VERSION 5.8 ;
BUSBITCHARS "[]" ;
DIVIDERCHAR "/" ;
UNITS
    DATABASE MICRONS 1000 ;
END UNITS

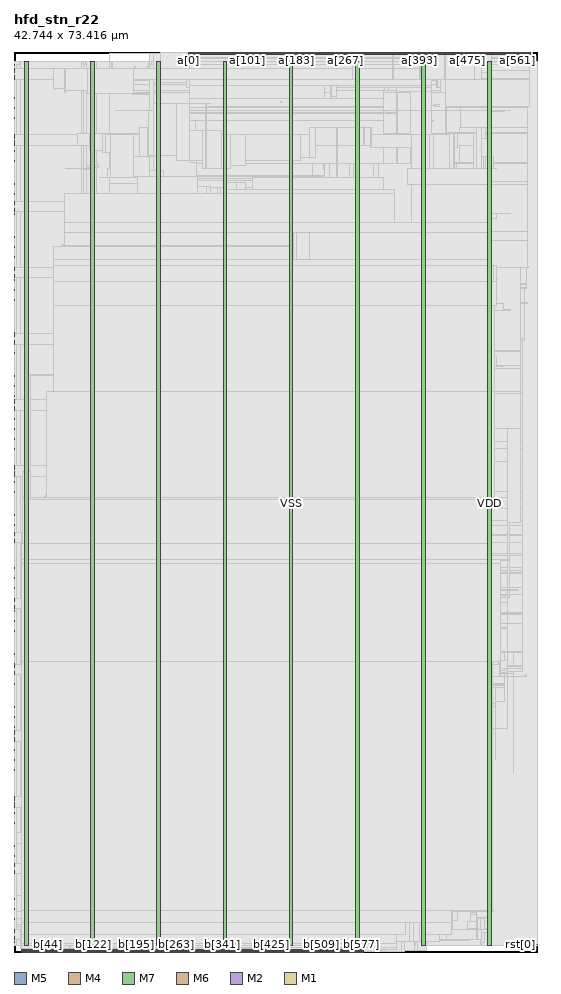
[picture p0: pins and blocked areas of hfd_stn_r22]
MACRO hfd_stn_r22
  FOREIGN hfd_stn_r22 0 0 ;
  CLASS BLOCK ;
  SIZE 42.744 BY 73.416 ;
  PIN a[0]
    DIRECTION INPUT ;
    USE SIGNAL ;
    PORT
      LAYER M5 ;
        RECT  14.208 73.224 14.232 73.416 ;
    END
  END a[0]
  PIN a[100]
    DIRECTION INPUT ;
    USE SIGNAL ;
    PORT
      LAYER M5 ;
        RECT  19.008 73.224 19.032 73.416 ;
    END
  END a[100]
  PIN a[101]
    DIRECTION INPUT ;
    USE SIGNAL ;
    PORT
      LAYER M5 ;
        RECT  19.056 73.224 19.08 73.416 ;
    END
  END a[101]
  PIN a[102]
    DIRECTION INPUT ;
    USE SIGNAL ;
    PORT
      LAYER M5 ;
        RECT  19.104 73.224 19.128 73.416 ;
    END
  END a[102]
  PIN a[103]
    DIRECTION INPUT ;
    USE SIGNAL ;
    PORT
      LAYER M5 ;
        RECT  19.152 73.224 19.176 73.416 ;
    END
  END a[103]
  PIN a[104]
    DIRECTION INPUT ;
    USE SIGNAL ;
    PORT
      LAYER M5 ;
        RECT  19.2 73.224 19.224 73.416 ;
    END
  END a[104]
  PIN a[105]
    DIRECTION INPUT ;
    USE SIGNAL ;
    PORT
      LAYER M5 ;
        RECT  19.248 73.224 19.272 73.416 ;
    END
  END a[105]
  PIN a[106]
    DIRECTION INPUT ;
    USE SIGNAL ;
    PORT
      LAYER M5 ;
        RECT  19.296 73.224 19.32 73.416 ;
    END
  END a[106]
  PIN a[107]
    DIRECTION INPUT ;
    USE SIGNAL ;
    PORT
      LAYER M5 ;
        RECT  19.344 73.224 19.368 73.416 ;
    END
  END a[107]
  PIN a[108]
    DIRECTION INPUT ;
    USE SIGNAL ;
    PORT
      LAYER M5 ;
        RECT  19.392 73.224 19.416 73.416 ;
    END
  END a[108]
  PIN a[109]
    DIRECTION INPUT ;
    USE SIGNAL ;
    PORT
      LAYER M5 ;
        RECT  19.44 73.224 19.464 73.416 ;
    END
  END a[109]
  PIN a[10]
    DIRECTION INPUT ;
    USE SIGNAL ;
    PORT
      LAYER M5 ;
        RECT  14.688 73.224 14.712 73.416 ;
    END
  END a[10]
  PIN a[110]
    DIRECTION INPUT ;
    USE SIGNAL ;
    PORT
      LAYER M5 ;
        RECT  19.488 73.224 19.512 73.416 ;
    END
  END a[110]
  PIN a[111]
    DIRECTION INPUT ;
    USE SIGNAL ;
    PORT
      LAYER M5 ;
        RECT  19.536 73.224 19.56 73.416 ;
    END
  END a[111]
  PIN a[112]
    DIRECTION INPUT ;
    USE SIGNAL ;
    PORT
      LAYER M5 ;
        RECT  19.584 73.224 19.608 73.416 ;
    END
  END a[112]
  PIN a[113]
    DIRECTION INPUT ;
    USE SIGNAL ;
    PORT
      LAYER M5 ;
        RECT  19.632 73.224 19.656 73.416 ;
    END
  END a[113]
  PIN a[114]
    DIRECTION INPUT ;
    USE SIGNAL ;
    PORT
      LAYER M5 ;
        RECT  19.68 73.224 19.704 73.416 ;
    END
  END a[114]
  PIN a[115]
    DIRECTION INPUT ;
    USE SIGNAL ;
    PORT
      LAYER M5 ;
        RECT  19.728 73.224 19.752 73.416 ;
    END
  END a[115]
  PIN a[116]
    DIRECTION INPUT ;
    USE SIGNAL ;
    PORT
      LAYER M5 ;
        RECT  19.776 73.224 19.8 73.416 ;
    END
  END a[116]
  PIN a[117]
    DIRECTION INPUT ;
    USE SIGNAL ;
    PORT
      LAYER M5 ;
        RECT  19.824 73.224 19.848 73.416 ;
    END
  END a[117]
  PIN a[118]
    DIRECTION INPUT ;
    USE SIGNAL ;
    PORT
      LAYER M5 ;
        RECT  19.872 73.224 19.896 73.416 ;
    END
  END a[118]
  PIN a[119]
    DIRECTION INPUT ;
    USE SIGNAL ;
    PORT
      LAYER M5 ;
        RECT  19.92 73.224 19.944 73.416 ;
    END
  END a[119]
  PIN a[11]
    DIRECTION INPUT ;
    USE SIGNAL ;
    PORT
      LAYER M5 ;
        RECT  14.736 73.224 14.76 73.416 ;
    END
  END a[11]
  PIN a[120]
    DIRECTION INPUT ;
    USE SIGNAL ;
    PORT
      LAYER M5 ;
        RECT  19.968 73.224 19.992 73.416 ;
    END
  END a[120]
  PIN a[121]
    DIRECTION INPUT ;
    USE SIGNAL ;
    PORT
      LAYER M5 ;
        RECT  20.016 73.224 20.04 73.416 ;
    END
  END a[121]
  PIN a[122]
    DIRECTION INPUT ;
    USE SIGNAL ;
    PORT
      LAYER M5 ;
        RECT  20.064 73.224 20.088 73.416 ;
    END
  END a[122]
  PIN a[123]
    DIRECTION INPUT ;
    USE SIGNAL ;
    PORT
      LAYER M5 ;
        RECT  20.112 73.224 20.136 73.416 ;
    END
  END a[123]
  PIN a[124]
    DIRECTION INPUT ;
    USE SIGNAL ;
    PORT
      LAYER M5 ;
        RECT  20.16 73.224 20.184 73.416 ;
    END
  END a[124]
  PIN a[125]
    DIRECTION INPUT ;
    USE SIGNAL ;
    PORT
      LAYER M5 ;
        RECT  20.208 73.224 20.232 73.416 ;
    END
  END a[125]
  PIN a[126]
    DIRECTION INPUT ;
    USE SIGNAL ;
    PORT
      LAYER M5 ;
        RECT  20.256 73.224 20.28 73.416 ;
    END
  END a[126]
  PIN a[127]
    DIRECTION INPUT ;
    USE SIGNAL ;
    PORT
      LAYER M5 ;
        RECT  20.304 73.224 20.328 73.416 ;
    END
  END a[127]
  PIN a[128]
    DIRECTION INPUT ;
    USE SIGNAL ;
    PORT
      LAYER M5 ;
        RECT  20.352 73.224 20.376 73.416 ;
    END
  END a[128]
  PIN a[129]
    DIRECTION INPUT ;
    USE SIGNAL ;
    PORT
      LAYER M5 ;
        RECT  20.4 73.224 20.424 73.416 ;
    END
  END a[129]
  PIN a[12]
    DIRECTION INPUT ;
    USE SIGNAL ;
    PORT
      LAYER M5 ;
        RECT  14.784 73.224 14.808 73.416 ;
    END
  END a[12]
  PIN a[130]
    DIRECTION INPUT ;
    USE SIGNAL ;
    PORT
      LAYER M5 ;
        RECT  20.448 73.224 20.472 73.416 ;
    END
  END a[130]
  PIN a[131]
    DIRECTION INPUT ;
    USE SIGNAL ;
    PORT
      LAYER M5 ;
        RECT  20.496 73.224 20.52 73.416 ;
    END
  END a[131]
  PIN a[132]
    DIRECTION INPUT ;
    USE SIGNAL ;
    PORT
      LAYER M5 ;
        RECT  20.544 73.224 20.568 73.416 ;
    END
  END a[132]
  PIN a[133]
    DIRECTION INPUT ;
    USE SIGNAL ;
    PORT
      LAYER M5 ;
        RECT  20.592 73.224 20.616 73.416 ;
    END
  END a[133]
  PIN a[134]
    DIRECTION INPUT ;
    USE SIGNAL ;
    PORT
      LAYER M5 ;
        RECT  20.64 73.224 20.664 73.416 ;
    END
  END a[134]
  PIN a[135]
    DIRECTION INPUT ;
    USE SIGNAL ;
    PORT
      LAYER M5 ;
        RECT  20.688 73.224 20.712 73.416 ;
    END
  END a[135]
  PIN a[136]
    DIRECTION INPUT ;
    USE SIGNAL ;
    PORT
      LAYER M5 ;
        RECT  20.736 73.224 20.76 73.416 ;
    END
  END a[136]
  PIN a[137]
    DIRECTION INPUT ;
    USE SIGNAL ;
    PORT
      LAYER M5 ;
        RECT  20.784 73.224 20.808 73.416 ;
    END
  END a[137]
  PIN a[138]
    DIRECTION INPUT ;
    USE SIGNAL ;
    PORT
      LAYER M5 ;
        RECT  20.832 73.224 20.856 73.416 ;
    END
  END a[138]
  PIN a[139]
    DIRECTION INPUT ;
    USE SIGNAL ;
    PORT
      LAYER M5 ;
        RECT  20.88 73.224 20.904 73.416 ;
    END
  END a[139]
  PIN a[13]
    DIRECTION INPUT ;
    USE SIGNAL ;
    PORT
      LAYER M5 ;
        RECT  14.832 73.224 14.856 73.416 ;
    END
  END a[13]
  PIN a[140]
    DIRECTION INPUT ;
    USE SIGNAL ;
    PORT
      LAYER M5 ;
        RECT  20.928 73.224 20.952 73.416 ;
    END
  END a[140]
  PIN a[141]
    DIRECTION INPUT ;
    USE SIGNAL ;
    PORT
      LAYER M5 ;
        RECT  20.976 73.224 21 73.416 ;
    END
  END a[141]
  PIN a[142]
    DIRECTION INPUT ;
    USE SIGNAL ;
    PORT
      LAYER M5 ;
        RECT  21.024 73.224 21.048 73.416 ;
    END
  END a[142]
  PIN a[143]
    DIRECTION INPUT ;
    USE SIGNAL ;
    PORT
      LAYER M5 ;
        RECT  21.072 73.224 21.096 73.416 ;
    END
  END a[143]
  PIN a[144]
    DIRECTION INPUT ;
    USE SIGNAL ;
    PORT
      LAYER M5 ;
        RECT  21.12 73.224 21.144 73.416 ;
    END
  END a[144]
  PIN a[145]
    DIRECTION INPUT ;
    USE SIGNAL ;
    PORT
      LAYER M5 ;
        RECT  21.168 73.224 21.192 73.416 ;
    END
  END a[145]
  PIN a[146]
    DIRECTION INPUT ;
    USE SIGNAL ;
    PORT
      LAYER M5 ;
        RECT  21.216 73.224 21.24 73.416 ;
    END
  END a[146]
  PIN a[147]
    DIRECTION INPUT ;
    USE SIGNAL ;
    PORT
      LAYER M5 ;
        RECT  21.264 73.224 21.288 73.416 ;
    END
  END a[147]
  PIN a[148]
    DIRECTION INPUT ;
    USE SIGNAL ;
    PORT
      LAYER M5 ;
        RECT  21.312 73.224 21.336 73.416 ;
    END
  END a[148]
  PIN a[149]
    DIRECTION INPUT ;
    USE SIGNAL ;
    PORT
      LAYER M5 ;
        RECT  21.36 73.224 21.384 73.416 ;
    END
  END a[149]
  PIN a[14]
    DIRECTION INPUT ;
    USE SIGNAL ;
    PORT
      LAYER M5 ;
        RECT  14.88 73.224 14.904 73.416 ;
    END
  END a[14]
  PIN a[150]
    DIRECTION INPUT ;
    USE SIGNAL ;
    PORT
      LAYER M5 ;
        RECT  21.408 73.224 21.432 73.416 ;
    END
  END a[150]
  PIN a[151]
    DIRECTION INPUT ;
    USE SIGNAL ;
    PORT
      LAYER M5 ;
        RECT  21.456 73.224 21.48 73.416 ;
    END
  END a[151]
  PIN a[152]
    DIRECTION INPUT ;
    USE SIGNAL ;
    PORT
      LAYER M5 ;
        RECT  21.504 73.224 21.528 73.416 ;
    END
  END a[152]
  PIN a[153]
    DIRECTION INPUT ;
    USE SIGNAL ;
    PORT
      LAYER M5 ;
        RECT  21.552 73.224 21.576 73.416 ;
    END
  END a[153]
  PIN a[154]
    DIRECTION INPUT ;
    USE SIGNAL ;
    PORT
      LAYER M5 ;
        RECT  21.6 73.224 21.624 73.416 ;
    END
  END a[154]
  PIN a[155]
    DIRECTION INPUT ;
    USE SIGNAL ;
    PORT
      LAYER M5 ;
        RECT  21.648 73.224 21.672 73.416 ;
    END
  END a[155]
  PIN a[156]
    DIRECTION INPUT ;
    USE SIGNAL ;
    PORT
      LAYER M5 ;
        RECT  21.696 73.224 21.72 73.416 ;
    END
  END a[156]
  PIN a[157]
    DIRECTION INPUT ;
    USE SIGNAL ;
    PORT
      LAYER M5 ;
        RECT  21.744 73.224 21.768 73.416 ;
    END
  END a[157]
  PIN a[158]
    DIRECTION INPUT ;
    USE SIGNAL ;
    PORT
      LAYER M5 ;
        RECT  21.792 73.224 21.816 73.416 ;
    END
  END a[158]
  PIN a[159]
    DIRECTION INPUT ;
    USE SIGNAL ;
    PORT
      LAYER M5 ;
        RECT  21.84 73.224 21.864 73.416 ;
    END
  END a[159]
  PIN a[15]
    DIRECTION INPUT ;
    USE SIGNAL ;
    PORT
      LAYER M5 ;
        RECT  14.928 73.224 14.952 73.416 ;
    END
  END a[15]
  PIN a[160]
    DIRECTION INPUT ;
    USE SIGNAL ;
    PORT
      LAYER M5 ;
        RECT  21.888 73.224 21.912 73.416 ;
    END
  END a[160]
  PIN a[161]
    DIRECTION INPUT ;
    USE SIGNAL ;
    PORT
      LAYER M5 ;
        RECT  21.936 73.224 21.96 73.416 ;
    END
  END a[161]
  PIN a[162]
    DIRECTION INPUT ;
    USE SIGNAL ;
    PORT
      LAYER M5 ;
        RECT  21.984 73.224 22.008 73.416 ;
    END
  END a[162]
  PIN a[163]
    DIRECTION INPUT ;
    USE SIGNAL ;
    PORT
      LAYER M5 ;
        RECT  22.032 73.224 22.056 73.416 ;
    END
  END a[163]
  PIN a[164]
    DIRECTION INPUT ;
    USE SIGNAL ;
    PORT
      LAYER M5 ;
        RECT  22.08 73.224 22.104 73.416 ;
    END
  END a[164]
  PIN a[165]
    DIRECTION INPUT ;
    USE SIGNAL ;
    PORT
      LAYER M5 ;
        RECT  22.128 73.224 22.152 73.416 ;
    END
  END a[165]
  PIN a[166]
    DIRECTION INPUT ;
    USE SIGNAL ;
    PORT
      LAYER M5 ;
        RECT  22.176 73.224 22.2 73.416 ;
    END
  END a[166]
  PIN a[167]
    DIRECTION INPUT ;
    USE SIGNAL ;
    PORT
      LAYER M5 ;
        RECT  22.224 73.224 22.248 73.416 ;
    END
  END a[167]
  PIN a[168]
    DIRECTION INPUT ;
    USE SIGNAL ;
    PORT
      LAYER M5 ;
        RECT  22.272 73.224 22.296 73.416 ;
    END
  END a[168]
  PIN a[169]
    DIRECTION INPUT ;
    USE SIGNAL ;
    PORT
      LAYER M5 ;
        RECT  22.32 73.224 22.344 73.416 ;
    END
  END a[169]
  PIN a[16]
    DIRECTION INPUT ;
    USE SIGNAL ;
    PORT
      LAYER M5 ;
        RECT  14.976 73.224 15 73.416 ;
    END
  END a[16]
  PIN a[170]
    DIRECTION INPUT ;
    USE SIGNAL ;
    PORT
      LAYER M5 ;
        RECT  22.368 73.224 22.392 73.416 ;
    END
  END a[170]
  PIN a[171]
    DIRECTION INPUT ;
    USE SIGNAL ;
    PORT
      LAYER M5 ;
        RECT  22.416 73.224 22.44 73.416 ;
    END
  END a[171]
  PIN a[172]
    DIRECTION INPUT ;
    USE SIGNAL ;
    PORT
      LAYER M5 ;
        RECT  22.464 73.224 22.488 73.416 ;
    END
  END a[172]
  PIN a[173]
    DIRECTION INPUT ;
    USE SIGNAL ;
    PORT
      LAYER M5 ;
        RECT  22.512 73.224 22.536 73.416 ;
    END
  END a[173]
  PIN a[174]
    DIRECTION INPUT ;
    USE SIGNAL ;
    PORT
      LAYER M5 ;
        RECT  22.56 73.224 22.584 73.416 ;
    END
  END a[174]
  PIN a[175]
    DIRECTION INPUT ;
    USE SIGNAL ;
    PORT
      LAYER M5 ;
        RECT  22.608 73.224 22.632 73.416 ;
    END
  END a[175]
  PIN a[176]
    DIRECTION INPUT ;
    USE SIGNAL ;
    PORT
      LAYER M5 ;
        RECT  22.656 73.224 22.68 73.416 ;
    END
  END a[176]
  PIN a[177]
    DIRECTION INPUT ;
    USE SIGNAL ;
    PORT
      LAYER M5 ;
        RECT  22.704 73.224 22.728 73.416 ;
    END
  END a[177]
  PIN a[178]
    DIRECTION INPUT ;
    USE SIGNAL ;
    PORT
      LAYER M5 ;
        RECT  22.752 73.224 22.776 73.416 ;
    END
  END a[178]
  PIN a[179]
    DIRECTION INPUT ;
    USE SIGNAL ;
    PORT
      LAYER M5 ;
        RECT  22.8 73.224 22.824 73.416 ;
    END
  END a[179]
  PIN a[17]
    DIRECTION INPUT ;
    USE SIGNAL ;
    PORT
      LAYER M5 ;
        RECT  15.024 73.224 15.048 73.416 ;
    END
  END a[17]
  PIN a[180]
    DIRECTION INPUT ;
    USE SIGNAL ;
    PORT
      LAYER M5 ;
        RECT  22.848 73.224 22.872 73.416 ;
    END
  END a[180]
  PIN a[181]
    DIRECTION INPUT ;
    USE SIGNAL ;
    PORT
      LAYER M5 ;
        RECT  22.896 73.224 22.92 73.416 ;
    END
  END a[181]
  PIN a[182]
    DIRECTION INPUT ;
    USE SIGNAL ;
    PORT
      LAYER M5 ;
        RECT  22.944 73.224 22.968 73.416 ;
    END
  END a[182]
  PIN a[183]
    DIRECTION INPUT ;
    USE SIGNAL ;
    PORT
      LAYER M5 ;
        RECT  22.992 73.224 23.016 73.416 ;
    END
  END a[183]
  PIN a[184]
    DIRECTION INPUT ;
    USE SIGNAL ;
    PORT
      LAYER M5 ;
        RECT  23.04 73.224 23.064 73.416 ;
    END
  END a[184]
  PIN a[185]
    DIRECTION INPUT ;
    USE SIGNAL ;
    PORT
      LAYER M5 ;
        RECT  23.088 73.224 23.112 73.416 ;
    END
  END a[185]
  PIN a[186]
    DIRECTION INPUT ;
    USE SIGNAL ;
    PORT
      LAYER M5 ;
        RECT  23.136 73.224 23.16 73.416 ;
    END
  END a[186]
  PIN a[187]
    DIRECTION INPUT ;
    USE SIGNAL ;
    PORT
      LAYER M5 ;
        RECT  23.184 73.224 23.208 73.416 ;
    END
  END a[187]
  PIN a[188]
    DIRECTION INPUT ;
    USE SIGNAL ;
    PORT
      LAYER M5 ;
        RECT  23.232 73.224 23.256 73.416 ;
    END
  END a[188]
  PIN a[189]
    DIRECTION INPUT ;
    USE SIGNAL ;
    PORT
      LAYER M5 ;
        RECT  23.28 73.224 23.304 73.416 ;
    END
  END a[189]
  PIN a[18]
    DIRECTION INPUT ;
    USE SIGNAL ;
    PORT
      LAYER M5 ;
        RECT  15.072 73.224 15.096 73.416 ;
    END
  END a[18]
  PIN a[190]
    DIRECTION INPUT ;
    USE SIGNAL ;
    PORT
      LAYER M5 ;
        RECT  23.328 73.224 23.352 73.416 ;
    END
  END a[190]
  PIN a[191]
    DIRECTION INPUT ;
    USE SIGNAL ;
    PORT
      LAYER M5 ;
        RECT  23.376 73.224 23.4 73.416 ;
    END
  END a[191]
  PIN a[192]
    DIRECTION INPUT ;
    USE SIGNAL ;
    PORT
      LAYER M5 ;
        RECT  23.424 73.224 23.448 73.416 ;
    END
  END a[192]
  PIN a[193]
    DIRECTION INPUT ;
    USE SIGNAL ;
    PORT
      LAYER M5 ;
        RECT  23.472 73.224 23.496 73.416 ;
    END
  END a[193]
  PIN a[194]
    DIRECTION INPUT ;
    USE SIGNAL ;
    PORT
      LAYER M5 ;
        RECT  23.52 73.224 23.544 73.416 ;
    END
  END a[194]
  PIN a[195]
    DIRECTION INPUT ;
    USE SIGNAL ;
    PORT
      LAYER M5 ;
        RECT  23.568 73.224 23.592 73.416 ;
    END
  END a[195]
  PIN a[196]
    DIRECTION INPUT ;
    USE SIGNAL ;
    PORT
      LAYER M5 ;
        RECT  23.616 73.224 23.64 73.416 ;
    END
  END a[196]
  PIN a[197]
    DIRECTION INPUT ;
    USE SIGNAL ;
    PORT
      LAYER M5 ;
        RECT  23.664 73.224 23.688 73.416 ;
    END
  END a[197]
  PIN a[198]
    DIRECTION INPUT ;
    USE SIGNAL ;
    PORT
      LAYER M5 ;
        RECT  23.712 73.224 23.736 73.416 ;
    END
  END a[198]
  PIN a[199]
    DIRECTION INPUT ;
    USE SIGNAL ;
    PORT
      LAYER M5 ;
        RECT  23.76 73.224 23.784 73.416 ;
    END
  END a[199]
  PIN a[19]
    DIRECTION INPUT ;
    USE SIGNAL ;
    PORT
      LAYER M5 ;
        RECT  15.12 73.224 15.144 73.416 ;
    END
  END a[19]
  PIN a[1]
    DIRECTION INPUT ;
    USE SIGNAL ;
    PORT
      LAYER M5 ;
        RECT  14.256 73.224 14.28 73.416 ;
    END
  END a[1]
  PIN a[200]
    DIRECTION INPUT ;
    USE SIGNAL ;
    PORT
      LAYER M5 ;
        RECT  23.808 73.224 23.832 73.416 ;
    END
  END a[200]
  PIN a[201]
    DIRECTION INPUT ;
    USE SIGNAL ;
    PORT
      LAYER M5 ;
        RECT  23.856 73.224 23.88 73.416 ;
    END
  END a[201]
  PIN a[202]
    DIRECTION INPUT ;
    USE SIGNAL ;
    PORT
      LAYER M5 ;
        RECT  23.904 73.224 23.928 73.416 ;
    END
  END a[202]
  PIN a[203]
    DIRECTION INPUT ;
    USE SIGNAL ;
    PORT
      LAYER M5 ;
        RECT  23.952 73.224 23.976 73.416 ;
    END
  END a[203]
  PIN a[204]
    DIRECTION INPUT ;
    USE SIGNAL ;
    PORT
      LAYER M5 ;
        RECT  24 73.224 24.024 73.416 ;
    END
  END a[204]
  PIN a[205]
    DIRECTION INPUT ;
    USE SIGNAL ;
    PORT
      LAYER M5 ;
        RECT  24.048 73.224 24.072 73.416 ;
    END
  END a[205]
  PIN a[206]
    DIRECTION INPUT ;
    USE SIGNAL ;
    PORT
      LAYER M5 ;
        RECT  24.096 73.224 24.12 73.416 ;
    END
  END a[206]
  PIN a[207]
    DIRECTION INPUT ;
    USE SIGNAL ;
    PORT
      LAYER M5 ;
        RECT  24.144 73.224 24.168 73.416 ;
    END
  END a[207]
  PIN a[208]
    DIRECTION INPUT ;
    USE SIGNAL ;
    PORT
      LAYER M5 ;
        RECT  24.192 73.224 24.216 73.416 ;
    END
  END a[208]
  PIN a[209]
    DIRECTION INPUT ;
    USE SIGNAL ;
    PORT
      LAYER M5 ;
        RECT  24.24 73.224 24.264 73.416 ;
    END
  END a[209]
  PIN a[20]
    DIRECTION INPUT ;
    USE SIGNAL ;
    PORT
      LAYER M5 ;
        RECT  15.168 73.224 15.192 73.416 ;
    END
  END a[20]
  PIN a[210]
    DIRECTION INPUT ;
    USE SIGNAL ;
    PORT
      LAYER M5 ;
        RECT  24.288 73.224 24.312 73.416 ;
    END
  END a[210]
  PIN a[211]
    DIRECTION INPUT ;
    USE SIGNAL ;
    PORT
      LAYER M5 ;
        RECT  24.336 73.224 24.36 73.416 ;
    END
  END a[211]
  PIN a[212]
    DIRECTION INPUT ;
    USE SIGNAL ;
    PORT
      LAYER M5 ;
        RECT  24.384 73.224 24.408 73.416 ;
    END
  END a[212]
  PIN a[213]
    DIRECTION INPUT ;
    USE SIGNAL ;
    PORT
      LAYER M5 ;
        RECT  24.432 73.224 24.456 73.416 ;
    END
  END a[213]
  PIN a[214]
    DIRECTION INPUT ;
    USE SIGNAL ;
    PORT
      LAYER M5 ;
        RECT  24.48 73.224 24.504 73.416 ;
    END
  END a[214]
  PIN a[215]
    DIRECTION INPUT ;
    USE SIGNAL ;
    PORT
      LAYER M5 ;
        RECT  24.528 73.224 24.552 73.416 ;
    END
  END a[215]
  PIN a[216]
    DIRECTION INPUT ;
    USE SIGNAL ;
    PORT
      LAYER M5 ;
        RECT  24.576 73.224 24.6 73.416 ;
    END
  END a[216]
  PIN a[217]
    DIRECTION INPUT ;
    USE SIGNAL ;
    PORT
      LAYER M5 ;
        RECT  24.624 73.224 24.648 73.416 ;
    END
  END a[217]
  PIN a[218]
    DIRECTION INPUT ;
    USE SIGNAL ;
    PORT
      LAYER M5 ;
        RECT  24.672 73.224 24.696 73.416 ;
    END
  END a[218]
  PIN a[219]
    DIRECTION INPUT ;
    USE SIGNAL ;
    PORT
      LAYER M5 ;
        RECT  24.72 73.224 24.744 73.416 ;
    END
  END a[219]
  PIN a[21]
    DIRECTION INPUT ;
    USE SIGNAL ;
    PORT
      LAYER M5 ;
        RECT  15.216 73.224 15.24 73.416 ;
    END
  END a[21]
  PIN a[220]
    DIRECTION INPUT ;
    USE SIGNAL ;
    PORT
      LAYER M5 ;
        RECT  24.768 73.224 24.792 73.416 ;
    END
  END a[220]
  PIN a[221]
    DIRECTION INPUT ;
    USE SIGNAL ;
    PORT
      LAYER M5 ;
        RECT  24.816 73.224 24.84 73.416 ;
    END
  END a[221]
  PIN a[222]
    DIRECTION INPUT ;
    USE SIGNAL ;
    PORT
      LAYER M5 ;
        RECT  24.864 73.224 24.888 73.416 ;
    END
  END a[222]
  PIN a[223]
    DIRECTION INPUT ;
    USE SIGNAL ;
    PORT
      LAYER M5 ;
        RECT  24.912 73.224 24.936 73.416 ;
    END
  END a[223]
  PIN a[224]
    DIRECTION INPUT ;
    USE SIGNAL ;
    PORT
      LAYER M5 ;
        RECT  24.96 73.224 24.984 73.416 ;
    END
  END a[224]
  PIN a[225]
    DIRECTION INPUT ;
    USE SIGNAL ;
    PORT
      LAYER M5 ;
        RECT  25.008 73.224 25.032 73.416 ;
    END
  END a[225]
  PIN a[226]
    DIRECTION INPUT ;
    USE SIGNAL ;
    PORT
      LAYER M5 ;
        RECT  25.056 73.224 25.08 73.416 ;
    END
  END a[226]
  PIN a[227]
    DIRECTION INPUT ;
    USE SIGNAL ;
    PORT
      LAYER M5 ;
        RECT  25.104 73.224 25.128 73.416 ;
    END
  END a[227]
  PIN a[228]
    DIRECTION INPUT ;
    USE SIGNAL ;
    PORT
      LAYER M5 ;
        RECT  25.152 73.224 25.176 73.416 ;
    END
  END a[228]
  PIN a[229]
    DIRECTION INPUT ;
    USE SIGNAL ;
    PORT
      LAYER M5 ;
        RECT  25.2 73.224 25.224 73.416 ;
    END
  END a[229]
  PIN a[22]
    DIRECTION INPUT ;
    USE SIGNAL ;
    PORT
      LAYER M5 ;
        RECT  15.264 73.224 15.288 73.416 ;
    END
  END a[22]
  PIN a[230]
    DIRECTION INPUT ;
    USE SIGNAL ;
    PORT
      LAYER M5 ;
        RECT  25.248 73.224 25.272 73.416 ;
    END
  END a[230]
  PIN a[231]
    DIRECTION INPUT ;
    USE SIGNAL ;
    PORT
      LAYER M5 ;
        RECT  25.296 73.224 25.32 73.416 ;
    END
  END a[231]
  PIN a[232]
    DIRECTION INPUT ;
    USE SIGNAL ;
    PORT
      LAYER M5 ;
        RECT  25.344 73.224 25.368 73.416 ;
    END
  END a[232]
  PIN a[233]
    DIRECTION INPUT ;
    USE SIGNAL ;
    PORT
      LAYER M5 ;
        RECT  25.392 73.224 25.416 73.416 ;
    END
  END a[233]
  PIN a[234]
    DIRECTION INPUT ;
    USE SIGNAL ;
    PORT
      LAYER M5 ;
        RECT  25.44 73.224 25.464 73.416 ;
    END
  END a[234]
  PIN a[235]
    DIRECTION INPUT ;
    USE SIGNAL ;
    PORT
      LAYER M5 ;
        RECT  25.488 73.224 25.512 73.416 ;
    END
  END a[235]
  PIN a[236]
    DIRECTION INPUT ;
    USE SIGNAL ;
    PORT
      LAYER M5 ;
        RECT  25.536 73.224 25.56 73.416 ;
    END
  END a[236]
  PIN a[237]
    DIRECTION INPUT ;
    USE SIGNAL ;
    PORT
      LAYER M5 ;
        RECT  25.584 73.224 25.608 73.416 ;
    END
  END a[237]
  PIN a[238]
    DIRECTION INPUT ;
    USE SIGNAL ;
    PORT
      LAYER M5 ;
        RECT  25.632 73.224 25.656 73.416 ;
    END
  END a[238]
  PIN a[239]
    DIRECTION INPUT ;
    USE SIGNAL ;
    PORT
      LAYER M5 ;
        RECT  25.68 73.224 25.704 73.416 ;
    END
  END a[239]
  PIN a[23]
    DIRECTION INPUT ;
    USE SIGNAL ;
    PORT
      LAYER M5 ;
        RECT  15.312 73.224 15.336 73.416 ;
    END
  END a[23]
  PIN a[240]
    DIRECTION INPUT ;
    USE SIGNAL ;
    PORT
      LAYER M5 ;
        RECT  25.728 73.224 25.752 73.416 ;
    END
  END a[240]
  PIN a[241]
    DIRECTION INPUT ;
    USE SIGNAL ;
    PORT
      LAYER M5 ;
        RECT  25.776 73.224 25.8 73.416 ;
    END
  END a[241]
  PIN a[242]
    DIRECTION INPUT ;
    USE SIGNAL ;
    PORT
      LAYER M5 ;
        RECT  25.824 73.224 25.848 73.416 ;
    END
  END a[242]
  PIN a[243]
    DIRECTION INPUT ;
    USE SIGNAL ;
    PORT
      LAYER M5 ;
        RECT  25.872 73.224 25.896 73.416 ;
    END
  END a[243]
  PIN a[244]
    DIRECTION INPUT ;
    USE SIGNAL ;
    PORT
      LAYER M5 ;
        RECT  25.92 73.224 25.944 73.416 ;
    END
  END a[244]
  PIN a[245]
    DIRECTION INPUT ;
    USE SIGNAL ;
    PORT
      LAYER M5 ;
        RECT  25.968 73.224 25.992 73.416 ;
    END
  END a[245]
  PIN a[246]
    DIRECTION INPUT ;
    USE SIGNAL ;
    PORT
      LAYER M5 ;
        RECT  26.016 73.224 26.04 73.416 ;
    END
  END a[246]
  PIN a[247]
    DIRECTION INPUT ;
    USE SIGNAL ;
    PORT
      LAYER M5 ;
        RECT  26.064 73.224 26.088 73.416 ;
    END
  END a[247]
  PIN a[248]
    DIRECTION INPUT ;
    USE SIGNAL ;
    PORT
      LAYER M5 ;
        RECT  26.112 73.224 26.136 73.416 ;
    END
  END a[248]
  PIN a[249]
    DIRECTION INPUT ;
    USE SIGNAL ;
    PORT
      LAYER M5 ;
        RECT  26.16 73.224 26.184 73.416 ;
    END
  END a[249]
  PIN a[24]
    DIRECTION INPUT ;
    USE SIGNAL ;
    PORT
      LAYER M5 ;
        RECT  15.36 73.224 15.384 73.416 ;
    END
  END a[24]
  PIN a[250]
    DIRECTION INPUT ;
    USE SIGNAL ;
    PORT
      LAYER M5 ;
        RECT  26.208 73.224 26.232 73.416 ;
    END
  END a[250]
  PIN a[251]
    DIRECTION INPUT ;
    USE SIGNAL ;
    PORT
      LAYER M5 ;
        RECT  26.256 73.224 26.28 73.416 ;
    END
  END a[251]
  PIN a[252]
    DIRECTION INPUT ;
    USE SIGNAL ;
    PORT
      LAYER M5 ;
        RECT  26.304 73.224 26.328 73.416 ;
    END
  END a[252]
  PIN a[253]
    DIRECTION INPUT ;
    USE SIGNAL ;
    PORT
      LAYER M5 ;
        RECT  26.352 73.224 26.376 73.416 ;
    END
  END a[253]
  PIN a[254]
    DIRECTION INPUT ;
    USE SIGNAL ;
    PORT
      LAYER M5 ;
        RECT  26.4 73.224 26.424 73.416 ;
    END
  END a[254]
  PIN a[255]
    DIRECTION INPUT ;
    USE SIGNAL ;
    PORT
      LAYER M5 ;
        RECT  26.448 73.224 26.472 73.416 ;
    END
  END a[255]
  PIN a[256]
    DIRECTION INPUT ;
    USE SIGNAL ;
    PORT
      LAYER M5 ;
        RECT  26.496 73.224 26.52 73.416 ;
    END
  END a[256]
  PIN a[257]
    DIRECTION INPUT ;
    USE SIGNAL ;
    PORT
      LAYER M5 ;
        RECT  26.544 73.224 26.568 73.416 ;
    END
  END a[257]
  PIN a[258]
    DIRECTION INPUT ;
    USE SIGNAL ;
    PORT
      LAYER M5 ;
        RECT  26.592 73.224 26.616 73.416 ;
    END
  END a[258]
  PIN a[259]
    DIRECTION INPUT ;
    USE SIGNAL ;
    PORT
      LAYER M5 ;
        RECT  26.64 73.224 26.664 73.416 ;
    END
  END a[259]
  PIN a[25]
    DIRECTION INPUT ;
    USE SIGNAL ;
    PORT
      LAYER M5 ;
        RECT  15.408 73.224 15.432 73.416 ;
    END
  END a[25]
  PIN a[260]
    DIRECTION INPUT ;
    USE SIGNAL ;
    PORT
      LAYER M5 ;
        RECT  26.688 73.224 26.712 73.416 ;
    END
  END a[260]
  PIN a[261]
    DIRECTION INPUT ;
    USE SIGNAL ;
    PORT
      LAYER M5 ;
        RECT  26.736 73.224 26.76 73.416 ;
    END
  END a[261]
  PIN a[262]
    DIRECTION INPUT ;
    USE SIGNAL ;
    PORT
      LAYER M5 ;
        RECT  26.784 73.224 26.808 73.416 ;
    END
  END a[262]
  PIN a[263]
    DIRECTION INPUT ;
    USE SIGNAL ;
    PORT
      LAYER M5 ;
        RECT  26.832 73.224 26.856 73.416 ;
    END
  END a[263]
  PIN a[264]
    DIRECTION INPUT ;
    USE SIGNAL ;
    PORT
      LAYER M5 ;
        RECT  26.88 73.224 26.904 73.416 ;
    END
  END a[264]
  PIN a[265]
    DIRECTION INPUT ;
    USE SIGNAL ;
    PORT
      LAYER M5 ;
        RECT  26.928 73.224 26.952 73.416 ;
    END
  END a[265]
  PIN a[266]
    DIRECTION INPUT ;
    USE SIGNAL ;
    PORT
      LAYER M5 ;
        RECT  26.976 73.224 27 73.416 ;
    END
  END a[266]
  PIN a[267]
    DIRECTION INPUT ;
    USE SIGNAL ;
    PORT
      LAYER M5 ;
        RECT  27.024 73.224 27.048 73.416 ;
    END
  END a[267]
  PIN a[268]
    DIRECTION INPUT ;
    USE SIGNAL ;
    PORT
      LAYER M5 ;
        RECT  27.072 73.224 27.096 73.416 ;
    END
  END a[268]
  PIN a[269]
    DIRECTION INPUT ;
    USE SIGNAL ;
    PORT
      LAYER M5 ;
        RECT  27.12 73.224 27.144 73.416 ;
    END
  END a[269]
  PIN a[26]
    DIRECTION INPUT ;
    USE SIGNAL ;
    PORT
      LAYER M5 ;
        RECT  15.456 73.224 15.48 73.416 ;
    END
  END a[26]
  PIN a[270]
    DIRECTION INPUT ;
    USE SIGNAL ;
    PORT
      LAYER M5 ;
        RECT  27.168 73.224 27.192 73.416 ;
    END
  END a[270]
  PIN a[271]
    DIRECTION INPUT ;
    USE SIGNAL ;
    PORT
      LAYER M5 ;
        RECT  27.216 73.224 27.24 73.416 ;
    END
  END a[271]
  PIN a[272]
    DIRECTION INPUT ;
    USE SIGNAL ;
    PORT
      LAYER M5 ;
        RECT  27.264 73.224 27.288 73.416 ;
    END
  END a[272]
  PIN a[273]
    DIRECTION INPUT ;
    USE SIGNAL ;
    PORT
      LAYER M5 ;
        RECT  27.312 73.224 27.336 73.416 ;
    END
  END a[273]
  PIN a[274]
    DIRECTION INPUT ;
    USE SIGNAL ;
    PORT
      LAYER M5 ;
        RECT  27.36 73.224 27.384 73.416 ;
    END
  END a[274]
  PIN a[275]
    DIRECTION INPUT ;
    USE SIGNAL ;
    PORT
      LAYER M5 ;
        RECT  27.408 73.224 27.432 73.416 ;
    END
  END a[275]
  PIN a[276]
    DIRECTION INPUT ;
    USE SIGNAL ;
    PORT
      LAYER M5 ;
        RECT  27.456 73.224 27.48 73.416 ;
    END
  END a[276]
  PIN a[277]
    DIRECTION INPUT ;
    USE SIGNAL ;
    PORT
      LAYER M5 ;
        RECT  27.504 73.224 27.528 73.416 ;
    END
  END a[277]
  PIN a[278]
    DIRECTION INPUT ;
    USE SIGNAL ;
    PORT
      LAYER M5 ;
        RECT  27.552 73.224 27.576 73.416 ;
    END
  END a[278]
  PIN a[279]
    DIRECTION INPUT ;
    USE SIGNAL ;
    PORT
      LAYER M5 ;
        RECT  27.6 73.224 27.624 73.416 ;
    END
  END a[279]
  PIN a[27]
    DIRECTION INPUT ;
    USE SIGNAL ;
    PORT
      LAYER M5 ;
        RECT  15.504 73.224 15.528 73.416 ;
    END
  END a[27]
  PIN a[280]
    DIRECTION INPUT ;
    USE SIGNAL ;
    PORT
      LAYER M5 ;
        RECT  27.648 73.224 27.672 73.416 ;
    END
  END a[280]
  PIN a[281]
    DIRECTION INPUT ;
    USE SIGNAL ;
    PORT
      LAYER M5 ;
        RECT  27.696 73.224 27.72 73.416 ;
    END
  END a[281]
  PIN a[282]
    DIRECTION INPUT ;
    USE SIGNAL ;
    PORT
      LAYER M5 ;
        RECT  27.744 73.224 27.768 73.416 ;
    END
  END a[282]
  PIN a[283]
    DIRECTION INPUT ;
    USE SIGNAL ;
    PORT
      LAYER M5 ;
        RECT  27.792 73.224 27.816 73.416 ;
    END
  END a[283]
  PIN a[284]
    DIRECTION INPUT ;
    USE SIGNAL ;
    PORT
      LAYER M5 ;
        RECT  27.84 73.224 27.864 73.416 ;
    END
  END a[284]
  PIN a[285]
    DIRECTION INPUT ;
    USE SIGNAL ;
    PORT
      LAYER M5 ;
        RECT  27.888 73.224 27.912 73.416 ;
    END
  END a[285]
  PIN a[286]
    DIRECTION INPUT ;
    USE SIGNAL ;
    PORT
      LAYER M5 ;
        RECT  27.936 73.224 27.96 73.416 ;
    END
  END a[286]
  PIN a[287]
    DIRECTION INPUT ;
    USE SIGNAL ;
    PORT
      LAYER M5 ;
        RECT  27.984 73.224 28.008 73.416 ;
    END
  END a[287]
  PIN a[288]
    DIRECTION INPUT ;
    USE SIGNAL ;
    PORT
      LAYER M5 ;
        RECT  28.032 73.224 28.056 73.416 ;
    END
  END a[288]
  PIN a[289]
    DIRECTION INPUT ;
    USE SIGNAL ;
    PORT
      LAYER M5 ;
        RECT  28.08 73.224 28.104 73.416 ;
    END
  END a[289]
  PIN a[28]
    DIRECTION INPUT ;
    USE SIGNAL ;
    PORT
      LAYER M5 ;
        RECT  15.552 73.224 15.576 73.416 ;
    END
  END a[28]
  PIN a[290]
    DIRECTION INPUT ;
    USE SIGNAL ;
    PORT
      LAYER M5 ;
        RECT  28.128 73.224 28.152 73.416 ;
    END
  END a[290]
  PIN a[291]
    DIRECTION INPUT ;
    USE SIGNAL ;
    PORT
      LAYER M5 ;
        RECT  28.176 73.224 28.2 73.416 ;
    END
  END a[291]
  PIN a[292]
    DIRECTION INPUT ;
    USE SIGNAL ;
    PORT
      LAYER M5 ;
        RECT  28.224 73.224 28.248 73.416 ;
    END
  END a[292]
  PIN a[293]
    DIRECTION INPUT ;
    USE SIGNAL ;
    PORT
      LAYER M5 ;
        RECT  28.272 73.224 28.296 73.416 ;
    END
  END a[293]
  PIN a[294]
    DIRECTION INPUT ;
    USE SIGNAL ;
    PORT
      LAYER M5 ;
        RECT  28.32 73.224 28.344 73.416 ;
    END
  END a[294]
  PIN a[295]
    DIRECTION INPUT ;
    USE SIGNAL ;
    PORT
      LAYER M5 ;
        RECT  28.368 73.224 28.392 73.416 ;
    END
  END a[295]
  PIN a[296]
    DIRECTION INPUT ;
    USE SIGNAL ;
    PORT
      LAYER M5 ;
        RECT  28.416 73.224 28.44 73.416 ;
    END
  END a[296]
  PIN a[297]
    DIRECTION INPUT ;
    USE SIGNAL ;
    PORT
      LAYER M5 ;
        RECT  28.464 73.224 28.488 73.416 ;
    END
  END a[297]
  PIN a[298]
    DIRECTION INPUT ;
    USE SIGNAL ;
    PORT
      LAYER M5 ;
        RECT  28.512 73.224 28.536 73.416 ;
    END
  END a[298]
  PIN a[299]
    DIRECTION INPUT ;
    USE SIGNAL ;
    PORT
      LAYER M5 ;
        RECT  28.56 73.224 28.584 73.416 ;
    END
  END a[299]
  PIN a[29]
    DIRECTION INPUT ;
    USE SIGNAL ;
    PORT
      LAYER M5 ;
        RECT  15.6 73.224 15.624 73.416 ;
    END
  END a[29]
  PIN a[2]
    DIRECTION INPUT ;
    USE SIGNAL ;
    PORT
      LAYER M5 ;
        RECT  14.304 73.224 14.328 73.416 ;
    END
  END a[2]
  PIN a[300]
    DIRECTION INPUT ;
    USE SIGNAL ;
    PORT
      LAYER M5 ;
        RECT  28.608 73.224 28.632 73.416 ;
    END
  END a[300]
  PIN a[301]
    DIRECTION INPUT ;
    USE SIGNAL ;
    PORT
      LAYER M5 ;
        RECT  28.656 73.224 28.68 73.416 ;
    END
  END a[301]
  PIN a[302]
    DIRECTION INPUT ;
    USE SIGNAL ;
    PORT
      LAYER M5 ;
        RECT  28.704 73.224 28.728 73.416 ;
    END
  END a[302]
  PIN a[303]
    DIRECTION INPUT ;
    USE SIGNAL ;
    PORT
      LAYER M5 ;
        RECT  28.752 73.224 28.776 73.416 ;
    END
  END a[303]
  PIN a[304]
    DIRECTION INPUT ;
    USE SIGNAL ;
    PORT
      LAYER M5 ;
        RECT  28.8 73.224 28.824 73.416 ;
    END
  END a[304]
  PIN a[305]
    DIRECTION INPUT ;
    USE SIGNAL ;
    PORT
      LAYER M5 ;
        RECT  28.848 73.224 28.872 73.416 ;
    END
  END a[305]
  PIN a[306]
    DIRECTION INPUT ;
    USE SIGNAL ;
    PORT
      LAYER M5 ;
        RECT  28.896 73.224 28.92 73.416 ;
    END
  END a[306]
  PIN a[307]
    DIRECTION INPUT ;
    USE SIGNAL ;
    PORT
      LAYER M5 ;
        RECT  28.944 73.224 28.968 73.416 ;
    END
  END a[307]
  PIN a[308]
    DIRECTION INPUT ;
    USE SIGNAL ;
    PORT
      LAYER M5 ;
        RECT  28.992 73.224 29.016 73.416 ;
    END
  END a[308]
  PIN a[309]
    DIRECTION INPUT ;
    USE SIGNAL ;
    PORT
      LAYER M5 ;
        RECT  29.04 73.224 29.064 73.416 ;
    END
  END a[309]
  PIN a[30]
    DIRECTION INPUT ;
    USE SIGNAL ;
    PORT
      LAYER M5 ;
        RECT  15.648 73.224 15.672 73.416 ;
    END
  END a[30]
  PIN a[310]
    DIRECTION INPUT ;
    USE SIGNAL ;
    PORT
      LAYER M5 ;
        RECT  29.088 73.224 29.112 73.416 ;
    END
  END a[310]
  PIN a[311]
    DIRECTION INPUT ;
    USE SIGNAL ;
    PORT
      LAYER M5 ;
        RECT  29.136 73.224 29.16 73.416 ;
    END
  END a[311]
  PIN a[312]
    DIRECTION INPUT ;
    USE SIGNAL ;
    PORT
      LAYER M5 ;
        RECT  29.184 73.224 29.208 73.416 ;
    END
  END a[312]
  PIN a[313]
    DIRECTION INPUT ;
    USE SIGNAL ;
    PORT
      LAYER M5 ;
        RECT  29.232 73.224 29.256 73.416 ;
    END
  END a[313]
  PIN a[314]
    DIRECTION INPUT ;
    USE SIGNAL ;
    PORT
      LAYER M5 ;
        RECT  29.28 73.224 29.304 73.416 ;
    END
  END a[314]
  PIN a[315]
    DIRECTION INPUT ;
    USE SIGNAL ;
    PORT
      LAYER M5 ;
        RECT  29.328 73.224 29.352 73.416 ;
    END
  END a[315]
  PIN a[316]
    DIRECTION INPUT ;
    USE SIGNAL ;
    PORT
      LAYER M5 ;
        RECT  29.376 73.224 29.4 73.416 ;
    END
  END a[316]
  PIN a[317]
    DIRECTION INPUT ;
    USE SIGNAL ;
    PORT
      LAYER M5 ;
        RECT  29.424 73.224 29.448 73.416 ;
    END
  END a[317]
  PIN a[318]
    DIRECTION INPUT ;
    USE SIGNAL ;
    PORT
      LAYER M5 ;
        RECT  29.472 73.224 29.496 73.416 ;
    END
  END a[318]
  PIN a[319]
    DIRECTION INPUT ;
    USE SIGNAL ;
    PORT
      LAYER M5 ;
        RECT  29.52 73.224 29.544 73.416 ;
    END
  END a[319]
  PIN a[31]
    DIRECTION INPUT ;
    USE SIGNAL ;
    PORT
      LAYER M5 ;
        RECT  15.696 73.224 15.72 73.416 ;
    END
  END a[31]
  PIN a[320]
    DIRECTION INPUT ;
    USE SIGNAL ;
    PORT
      LAYER M5 ;
        RECT  29.568 73.224 29.592 73.416 ;
    END
  END a[320]
  PIN a[321]
    DIRECTION INPUT ;
    USE SIGNAL ;
    PORT
      LAYER M5 ;
        RECT  29.616 73.224 29.64 73.416 ;
    END
  END a[321]
  PIN a[322]
    DIRECTION INPUT ;
    USE SIGNAL ;
    PORT
      LAYER M5 ;
        RECT  29.664 73.224 29.688 73.416 ;
    END
  END a[322]
  PIN a[323]
    DIRECTION INPUT ;
    USE SIGNAL ;
    PORT
      LAYER M5 ;
        RECT  29.712 73.224 29.736 73.416 ;
    END
  END a[323]
  PIN a[324]
    DIRECTION INPUT ;
    USE SIGNAL ;
    PORT
      LAYER M5 ;
        RECT  29.76 73.224 29.784 73.416 ;
    END
  END a[324]
  PIN a[325]
    DIRECTION INPUT ;
    USE SIGNAL ;
    PORT
      LAYER M5 ;
        RECT  29.808 73.224 29.832 73.416 ;
    END
  END a[325]
  PIN a[326]
    DIRECTION INPUT ;
    USE SIGNAL ;
    PORT
      LAYER M5 ;
        RECT  29.856 73.224 29.88 73.416 ;
    END
  END a[326]
  PIN a[327]
    DIRECTION INPUT ;
    USE SIGNAL ;
    PORT
      LAYER M5 ;
        RECT  29.904 73.224 29.928 73.416 ;
    END
  END a[327]
  PIN a[328]
    DIRECTION INPUT ;
    USE SIGNAL ;
    PORT
      LAYER M5 ;
        RECT  29.952 73.224 29.976 73.416 ;
    END
  END a[328]
  PIN a[329]
    DIRECTION INPUT ;
    USE SIGNAL ;
    PORT
      LAYER M5 ;
        RECT  30 73.224 30.024 73.416 ;
    END
  END a[329]
  PIN a[32]
    DIRECTION INPUT ;
    USE SIGNAL ;
    PORT
      LAYER M5 ;
        RECT  15.744 73.224 15.768 73.416 ;
    END
  END a[32]
  PIN a[330]
    DIRECTION INPUT ;
    USE SIGNAL ;
    PORT
      LAYER M5 ;
        RECT  30.048 73.224 30.072 73.416 ;
    END
  END a[330]
  PIN a[331]
    DIRECTION INPUT ;
    USE SIGNAL ;
    PORT
      LAYER M5 ;
        RECT  30.096 73.224 30.12 73.416 ;
    END
  END a[331]
  PIN a[332]
    DIRECTION INPUT ;
    USE SIGNAL ;
    PORT
      LAYER M5 ;
        RECT  30.144 73.224 30.168 73.416 ;
    END
  END a[332]
  PIN a[333]
    DIRECTION INPUT ;
    USE SIGNAL ;
    PORT
      LAYER M5 ;
        RECT  30.192 73.224 30.216 73.416 ;
    END
  END a[333]
  PIN a[334]
    DIRECTION INPUT ;
    USE SIGNAL ;
    PORT
      LAYER M5 ;
        RECT  30.24 73.224 30.264 73.416 ;
    END
  END a[334]
  PIN a[335]
    DIRECTION INPUT ;
    USE SIGNAL ;
    PORT
      LAYER M5 ;
        RECT  30.288 73.224 30.312 73.416 ;
    END
  END a[335]
  PIN a[336]
    DIRECTION INPUT ;
    USE SIGNAL ;
    PORT
      LAYER M5 ;
        RECT  30.336 73.224 30.36 73.416 ;
    END
  END a[336]
  PIN a[337]
    DIRECTION INPUT ;
    USE SIGNAL ;
    PORT
      LAYER M5 ;
        RECT  30.384 73.224 30.408 73.416 ;
    END
  END a[337]
  PIN a[338]
    DIRECTION INPUT ;
    USE SIGNAL ;
    PORT
      LAYER M5 ;
        RECT  30.432 73.224 30.456 73.416 ;
    END
  END a[338]
  PIN a[339]
    DIRECTION INPUT ;
    USE SIGNAL ;
    PORT
      LAYER M5 ;
        RECT  30.48 73.224 30.504 73.416 ;
    END
  END a[339]
  PIN a[33]
    DIRECTION INPUT ;
    USE SIGNAL ;
    PORT
      LAYER M5 ;
        RECT  15.792 73.224 15.816 73.416 ;
    END
  END a[33]
  PIN a[340]
    DIRECTION INPUT ;
    USE SIGNAL ;
    PORT
      LAYER M5 ;
        RECT  30.528 73.224 30.552 73.416 ;
    END
  END a[340]
  PIN a[341]
    DIRECTION INPUT ;
    USE SIGNAL ;
    PORT
      LAYER M5 ;
        RECT  30.576 73.224 30.6 73.416 ;
    END
  END a[341]
  PIN a[342]
    DIRECTION INPUT ;
    USE SIGNAL ;
    PORT
      LAYER M5 ;
        RECT  30.624 73.224 30.648 73.416 ;
    END
  END a[342]
  PIN a[343]
    DIRECTION INPUT ;
    USE SIGNAL ;
    PORT
      LAYER M5 ;
        RECT  30.672 73.224 30.696 73.416 ;
    END
  END a[343]
  PIN a[344]
    DIRECTION INPUT ;
    USE SIGNAL ;
    PORT
      LAYER M5 ;
        RECT  30.72 73.224 30.744 73.416 ;
    END
  END a[344]
  PIN a[345]
    DIRECTION INPUT ;
    USE SIGNAL ;
    PORT
      LAYER M5 ;
        RECT  30.768 73.224 30.792 73.416 ;
    END
  END a[345]
  PIN a[346]
    DIRECTION INPUT ;
    USE SIGNAL ;
    PORT
      LAYER M5 ;
        RECT  30.816 73.224 30.84 73.416 ;
    END
  END a[346]
  PIN a[347]
    DIRECTION INPUT ;
    USE SIGNAL ;
    PORT
      LAYER M5 ;
        RECT  30.864 73.224 30.888 73.416 ;
    END
  END a[347]
  PIN a[348]
    DIRECTION INPUT ;
    USE SIGNAL ;
    PORT
      LAYER M5 ;
        RECT  30.912 73.224 30.936 73.416 ;
    END
  END a[348]
  PIN a[349]
    DIRECTION INPUT ;
    USE SIGNAL ;
    PORT
      LAYER M5 ;
        RECT  30.96 73.224 30.984 73.416 ;
    END
  END a[349]
  PIN a[34]
    DIRECTION INPUT ;
    USE SIGNAL ;
    PORT
      LAYER M5 ;
        RECT  15.84 73.224 15.864 73.416 ;
    END
  END a[34]
  PIN a[350]
    DIRECTION INPUT ;
    USE SIGNAL ;
    PORT
      LAYER M5 ;
        RECT  31.008 73.224 31.032 73.416 ;
    END
  END a[350]
  PIN a[351]
    DIRECTION INPUT ;
    USE SIGNAL ;
    PORT
      LAYER M5 ;
        RECT  31.056 73.224 31.08 73.416 ;
    END
  END a[351]
  PIN a[352]
    DIRECTION INPUT ;
    USE SIGNAL ;
    PORT
      LAYER M5 ;
        RECT  31.104 73.224 31.128 73.416 ;
    END
  END a[352]
  PIN a[353]
    DIRECTION INPUT ;
    USE SIGNAL ;
    PORT
      LAYER M5 ;
        RECT  31.152 73.224 31.176 73.416 ;
    END
  END a[353]
  PIN a[354]
    DIRECTION INPUT ;
    USE SIGNAL ;
    PORT
      LAYER M5 ;
        RECT  31.2 73.224 31.224 73.416 ;
    END
  END a[354]
  PIN a[355]
    DIRECTION INPUT ;
    USE SIGNAL ;
    PORT
      LAYER M5 ;
        RECT  31.248 73.224 31.272 73.416 ;
    END
  END a[355]
  PIN a[356]
    DIRECTION INPUT ;
    USE SIGNAL ;
    PORT
      LAYER M5 ;
        RECT  31.296 73.224 31.32 73.416 ;
    END
  END a[356]
  PIN a[357]
    DIRECTION INPUT ;
    USE SIGNAL ;
    PORT
      LAYER M5 ;
        RECT  31.344 73.224 31.368 73.416 ;
    END
  END a[357]
  PIN a[358]
    DIRECTION INPUT ;
    USE SIGNAL ;
    PORT
      LAYER M5 ;
        RECT  31.392 73.224 31.416 73.416 ;
    END
  END a[358]
  PIN a[359]
    DIRECTION INPUT ;
    USE SIGNAL ;
    PORT
      LAYER M5 ;
        RECT  31.44 73.224 31.464 73.416 ;
    END
  END a[359]
  PIN a[35]
    DIRECTION INPUT ;
    USE SIGNAL ;
    PORT
      LAYER M5 ;
        RECT  15.888 73.224 15.912 73.416 ;
    END
  END a[35]
  PIN a[360]
    DIRECTION INPUT ;
    USE SIGNAL ;
    PORT
      LAYER M5 ;
        RECT  31.488 73.224 31.512 73.416 ;
    END
  END a[360]
  PIN a[361]
    DIRECTION INPUT ;
    USE SIGNAL ;
    PORT
      LAYER M5 ;
        RECT  31.536 73.224 31.56 73.416 ;
    END
  END a[361]
  PIN a[362]
    DIRECTION INPUT ;
    USE SIGNAL ;
    PORT
      LAYER M5 ;
        RECT  31.584 73.224 31.608 73.416 ;
    END
  END a[362]
  PIN a[363]
    DIRECTION INPUT ;
    USE SIGNAL ;
    PORT
      LAYER M5 ;
        RECT  31.632 73.224 31.656 73.416 ;
    END
  END a[363]
  PIN a[364]
    DIRECTION INPUT ;
    USE SIGNAL ;
    PORT
      LAYER M5 ;
        RECT  31.68 73.224 31.704 73.416 ;
    END
  END a[364]
  PIN a[365]
    DIRECTION INPUT ;
    USE SIGNAL ;
    PORT
      LAYER M5 ;
        RECT  31.728 73.224 31.752 73.416 ;
    END
  END a[365]
  PIN a[366]
    DIRECTION INPUT ;
    USE SIGNAL ;
    PORT
      LAYER M5 ;
        RECT  31.776 73.224 31.8 73.416 ;
    END
  END a[366]
  PIN a[367]
    DIRECTION INPUT ;
    USE SIGNAL ;
    PORT
      LAYER M5 ;
        RECT  31.824 73.224 31.848 73.416 ;
    END
  END a[367]
  PIN a[368]
    DIRECTION INPUT ;
    USE SIGNAL ;
    PORT
      LAYER M5 ;
        RECT  31.872 73.224 31.896 73.416 ;
    END
  END a[368]
  PIN a[369]
    DIRECTION INPUT ;
    USE SIGNAL ;
    PORT
      LAYER M5 ;
        RECT  31.92 73.224 31.944 73.416 ;
    END
  END a[369]
  PIN a[36]
    DIRECTION INPUT ;
    USE SIGNAL ;
    PORT
      LAYER M5 ;
        RECT  15.936 73.224 15.96 73.416 ;
    END
  END a[36]
  PIN a[370]
    DIRECTION INPUT ;
    USE SIGNAL ;
    PORT
      LAYER M5 ;
        RECT  31.968 73.224 31.992 73.416 ;
    END
  END a[370]
  PIN a[371]
    DIRECTION INPUT ;
    USE SIGNAL ;
    PORT
      LAYER M5 ;
        RECT  32.016 73.224 32.04 73.416 ;
    END
  END a[371]
  PIN a[372]
    DIRECTION INPUT ;
    USE SIGNAL ;
    PORT
      LAYER M5 ;
        RECT  32.064 73.224 32.088 73.416 ;
    END
  END a[372]
  PIN a[373]
    DIRECTION INPUT ;
    USE SIGNAL ;
    PORT
      LAYER M5 ;
        RECT  32.112 73.224 32.136 73.416 ;
    END
  END a[373]
  PIN a[374]
    DIRECTION INPUT ;
    USE SIGNAL ;
    PORT
      LAYER M5 ;
        RECT  32.16 73.224 32.184 73.416 ;
    END
  END a[374]
  PIN a[375]
    DIRECTION INPUT ;
    USE SIGNAL ;
    PORT
      LAYER M5 ;
        RECT  32.208 73.224 32.232 73.416 ;
    END
  END a[375]
  PIN a[376]
    DIRECTION INPUT ;
    USE SIGNAL ;
    PORT
      LAYER M5 ;
        RECT  32.256 73.224 32.28 73.416 ;
    END
  END a[376]
  PIN a[377]
    DIRECTION INPUT ;
    USE SIGNAL ;
    PORT
      LAYER M5 ;
        RECT  32.304 73.224 32.328 73.416 ;
    END
  END a[377]
  PIN a[378]
    DIRECTION INPUT ;
    USE SIGNAL ;
    PORT
      LAYER M5 ;
        RECT  32.352 73.224 32.376 73.416 ;
    END
  END a[378]
  PIN a[379]
    DIRECTION INPUT ;
    USE SIGNAL ;
    PORT
      LAYER M5 ;
        RECT  32.4 73.224 32.424 73.416 ;
    END
  END a[379]
  PIN a[37]
    DIRECTION INPUT ;
    USE SIGNAL ;
    PORT
      LAYER M5 ;
        RECT  15.984 73.224 16.008 73.416 ;
    END
  END a[37]
  PIN a[380]
    DIRECTION INPUT ;
    USE SIGNAL ;
    PORT
      LAYER M5 ;
        RECT  32.448 73.224 32.472 73.416 ;
    END
  END a[380]
  PIN a[381]
    DIRECTION INPUT ;
    USE SIGNAL ;
    PORT
      LAYER M5 ;
        RECT  32.496 73.224 32.52 73.416 ;
    END
  END a[381]
  PIN a[382]
    DIRECTION INPUT ;
    USE SIGNAL ;
    PORT
      LAYER M5 ;
        RECT  32.544 73.224 32.568 73.416 ;
    END
  END a[382]
  PIN a[383]
    DIRECTION INPUT ;
    USE SIGNAL ;
    PORT
      LAYER M5 ;
        RECT  32.592 73.224 32.616 73.416 ;
    END
  END a[383]
  PIN a[384]
    DIRECTION INPUT ;
    USE SIGNAL ;
    PORT
      LAYER M5 ;
        RECT  32.64 73.224 32.664 73.416 ;
    END
  END a[384]
  PIN a[385]
    DIRECTION INPUT ;
    USE SIGNAL ;
    PORT
      LAYER M5 ;
        RECT  32.688 73.224 32.712 73.416 ;
    END
  END a[385]
  PIN a[386]
    DIRECTION INPUT ;
    USE SIGNAL ;
    PORT
      LAYER M5 ;
        RECT  32.736 73.224 32.76 73.416 ;
    END
  END a[386]
  PIN a[387]
    DIRECTION INPUT ;
    USE SIGNAL ;
    PORT
      LAYER M5 ;
        RECT  32.784 73.224 32.808 73.416 ;
    END
  END a[387]
  PIN a[388]
    DIRECTION INPUT ;
    USE SIGNAL ;
    PORT
      LAYER M5 ;
        RECT  32.832 73.224 32.856 73.416 ;
    END
  END a[388]
  PIN a[389]
    DIRECTION INPUT ;
    USE SIGNAL ;
    PORT
      LAYER M5 ;
        RECT  32.88 73.224 32.904 73.416 ;
    END
  END a[389]
  PIN a[38]
    DIRECTION INPUT ;
    USE SIGNAL ;
    PORT
      LAYER M5 ;
        RECT  16.032 73.224 16.056 73.416 ;
    END
  END a[38]
  PIN a[390]
    DIRECTION INPUT ;
    USE SIGNAL ;
    PORT
      LAYER M5 ;
        RECT  32.928 73.224 32.952 73.416 ;
    END
  END a[390]
  PIN a[391]
    DIRECTION INPUT ;
    USE SIGNAL ;
    PORT
      LAYER M5 ;
        RECT  32.976 73.224 33 73.416 ;
    END
  END a[391]
  PIN a[392]
    DIRECTION INPUT ;
    USE SIGNAL ;
    PORT
      LAYER M5 ;
        RECT  33.024 73.224 33.048 73.416 ;
    END
  END a[392]
  PIN a[393]
    DIRECTION INPUT ;
    USE SIGNAL ;
    PORT
      LAYER M5 ;
        RECT  33.072 73.224 33.096 73.416 ;
    END
  END a[393]
  PIN a[394]
    DIRECTION INPUT ;
    USE SIGNAL ;
    PORT
      LAYER M5 ;
        RECT  33.12 73.224 33.144 73.416 ;
    END
  END a[394]
  PIN a[395]
    DIRECTION INPUT ;
    USE SIGNAL ;
    PORT
      LAYER M5 ;
        RECT  33.168 73.224 33.192 73.416 ;
    END
  END a[395]
  PIN a[396]
    DIRECTION INPUT ;
    USE SIGNAL ;
    PORT
      LAYER M5 ;
        RECT  33.216 73.224 33.24 73.416 ;
    END
  END a[396]
  PIN a[397]
    DIRECTION INPUT ;
    USE SIGNAL ;
    PORT
      LAYER M5 ;
        RECT  33.264 73.224 33.288 73.416 ;
    END
  END a[397]
  PIN a[398]
    DIRECTION INPUT ;
    USE SIGNAL ;
    PORT
      LAYER M5 ;
        RECT  33.312 73.224 33.336 73.416 ;
    END
  END a[398]
  PIN a[399]
    DIRECTION INPUT ;
    USE SIGNAL ;
    PORT
      LAYER M5 ;
        RECT  33.36 73.224 33.384 73.416 ;
    END
  END a[399]
  PIN a[39]
    DIRECTION INPUT ;
    USE SIGNAL ;
    PORT
      LAYER M5 ;
        RECT  16.08 73.224 16.104 73.416 ;
    END
  END a[39]
  PIN a[3]
    DIRECTION INPUT ;
    USE SIGNAL ;
    PORT
      LAYER M5 ;
        RECT  14.352 73.224 14.376 73.416 ;
    END
  END a[3]
  PIN a[400]
    DIRECTION INPUT ;
    USE SIGNAL ;
    PORT
      LAYER M5 ;
        RECT  33.408 73.224 33.432 73.416 ;
    END
  END a[400]
  PIN a[401]
    DIRECTION INPUT ;
    USE SIGNAL ;
    PORT
      LAYER M5 ;
        RECT  33.456 73.224 33.48 73.416 ;
    END
  END a[401]
  PIN a[402]
    DIRECTION INPUT ;
    USE SIGNAL ;
    PORT
      LAYER M5 ;
        RECT  33.504 73.224 33.528 73.416 ;
    END
  END a[402]
  PIN a[403]
    DIRECTION INPUT ;
    USE SIGNAL ;
    PORT
      LAYER M5 ;
        RECT  33.552 73.224 33.576 73.416 ;
    END
  END a[403]
  PIN a[404]
    DIRECTION INPUT ;
    USE SIGNAL ;
    PORT
      LAYER M5 ;
        RECT  33.6 73.224 33.624 73.416 ;
    END
  END a[404]
  PIN a[405]
    DIRECTION INPUT ;
    USE SIGNAL ;
    PORT
      LAYER M5 ;
        RECT  33.648 73.224 33.672 73.416 ;
    END
  END a[405]
  PIN a[406]
    DIRECTION INPUT ;
    USE SIGNAL ;
    PORT
      LAYER M5 ;
        RECT  33.696 73.224 33.72 73.416 ;
    END
  END a[406]
  PIN a[407]
    DIRECTION INPUT ;
    USE SIGNAL ;
    PORT
      LAYER M5 ;
        RECT  33.744 73.224 33.768 73.416 ;
    END
  END a[407]
  PIN a[408]
    DIRECTION INPUT ;
    USE SIGNAL ;
    PORT
      LAYER M5 ;
        RECT  33.792 73.224 33.816 73.416 ;
    END
  END a[408]
  PIN a[409]
    DIRECTION INPUT ;
    USE SIGNAL ;
    PORT
      LAYER M5 ;
        RECT  33.84 73.224 33.864 73.416 ;
    END
  END a[409]
  PIN a[40]
    DIRECTION INPUT ;
    USE SIGNAL ;
    PORT
      LAYER M5 ;
        RECT  16.128 73.224 16.152 73.416 ;
    END
  END a[40]
  PIN a[410]
    DIRECTION INPUT ;
    USE SIGNAL ;
    PORT
      LAYER M5 ;
        RECT  33.888 73.224 33.912 73.416 ;
    END
  END a[410]
  PIN a[411]
    DIRECTION INPUT ;
    USE SIGNAL ;
    PORT
      LAYER M5 ;
        RECT  33.936 73.224 33.96 73.416 ;
    END
  END a[411]
  PIN a[412]
    DIRECTION INPUT ;
    USE SIGNAL ;
    PORT
      LAYER M5 ;
        RECT  33.984 73.224 34.008 73.416 ;
    END
  END a[412]
  PIN a[413]
    DIRECTION INPUT ;
    USE SIGNAL ;
    PORT
      LAYER M5 ;
        RECT  34.032 73.224 34.056 73.416 ;
    END
  END a[413]
  PIN a[414]
    DIRECTION INPUT ;
    USE SIGNAL ;
    PORT
      LAYER M5 ;
        RECT  34.08 73.224 34.104 73.416 ;
    END
  END a[414]
  PIN a[415]
    DIRECTION INPUT ;
    USE SIGNAL ;
    PORT
      LAYER M5 ;
        RECT  34.128 73.224 34.152 73.416 ;
    END
  END a[415]
  PIN a[416]
    DIRECTION INPUT ;
    USE SIGNAL ;
    PORT
      LAYER M5 ;
        RECT  34.176 73.224 34.2 73.416 ;
    END
  END a[416]
  PIN a[417]
    DIRECTION INPUT ;
    USE SIGNAL ;
    PORT
      LAYER M5 ;
        RECT  34.224 73.224 34.248 73.416 ;
    END
  END a[417]
  PIN a[418]
    DIRECTION INPUT ;
    USE SIGNAL ;
    PORT
      LAYER M5 ;
        RECT  34.272 73.224 34.296 73.416 ;
    END
  END a[418]
  PIN a[419]
    DIRECTION INPUT ;
    USE SIGNAL ;
    PORT
      LAYER M5 ;
        RECT  34.32 73.224 34.344 73.416 ;
    END
  END a[419]
  PIN a[41]
    DIRECTION INPUT ;
    USE SIGNAL ;
    PORT
      LAYER M5 ;
        RECT  16.176 73.224 16.2 73.416 ;
    END
  END a[41]
  PIN a[420]
    DIRECTION INPUT ;
    USE SIGNAL ;
    PORT
      LAYER M5 ;
        RECT  34.368 73.224 34.392 73.416 ;
    END
  END a[420]
  PIN a[421]
    DIRECTION INPUT ;
    USE SIGNAL ;
    PORT
      LAYER M5 ;
        RECT  34.416 73.224 34.44 73.416 ;
    END
  END a[421]
  PIN a[422]
    DIRECTION INPUT ;
    USE SIGNAL ;
    PORT
      LAYER M5 ;
        RECT  34.464 73.224 34.488 73.416 ;
    END
  END a[422]
  PIN a[423]
    DIRECTION INPUT ;
    USE SIGNAL ;
    PORT
      LAYER M5 ;
        RECT  34.512 73.224 34.536 73.416 ;
    END
  END a[423]
  PIN a[424]
    DIRECTION INPUT ;
    USE SIGNAL ;
    PORT
      LAYER M5 ;
        RECT  34.56 73.224 34.584 73.416 ;
    END
  END a[424]
  PIN a[425]
    DIRECTION INPUT ;
    USE SIGNAL ;
    PORT
      LAYER M5 ;
        RECT  34.608 73.224 34.632 73.416 ;
    END
  END a[425]
  PIN a[426]
    DIRECTION INPUT ;
    USE SIGNAL ;
    PORT
      LAYER M5 ;
        RECT  34.656 73.224 34.68 73.416 ;
    END
  END a[426]
  PIN a[427]
    DIRECTION INPUT ;
    USE SIGNAL ;
    PORT
      LAYER M5 ;
        RECT  34.704 73.224 34.728 73.416 ;
    END
  END a[427]
  PIN a[428]
    DIRECTION INPUT ;
    USE SIGNAL ;
    PORT
      LAYER M5 ;
        RECT  34.752 73.224 34.776 73.416 ;
    END
  END a[428]
  PIN a[429]
    DIRECTION INPUT ;
    USE SIGNAL ;
    PORT
      LAYER M5 ;
        RECT  34.8 73.224 34.824 73.416 ;
    END
  END a[429]
  PIN a[42]
    DIRECTION INPUT ;
    USE SIGNAL ;
    PORT
      LAYER M5 ;
        RECT  16.224 73.224 16.248 73.416 ;
    END
  END a[42]
  PIN a[430]
    DIRECTION INPUT ;
    USE SIGNAL ;
    PORT
      LAYER M5 ;
        RECT  34.848 73.224 34.872 73.416 ;
    END
  END a[430]
  PIN a[431]
    DIRECTION INPUT ;
    USE SIGNAL ;
    PORT
      LAYER M5 ;
        RECT  34.896 73.224 34.92 73.416 ;
    END
  END a[431]
  PIN a[432]
    DIRECTION INPUT ;
    USE SIGNAL ;
    PORT
      LAYER M5 ;
        RECT  34.944 73.224 34.968 73.416 ;
    END
  END a[432]
  PIN a[433]
    DIRECTION INPUT ;
    USE SIGNAL ;
    PORT
      LAYER M5 ;
        RECT  34.992 73.224 35.016 73.416 ;
    END
  END a[433]
  PIN a[434]
    DIRECTION INPUT ;
    USE SIGNAL ;
    PORT
      LAYER M5 ;
        RECT  35.04 73.224 35.064 73.416 ;
    END
  END a[434]
  PIN a[435]
    DIRECTION INPUT ;
    USE SIGNAL ;
    PORT
      LAYER M5 ;
        RECT  35.088 73.224 35.112 73.416 ;
    END
  END a[435]
  PIN a[436]
    DIRECTION INPUT ;
    USE SIGNAL ;
    PORT
      LAYER M5 ;
        RECT  35.136 73.224 35.16 73.416 ;
    END
  END a[436]
  PIN a[437]
    DIRECTION INPUT ;
    USE SIGNAL ;
    PORT
      LAYER M5 ;
        RECT  35.184 73.224 35.208 73.416 ;
    END
  END a[437]
  PIN a[438]
    DIRECTION INPUT ;
    USE SIGNAL ;
    PORT
      LAYER M5 ;
        RECT  35.232 73.224 35.256 73.416 ;
    END
  END a[438]
  PIN a[439]
    DIRECTION INPUT ;
    USE SIGNAL ;
    PORT
      LAYER M5 ;
        RECT  35.28 73.224 35.304 73.416 ;
    END
  END a[439]
  PIN a[43]
    DIRECTION INPUT ;
    USE SIGNAL ;
    PORT
      LAYER M5 ;
        RECT  16.272 73.224 16.296 73.416 ;
    END
  END a[43]
  PIN a[440]
    DIRECTION INPUT ;
    USE SIGNAL ;
    PORT
      LAYER M5 ;
        RECT  35.328 73.224 35.352 73.416 ;
    END
  END a[440]
  PIN a[441]
    DIRECTION INPUT ;
    USE SIGNAL ;
    PORT
      LAYER M5 ;
        RECT  35.376 73.224 35.4 73.416 ;
    END
  END a[441]
  PIN a[442]
    DIRECTION INPUT ;
    USE SIGNAL ;
    PORT
      LAYER M5 ;
        RECT  35.424 73.224 35.448 73.416 ;
    END
  END a[442]
  PIN a[443]
    DIRECTION INPUT ;
    USE SIGNAL ;
    PORT
      LAYER M5 ;
        RECT  35.472 73.224 35.496 73.416 ;
    END
  END a[443]
  PIN a[444]
    DIRECTION INPUT ;
    USE SIGNAL ;
    PORT
      LAYER M5 ;
        RECT  35.52 73.224 35.544 73.416 ;
    END
  END a[444]
  PIN a[445]
    DIRECTION INPUT ;
    USE SIGNAL ;
    PORT
      LAYER M5 ;
        RECT  35.568 73.224 35.592 73.416 ;
    END
  END a[445]
  PIN a[446]
    DIRECTION INPUT ;
    USE SIGNAL ;
    PORT
      LAYER M5 ;
        RECT  35.616 73.224 35.64 73.416 ;
    END
  END a[446]
  PIN a[447]
    DIRECTION INPUT ;
    USE SIGNAL ;
    PORT
      LAYER M5 ;
        RECT  35.664 73.224 35.688 73.416 ;
    END
  END a[447]
  PIN a[448]
    DIRECTION INPUT ;
    USE SIGNAL ;
    PORT
      LAYER M5 ;
        RECT  35.712 73.224 35.736 73.416 ;
    END
  END a[448]
  PIN a[449]
    DIRECTION INPUT ;
    USE SIGNAL ;
    PORT
      LAYER M5 ;
        RECT  35.76 73.224 35.784 73.416 ;
    END
  END a[449]
  PIN a[44]
    DIRECTION INPUT ;
    USE SIGNAL ;
    PORT
      LAYER M5 ;
        RECT  16.32 73.224 16.344 73.416 ;
    END
  END a[44]
  PIN a[450]
    DIRECTION INPUT ;
    USE SIGNAL ;
    PORT
      LAYER M5 ;
        RECT  35.808 73.224 35.832 73.416 ;
    END
  END a[450]
  PIN a[451]
    DIRECTION INPUT ;
    USE SIGNAL ;
    PORT
      LAYER M5 ;
        RECT  35.856 73.224 35.88 73.416 ;
    END
  END a[451]
  PIN a[452]
    DIRECTION INPUT ;
    USE SIGNAL ;
    PORT
      LAYER M5 ;
        RECT  35.904 73.224 35.928 73.416 ;
    END
  END a[452]
  PIN a[453]
    DIRECTION INPUT ;
    USE SIGNAL ;
    PORT
      LAYER M5 ;
        RECT  35.952 73.224 35.976 73.416 ;
    END
  END a[453]
  PIN a[454]
    DIRECTION INPUT ;
    USE SIGNAL ;
    PORT
      LAYER M5 ;
        RECT  36 73.224 36.024 73.416 ;
    END
  END a[454]
  PIN a[455]
    DIRECTION INPUT ;
    USE SIGNAL ;
    PORT
      LAYER M5 ;
        RECT  36.048 73.224 36.072 73.416 ;
    END
  END a[455]
  PIN a[456]
    DIRECTION INPUT ;
    USE SIGNAL ;
    PORT
      LAYER M5 ;
        RECT  36.096 73.224 36.12 73.416 ;
    END
  END a[456]
  PIN a[457]
    DIRECTION INPUT ;
    USE SIGNAL ;
    PORT
      LAYER M5 ;
        RECT  36.144 73.224 36.168 73.416 ;
    END
  END a[457]
  PIN a[458]
    DIRECTION INPUT ;
    USE SIGNAL ;
    PORT
      LAYER M5 ;
        RECT  36.192 73.224 36.216 73.416 ;
    END
  END a[458]
  PIN a[459]
    DIRECTION INPUT ;
    USE SIGNAL ;
    PORT
      LAYER M5 ;
        RECT  36.24 73.224 36.264 73.416 ;
    END
  END a[459]
  PIN a[45]
    DIRECTION INPUT ;
    USE SIGNAL ;
    PORT
      LAYER M5 ;
        RECT  16.368 73.224 16.392 73.416 ;
    END
  END a[45]
  PIN a[460]
    DIRECTION INPUT ;
    USE SIGNAL ;
    PORT
      LAYER M5 ;
        RECT  36.288 73.224 36.312 73.416 ;
    END
  END a[460]
  PIN a[461]
    DIRECTION INPUT ;
    USE SIGNAL ;
    PORT
      LAYER M5 ;
        RECT  36.336 73.224 36.36 73.416 ;
    END
  END a[461]
  PIN a[462]
    DIRECTION INPUT ;
    USE SIGNAL ;
    PORT
      LAYER M5 ;
        RECT  36.384 73.224 36.408 73.416 ;
    END
  END a[462]
  PIN a[463]
    DIRECTION INPUT ;
    USE SIGNAL ;
    PORT
      LAYER M5 ;
        RECT  36.432 73.224 36.456 73.416 ;
    END
  END a[463]
  PIN a[464]
    DIRECTION INPUT ;
    USE SIGNAL ;
    PORT
      LAYER M5 ;
        RECT  36.48 73.224 36.504 73.416 ;
    END
  END a[464]
  PIN a[465]
    DIRECTION INPUT ;
    USE SIGNAL ;
    PORT
      LAYER M5 ;
        RECT  36.528 73.224 36.552 73.416 ;
    END
  END a[465]
  PIN a[466]
    DIRECTION INPUT ;
    USE SIGNAL ;
    PORT
      LAYER M5 ;
        RECT  36.576 73.224 36.6 73.416 ;
    END
  END a[466]
  PIN a[467]
    DIRECTION INPUT ;
    USE SIGNAL ;
    PORT
      LAYER M5 ;
        RECT  36.624 73.224 36.648 73.416 ;
    END
  END a[467]
  PIN a[468]
    DIRECTION INPUT ;
    USE SIGNAL ;
    PORT
      LAYER M5 ;
        RECT  36.672 73.224 36.696 73.416 ;
    END
  END a[468]
  PIN a[469]
    DIRECTION INPUT ;
    USE SIGNAL ;
    PORT
      LAYER M5 ;
        RECT  36.72 73.224 36.744 73.416 ;
    END
  END a[469]
  PIN a[46]
    DIRECTION INPUT ;
    USE SIGNAL ;
    PORT
      LAYER M5 ;
        RECT  16.416 73.224 16.44 73.416 ;
    END
  END a[46]
  PIN a[470]
    DIRECTION INPUT ;
    USE SIGNAL ;
    PORT
      LAYER M5 ;
        RECT  36.768 73.224 36.792 73.416 ;
    END
  END a[470]
  PIN a[471]
    DIRECTION INPUT ;
    USE SIGNAL ;
    PORT
      LAYER M5 ;
        RECT  36.816 73.224 36.84 73.416 ;
    END
  END a[471]
  PIN a[472]
    DIRECTION INPUT ;
    USE SIGNAL ;
    PORT
      LAYER M5 ;
        RECT  36.864 73.224 36.888 73.416 ;
    END
  END a[472]
  PIN a[473]
    DIRECTION INPUT ;
    USE SIGNAL ;
    PORT
      LAYER M5 ;
        RECT  36.912 73.224 36.936 73.416 ;
    END
  END a[473]
  PIN a[474]
    DIRECTION INPUT ;
    USE SIGNAL ;
    PORT
      LAYER M5 ;
        RECT  36.96 73.224 36.984 73.416 ;
    END
  END a[474]
  PIN a[475]
    DIRECTION INPUT ;
    USE SIGNAL ;
    PORT
      LAYER M5 ;
        RECT  37.008 73.224 37.032 73.416 ;
    END
  END a[475]
  PIN a[476]
    DIRECTION INPUT ;
    USE SIGNAL ;
    PORT
      LAYER M5 ;
        RECT  37.056 73.224 37.08 73.416 ;
    END
  END a[476]
  PIN a[477]
    DIRECTION INPUT ;
    USE SIGNAL ;
    PORT
      LAYER M5 ;
        RECT  37.104 73.224 37.128 73.416 ;
    END
  END a[477]
  PIN a[478]
    DIRECTION INPUT ;
    USE SIGNAL ;
    PORT
      LAYER M5 ;
        RECT  37.152 73.224 37.176 73.416 ;
    END
  END a[478]
  PIN a[479]
    DIRECTION INPUT ;
    USE SIGNAL ;
    PORT
      LAYER M5 ;
        RECT  37.2 73.224 37.224 73.416 ;
    END
  END a[479]
  PIN a[47]
    DIRECTION INPUT ;
    USE SIGNAL ;
    PORT
      LAYER M5 ;
        RECT  16.464 73.224 16.488 73.416 ;
    END
  END a[47]
  PIN a[480]
    DIRECTION INPUT ;
    USE SIGNAL ;
    PORT
      LAYER M5 ;
        RECT  37.248 73.224 37.272 73.416 ;
    END
  END a[480]
  PIN a[481]
    DIRECTION INPUT ;
    USE SIGNAL ;
    PORT
      LAYER M5 ;
        RECT  37.296 73.224 37.32 73.416 ;
    END
  END a[481]
  PIN a[482]
    DIRECTION INPUT ;
    USE SIGNAL ;
    PORT
      LAYER M5 ;
        RECT  37.344 73.224 37.368 73.416 ;
    END
  END a[482]
  PIN a[483]
    DIRECTION INPUT ;
    USE SIGNAL ;
    PORT
      LAYER M5 ;
        RECT  37.392 73.224 37.416 73.416 ;
    END
  END a[483]
  PIN a[484]
    DIRECTION INPUT ;
    USE SIGNAL ;
    PORT
      LAYER M5 ;
        RECT  37.44 73.224 37.464 73.416 ;
    END
  END a[484]
  PIN a[485]
    DIRECTION INPUT ;
    USE SIGNAL ;
    PORT
      LAYER M5 ;
        RECT  37.488 73.224 37.512 73.416 ;
    END
  END a[485]
  PIN a[486]
    DIRECTION INPUT ;
    USE SIGNAL ;
    PORT
      LAYER M5 ;
        RECT  37.536 73.224 37.56 73.416 ;
    END
  END a[486]
  PIN a[487]
    DIRECTION INPUT ;
    USE SIGNAL ;
    PORT
      LAYER M5 ;
        RECT  37.584 73.224 37.608 73.416 ;
    END
  END a[487]
  PIN a[488]
    DIRECTION INPUT ;
    USE SIGNAL ;
    PORT
      LAYER M5 ;
        RECT  37.632 73.224 37.656 73.416 ;
    END
  END a[488]
  PIN a[489]
    DIRECTION INPUT ;
    USE SIGNAL ;
    PORT
      LAYER M5 ;
        RECT  37.68 73.224 37.704 73.416 ;
    END
  END a[489]
  PIN a[48]
    DIRECTION INPUT ;
    USE SIGNAL ;
    PORT
      LAYER M5 ;
        RECT  16.512 73.224 16.536 73.416 ;
    END
  END a[48]
  PIN a[490]
    DIRECTION INPUT ;
    USE SIGNAL ;
    PORT
      LAYER M5 ;
        RECT  37.728 73.224 37.752 73.416 ;
    END
  END a[490]
  PIN a[491]
    DIRECTION INPUT ;
    USE SIGNAL ;
    PORT
      LAYER M5 ;
        RECT  37.776 73.224 37.8 73.416 ;
    END
  END a[491]
  PIN a[492]
    DIRECTION INPUT ;
    USE SIGNAL ;
    PORT
      LAYER M5 ;
        RECT  37.824 73.224 37.848 73.416 ;
    END
  END a[492]
  PIN a[493]
    DIRECTION INPUT ;
    USE SIGNAL ;
    PORT
      LAYER M5 ;
        RECT  37.872 73.224 37.896 73.416 ;
    END
  END a[493]
  PIN a[494]
    DIRECTION INPUT ;
    USE SIGNAL ;
    PORT
      LAYER M5 ;
        RECT  37.92 73.224 37.944 73.416 ;
    END
  END a[494]
  PIN a[495]
    DIRECTION INPUT ;
    USE SIGNAL ;
    PORT
      LAYER M5 ;
        RECT  37.968 73.224 37.992 73.416 ;
    END
  END a[495]
  PIN a[496]
    DIRECTION INPUT ;
    USE SIGNAL ;
    PORT
      LAYER M5 ;
        RECT  38.016 73.224 38.04 73.416 ;
    END
  END a[496]
  PIN a[497]
    DIRECTION INPUT ;
    USE SIGNAL ;
    PORT
      LAYER M5 ;
        RECT  38.064 73.224 38.088 73.416 ;
    END
  END a[497]
  PIN a[498]
    DIRECTION INPUT ;
    USE SIGNAL ;
    PORT
      LAYER M5 ;
        RECT  38.112 73.224 38.136 73.416 ;
    END
  END a[498]
  PIN a[499]
    DIRECTION INPUT ;
    USE SIGNAL ;
    PORT
      LAYER M5 ;
        RECT  38.16 73.224 38.184 73.416 ;
    END
  END a[499]
  PIN a[49]
    DIRECTION INPUT ;
    USE SIGNAL ;
    PORT
      LAYER M5 ;
        RECT  16.56 73.224 16.584 73.416 ;
    END
  END a[49]
  PIN a[4]
    DIRECTION INPUT ;
    USE SIGNAL ;
    PORT
      LAYER M5 ;
        RECT  14.4 73.224 14.424 73.416 ;
    END
  END a[4]
  PIN a[500]
    DIRECTION INPUT ;
    USE SIGNAL ;
    PORT
      LAYER M5 ;
        RECT  38.208 73.224 38.232 73.416 ;
    END
  END a[500]
  PIN a[501]
    DIRECTION INPUT ;
    USE SIGNAL ;
    PORT
      LAYER M5 ;
        RECT  38.256 73.224 38.28 73.416 ;
    END
  END a[501]
  PIN a[502]
    DIRECTION INPUT ;
    USE SIGNAL ;
    PORT
      LAYER M5 ;
        RECT  38.304 73.224 38.328 73.416 ;
    END
  END a[502]
  PIN a[503]
    DIRECTION INPUT ;
    USE SIGNAL ;
    PORT
      LAYER M5 ;
        RECT  38.352 73.224 38.376 73.416 ;
    END
  END a[503]
  PIN a[504]
    DIRECTION INPUT ;
    USE SIGNAL ;
    PORT
      LAYER M5 ;
        RECT  38.4 73.224 38.424 73.416 ;
    END
  END a[504]
  PIN a[505]
    DIRECTION INPUT ;
    USE SIGNAL ;
    PORT
      LAYER M5 ;
        RECT  38.448 73.224 38.472 73.416 ;
    END
  END a[505]
  PIN a[506]
    DIRECTION INPUT ;
    USE SIGNAL ;
    PORT
      LAYER M5 ;
        RECT  38.496 73.224 38.52 73.416 ;
    END
  END a[506]
  PIN a[507]
    DIRECTION INPUT ;
    USE SIGNAL ;
    PORT
      LAYER M5 ;
        RECT  38.544 73.224 38.568 73.416 ;
    END
  END a[507]
  PIN a[508]
    DIRECTION INPUT ;
    USE SIGNAL ;
    PORT
      LAYER M5 ;
        RECT  38.592 73.224 38.616 73.416 ;
    END
  END a[508]
  PIN a[509]
    DIRECTION INPUT ;
    USE SIGNAL ;
    PORT
      LAYER M5 ;
        RECT  38.64 73.224 38.664 73.416 ;
    END
  END a[509]
  PIN a[50]
    DIRECTION INPUT ;
    USE SIGNAL ;
    PORT
      LAYER M5 ;
        RECT  16.608 73.224 16.632 73.416 ;
    END
  END a[50]
  PIN a[510]
    DIRECTION INPUT ;
    USE SIGNAL ;
    PORT
      LAYER M5 ;
        RECT  38.688 73.224 38.712 73.416 ;
    END
  END a[510]
  PIN a[511]
    DIRECTION INPUT ;
    USE SIGNAL ;
    PORT
      LAYER M5 ;
        RECT  38.736 73.224 38.76 73.416 ;
    END
  END a[511]
  PIN a[512]
    DIRECTION INPUT ;
    USE SIGNAL ;
    PORT
      LAYER M5 ;
        RECT  38.784 73.224 38.808 73.416 ;
    END
  END a[512]
  PIN a[513]
    DIRECTION INPUT ;
    USE SIGNAL ;
    PORT
      LAYER M5 ;
        RECT  38.832 73.224 38.856 73.416 ;
    END
  END a[513]
  PIN a[514]
    DIRECTION INPUT ;
    USE SIGNAL ;
    PORT
      LAYER M5 ;
        RECT  38.88 73.224 38.904 73.416 ;
    END
  END a[514]
  PIN a[515]
    DIRECTION INPUT ;
    USE SIGNAL ;
    PORT
      LAYER M5 ;
        RECT  38.928 73.224 38.952 73.416 ;
    END
  END a[515]
  PIN a[516]
    DIRECTION INPUT ;
    USE SIGNAL ;
    PORT
      LAYER M5 ;
        RECT  38.976 73.224 39 73.416 ;
    END
  END a[516]
  PIN a[517]
    DIRECTION INPUT ;
    USE SIGNAL ;
    PORT
      LAYER M5 ;
        RECT  39.024 73.224 39.048 73.416 ;
    END
  END a[517]
  PIN a[518]
    DIRECTION INPUT ;
    USE SIGNAL ;
    PORT
      LAYER M5 ;
        RECT  39.072 73.224 39.096 73.416 ;
    END
  END a[518]
  PIN a[519]
    DIRECTION INPUT ;
    USE SIGNAL ;
    PORT
      LAYER M5 ;
        RECT  39.12 73.224 39.144 73.416 ;
    END
  END a[519]
  PIN a[51]
    DIRECTION INPUT ;
    USE SIGNAL ;
    PORT
      LAYER M5 ;
        RECT  16.656 73.224 16.68 73.416 ;
    END
  END a[51]
  PIN a[520]
    DIRECTION INPUT ;
    USE SIGNAL ;
    PORT
      LAYER M5 ;
        RECT  39.168 73.224 39.192 73.416 ;
    END
  END a[520]
  PIN a[521]
    DIRECTION INPUT ;
    USE SIGNAL ;
    PORT
      LAYER M5 ;
        RECT  39.216 73.224 39.24 73.416 ;
    END
  END a[521]
  PIN a[522]
    DIRECTION INPUT ;
    USE SIGNAL ;
    PORT
      LAYER M5 ;
        RECT  39.264 73.224 39.288 73.416 ;
    END
  END a[522]
  PIN a[523]
    DIRECTION INPUT ;
    USE SIGNAL ;
    PORT
      LAYER M5 ;
        RECT  39.312 73.224 39.336 73.416 ;
    END
  END a[523]
  PIN a[524]
    DIRECTION INPUT ;
    USE SIGNAL ;
    PORT
      LAYER M5 ;
        RECT  39.36 73.224 39.384 73.416 ;
    END
  END a[524]
  PIN a[525]
    DIRECTION INPUT ;
    USE SIGNAL ;
    PORT
      LAYER M5 ;
        RECT  39.408 73.224 39.432 73.416 ;
    END
  END a[525]
  PIN a[526]
    DIRECTION INPUT ;
    USE SIGNAL ;
    PORT
      LAYER M5 ;
        RECT  39.456 73.224 39.48 73.416 ;
    END
  END a[526]
  PIN a[527]
    DIRECTION INPUT ;
    USE SIGNAL ;
    PORT
      LAYER M5 ;
        RECT  39.504 73.224 39.528 73.416 ;
    END
  END a[527]
  PIN a[528]
    DIRECTION INPUT ;
    USE SIGNAL ;
    PORT
      LAYER M5 ;
        RECT  39.552 73.224 39.576 73.416 ;
    END
  END a[528]
  PIN a[529]
    DIRECTION INPUT ;
    USE SIGNAL ;
    PORT
      LAYER M5 ;
        RECT  39.6 73.224 39.624 73.416 ;
    END
  END a[529]
  PIN a[52]
    DIRECTION INPUT ;
    USE SIGNAL ;
    PORT
      LAYER M5 ;
        RECT  16.704 73.224 16.728 73.416 ;
    END
  END a[52]
  PIN a[530]
    DIRECTION INPUT ;
    USE SIGNAL ;
    PORT
      LAYER M5 ;
        RECT  39.648 73.224 39.672 73.416 ;
    END
  END a[530]
  PIN a[531]
    DIRECTION INPUT ;
    USE SIGNAL ;
    PORT
      LAYER M5 ;
        RECT  39.696 73.224 39.72 73.416 ;
    END
  END a[531]
  PIN a[532]
    DIRECTION INPUT ;
    USE SIGNAL ;
    PORT
      LAYER M5 ;
        RECT  39.744 73.224 39.768 73.416 ;
    END
  END a[532]
  PIN a[533]
    DIRECTION INPUT ;
    USE SIGNAL ;
    PORT
      LAYER M5 ;
        RECT  39.792 73.224 39.816 73.416 ;
    END
  END a[533]
  PIN a[534]
    DIRECTION INPUT ;
    USE SIGNAL ;
    PORT
      LAYER M5 ;
        RECT  39.84 73.224 39.864 73.416 ;
    END
  END a[534]
  PIN a[535]
    DIRECTION INPUT ;
    USE SIGNAL ;
    PORT
      LAYER M5 ;
        RECT  39.888 73.224 39.912 73.416 ;
    END
  END a[535]
  PIN a[536]
    DIRECTION INPUT ;
    USE SIGNAL ;
    PORT
      LAYER M5 ;
        RECT  39.936 73.224 39.96 73.416 ;
    END
  END a[536]
  PIN a[537]
    DIRECTION INPUT ;
    USE SIGNAL ;
    PORT
      LAYER M5 ;
        RECT  39.984 73.224 40.008 73.416 ;
    END
  END a[537]
  PIN a[538]
    DIRECTION INPUT ;
    USE SIGNAL ;
    PORT
      LAYER M5 ;
        RECT  40.032 73.224 40.056 73.416 ;
    END
  END a[538]
  PIN a[539]
    DIRECTION INPUT ;
    USE SIGNAL ;
    PORT
      LAYER M5 ;
        RECT  40.08 73.224 40.104 73.416 ;
    END
  END a[539]
  PIN a[53]
    DIRECTION INPUT ;
    USE SIGNAL ;
    PORT
      LAYER M5 ;
        RECT  16.752 73.224 16.776 73.416 ;
    END
  END a[53]
  PIN a[540]
    DIRECTION INPUT ;
    USE SIGNAL ;
    PORT
      LAYER M5 ;
        RECT  40.128 73.224 40.152 73.416 ;
    END
  END a[540]
  PIN a[541]
    DIRECTION INPUT ;
    USE SIGNAL ;
    PORT
      LAYER M5 ;
        RECT  40.176 73.224 40.2 73.416 ;
    END
  END a[541]
  PIN a[542]
    DIRECTION INPUT ;
    USE SIGNAL ;
    PORT
      LAYER M5 ;
        RECT  40.224 73.224 40.248 73.416 ;
    END
  END a[542]
  PIN a[543]
    DIRECTION INPUT ;
    USE SIGNAL ;
    PORT
      LAYER M5 ;
        RECT  40.272 73.224 40.296 73.416 ;
    END
  END a[543]
  PIN a[544]
    DIRECTION INPUT ;
    USE SIGNAL ;
    PORT
      LAYER M5 ;
        RECT  40.32 73.224 40.344 73.416 ;
    END
  END a[544]
  PIN a[545]
    DIRECTION INPUT ;
    USE SIGNAL ;
    PORT
      LAYER M5 ;
        RECT  40.368 73.224 40.392 73.416 ;
    END
  END a[545]
  PIN a[546]
    DIRECTION INPUT ;
    USE SIGNAL ;
    PORT
      LAYER M5 ;
        RECT  40.416 73.224 40.44 73.416 ;
    END
  END a[546]
  PIN a[547]
    DIRECTION INPUT ;
    USE SIGNAL ;
    PORT
      LAYER M5 ;
        RECT  40.464 73.224 40.488 73.416 ;
    END
  END a[547]
  PIN a[548]
    DIRECTION INPUT ;
    USE SIGNAL ;
    PORT
      LAYER M5 ;
        RECT  40.512 73.224 40.536 73.416 ;
    END
  END a[548]
  PIN a[549]
    DIRECTION INPUT ;
    USE SIGNAL ;
    PORT
      LAYER M5 ;
        RECT  40.56 73.224 40.584 73.416 ;
    END
  END a[549]
  PIN a[54]
    DIRECTION INPUT ;
    USE SIGNAL ;
    PORT
      LAYER M5 ;
        RECT  16.8 73.224 16.824 73.416 ;
    END
  END a[54]
  PIN a[550]
    DIRECTION INPUT ;
    USE SIGNAL ;
    PORT
      LAYER M5 ;
        RECT  40.608 73.224 40.632 73.416 ;
    END
  END a[550]
  PIN a[551]
    DIRECTION INPUT ;
    USE SIGNAL ;
    PORT
      LAYER M5 ;
        RECT  40.656 73.224 40.68 73.416 ;
    END
  END a[551]
  PIN a[552]
    DIRECTION INPUT ;
    USE SIGNAL ;
    PORT
      LAYER M5 ;
        RECT  40.704 73.224 40.728 73.416 ;
    END
  END a[552]
  PIN a[553]
    DIRECTION INPUT ;
    USE SIGNAL ;
    PORT
      LAYER M5 ;
        RECT  40.752 73.224 40.776 73.416 ;
    END
  END a[553]
  PIN a[554]
    DIRECTION INPUT ;
    USE SIGNAL ;
    PORT
      LAYER M5 ;
        RECT  40.8 73.224 40.824 73.416 ;
    END
  END a[554]
  PIN a[555]
    DIRECTION INPUT ;
    USE SIGNAL ;
    PORT
      LAYER M5 ;
        RECT  40.848 73.224 40.872 73.416 ;
    END
  END a[555]
  PIN a[556]
    DIRECTION INPUT ;
    USE SIGNAL ;
    PORT
      LAYER M5 ;
        RECT  40.896 73.224 40.92 73.416 ;
    END
  END a[556]
  PIN a[557]
    DIRECTION INPUT ;
    USE SIGNAL ;
    PORT
      LAYER M5 ;
        RECT  40.944 73.224 40.968 73.416 ;
    END
  END a[557]
  PIN a[558]
    DIRECTION INPUT ;
    USE SIGNAL ;
    PORT
      LAYER M5 ;
        RECT  40.992 73.224 41.016 73.416 ;
    END
  END a[558]
  PIN a[559]
    DIRECTION INPUT ;
    USE SIGNAL ;
    PORT
      LAYER M5 ;
        RECT  41.04 73.224 41.064 73.416 ;
    END
  END a[559]
  PIN a[55]
    DIRECTION INPUT ;
    USE SIGNAL ;
    PORT
      LAYER M5 ;
        RECT  16.848 73.224 16.872 73.416 ;
    END
  END a[55]
  PIN a[560]
    DIRECTION INPUT ;
    USE SIGNAL ;
    PORT
      LAYER M5 ;
        RECT  41.088 73.224 41.112 73.416 ;
    END
  END a[560]
  PIN a[561]
    DIRECTION INPUT ;
    USE SIGNAL ;
    PORT
      LAYER M5 ;
        RECT  41.136 73.224 41.16 73.416 ;
    END
  END a[561]
  PIN a[562]
    DIRECTION INPUT ;
    USE SIGNAL ;
    PORT
      LAYER M5 ;
        RECT  41.184 73.224 41.208 73.416 ;
    END
  END a[562]
  PIN a[563]
    DIRECTION INPUT ;
    USE SIGNAL ;
    PORT
      LAYER M5 ;
        RECT  41.232 73.224 41.256 73.416 ;
    END
  END a[563]
  PIN a[564]
    DIRECTION INPUT ;
    USE SIGNAL ;
    PORT
      LAYER M5 ;
        RECT  41.28 73.224 41.304 73.416 ;
    END
  END a[564]
  PIN a[565]
    DIRECTION INPUT ;
    USE SIGNAL ;
    PORT
      LAYER M5 ;
        RECT  41.328 73.224 41.352 73.416 ;
    END
  END a[565]
  PIN a[566]
    DIRECTION INPUT ;
    USE SIGNAL ;
    PORT
      LAYER M5 ;
        RECT  41.376 73.224 41.4 73.416 ;
    END
  END a[566]
  PIN a[567]
    DIRECTION INPUT ;
    USE SIGNAL ;
    PORT
      LAYER M5 ;
        RECT  41.424 73.224 41.448 73.416 ;
    END
  END a[567]
  PIN a[568]
    DIRECTION INPUT ;
    USE SIGNAL ;
    PORT
      LAYER M5 ;
        RECT  41.472 73.224 41.496 73.416 ;
    END
  END a[568]
  PIN a[569]
    DIRECTION INPUT ;
    USE SIGNAL ;
    PORT
      LAYER M5 ;
        RECT  41.52 73.224 41.544 73.416 ;
    END
  END a[569]
  PIN a[56]
    DIRECTION INPUT ;
    USE SIGNAL ;
    PORT
      LAYER M5 ;
        RECT  16.896 73.224 16.92 73.416 ;
    END
  END a[56]
  PIN a[570]
    DIRECTION INPUT ;
    USE SIGNAL ;
    PORT
      LAYER M5 ;
        RECT  41.568 73.224 41.592 73.416 ;
    END
  END a[570]
  PIN a[571]
    DIRECTION INPUT ;
    USE SIGNAL ;
    PORT
      LAYER M5 ;
        RECT  41.616 73.224 41.64 73.416 ;
    END
  END a[571]
  PIN a[572]
    DIRECTION INPUT ;
    USE SIGNAL ;
    PORT
      LAYER M5 ;
        RECT  41.664 73.224 41.688 73.416 ;
    END
  END a[572]
  PIN a[573]
    DIRECTION INPUT ;
    USE SIGNAL ;
    PORT
      LAYER M5 ;
        RECT  41.712 73.224 41.736 73.416 ;
    END
  END a[573]
  PIN a[574]
    DIRECTION INPUT ;
    USE SIGNAL ;
    PORT
      LAYER M5 ;
        RECT  41.76 73.224 41.784 73.416 ;
    END
  END a[574]
  PIN a[575]
    DIRECTION INPUT ;
    USE SIGNAL ;
    PORT
      LAYER M5 ;
        RECT  41.808 73.224 41.832 73.416 ;
    END
  END a[575]
  PIN a[576]
    DIRECTION INPUT ;
    USE SIGNAL ;
    PORT
      LAYER M5 ;
        RECT  41.856 73.224 41.88 73.416 ;
    END
  END a[576]
  PIN a[577]
    DIRECTION INPUT ;
    USE SIGNAL ;
    PORT
      LAYER M5 ;
        RECT  41.904 73.224 41.928 73.416 ;
    END
  END a[577]
  PIN a[578]
    DIRECTION INPUT ;
    USE SIGNAL ;
    PORT
      LAYER M5 ;
        RECT  41.952 73.224 41.976 73.416 ;
    END
  END a[578]
  PIN a[579]
    DIRECTION INPUT ;
    USE SIGNAL ;
    PORT
      LAYER M5 ;
        RECT  42 73.224 42.024 73.416 ;
    END
  END a[579]
  PIN a[57]
    DIRECTION INPUT ;
    USE SIGNAL ;
    PORT
      LAYER M5 ;
        RECT  16.944 73.224 16.968 73.416 ;
    END
  END a[57]
  PIN a[580]
    DIRECTION INPUT ;
    USE SIGNAL ;
    PORT
      LAYER M5 ;
        RECT  42.048 73.224 42.072 73.416 ;
    END
  END a[580]
  PIN a[581]
    DIRECTION INPUT ;
    USE SIGNAL ;
    PORT
      LAYER M5 ;
        RECT  42.096 73.224 42.12 73.416 ;
    END
  END a[581]
  PIN a[58]
    DIRECTION INPUT ;
    USE SIGNAL ;
    PORT
      LAYER M5 ;
        RECT  16.992 73.224 17.016 73.416 ;
    END
  END a[58]
  PIN a[59]
    DIRECTION INPUT ;
    USE SIGNAL ;
    PORT
      LAYER M5 ;
        RECT  17.04 73.224 17.064 73.416 ;
    END
  END a[59]
  PIN a[5]
    DIRECTION INPUT ;
    USE SIGNAL ;
    PORT
      LAYER M5 ;
        RECT  14.448 73.224 14.472 73.416 ;
    END
  END a[5]
  PIN a[60]
    DIRECTION INPUT ;
    USE SIGNAL ;
    PORT
      LAYER M5 ;
        RECT  17.088 73.224 17.112 73.416 ;
    END
  END a[60]
  PIN a[61]
    DIRECTION INPUT ;
    USE SIGNAL ;
    PORT
      LAYER M5 ;
        RECT  17.136 73.224 17.16 73.416 ;
    END
  END a[61]
  PIN a[62]
    DIRECTION INPUT ;
    USE SIGNAL ;
    PORT
      LAYER M5 ;
        RECT  17.184 73.224 17.208 73.416 ;
    END
  END a[62]
  PIN a[63]
    DIRECTION INPUT ;
    USE SIGNAL ;
    PORT
      LAYER M5 ;
        RECT  17.232 73.224 17.256 73.416 ;
    END
  END a[63]
  PIN a[64]
    DIRECTION INPUT ;
    USE SIGNAL ;
    PORT
      LAYER M5 ;
        RECT  17.28 73.224 17.304 73.416 ;
    END
  END a[64]
  PIN a[65]
    DIRECTION INPUT ;
    USE SIGNAL ;
    PORT
      LAYER M5 ;
        RECT  17.328 73.224 17.352 73.416 ;
    END
  END a[65]
  PIN a[66]
    DIRECTION INPUT ;
    USE SIGNAL ;
    PORT
      LAYER M5 ;
        RECT  17.376 73.224 17.4 73.416 ;
    END
  END a[66]
  PIN a[67]
    DIRECTION INPUT ;
    USE SIGNAL ;
    PORT
      LAYER M5 ;
        RECT  17.424 73.224 17.448 73.416 ;
    END
  END a[67]
  PIN a[68]
    DIRECTION INPUT ;
    USE SIGNAL ;
    PORT
      LAYER M5 ;
        RECT  17.472 73.224 17.496 73.416 ;
    END
  END a[68]
  PIN a[69]
    DIRECTION INPUT ;
    USE SIGNAL ;
    PORT
      LAYER M5 ;
        RECT  17.52 73.224 17.544 73.416 ;
    END
  END a[69]
  PIN a[6]
    DIRECTION INPUT ;
    USE SIGNAL ;
    PORT
      LAYER M5 ;
        RECT  14.496 73.224 14.52 73.416 ;
    END
  END a[6]
  PIN a[70]
    DIRECTION INPUT ;
    USE SIGNAL ;
    PORT
      LAYER M5 ;
        RECT  17.568 73.224 17.592 73.416 ;
    END
  END a[70]
  PIN a[71]
    DIRECTION INPUT ;
    USE SIGNAL ;
    PORT
      LAYER M5 ;
        RECT  17.616 73.224 17.64 73.416 ;
    END
  END a[71]
  PIN a[72]
    DIRECTION INPUT ;
    USE SIGNAL ;
    PORT
      LAYER M5 ;
        RECT  17.664 73.224 17.688 73.416 ;
    END
  END a[72]
  PIN a[73]
    DIRECTION INPUT ;
    USE SIGNAL ;
    PORT
      LAYER M5 ;
        RECT  17.712 73.224 17.736 73.416 ;
    END
  END a[73]
  PIN a[74]
    DIRECTION INPUT ;
    USE SIGNAL ;
    PORT
      LAYER M5 ;
        RECT  17.76 73.224 17.784 73.416 ;
    END
  END a[74]
  PIN a[75]
    DIRECTION INPUT ;
    USE SIGNAL ;
    PORT
      LAYER M5 ;
        RECT  17.808 73.224 17.832 73.416 ;
    END
  END a[75]
  PIN a[76]
    DIRECTION INPUT ;
    USE SIGNAL ;
    PORT
      LAYER M5 ;
        RECT  17.856 73.224 17.88 73.416 ;
    END
  END a[76]
  PIN a[77]
    DIRECTION INPUT ;
    USE SIGNAL ;
    PORT
      LAYER M5 ;
        RECT  17.904 73.224 17.928 73.416 ;
    END
  END a[77]
  PIN a[78]
    DIRECTION INPUT ;
    USE SIGNAL ;
    PORT
      LAYER M5 ;
        RECT  17.952 73.224 17.976 73.416 ;
    END
  END a[78]
  PIN a[79]
    DIRECTION INPUT ;
    USE SIGNAL ;
    PORT
      LAYER M5 ;
        RECT  18 73.224 18.024 73.416 ;
    END
  END a[79]
  PIN a[7]
    DIRECTION INPUT ;
    USE SIGNAL ;
    PORT
      LAYER M5 ;
        RECT  14.544 73.224 14.568 73.416 ;
    END
  END a[7]
  PIN a[80]
    DIRECTION INPUT ;
    USE SIGNAL ;
    PORT
      LAYER M5 ;
        RECT  18.048 73.224 18.072 73.416 ;
    END
  END a[80]
  PIN a[81]
    DIRECTION INPUT ;
    USE SIGNAL ;
    PORT
      LAYER M5 ;
        RECT  18.096 73.224 18.12 73.416 ;
    END
  END a[81]
  PIN a[82]
    DIRECTION INPUT ;
    USE SIGNAL ;
    PORT
      LAYER M5 ;
        RECT  18.144 73.224 18.168 73.416 ;
    END
  END a[82]
  PIN a[83]
    DIRECTION INPUT ;
    USE SIGNAL ;
    PORT
      LAYER M5 ;
        RECT  18.192 73.224 18.216 73.416 ;
    END
  END a[83]
  PIN a[84]
    DIRECTION INPUT ;
    USE SIGNAL ;
    PORT
      LAYER M5 ;
        RECT  18.24 73.224 18.264 73.416 ;
    END
  END a[84]
  PIN a[85]
    DIRECTION INPUT ;
    USE SIGNAL ;
    PORT
      LAYER M5 ;
        RECT  18.288 73.224 18.312 73.416 ;
    END
  END a[85]
  PIN a[86]
    DIRECTION INPUT ;
    USE SIGNAL ;
    PORT
      LAYER M5 ;
        RECT  18.336 73.224 18.36 73.416 ;
    END
  END a[86]
  PIN a[87]
    DIRECTION INPUT ;
    USE SIGNAL ;
    PORT
      LAYER M5 ;
        RECT  18.384 73.224 18.408 73.416 ;
    END
  END a[87]
  PIN a[88]
    DIRECTION INPUT ;
    USE SIGNAL ;
    PORT
      LAYER M5 ;
        RECT  18.432 73.224 18.456 73.416 ;
    END
  END a[88]
  PIN a[89]
    DIRECTION INPUT ;
    USE SIGNAL ;
    PORT
      LAYER M5 ;
        RECT  18.48 73.224 18.504 73.416 ;
    END
  END a[89]
  PIN a[8]
    DIRECTION INPUT ;
    USE SIGNAL ;
    PORT
      LAYER M5 ;
        RECT  14.592 73.224 14.616 73.416 ;
    END
  END a[8]
  PIN a[90]
    DIRECTION INPUT ;
    USE SIGNAL ;
    PORT
      LAYER M5 ;
        RECT  18.528 73.224 18.552 73.416 ;
    END
  END a[90]
  PIN a[91]
    DIRECTION INPUT ;
    USE SIGNAL ;
    PORT
      LAYER M5 ;
        RECT  18.576 73.224 18.6 73.416 ;
    END
  END a[91]
  PIN a[92]
    DIRECTION INPUT ;
    USE SIGNAL ;
    PORT
      LAYER M5 ;
        RECT  18.624 73.224 18.648 73.416 ;
    END
  END a[92]
  PIN a[93]
    DIRECTION INPUT ;
    USE SIGNAL ;
    PORT
      LAYER M5 ;
        RECT  18.672 73.224 18.696 73.416 ;
    END
  END a[93]
  PIN a[94]
    DIRECTION INPUT ;
    USE SIGNAL ;
    PORT
      LAYER M5 ;
        RECT  18.72 73.224 18.744 73.416 ;
    END
  END a[94]
  PIN a[95]
    DIRECTION INPUT ;
    USE SIGNAL ;
    PORT
      LAYER M5 ;
        RECT  18.768 73.224 18.792 73.416 ;
    END
  END a[95]
  PIN a[96]
    DIRECTION INPUT ;
    USE SIGNAL ;
    PORT
      LAYER M5 ;
        RECT  18.816 73.224 18.84 73.416 ;
    END
  END a[96]
  PIN a[97]
    DIRECTION INPUT ;
    USE SIGNAL ;
    PORT
      LAYER M5 ;
        RECT  18.864 73.224 18.888 73.416 ;
    END
  END a[97]
  PIN a[98]
    DIRECTION INPUT ;
    USE SIGNAL ;
    PORT
      LAYER M5 ;
        RECT  18.912 73.224 18.936 73.416 ;
    END
  END a[98]
  PIN a[99]
    DIRECTION INPUT ;
    USE SIGNAL ;
    PORT
      LAYER M5 ;
        RECT  18.96 73.224 18.984 73.416 ;
    END
  END a[99]
  PIN a[9]
    DIRECTION INPUT ;
    USE SIGNAL ;
    PORT
      LAYER M5 ;
        RECT  14.64 73.224 14.664 73.416 ;
    END
  END a[9]
  PIN b[0]
    DIRECTION OUTPUT ;
    USE SIGNAL ;
    PORT
      LAYER M5 ;
        RECT  0.624 0 0.648 0.192 ;
    END
  END b[0]
  PIN b[100]
    DIRECTION OUTPUT ;
    USE SIGNAL ;
    PORT
      LAYER M5 ;
        RECT  5.424 0 5.448 0.192 ;
    END
  END b[100]
  PIN b[101]
    DIRECTION OUTPUT ;
    USE SIGNAL ;
    PORT
      LAYER M5 ;
        RECT  5.472 0 5.496 0.192 ;
    END
  END b[101]
  PIN b[102]
    DIRECTION OUTPUT ;
    USE SIGNAL ;
    PORT
      LAYER M5 ;
        RECT  5.52 0 5.544 0.192 ;
    END
  END b[102]
  PIN b[103]
    DIRECTION OUTPUT ;
    USE SIGNAL ;
    PORT
      LAYER M5 ;
        RECT  5.568 0 5.592 0.192 ;
    END
  END b[103]
  PIN b[104]
    DIRECTION OUTPUT ;
    USE SIGNAL ;
    PORT
      LAYER M5 ;
        RECT  5.616 0 5.64 0.192 ;
    END
  END b[104]
  PIN b[105]
    DIRECTION OUTPUT ;
    USE SIGNAL ;
    PORT
      LAYER M5 ;
        RECT  5.664 0 5.688 0.192 ;
    END
  END b[105]
  PIN b[106]
    DIRECTION OUTPUT ;
    USE SIGNAL ;
    PORT
      LAYER M5 ;
        RECT  5.712 0 5.736 0.192 ;
    END
  END b[106]
  PIN b[107]
    DIRECTION OUTPUT ;
    USE SIGNAL ;
    PORT
      LAYER M5 ;
        RECT  5.76 0 5.784 0.192 ;
    END
  END b[107]
  PIN b[108]
    DIRECTION OUTPUT ;
    USE SIGNAL ;
    PORT
      LAYER M5 ;
        RECT  5.808 0 5.832 0.192 ;
    END
  END b[108]
  PIN b[109]
    DIRECTION OUTPUT ;
    USE SIGNAL ;
    PORT
      LAYER M5 ;
        RECT  5.856 0 5.88 0.192 ;
    END
  END b[109]
  PIN b[10]
    DIRECTION OUTPUT ;
    USE SIGNAL ;
    PORT
      LAYER M5 ;
        RECT  1.104 0 1.128 0.192 ;
    END
  END b[10]
  PIN b[110]
    DIRECTION OUTPUT ;
    USE SIGNAL ;
    PORT
      LAYER M5 ;
        RECT  5.904 0 5.928 0.192 ;
    END
  END b[110]
  PIN b[111]
    DIRECTION OUTPUT ;
    USE SIGNAL ;
    PORT
      LAYER M5 ;
        RECT  5.952 0 5.976 0.192 ;
    END
  END b[111]
  PIN b[112]
    DIRECTION OUTPUT ;
    USE SIGNAL ;
    PORT
      LAYER M5 ;
        RECT  6 0 6.024 0.192 ;
    END
  END b[112]
  PIN b[113]
    DIRECTION OUTPUT ;
    USE SIGNAL ;
    PORT
      LAYER M5 ;
        RECT  6.048 0 6.072 0.192 ;
    END
  END b[113]
  PIN b[114]
    DIRECTION OUTPUT ;
    USE SIGNAL ;
    PORT
      LAYER M5 ;
        RECT  6.096 0 6.12 0.192 ;
    END
  END b[114]
  PIN b[115]
    DIRECTION OUTPUT ;
    USE SIGNAL ;
    PORT
      LAYER M5 ;
        RECT  6.144 0 6.168 0.192 ;
    END
  END b[115]
  PIN b[116]
    DIRECTION OUTPUT ;
    USE SIGNAL ;
    PORT
      LAYER M5 ;
        RECT  6.192 0 6.216 0.192 ;
    END
  END b[116]
  PIN b[117]
    DIRECTION OUTPUT ;
    USE SIGNAL ;
    PORT
      LAYER M5 ;
        RECT  6.24 0 6.264 0.192 ;
    END
  END b[117]
  PIN b[118]
    DIRECTION OUTPUT ;
    USE SIGNAL ;
    PORT
      LAYER M5 ;
        RECT  6.288 0 6.312 0.192 ;
    END
  END b[118]
  PIN b[119]
    DIRECTION OUTPUT ;
    USE SIGNAL ;
    PORT
      LAYER M5 ;
        RECT  6.336 0 6.36 0.192 ;
    END
  END b[119]
  PIN b[11]
    DIRECTION OUTPUT ;
    USE SIGNAL ;
    PORT
      LAYER M5 ;
        RECT  1.152 0 1.176 0.192 ;
    END
  END b[11]
  PIN b[120]
    DIRECTION OUTPUT ;
    USE SIGNAL ;
    PORT
      LAYER M5 ;
        RECT  6.384 0 6.408 0.192 ;
    END
  END b[120]
  PIN b[121]
    DIRECTION OUTPUT ;
    USE SIGNAL ;
    PORT
      LAYER M5 ;
        RECT  6.432 0 6.456 0.192 ;
    END
  END b[121]
  PIN b[122]
    DIRECTION OUTPUT ;
    USE SIGNAL ;
    PORT
      LAYER M5 ;
        RECT  6.48 0 6.504 0.192 ;
    END
  END b[122]
  PIN b[123]
    DIRECTION OUTPUT ;
    USE SIGNAL ;
    PORT
      LAYER M5 ;
        RECT  6.528 0 6.552 0.192 ;
    END
  END b[123]
  PIN b[124]
    DIRECTION OUTPUT ;
    USE SIGNAL ;
    PORT
      LAYER M5 ;
        RECT  6.576 0 6.6 0.192 ;
    END
  END b[124]
  PIN b[125]
    DIRECTION OUTPUT ;
    USE SIGNAL ;
    PORT
      LAYER M5 ;
        RECT  6.624 0 6.648 0.192 ;
    END
  END b[125]
  PIN b[126]
    DIRECTION OUTPUT ;
    USE SIGNAL ;
    PORT
      LAYER M5 ;
        RECT  6.672 0 6.696 0.192 ;
    END
  END b[126]
  PIN b[127]
    DIRECTION OUTPUT ;
    USE SIGNAL ;
    PORT
      LAYER M5 ;
        RECT  6.72 0 6.744 0.192 ;
    END
  END b[127]
  PIN b[128]
    DIRECTION OUTPUT ;
    USE SIGNAL ;
    PORT
      LAYER M5 ;
        RECT  6.768 0 6.792 0.192 ;
    END
  END b[128]
  PIN b[129]
    DIRECTION OUTPUT ;
    USE SIGNAL ;
    PORT
      LAYER M5 ;
        RECT  6.816 0 6.84 0.192 ;
    END
  END b[129]
  PIN b[12]
    DIRECTION OUTPUT ;
    USE SIGNAL ;
    PORT
      LAYER M5 ;
        RECT  1.2 0 1.224 0.192 ;
    END
  END b[12]
  PIN b[130]
    DIRECTION OUTPUT ;
    USE SIGNAL ;
    PORT
      LAYER M5 ;
        RECT  6.864 0 6.888 0.192 ;
    END
  END b[130]
  PIN b[131]
    DIRECTION OUTPUT ;
    USE SIGNAL ;
    PORT
      LAYER M5 ;
        RECT  6.912 0 6.936 0.192 ;
    END
  END b[131]
  PIN b[132]
    DIRECTION OUTPUT ;
    USE SIGNAL ;
    PORT
      LAYER M5 ;
        RECT  6.96 0 6.984 0.192 ;
    END
  END b[132]
  PIN b[133]
    DIRECTION OUTPUT ;
    USE SIGNAL ;
    PORT
      LAYER M5 ;
        RECT  7.008 0 7.032 0.192 ;
    END
  END b[133]
  PIN b[134]
    DIRECTION OUTPUT ;
    USE SIGNAL ;
    PORT
      LAYER M5 ;
        RECT  7.056 0 7.08 0.192 ;
    END
  END b[134]
  PIN b[135]
    DIRECTION OUTPUT ;
    USE SIGNAL ;
    PORT
      LAYER M5 ;
        RECT  7.104 0 7.128 0.192 ;
    END
  END b[135]
  PIN b[136]
    DIRECTION OUTPUT ;
    USE SIGNAL ;
    PORT
      LAYER M5 ;
        RECT  7.152 0 7.176 0.192 ;
    END
  END b[136]
  PIN b[137]
    DIRECTION OUTPUT ;
    USE SIGNAL ;
    PORT
      LAYER M5 ;
        RECT  7.2 0 7.224 0.192 ;
    END
  END b[137]
  PIN b[138]
    DIRECTION OUTPUT ;
    USE SIGNAL ;
    PORT
      LAYER M5 ;
        RECT  7.248 0 7.272 0.192 ;
    END
  END b[138]
  PIN b[139]
    DIRECTION OUTPUT ;
    USE SIGNAL ;
    PORT
      LAYER M5 ;
        RECT  7.296 0 7.32 0.192 ;
    END
  END b[139]
  PIN b[13]
    DIRECTION OUTPUT ;
    USE SIGNAL ;
    PORT
      LAYER M5 ;
        RECT  1.248 0 1.272 0.192 ;
    END
  END b[13]
  PIN b[140]
    DIRECTION OUTPUT ;
    USE SIGNAL ;
    PORT
      LAYER M5 ;
        RECT  7.344 0 7.368 0.192 ;
    END
  END b[140]
  PIN b[141]
    DIRECTION OUTPUT ;
    USE SIGNAL ;
    PORT
      LAYER M5 ;
        RECT  7.392 0 7.416 0.192 ;
    END
  END b[141]
  PIN b[142]
    DIRECTION OUTPUT ;
    USE SIGNAL ;
    PORT
      LAYER M5 ;
        RECT  7.44 0 7.464 0.192 ;
    END
  END b[142]
  PIN b[143]
    DIRECTION OUTPUT ;
    USE SIGNAL ;
    PORT
      LAYER M5 ;
        RECT  7.488 0 7.512 0.192 ;
    END
  END b[143]
  PIN b[144]
    DIRECTION OUTPUT ;
    USE SIGNAL ;
    PORT
      LAYER M5 ;
        RECT  7.536 0 7.56 0.192 ;
    END
  END b[144]
  PIN b[145]
    DIRECTION OUTPUT ;
    USE SIGNAL ;
    PORT
      LAYER M5 ;
        RECT  7.584 0 7.608 0.192 ;
    END
  END b[145]
  PIN b[146]
    DIRECTION OUTPUT ;
    USE SIGNAL ;
    PORT
      LAYER M5 ;
        RECT  7.632 0 7.656 0.192 ;
    END
  END b[146]
  PIN b[147]
    DIRECTION OUTPUT ;
    USE SIGNAL ;
    PORT
      LAYER M5 ;
        RECT  7.68 0 7.704 0.192 ;
    END
  END b[147]
  PIN b[148]
    DIRECTION OUTPUT ;
    USE SIGNAL ;
    PORT
      LAYER M5 ;
        RECT  7.728 0 7.752 0.192 ;
    END
  END b[148]
  PIN b[149]
    DIRECTION OUTPUT ;
    USE SIGNAL ;
    PORT
      LAYER M5 ;
        RECT  7.776 0 7.8 0.192 ;
    END
  END b[149]
  PIN b[14]
    DIRECTION OUTPUT ;
    USE SIGNAL ;
    PORT
      LAYER M5 ;
        RECT  1.296 0 1.32 0.192 ;
    END
  END b[14]
  PIN b[150]
    DIRECTION OUTPUT ;
    USE SIGNAL ;
    PORT
      LAYER M5 ;
        RECT  7.824 0 7.848 0.192 ;
    END
  END b[150]
  PIN b[151]
    DIRECTION OUTPUT ;
    USE SIGNAL ;
    PORT
      LAYER M5 ;
        RECT  7.872 0 7.896 0.192 ;
    END
  END b[151]
  PIN b[152]
    DIRECTION OUTPUT ;
    USE SIGNAL ;
    PORT
      LAYER M5 ;
        RECT  7.92 0 7.944 0.192 ;
    END
  END b[152]
  PIN b[153]
    DIRECTION OUTPUT ;
    USE SIGNAL ;
    PORT
      LAYER M5 ;
        RECT  7.968 0 7.992 0.192 ;
    END
  END b[153]
  PIN b[154]
    DIRECTION OUTPUT ;
    USE SIGNAL ;
    PORT
      LAYER M5 ;
        RECT  8.016 0 8.04 0.192 ;
    END
  END b[154]
  PIN b[155]
    DIRECTION OUTPUT ;
    USE SIGNAL ;
    PORT
      LAYER M5 ;
        RECT  8.064 0 8.088 0.192 ;
    END
  END b[155]
  PIN b[156]
    DIRECTION OUTPUT ;
    USE SIGNAL ;
    PORT
      LAYER M5 ;
        RECT  8.112 0 8.136 0.192 ;
    END
  END b[156]
  PIN b[157]
    DIRECTION OUTPUT ;
    USE SIGNAL ;
    PORT
      LAYER M5 ;
        RECT  8.16 0 8.184 0.192 ;
    END
  END b[157]
  PIN b[158]
    DIRECTION OUTPUT ;
    USE SIGNAL ;
    PORT
      LAYER M5 ;
        RECT  8.208 0 8.232 0.192 ;
    END
  END b[158]
  PIN b[159]
    DIRECTION OUTPUT ;
    USE SIGNAL ;
    PORT
      LAYER M5 ;
        RECT  8.256 0 8.28 0.192 ;
    END
  END b[159]
  PIN b[15]
    DIRECTION OUTPUT ;
    USE SIGNAL ;
    PORT
      LAYER M5 ;
        RECT  1.344 0 1.368 0.192 ;
    END
  END b[15]
  PIN b[160]
    DIRECTION OUTPUT ;
    USE SIGNAL ;
    PORT
      LAYER M5 ;
        RECT  8.304 0 8.328 0.192 ;
    END
  END b[160]
  PIN b[161]
    DIRECTION OUTPUT ;
    USE SIGNAL ;
    PORT
      LAYER M5 ;
        RECT  8.352 0 8.376 0.192 ;
    END
  END b[161]
  PIN b[162]
    DIRECTION OUTPUT ;
    USE SIGNAL ;
    PORT
      LAYER M5 ;
        RECT  8.4 0 8.424 0.192 ;
    END
  END b[162]
  PIN b[163]
    DIRECTION OUTPUT ;
    USE SIGNAL ;
    PORT
      LAYER M5 ;
        RECT  8.448 0 8.472 0.192 ;
    END
  END b[163]
  PIN b[164]
    DIRECTION OUTPUT ;
    USE SIGNAL ;
    PORT
      LAYER M5 ;
        RECT  8.496 0 8.52 0.192 ;
    END
  END b[164]
  PIN b[165]
    DIRECTION OUTPUT ;
    USE SIGNAL ;
    PORT
      LAYER M5 ;
        RECT  8.544 0 8.568 0.192 ;
    END
  END b[165]
  PIN b[166]
    DIRECTION OUTPUT ;
    USE SIGNAL ;
    PORT
      LAYER M5 ;
        RECT  8.592 0 8.616 0.192 ;
    END
  END b[166]
  PIN b[167]
    DIRECTION OUTPUT ;
    USE SIGNAL ;
    PORT
      LAYER M5 ;
        RECT  8.64 0 8.664 0.192 ;
    END
  END b[167]
  PIN b[168]
    DIRECTION OUTPUT ;
    USE SIGNAL ;
    PORT
      LAYER M5 ;
        RECT  8.688 0 8.712 0.192 ;
    END
  END b[168]
  PIN b[169]
    DIRECTION OUTPUT ;
    USE SIGNAL ;
    PORT
      LAYER M5 ;
        RECT  8.736 0 8.76 0.192 ;
    END
  END b[169]
  PIN b[16]
    DIRECTION OUTPUT ;
    USE SIGNAL ;
    PORT
      LAYER M5 ;
        RECT  1.392 0 1.416 0.192 ;
    END
  END b[16]
  PIN b[170]
    DIRECTION OUTPUT ;
    USE SIGNAL ;
    PORT
      LAYER M5 ;
        RECT  8.784 0 8.808 0.192 ;
    END
  END b[170]
  PIN b[171]
    DIRECTION OUTPUT ;
    USE SIGNAL ;
    PORT
      LAYER M5 ;
        RECT  8.832 0 8.856 0.192 ;
    END
  END b[171]
  PIN b[172]
    DIRECTION OUTPUT ;
    USE SIGNAL ;
    PORT
      LAYER M5 ;
        RECT  8.88 0 8.904 0.192 ;
    END
  END b[172]
  PIN b[173]
    DIRECTION OUTPUT ;
    USE SIGNAL ;
    PORT
      LAYER M5 ;
        RECT  8.928 0 8.952 0.192 ;
    END
  END b[173]
  PIN b[174]
    DIRECTION OUTPUT ;
    USE SIGNAL ;
    PORT
      LAYER M5 ;
        RECT  8.976 0 9 0.192 ;
    END
  END b[174]
  PIN b[175]
    DIRECTION OUTPUT ;
    USE SIGNAL ;
    PORT
      LAYER M5 ;
        RECT  9.024 0 9.048 0.192 ;
    END
  END b[175]
  PIN b[176]
    DIRECTION OUTPUT ;
    USE SIGNAL ;
    PORT
      LAYER M5 ;
        RECT  9.072 0 9.096 0.192 ;
    END
  END b[176]
  PIN b[177]
    DIRECTION OUTPUT ;
    USE SIGNAL ;
    PORT
      LAYER M5 ;
        RECT  9.12 0 9.144 0.192 ;
    END
  END b[177]
  PIN b[178]
    DIRECTION OUTPUT ;
    USE SIGNAL ;
    PORT
      LAYER M5 ;
        RECT  9.168 0 9.192 0.192 ;
    END
  END b[178]
  PIN b[179]
    DIRECTION OUTPUT ;
    USE SIGNAL ;
    PORT
      LAYER M5 ;
        RECT  9.216 0 9.24 0.192 ;
    END
  END b[179]
  PIN b[17]
    DIRECTION OUTPUT ;
    USE SIGNAL ;
    PORT
      LAYER M5 ;
        RECT  1.44 0 1.464 0.192 ;
    END
  END b[17]
  PIN b[180]
    DIRECTION OUTPUT ;
    USE SIGNAL ;
    PORT
      LAYER M5 ;
        RECT  9.264 0 9.288 0.192 ;
    END
  END b[180]
  PIN b[181]
    DIRECTION OUTPUT ;
    USE SIGNAL ;
    PORT
      LAYER M5 ;
        RECT  9.312 0 9.336 0.192 ;
    END
  END b[181]
  PIN b[182]
    DIRECTION OUTPUT ;
    USE SIGNAL ;
    PORT
      LAYER M5 ;
        RECT  9.36 0 9.384 0.192 ;
    END
  END b[182]
  PIN b[183]
    DIRECTION OUTPUT ;
    USE SIGNAL ;
    PORT
      LAYER M5 ;
        RECT  9.408 0 9.432 0.192 ;
    END
  END b[183]
  PIN b[184]
    DIRECTION OUTPUT ;
    USE SIGNAL ;
    PORT
      LAYER M5 ;
        RECT  9.456 0 9.48 0.192 ;
    END
  END b[184]
  PIN b[185]
    DIRECTION OUTPUT ;
    USE SIGNAL ;
    PORT
      LAYER M5 ;
        RECT  9.504 0 9.528 0.192 ;
    END
  END b[185]
  PIN b[186]
    DIRECTION OUTPUT ;
    USE SIGNAL ;
    PORT
      LAYER M5 ;
        RECT  9.552 0 9.576 0.192 ;
    END
  END b[186]
  PIN b[187]
    DIRECTION OUTPUT ;
    USE SIGNAL ;
    PORT
      LAYER M5 ;
        RECT  9.6 0 9.624 0.192 ;
    END
  END b[187]
  PIN b[188]
    DIRECTION OUTPUT ;
    USE SIGNAL ;
    PORT
      LAYER M5 ;
        RECT  9.648 0 9.672 0.192 ;
    END
  END b[188]
  PIN b[189]
    DIRECTION OUTPUT ;
    USE SIGNAL ;
    PORT
      LAYER M5 ;
        RECT  9.696 0 9.72 0.192 ;
    END
  END b[189]
  PIN b[18]
    DIRECTION OUTPUT ;
    USE SIGNAL ;
    PORT
      LAYER M5 ;
        RECT  1.488 0 1.512 0.192 ;
    END
  END b[18]
  PIN b[190]
    DIRECTION OUTPUT ;
    USE SIGNAL ;
    PORT
      LAYER M5 ;
        RECT  9.744 0 9.768 0.192 ;
    END
  END b[190]
  PIN b[191]
    DIRECTION OUTPUT ;
    USE SIGNAL ;
    PORT
      LAYER M5 ;
        RECT  9.792 0 9.816 0.192 ;
    END
  END b[191]
  PIN b[192]
    DIRECTION OUTPUT ;
    USE SIGNAL ;
    PORT
      LAYER M5 ;
        RECT  9.84 0 9.864 0.192 ;
    END
  END b[192]
  PIN b[193]
    DIRECTION OUTPUT ;
    USE SIGNAL ;
    PORT
      LAYER M5 ;
        RECT  9.888 0 9.912 0.192 ;
    END
  END b[193]
  PIN b[194]
    DIRECTION OUTPUT ;
    USE SIGNAL ;
    PORT
      LAYER M5 ;
        RECT  9.936 0 9.96 0.192 ;
    END
  END b[194]
  PIN b[195]
    DIRECTION OUTPUT ;
    USE SIGNAL ;
    PORT
      LAYER M5 ;
        RECT  9.984 0 10.008 0.192 ;
    END
  END b[195]
  PIN b[196]
    DIRECTION OUTPUT ;
    USE SIGNAL ;
    PORT
      LAYER M5 ;
        RECT  10.032 0 10.056 0.192 ;
    END
  END b[196]
  PIN b[197]
    DIRECTION OUTPUT ;
    USE SIGNAL ;
    PORT
      LAYER M5 ;
        RECT  10.08 0 10.104 0.192 ;
    END
  END b[197]
  PIN b[198]
    DIRECTION OUTPUT ;
    USE SIGNAL ;
    PORT
      LAYER M5 ;
        RECT  10.128 0 10.152 0.192 ;
    END
  END b[198]
  PIN b[199]
    DIRECTION OUTPUT ;
    USE SIGNAL ;
    PORT
      LAYER M5 ;
        RECT  10.176 0 10.2 0.192 ;
    END
  END b[199]
  PIN b[19]
    DIRECTION OUTPUT ;
    USE SIGNAL ;
    PORT
      LAYER M5 ;
        RECT  1.536 0 1.56 0.192 ;
    END
  END b[19]
  PIN b[1]
    DIRECTION OUTPUT ;
    USE SIGNAL ;
    PORT
      LAYER M5 ;
        RECT  0.672 0 0.696 0.192 ;
    END
  END b[1]
  PIN b[200]
    DIRECTION OUTPUT ;
    USE SIGNAL ;
    PORT
      LAYER M5 ;
        RECT  10.224 0 10.248 0.192 ;
    END
  END b[200]
  PIN b[201]
    DIRECTION OUTPUT ;
    USE SIGNAL ;
    PORT
      LAYER M5 ;
        RECT  10.272 0 10.296 0.192 ;
    END
  END b[201]
  PIN b[202]
    DIRECTION OUTPUT ;
    USE SIGNAL ;
    PORT
      LAYER M5 ;
        RECT  10.32 0 10.344 0.192 ;
    END
  END b[202]
  PIN b[203]
    DIRECTION OUTPUT ;
    USE SIGNAL ;
    PORT
      LAYER M5 ;
        RECT  10.368 0 10.392 0.192 ;
    END
  END b[203]
  PIN b[204]
    DIRECTION OUTPUT ;
    USE SIGNAL ;
    PORT
      LAYER M5 ;
        RECT  10.416 0 10.44 0.192 ;
    END
  END b[204]
  PIN b[205]
    DIRECTION OUTPUT ;
    USE SIGNAL ;
    PORT
      LAYER M5 ;
        RECT  10.464 0 10.488 0.192 ;
    END
  END b[205]
  PIN b[206]
    DIRECTION OUTPUT ;
    USE SIGNAL ;
    PORT
      LAYER M5 ;
        RECT  10.512 0 10.536 0.192 ;
    END
  END b[206]
  PIN b[207]
    DIRECTION OUTPUT ;
    USE SIGNAL ;
    PORT
      LAYER M5 ;
        RECT  10.56 0 10.584 0.192 ;
    END
  END b[207]
  PIN b[208]
    DIRECTION OUTPUT ;
    USE SIGNAL ;
    PORT
      LAYER M5 ;
        RECT  10.608 0 10.632 0.192 ;
    END
  END b[208]
  PIN b[209]
    DIRECTION OUTPUT ;
    USE SIGNAL ;
    PORT
      LAYER M5 ;
        RECT  10.656 0 10.68 0.192 ;
    END
  END b[209]
  PIN b[20]
    DIRECTION OUTPUT ;
    USE SIGNAL ;
    PORT
      LAYER M5 ;
        RECT  1.584 0 1.608 0.192 ;
    END
  END b[20]
  PIN b[210]
    DIRECTION OUTPUT ;
    USE SIGNAL ;
    PORT
      LAYER M5 ;
        RECT  10.704 0 10.728 0.192 ;
    END
  END b[210]
  PIN b[211]
    DIRECTION OUTPUT ;
    USE SIGNAL ;
    PORT
      LAYER M5 ;
        RECT  10.752 0 10.776 0.192 ;
    END
  END b[211]
  PIN b[212]
    DIRECTION OUTPUT ;
    USE SIGNAL ;
    PORT
      LAYER M5 ;
        RECT  10.8 0 10.824 0.192 ;
    END
  END b[212]
  PIN b[213]
    DIRECTION OUTPUT ;
    USE SIGNAL ;
    PORT
      LAYER M5 ;
        RECT  10.848 0 10.872 0.192 ;
    END
  END b[213]
  PIN b[214]
    DIRECTION OUTPUT ;
    USE SIGNAL ;
    PORT
      LAYER M5 ;
        RECT  10.896 0 10.92 0.192 ;
    END
  END b[214]
  PIN b[215]
    DIRECTION OUTPUT ;
    USE SIGNAL ;
    PORT
      LAYER M5 ;
        RECT  10.944 0 10.968 0.192 ;
    END
  END b[215]
  PIN b[216]
    DIRECTION OUTPUT ;
    USE SIGNAL ;
    PORT
      LAYER M5 ;
        RECT  10.992 0 11.016 0.192 ;
    END
  END b[216]
  PIN b[217]
    DIRECTION OUTPUT ;
    USE SIGNAL ;
    PORT
      LAYER M5 ;
        RECT  11.04 0 11.064 0.192 ;
    END
  END b[217]
  PIN b[218]
    DIRECTION OUTPUT ;
    USE SIGNAL ;
    PORT
      LAYER M5 ;
        RECT  11.088 0 11.112 0.192 ;
    END
  END b[218]
  PIN b[219]
    DIRECTION OUTPUT ;
    USE SIGNAL ;
    PORT
      LAYER M5 ;
        RECT  11.136 0 11.16 0.192 ;
    END
  END b[219]
  PIN b[21]
    DIRECTION OUTPUT ;
    USE SIGNAL ;
    PORT
      LAYER M5 ;
        RECT  1.632 0 1.656 0.192 ;
    END
  END b[21]
  PIN b[220]
    DIRECTION OUTPUT ;
    USE SIGNAL ;
    PORT
      LAYER M5 ;
        RECT  11.184 0 11.208 0.192 ;
    END
  END b[220]
  PIN b[221]
    DIRECTION OUTPUT ;
    USE SIGNAL ;
    PORT
      LAYER M5 ;
        RECT  11.232 0 11.256 0.192 ;
    END
  END b[221]
  PIN b[222]
    DIRECTION OUTPUT ;
    USE SIGNAL ;
    PORT
      LAYER M5 ;
        RECT  11.28 0 11.304 0.192 ;
    END
  END b[222]
  PIN b[223]
    DIRECTION OUTPUT ;
    USE SIGNAL ;
    PORT
      LAYER M5 ;
        RECT  11.328 0 11.352 0.192 ;
    END
  END b[223]
  PIN b[224]
    DIRECTION OUTPUT ;
    USE SIGNAL ;
    PORT
      LAYER M5 ;
        RECT  11.376 0 11.4 0.192 ;
    END
  END b[224]
  PIN b[225]
    DIRECTION OUTPUT ;
    USE SIGNAL ;
    PORT
      LAYER M5 ;
        RECT  11.424 0 11.448 0.192 ;
    END
  END b[225]
  PIN b[226]
    DIRECTION OUTPUT ;
    USE SIGNAL ;
    PORT
      LAYER M5 ;
        RECT  11.472 0 11.496 0.192 ;
    END
  END b[226]
  PIN b[227]
    DIRECTION OUTPUT ;
    USE SIGNAL ;
    PORT
      LAYER M5 ;
        RECT  11.52 0 11.544 0.192 ;
    END
  END b[227]
  PIN b[228]
    DIRECTION OUTPUT ;
    USE SIGNAL ;
    PORT
      LAYER M5 ;
        RECT  11.568 0 11.592 0.192 ;
    END
  END b[228]
  PIN b[229]
    DIRECTION OUTPUT ;
    USE SIGNAL ;
    PORT
      LAYER M5 ;
        RECT  11.616 0 11.64 0.192 ;
    END
  END b[229]
  PIN b[22]
    DIRECTION OUTPUT ;
    USE SIGNAL ;
    PORT
      LAYER M5 ;
        RECT  1.68 0 1.704 0.192 ;
    END
  END b[22]
  PIN b[230]
    DIRECTION OUTPUT ;
    USE SIGNAL ;
    PORT
      LAYER M5 ;
        RECT  11.664 0 11.688 0.192 ;
    END
  END b[230]
  PIN b[231]
    DIRECTION OUTPUT ;
    USE SIGNAL ;
    PORT
      LAYER M5 ;
        RECT  11.712 0 11.736 0.192 ;
    END
  END b[231]
  PIN b[232]
    DIRECTION OUTPUT ;
    USE SIGNAL ;
    PORT
      LAYER M5 ;
        RECT  11.76 0 11.784 0.192 ;
    END
  END b[232]
  PIN b[233]
    DIRECTION OUTPUT ;
    USE SIGNAL ;
    PORT
      LAYER M5 ;
        RECT  11.808 0 11.832 0.192 ;
    END
  END b[233]
  PIN b[234]
    DIRECTION OUTPUT ;
    USE SIGNAL ;
    PORT
      LAYER M5 ;
        RECT  11.856 0 11.88 0.192 ;
    END
  END b[234]
  PIN b[235]
    DIRECTION OUTPUT ;
    USE SIGNAL ;
    PORT
      LAYER M5 ;
        RECT  11.904 0 11.928 0.192 ;
    END
  END b[235]
  PIN b[236]
    DIRECTION OUTPUT ;
    USE SIGNAL ;
    PORT
      LAYER M5 ;
        RECT  11.952 0 11.976 0.192 ;
    END
  END b[236]
  PIN b[237]
    DIRECTION OUTPUT ;
    USE SIGNAL ;
    PORT
      LAYER M5 ;
        RECT  12 0 12.024 0.192 ;
    END
  END b[237]
  PIN b[238]
    DIRECTION OUTPUT ;
    USE SIGNAL ;
    PORT
      LAYER M5 ;
        RECT  12.048 0 12.072 0.192 ;
    END
  END b[238]
  PIN b[239]
    DIRECTION OUTPUT ;
    USE SIGNAL ;
    PORT
      LAYER M5 ;
        RECT  12.096 0 12.12 0.192 ;
    END
  END b[239]
  PIN b[23]
    DIRECTION OUTPUT ;
    USE SIGNAL ;
    PORT
      LAYER M5 ;
        RECT  1.728 0 1.752 0.192 ;
    END
  END b[23]
  PIN b[240]
    DIRECTION OUTPUT ;
    USE SIGNAL ;
    PORT
      LAYER M5 ;
        RECT  12.144 0 12.168 0.192 ;
    END
  END b[240]
  PIN b[241]
    DIRECTION OUTPUT ;
    USE SIGNAL ;
    PORT
      LAYER M5 ;
        RECT  12.192 0 12.216 0.192 ;
    END
  END b[241]
  PIN b[242]
    DIRECTION OUTPUT ;
    USE SIGNAL ;
    PORT
      LAYER M5 ;
        RECT  12.24 0 12.264 0.192 ;
    END
  END b[242]
  PIN b[243]
    DIRECTION OUTPUT ;
    USE SIGNAL ;
    PORT
      LAYER M5 ;
        RECT  12.288 0 12.312 0.192 ;
    END
  END b[243]
  PIN b[244]
    DIRECTION OUTPUT ;
    USE SIGNAL ;
    PORT
      LAYER M5 ;
        RECT  12.336 0 12.36 0.192 ;
    END
  END b[244]
  PIN b[245]
    DIRECTION OUTPUT ;
    USE SIGNAL ;
    PORT
      LAYER M5 ;
        RECT  12.384 0 12.408 0.192 ;
    END
  END b[245]
  PIN b[246]
    DIRECTION OUTPUT ;
    USE SIGNAL ;
    PORT
      LAYER M5 ;
        RECT  12.432 0 12.456 0.192 ;
    END
  END b[246]
  PIN b[247]
    DIRECTION OUTPUT ;
    USE SIGNAL ;
    PORT
      LAYER M5 ;
        RECT  12.48 0 12.504 0.192 ;
    END
  END b[247]
  PIN b[248]
    DIRECTION OUTPUT ;
    USE SIGNAL ;
    PORT
      LAYER M5 ;
        RECT  12.528 0 12.552 0.192 ;
    END
  END b[248]
  PIN b[249]
    DIRECTION OUTPUT ;
    USE SIGNAL ;
    PORT
      LAYER M5 ;
        RECT  12.576 0 12.6 0.192 ;
    END
  END b[249]
  PIN b[24]
    DIRECTION OUTPUT ;
    USE SIGNAL ;
    PORT
      LAYER M5 ;
        RECT  1.776 0 1.8 0.192 ;
    END
  END b[24]
  PIN b[250]
    DIRECTION OUTPUT ;
    USE SIGNAL ;
    PORT
      LAYER M5 ;
        RECT  12.624 0 12.648 0.192 ;
    END
  END b[250]
  PIN b[251]
    DIRECTION OUTPUT ;
    USE SIGNAL ;
    PORT
      LAYER M5 ;
        RECT  12.672 0 12.696 0.192 ;
    END
  END b[251]
  PIN b[252]
    DIRECTION OUTPUT ;
    USE SIGNAL ;
    PORT
      LAYER M5 ;
        RECT  12.72 0 12.744 0.192 ;
    END
  END b[252]
  PIN b[253]
    DIRECTION OUTPUT ;
    USE SIGNAL ;
    PORT
      LAYER M5 ;
        RECT  12.768 0 12.792 0.192 ;
    END
  END b[253]
  PIN b[254]
    DIRECTION OUTPUT ;
    USE SIGNAL ;
    PORT
      LAYER M5 ;
        RECT  12.816 0 12.84 0.192 ;
    END
  END b[254]
  PIN b[255]
    DIRECTION OUTPUT ;
    USE SIGNAL ;
    PORT
      LAYER M5 ;
        RECT  12.864 0 12.888 0.192 ;
    END
  END b[255]
  PIN b[256]
    DIRECTION OUTPUT ;
    USE SIGNAL ;
    PORT
      LAYER M5 ;
        RECT  12.912 0 12.936 0.192 ;
    END
  END b[256]
  PIN b[257]
    DIRECTION OUTPUT ;
    USE SIGNAL ;
    PORT
      LAYER M5 ;
        RECT  12.96 0 12.984 0.192 ;
    END
  END b[257]
  PIN b[258]
    DIRECTION OUTPUT ;
    USE SIGNAL ;
    PORT
      LAYER M5 ;
        RECT  13.008 0 13.032 0.192 ;
    END
  END b[258]
  PIN b[259]
    DIRECTION OUTPUT ;
    USE SIGNAL ;
    PORT
      LAYER M5 ;
        RECT  13.056 0 13.08 0.192 ;
    END
  END b[259]
  PIN b[25]
    DIRECTION OUTPUT ;
    USE SIGNAL ;
    PORT
      LAYER M5 ;
        RECT  1.824 0 1.848 0.192 ;
    END
  END b[25]
  PIN b[260]
    DIRECTION OUTPUT ;
    USE SIGNAL ;
    PORT
      LAYER M5 ;
        RECT  13.104 0 13.128 0.192 ;
    END
  END b[260]
  PIN b[261]
    DIRECTION OUTPUT ;
    USE SIGNAL ;
    PORT
      LAYER M5 ;
        RECT  13.152 0 13.176 0.192 ;
    END
  END b[261]
  PIN b[262]
    DIRECTION OUTPUT ;
    USE SIGNAL ;
    PORT
      LAYER M5 ;
        RECT  13.2 0 13.224 0.192 ;
    END
  END b[262]
  PIN b[263]
    DIRECTION OUTPUT ;
    USE SIGNAL ;
    PORT
      LAYER M5 ;
        RECT  13.248 0 13.272 0.192 ;
    END
  END b[263]
  PIN b[264]
    DIRECTION OUTPUT ;
    USE SIGNAL ;
    PORT
      LAYER M5 ;
        RECT  13.296 0 13.32 0.192 ;
    END
  END b[264]
  PIN b[265]
    DIRECTION OUTPUT ;
    USE SIGNAL ;
    PORT
      LAYER M5 ;
        RECT  13.344 0 13.368 0.192 ;
    END
  END b[265]
  PIN b[266]
    DIRECTION OUTPUT ;
    USE SIGNAL ;
    PORT
      LAYER M5 ;
        RECT  13.392 0 13.416 0.192 ;
    END
  END b[266]
  PIN b[267]
    DIRECTION OUTPUT ;
    USE SIGNAL ;
    PORT
      LAYER M5 ;
        RECT  13.44 0 13.464 0.192 ;
    END
  END b[267]
  PIN b[268]
    DIRECTION OUTPUT ;
    USE SIGNAL ;
    PORT
      LAYER M5 ;
        RECT  13.488 0 13.512 0.192 ;
    END
  END b[268]
  PIN b[269]
    DIRECTION OUTPUT ;
    USE SIGNAL ;
    PORT
      LAYER M5 ;
        RECT  13.536 0 13.56 0.192 ;
    END
  END b[269]
  PIN b[26]
    DIRECTION OUTPUT ;
    USE SIGNAL ;
    PORT
      LAYER M5 ;
        RECT  1.872 0 1.896 0.192 ;
    END
  END b[26]
  PIN b[270]
    DIRECTION OUTPUT ;
    USE SIGNAL ;
    PORT
      LAYER M5 ;
        RECT  13.584 0 13.608 0.192 ;
    END
  END b[270]
  PIN b[271]
    DIRECTION OUTPUT ;
    USE SIGNAL ;
    PORT
      LAYER M5 ;
        RECT  13.632 0 13.656 0.192 ;
    END
  END b[271]
  PIN b[272]
    DIRECTION OUTPUT ;
    USE SIGNAL ;
    PORT
      LAYER M5 ;
        RECT  13.68 0 13.704 0.192 ;
    END
  END b[272]
  PIN b[273]
    DIRECTION OUTPUT ;
    USE SIGNAL ;
    PORT
      LAYER M5 ;
        RECT  13.728 0 13.752 0.192 ;
    END
  END b[273]
  PIN b[274]
    DIRECTION OUTPUT ;
    USE SIGNAL ;
    PORT
      LAYER M5 ;
        RECT  13.776 0 13.8 0.192 ;
    END
  END b[274]
  PIN b[275]
    DIRECTION OUTPUT ;
    USE SIGNAL ;
    PORT
      LAYER M5 ;
        RECT  13.824 0 13.848 0.192 ;
    END
  END b[275]
  PIN b[276]
    DIRECTION OUTPUT ;
    USE SIGNAL ;
    PORT
      LAYER M5 ;
        RECT  13.872 0 13.896 0.192 ;
    END
  END b[276]
  PIN b[277]
    DIRECTION OUTPUT ;
    USE SIGNAL ;
    PORT
      LAYER M5 ;
        RECT  13.92 0 13.944 0.192 ;
    END
  END b[277]
  PIN b[278]
    DIRECTION OUTPUT ;
    USE SIGNAL ;
    PORT
      LAYER M5 ;
        RECT  13.968 0 13.992 0.192 ;
    END
  END b[278]
  PIN b[279]
    DIRECTION OUTPUT ;
    USE SIGNAL ;
    PORT
      LAYER M5 ;
        RECT  14.016 0 14.04 0.192 ;
    END
  END b[279]
  PIN b[27]
    DIRECTION OUTPUT ;
    USE SIGNAL ;
    PORT
      LAYER M5 ;
        RECT  1.92 0 1.944 0.192 ;
    END
  END b[27]
  PIN b[280]
    DIRECTION OUTPUT ;
    USE SIGNAL ;
    PORT
      LAYER M5 ;
        RECT  14.064 0 14.088 0.192 ;
    END
  END b[280]
  PIN b[281]
    DIRECTION OUTPUT ;
    USE SIGNAL ;
    PORT
      LAYER M5 ;
        RECT  14.112 0 14.136 0.192 ;
    END
  END b[281]
  PIN b[282]
    DIRECTION OUTPUT ;
    USE SIGNAL ;
    PORT
      LAYER M5 ;
        RECT  14.16 0 14.184 0.192 ;
    END
  END b[282]
  PIN b[283]
    DIRECTION OUTPUT ;
    USE SIGNAL ;
    PORT
      LAYER M5 ;
        RECT  14.208 0 14.232 0.192 ;
    END
  END b[283]
  PIN b[284]
    DIRECTION OUTPUT ;
    USE SIGNAL ;
    PORT
      LAYER M5 ;
        RECT  14.256 0 14.28 0.192 ;
    END
  END b[284]
  PIN b[285]
    DIRECTION OUTPUT ;
    USE SIGNAL ;
    PORT
      LAYER M5 ;
        RECT  14.304 0 14.328 0.192 ;
    END
  END b[285]
  PIN b[286]
    DIRECTION OUTPUT ;
    USE SIGNAL ;
    PORT
      LAYER M5 ;
        RECT  14.352 0 14.376 0.192 ;
    END
  END b[286]
  PIN b[287]
    DIRECTION OUTPUT ;
    USE SIGNAL ;
    PORT
      LAYER M5 ;
        RECT  14.4 0 14.424 0.192 ;
    END
  END b[287]
  PIN b[288]
    DIRECTION OUTPUT ;
    USE SIGNAL ;
    PORT
      LAYER M5 ;
        RECT  14.448 0 14.472 0.192 ;
    END
  END b[288]
  PIN b[289]
    DIRECTION OUTPUT ;
    USE SIGNAL ;
    PORT
      LAYER M5 ;
        RECT  14.496 0 14.52 0.192 ;
    END
  END b[289]
  PIN b[28]
    DIRECTION OUTPUT ;
    USE SIGNAL ;
    PORT
      LAYER M5 ;
        RECT  1.968 0 1.992 0.192 ;
    END
  END b[28]
  PIN b[290]
    DIRECTION OUTPUT ;
    USE SIGNAL ;
    PORT
      LAYER M5 ;
        RECT  14.544 0 14.568 0.192 ;
    END
  END b[290]
  PIN b[291]
    DIRECTION OUTPUT ;
    USE SIGNAL ;
    PORT
      LAYER M5 ;
        RECT  14.592 0 14.616 0.192 ;
    END
  END b[291]
  PIN b[292]
    DIRECTION OUTPUT ;
    USE SIGNAL ;
    PORT
      LAYER M5 ;
        RECT  14.64 0 14.664 0.192 ;
    END
  END b[292]
  PIN b[293]
    DIRECTION OUTPUT ;
    USE SIGNAL ;
    PORT
      LAYER M5 ;
        RECT  14.688 0 14.712 0.192 ;
    END
  END b[293]
  PIN b[294]
    DIRECTION OUTPUT ;
    USE SIGNAL ;
    PORT
      LAYER M5 ;
        RECT  14.736 0 14.76 0.192 ;
    END
  END b[294]
  PIN b[295]
    DIRECTION OUTPUT ;
    USE SIGNAL ;
    PORT
      LAYER M5 ;
        RECT  14.784 0 14.808 0.192 ;
    END
  END b[295]
  PIN b[296]
    DIRECTION OUTPUT ;
    USE SIGNAL ;
    PORT
      LAYER M5 ;
        RECT  14.832 0 14.856 0.192 ;
    END
  END b[296]
  PIN b[297]
    DIRECTION OUTPUT ;
    USE SIGNAL ;
    PORT
      LAYER M5 ;
        RECT  14.88 0 14.904 0.192 ;
    END
  END b[297]
  PIN b[298]
    DIRECTION OUTPUT ;
    USE SIGNAL ;
    PORT
      LAYER M5 ;
        RECT  14.928 0 14.952 0.192 ;
    END
  END b[298]
  PIN b[299]
    DIRECTION OUTPUT ;
    USE SIGNAL ;
    PORT
      LAYER M5 ;
        RECT  14.976 0 15 0.192 ;
    END
  END b[299]
  PIN b[29]
    DIRECTION OUTPUT ;
    USE SIGNAL ;
    PORT
      LAYER M5 ;
        RECT  2.016 0 2.04 0.192 ;
    END
  END b[29]
  PIN b[2]
    DIRECTION OUTPUT ;
    USE SIGNAL ;
    PORT
      LAYER M5 ;
        RECT  0.72 0 0.744 0.192 ;
    END
  END b[2]
  PIN b[300]
    DIRECTION OUTPUT ;
    USE SIGNAL ;
    PORT
      LAYER M5 ;
        RECT  15.024 0 15.048 0.192 ;
    END
  END b[300]
  PIN b[301]
    DIRECTION OUTPUT ;
    USE SIGNAL ;
    PORT
      LAYER M5 ;
        RECT  15.072 0 15.096 0.192 ;
    END
  END b[301]
  PIN b[302]
    DIRECTION OUTPUT ;
    USE SIGNAL ;
    PORT
      LAYER M5 ;
        RECT  15.12 0 15.144 0.192 ;
    END
  END b[302]
  PIN b[303]
    DIRECTION OUTPUT ;
    USE SIGNAL ;
    PORT
      LAYER M5 ;
        RECT  15.168 0 15.192 0.192 ;
    END
  END b[303]
  PIN b[304]
    DIRECTION OUTPUT ;
    USE SIGNAL ;
    PORT
      LAYER M5 ;
        RECT  15.216 0 15.24 0.192 ;
    END
  END b[304]
  PIN b[305]
    DIRECTION OUTPUT ;
    USE SIGNAL ;
    PORT
      LAYER M5 ;
        RECT  15.264 0 15.288 0.192 ;
    END
  END b[305]
  PIN b[306]
    DIRECTION OUTPUT ;
    USE SIGNAL ;
    PORT
      LAYER M5 ;
        RECT  15.312 0 15.336 0.192 ;
    END
  END b[306]
  PIN b[307]
    DIRECTION OUTPUT ;
    USE SIGNAL ;
    PORT
      LAYER M5 ;
        RECT  15.36 0 15.384 0.192 ;
    END
  END b[307]
  PIN b[308]
    DIRECTION OUTPUT ;
    USE SIGNAL ;
    PORT
      LAYER M5 ;
        RECT  15.408 0 15.432 0.192 ;
    END
  END b[308]
  PIN b[309]
    DIRECTION OUTPUT ;
    USE SIGNAL ;
    PORT
      LAYER M5 ;
        RECT  15.456 0 15.48 0.192 ;
    END
  END b[309]
  PIN b[30]
    DIRECTION OUTPUT ;
    USE SIGNAL ;
    PORT
      LAYER M5 ;
        RECT  2.064 0 2.088 0.192 ;
    END
  END b[30]
  PIN b[310]
    DIRECTION OUTPUT ;
    USE SIGNAL ;
    PORT
      LAYER M5 ;
        RECT  15.504 0 15.528 0.192 ;
    END
  END b[310]
  PIN b[311]
    DIRECTION OUTPUT ;
    USE SIGNAL ;
    PORT
      LAYER M5 ;
        RECT  15.552 0 15.576 0.192 ;
    END
  END b[311]
  PIN b[312]
    DIRECTION OUTPUT ;
    USE SIGNAL ;
    PORT
      LAYER M5 ;
        RECT  15.6 0 15.624 0.192 ;
    END
  END b[312]
  PIN b[313]
    DIRECTION OUTPUT ;
    USE SIGNAL ;
    PORT
      LAYER M5 ;
        RECT  15.648 0 15.672 0.192 ;
    END
  END b[313]
  PIN b[314]
    DIRECTION OUTPUT ;
    USE SIGNAL ;
    PORT
      LAYER M5 ;
        RECT  15.696 0 15.72 0.192 ;
    END
  END b[314]
  PIN b[315]
    DIRECTION OUTPUT ;
    USE SIGNAL ;
    PORT
      LAYER M5 ;
        RECT  15.744 0 15.768 0.192 ;
    END
  END b[315]
  PIN b[316]
    DIRECTION OUTPUT ;
    USE SIGNAL ;
    PORT
      LAYER M5 ;
        RECT  15.792 0 15.816 0.192 ;
    END
  END b[316]
  PIN b[317]
    DIRECTION OUTPUT ;
    USE SIGNAL ;
    PORT
      LAYER M5 ;
        RECT  15.84 0 15.864 0.192 ;
    END
  END b[317]
  PIN b[318]
    DIRECTION OUTPUT ;
    USE SIGNAL ;
    PORT
      LAYER M5 ;
        RECT  15.888 0 15.912 0.192 ;
    END
  END b[318]
  PIN b[319]
    DIRECTION OUTPUT ;
    USE SIGNAL ;
    PORT
      LAYER M5 ;
        RECT  15.936 0 15.96 0.192 ;
    END
  END b[319]
  PIN b[31]
    DIRECTION OUTPUT ;
    USE SIGNAL ;
    PORT
      LAYER M5 ;
        RECT  2.112 0 2.136 0.192 ;
    END
  END b[31]
  PIN b[320]
    DIRECTION OUTPUT ;
    USE SIGNAL ;
    PORT
      LAYER M5 ;
        RECT  15.984 0 16.008 0.192 ;
    END
  END b[320]
  PIN b[321]
    DIRECTION OUTPUT ;
    USE SIGNAL ;
    PORT
      LAYER M5 ;
        RECT  16.032 0 16.056 0.192 ;
    END
  END b[321]
  PIN b[322]
    DIRECTION OUTPUT ;
    USE SIGNAL ;
    PORT
      LAYER M5 ;
        RECT  16.08 0 16.104 0.192 ;
    END
  END b[322]
  PIN b[323]
    DIRECTION OUTPUT ;
    USE SIGNAL ;
    PORT
      LAYER M5 ;
        RECT  16.128 0 16.152 0.192 ;
    END
  END b[323]
  PIN b[324]
    DIRECTION OUTPUT ;
    USE SIGNAL ;
    PORT
      LAYER M5 ;
        RECT  16.176 0 16.2 0.192 ;
    END
  END b[324]
  PIN b[325]
    DIRECTION OUTPUT ;
    USE SIGNAL ;
    PORT
      LAYER M5 ;
        RECT  16.224 0 16.248 0.192 ;
    END
  END b[325]
  PIN b[326]
    DIRECTION OUTPUT ;
    USE SIGNAL ;
    PORT
      LAYER M5 ;
        RECT  16.272 0 16.296 0.192 ;
    END
  END b[326]
  PIN b[327]
    DIRECTION OUTPUT ;
    USE SIGNAL ;
    PORT
      LAYER M5 ;
        RECT  16.32 0 16.344 0.192 ;
    END
  END b[327]
  PIN b[328]
    DIRECTION OUTPUT ;
    USE SIGNAL ;
    PORT
      LAYER M5 ;
        RECT  16.368 0 16.392 0.192 ;
    END
  END b[328]
  PIN b[329]
    DIRECTION OUTPUT ;
    USE SIGNAL ;
    PORT
      LAYER M5 ;
        RECT  16.416 0 16.44 0.192 ;
    END
  END b[329]
  PIN b[32]
    DIRECTION OUTPUT ;
    USE SIGNAL ;
    PORT
      LAYER M5 ;
        RECT  2.16 0 2.184 0.192 ;
    END
  END b[32]
  PIN b[330]
    DIRECTION OUTPUT ;
    USE SIGNAL ;
    PORT
      LAYER M5 ;
        RECT  16.464 0 16.488 0.192 ;
    END
  END b[330]
  PIN b[331]
    DIRECTION OUTPUT ;
    USE SIGNAL ;
    PORT
      LAYER M5 ;
        RECT  16.512 0 16.536 0.192 ;
    END
  END b[331]
  PIN b[332]
    DIRECTION OUTPUT ;
    USE SIGNAL ;
    PORT
      LAYER M5 ;
        RECT  16.56 0 16.584 0.192 ;
    END
  END b[332]
  PIN b[333]
    DIRECTION OUTPUT ;
    USE SIGNAL ;
    PORT
      LAYER M5 ;
        RECT  16.608 0 16.632 0.192 ;
    END
  END b[333]
  PIN b[334]
    DIRECTION OUTPUT ;
    USE SIGNAL ;
    PORT
      LAYER M5 ;
        RECT  16.656 0 16.68 0.192 ;
    END
  END b[334]
  PIN b[335]
    DIRECTION OUTPUT ;
    USE SIGNAL ;
    PORT
      LAYER M5 ;
        RECT  16.704 0 16.728 0.192 ;
    END
  END b[335]
  PIN b[336]
    DIRECTION OUTPUT ;
    USE SIGNAL ;
    PORT
      LAYER M5 ;
        RECT  16.752 0 16.776 0.192 ;
    END
  END b[336]
  PIN b[337]
    DIRECTION OUTPUT ;
    USE SIGNAL ;
    PORT
      LAYER M5 ;
        RECT  16.8 0 16.824 0.192 ;
    END
  END b[337]
  PIN b[338]
    DIRECTION OUTPUT ;
    USE SIGNAL ;
    PORT
      LAYER M5 ;
        RECT  16.848 0 16.872 0.192 ;
    END
  END b[338]
  PIN b[339]
    DIRECTION OUTPUT ;
    USE SIGNAL ;
    PORT
      LAYER M5 ;
        RECT  16.896 0 16.92 0.192 ;
    END
  END b[339]
  PIN b[33]
    DIRECTION OUTPUT ;
    USE SIGNAL ;
    PORT
      LAYER M5 ;
        RECT  2.208 0 2.232 0.192 ;
    END
  END b[33]
  PIN b[340]
    DIRECTION OUTPUT ;
    USE SIGNAL ;
    PORT
      LAYER M5 ;
        RECT  16.944 0 16.968 0.192 ;
    END
  END b[340]
  PIN b[341]
    DIRECTION OUTPUT ;
    USE SIGNAL ;
    PORT
      LAYER M5 ;
        RECT  16.992 0 17.016 0.192 ;
    END
  END b[341]
  PIN b[342]
    DIRECTION OUTPUT ;
    USE SIGNAL ;
    PORT
      LAYER M5 ;
        RECT  17.04 0 17.064 0.192 ;
    END
  END b[342]
  PIN b[343]
    DIRECTION OUTPUT ;
    USE SIGNAL ;
    PORT
      LAYER M5 ;
        RECT  17.088 0 17.112 0.192 ;
    END
  END b[343]
  PIN b[344]
    DIRECTION OUTPUT ;
    USE SIGNAL ;
    PORT
      LAYER M5 ;
        RECT  17.136 0 17.16 0.192 ;
    END
  END b[344]
  PIN b[345]
    DIRECTION OUTPUT ;
    USE SIGNAL ;
    PORT
      LAYER M5 ;
        RECT  17.184 0 17.208 0.192 ;
    END
  END b[345]
  PIN b[346]
    DIRECTION OUTPUT ;
    USE SIGNAL ;
    PORT
      LAYER M5 ;
        RECT  17.232 0 17.256 0.192 ;
    END
  END b[346]
  PIN b[347]
    DIRECTION OUTPUT ;
    USE SIGNAL ;
    PORT
      LAYER M5 ;
        RECT  17.28 0 17.304 0.192 ;
    END
  END b[347]
  PIN b[348]
    DIRECTION OUTPUT ;
    USE SIGNAL ;
    PORT
      LAYER M5 ;
        RECT  17.328 0 17.352 0.192 ;
    END
  END b[348]
  PIN b[349]
    DIRECTION OUTPUT ;
    USE SIGNAL ;
    PORT
      LAYER M5 ;
        RECT  17.376 0 17.4 0.192 ;
    END
  END b[349]
  PIN b[34]
    DIRECTION OUTPUT ;
    USE SIGNAL ;
    PORT
      LAYER M5 ;
        RECT  2.256 0 2.28 0.192 ;
    END
  END b[34]
  PIN b[350]
    DIRECTION OUTPUT ;
    USE SIGNAL ;
    PORT
      LAYER M5 ;
        RECT  17.424 0 17.448 0.192 ;
    END
  END b[350]
  PIN b[351]
    DIRECTION OUTPUT ;
    USE SIGNAL ;
    PORT
      LAYER M5 ;
        RECT  17.472 0 17.496 0.192 ;
    END
  END b[351]
  PIN b[352]
    DIRECTION OUTPUT ;
    USE SIGNAL ;
    PORT
      LAYER M5 ;
        RECT  17.52 0 17.544 0.192 ;
    END
  END b[352]
  PIN b[353]
    DIRECTION OUTPUT ;
    USE SIGNAL ;
    PORT
      LAYER M5 ;
        RECT  17.568 0 17.592 0.192 ;
    END
  END b[353]
  PIN b[354]
    DIRECTION OUTPUT ;
    USE SIGNAL ;
    PORT
      LAYER M5 ;
        RECT  17.616 0 17.64 0.192 ;
    END
  END b[354]
  PIN b[355]
    DIRECTION OUTPUT ;
    USE SIGNAL ;
    PORT
      LAYER M5 ;
        RECT  17.664 0 17.688 0.192 ;
    END
  END b[355]
  PIN b[356]
    DIRECTION OUTPUT ;
    USE SIGNAL ;
    PORT
      LAYER M5 ;
        RECT  17.712 0 17.736 0.192 ;
    END
  END b[356]
  PIN b[357]
    DIRECTION OUTPUT ;
    USE SIGNAL ;
    PORT
      LAYER M5 ;
        RECT  17.76 0 17.784 0.192 ;
    END
  END b[357]
  PIN b[358]
    DIRECTION OUTPUT ;
    USE SIGNAL ;
    PORT
      LAYER M5 ;
        RECT  17.808 0 17.832 0.192 ;
    END
  END b[358]
  PIN b[359]
    DIRECTION OUTPUT ;
    USE SIGNAL ;
    PORT
      LAYER M5 ;
        RECT  17.856 0 17.88 0.192 ;
    END
  END b[359]
  PIN b[35]
    DIRECTION OUTPUT ;
    USE SIGNAL ;
    PORT
      LAYER M5 ;
        RECT  2.304 0 2.328 0.192 ;
    END
  END b[35]
  PIN b[360]
    DIRECTION OUTPUT ;
    USE SIGNAL ;
    PORT
      LAYER M5 ;
        RECT  17.904 0 17.928 0.192 ;
    END
  END b[360]
  PIN b[361]
    DIRECTION OUTPUT ;
    USE SIGNAL ;
    PORT
      LAYER M5 ;
        RECT  17.952 0 17.976 0.192 ;
    END
  END b[361]
  PIN b[362]
    DIRECTION OUTPUT ;
    USE SIGNAL ;
    PORT
      LAYER M5 ;
        RECT  18 0 18.024 0.192 ;
    END
  END b[362]
  PIN b[363]
    DIRECTION OUTPUT ;
    USE SIGNAL ;
    PORT
      LAYER M5 ;
        RECT  18.048 0 18.072 0.192 ;
    END
  END b[363]
  PIN b[364]
    DIRECTION OUTPUT ;
    USE SIGNAL ;
    PORT
      LAYER M5 ;
        RECT  18.096 0 18.12 0.192 ;
    END
  END b[364]
  PIN b[365]
    DIRECTION OUTPUT ;
    USE SIGNAL ;
    PORT
      LAYER M5 ;
        RECT  18.144 0 18.168 0.192 ;
    END
  END b[365]
  PIN b[366]
    DIRECTION OUTPUT ;
    USE SIGNAL ;
    PORT
      LAYER M5 ;
        RECT  18.192 0 18.216 0.192 ;
    END
  END b[366]
  PIN b[367]
    DIRECTION OUTPUT ;
    USE SIGNAL ;
    PORT
      LAYER M5 ;
        RECT  18.24 0 18.264 0.192 ;
    END
  END b[367]
  PIN b[368]
    DIRECTION OUTPUT ;
    USE SIGNAL ;
    PORT
      LAYER M5 ;
        RECT  18.288 0 18.312 0.192 ;
    END
  END b[368]
  PIN b[369]
    DIRECTION OUTPUT ;
    USE SIGNAL ;
    PORT
      LAYER M5 ;
        RECT  18.336 0 18.36 0.192 ;
    END
  END b[369]
  PIN b[36]
    DIRECTION OUTPUT ;
    USE SIGNAL ;
    PORT
      LAYER M5 ;
        RECT  2.352 0 2.376 0.192 ;
    END
  END b[36]
  PIN b[370]
    DIRECTION OUTPUT ;
    USE SIGNAL ;
    PORT
      LAYER M5 ;
        RECT  18.384 0 18.408 0.192 ;
    END
  END b[370]
  PIN b[371]
    DIRECTION OUTPUT ;
    USE SIGNAL ;
    PORT
      LAYER M5 ;
        RECT  18.432 0 18.456 0.192 ;
    END
  END b[371]
  PIN b[372]
    DIRECTION OUTPUT ;
    USE SIGNAL ;
    PORT
      LAYER M5 ;
        RECT  18.48 0 18.504 0.192 ;
    END
  END b[372]
  PIN b[373]
    DIRECTION OUTPUT ;
    USE SIGNAL ;
    PORT
      LAYER M5 ;
        RECT  18.528 0 18.552 0.192 ;
    END
  END b[373]
  PIN b[374]
    DIRECTION OUTPUT ;
    USE SIGNAL ;
    PORT
      LAYER M5 ;
        RECT  18.576 0 18.6 0.192 ;
    END
  END b[374]
  PIN b[375]
    DIRECTION OUTPUT ;
    USE SIGNAL ;
    PORT
      LAYER M5 ;
        RECT  18.624 0 18.648 0.192 ;
    END
  END b[375]
  PIN b[376]
    DIRECTION OUTPUT ;
    USE SIGNAL ;
    PORT
      LAYER M5 ;
        RECT  18.672 0 18.696 0.192 ;
    END
  END b[376]
  PIN b[377]
    DIRECTION OUTPUT ;
    USE SIGNAL ;
    PORT
      LAYER M5 ;
        RECT  18.72 0 18.744 0.192 ;
    END
  END b[377]
  PIN b[378]
    DIRECTION OUTPUT ;
    USE SIGNAL ;
    PORT
      LAYER M5 ;
        RECT  18.768 0 18.792 0.192 ;
    END
  END b[378]
  PIN b[379]
    DIRECTION OUTPUT ;
    USE SIGNAL ;
    PORT
      LAYER M5 ;
        RECT  18.816 0 18.84 0.192 ;
    END
  END b[379]
  PIN b[37]
    DIRECTION OUTPUT ;
    USE SIGNAL ;
    PORT
      LAYER M5 ;
        RECT  2.4 0 2.424 0.192 ;
    END
  END b[37]
  PIN b[380]
    DIRECTION OUTPUT ;
    USE SIGNAL ;
    PORT
      LAYER M5 ;
        RECT  18.864 0 18.888 0.192 ;
    END
  END b[380]
  PIN b[381]
    DIRECTION OUTPUT ;
    USE SIGNAL ;
    PORT
      LAYER M5 ;
        RECT  18.912 0 18.936 0.192 ;
    END
  END b[381]
  PIN b[382]
    DIRECTION OUTPUT ;
    USE SIGNAL ;
    PORT
      LAYER M5 ;
        RECT  18.96 0 18.984 0.192 ;
    END
  END b[382]
  PIN b[383]
    DIRECTION OUTPUT ;
    USE SIGNAL ;
    PORT
      LAYER M5 ;
        RECT  19.008 0 19.032 0.192 ;
    END
  END b[383]
  PIN b[384]
    DIRECTION OUTPUT ;
    USE SIGNAL ;
    PORT
      LAYER M5 ;
        RECT  19.056 0 19.08 0.192 ;
    END
  END b[384]
  PIN b[385]
    DIRECTION OUTPUT ;
    USE SIGNAL ;
    PORT
      LAYER M5 ;
        RECT  19.104 0 19.128 0.192 ;
    END
  END b[385]
  PIN b[386]
    DIRECTION OUTPUT ;
    USE SIGNAL ;
    PORT
      LAYER M5 ;
        RECT  19.152 0 19.176 0.192 ;
    END
  END b[386]
  PIN b[387]
    DIRECTION OUTPUT ;
    USE SIGNAL ;
    PORT
      LAYER M5 ;
        RECT  19.2 0 19.224 0.192 ;
    END
  END b[387]
  PIN b[388]
    DIRECTION OUTPUT ;
    USE SIGNAL ;
    PORT
      LAYER M5 ;
        RECT  19.248 0 19.272 0.192 ;
    END
  END b[388]
  PIN b[389]
    DIRECTION OUTPUT ;
    USE SIGNAL ;
    PORT
      LAYER M5 ;
        RECT  19.296 0 19.32 0.192 ;
    END
  END b[389]
  PIN b[38]
    DIRECTION OUTPUT ;
    USE SIGNAL ;
    PORT
      LAYER M5 ;
        RECT  2.448 0 2.472 0.192 ;
    END
  END b[38]
  PIN b[390]
    DIRECTION OUTPUT ;
    USE SIGNAL ;
    PORT
      LAYER M5 ;
        RECT  19.344 0 19.368 0.192 ;
    END
  END b[390]
  PIN b[391]
    DIRECTION OUTPUT ;
    USE SIGNAL ;
    PORT
      LAYER M5 ;
        RECT  19.392 0 19.416 0.192 ;
    END
  END b[391]
  PIN b[392]
    DIRECTION OUTPUT ;
    USE SIGNAL ;
    PORT
      LAYER M5 ;
        RECT  19.44 0 19.464 0.192 ;
    END
  END b[392]
  PIN b[393]
    DIRECTION OUTPUT ;
    USE SIGNAL ;
    PORT
      LAYER M5 ;
        RECT  19.488 0 19.512 0.192 ;
    END
  END b[393]
  PIN b[394]
    DIRECTION OUTPUT ;
    USE SIGNAL ;
    PORT
      LAYER M5 ;
        RECT  19.536 0 19.56 0.192 ;
    END
  END b[394]
  PIN b[395]
    DIRECTION OUTPUT ;
    USE SIGNAL ;
    PORT
      LAYER M5 ;
        RECT  19.584 0 19.608 0.192 ;
    END
  END b[395]
  PIN b[396]
    DIRECTION OUTPUT ;
    USE SIGNAL ;
    PORT
      LAYER M5 ;
        RECT  19.632 0 19.656 0.192 ;
    END
  END b[396]
  PIN b[397]
    DIRECTION OUTPUT ;
    USE SIGNAL ;
    PORT
      LAYER M5 ;
        RECT  19.68 0 19.704 0.192 ;
    END
  END b[397]
  PIN b[398]
    DIRECTION OUTPUT ;
    USE SIGNAL ;
    PORT
      LAYER M5 ;
        RECT  19.728 0 19.752 0.192 ;
    END
  END b[398]
  PIN b[399]
    DIRECTION OUTPUT ;
    USE SIGNAL ;
    PORT
      LAYER M5 ;
        RECT  19.776 0 19.8 0.192 ;
    END
  END b[399]
  PIN b[39]
    DIRECTION OUTPUT ;
    USE SIGNAL ;
    PORT
      LAYER M5 ;
        RECT  2.496 0 2.52 0.192 ;
    END
  END b[39]
  PIN b[3]
    DIRECTION OUTPUT ;
    USE SIGNAL ;
    PORT
      LAYER M5 ;
        RECT  0.768 0 0.792 0.192 ;
    END
  END b[3]
  PIN b[400]
    DIRECTION OUTPUT ;
    USE SIGNAL ;
    PORT
      LAYER M5 ;
        RECT  19.824 0 19.848 0.192 ;
    END
  END b[400]
  PIN b[401]
    DIRECTION OUTPUT ;
    USE SIGNAL ;
    PORT
      LAYER M5 ;
        RECT  19.872 0 19.896 0.192 ;
    END
  END b[401]
  PIN b[402]
    DIRECTION OUTPUT ;
    USE SIGNAL ;
    PORT
      LAYER M5 ;
        RECT  19.92 0 19.944 0.192 ;
    END
  END b[402]
  PIN b[403]
    DIRECTION OUTPUT ;
    USE SIGNAL ;
    PORT
      LAYER M5 ;
        RECT  19.968 0 19.992 0.192 ;
    END
  END b[403]
  PIN b[404]
    DIRECTION OUTPUT ;
    USE SIGNAL ;
    PORT
      LAYER M5 ;
        RECT  20.016 0 20.04 0.192 ;
    END
  END b[404]
  PIN b[405]
    DIRECTION OUTPUT ;
    USE SIGNAL ;
    PORT
      LAYER M5 ;
        RECT  20.064 0 20.088 0.192 ;
    END
  END b[405]
  PIN b[406]
    DIRECTION OUTPUT ;
    USE SIGNAL ;
    PORT
      LAYER M5 ;
        RECT  20.112 0 20.136 0.192 ;
    END
  END b[406]
  PIN b[407]
    DIRECTION OUTPUT ;
    USE SIGNAL ;
    PORT
      LAYER M5 ;
        RECT  20.16 0 20.184 0.192 ;
    END
  END b[407]
  PIN b[408]
    DIRECTION OUTPUT ;
    USE SIGNAL ;
    PORT
      LAYER M5 ;
        RECT  20.208 0 20.232 0.192 ;
    END
  END b[408]
  PIN b[409]
    DIRECTION OUTPUT ;
    USE SIGNAL ;
    PORT
      LAYER M5 ;
        RECT  20.256 0 20.28 0.192 ;
    END
  END b[409]
  PIN b[40]
    DIRECTION OUTPUT ;
    USE SIGNAL ;
    PORT
      LAYER M5 ;
        RECT  2.544 0 2.568 0.192 ;
    END
  END b[40]
  PIN b[410]
    DIRECTION OUTPUT ;
    USE SIGNAL ;
    PORT
      LAYER M5 ;
        RECT  20.304 0 20.328 0.192 ;
    END
  END b[410]
  PIN b[411]
    DIRECTION OUTPUT ;
    USE SIGNAL ;
    PORT
      LAYER M5 ;
        RECT  20.352 0 20.376 0.192 ;
    END
  END b[411]
  PIN b[412]
    DIRECTION OUTPUT ;
    USE SIGNAL ;
    PORT
      LAYER M5 ;
        RECT  20.4 0 20.424 0.192 ;
    END
  END b[412]
  PIN b[413]
    DIRECTION OUTPUT ;
    USE SIGNAL ;
    PORT
      LAYER M5 ;
        RECT  20.448 0 20.472 0.192 ;
    END
  END b[413]
  PIN b[414]
    DIRECTION OUTPUT ;
    USE SIGNAL ;
    PORT
      LAYER M5 ;
        RECT  20.496 0 20.52 0.192 ;
    END
  END b[414]
  PIN b[415]
    DIRECTION OUTPUT ;
    USE SIGNAL ;
    PORT
      LAYER M5 ;
        RECT  20.544 0 20.568 0.192 ;
    END
  END b[415]
  PIN b[416]
    DIRECTION OUTPUT ;
    USE SIGNAL ;
    PORT
      LAYER M5 ;
        RECT  20.592 0 20.616 0.192 ;
    END
  END b[416]
  PIN b[417]
    DIRECTION OUTPUT ;
    USE SIGNAL ;
    PORT
      LAYER M5 ;
        RECT  20.64 0 20.664 0.192 ;
    END
  END b[417]
  PIN b[418]
    DIRECTION OUTPUT ;
    USE SIGNAL ;
    PORT
      LAYER M5 ;
        RECT  20.688 0 20.712 0.192 ;
    END
  END b[418]
  PIN b[419]
    DIRECTION OUTPUT ;
    USE SIGNAL ;
    PORT
      LAYER M5 ;
        RECT  20.736 0 20.76 0.192 ;
    END
  END b[419]
  PIN b[41]
    DIRECTION OUTPUT ;
    USE SIGNAL ;
    PORT
      LAYER M5 ;
        RECT  2.592 0 2.616 0.192 ;
    END
  END b[41]
  PIN b[420]
    DIRECTION OUTPUT ;
    USE SIGNAL ;
    PORT
      LAYER M5 ;
        RECT  20.784 0 20.808 0.192 ;
    END
  END b[420]
  PIN b[421]
    DIRECTION OUTPUT ;
    USE SIGNAL ;
    PORT
      LAYER M5 ;
        RECT  20.832 0 20.856 0.192 ;
    END
  END b[421]
  PIN b[422]
    DIRECTION OUTPUT ;
    USE SIGNAL ;
    PORT
      LAYER M5 ;
        RECT  20.88 0 20.904 0.192 ;
    END
  END b[422]
  PIN b[423]
    DIRECTION OUTPUT ;
    USE SIGNAL ;
    PORT
      LAYER M5 ;
        RECT  20.928 0 20.952 0.192 ;
    END
  END b[423]
  PIN b[424]
    DIRECTION OUTPUT ;
    USE SIGNAL ;
    PORT
      LAYER M5 ;
        RECT  20.976 0 21 0.192 ;
    END
  END b[424]
  PIN b[425]
    DIRECTION OUTPUT ;
    USE SIGNAL ;
    PORT
      LAYER M5 ;
        RECT  21.024 0 21.048 0.192 ;
    END
  END b[425]
  PIN b[426]
    DIRECTION OUTPUT ;
    USE SIGNAL ;
    PORT
      LAYER M5 ;
        RECT  21.072 0 21.096 0.192 ;
    END
  END b[426]
  PIN b[427]
    DIRECTION OUTPUT ;
    USE SIGNAL ;
    PORT
      LAYER M5 ;
        RECT  21.12 0 21.144 0.192 ;
    END
  END b[427]
  PIN b[428]
    DIRECTION OUTPUT ;
    USE SIGNAL ;
    PORT
      LAYER M5 ;
        RECT  21.168 0 21.192 0.192 ;
    END
  END b[428]
  PIN b[429]
    DIRECTION OUTPUT ;
    USE SIGNAL ;
    PORT
      LAYER M5 ;
        RECT  21.216 0 21.24 0.192 ;
    END
  END b[429]
  PIN b[42]
    DIRECTION OUTPUT ;
    USE SIGNAL ;
    PORT
      LAYER M5 ;
        RECT  2.64 0 2.664 0.192 ;
    END
  END b[42]
  PIN b[430]
    DIRECTION OUTPUT ;
    USE SIGNAL ;
    PORT
      LAYER M5 ;
        RECT  21.264 0 21.288 0.192 ;
    END
  END b[430]
  PIN b[431]
    DIRECTION OUTPUT ;
    USE SIGNAL ;
    PORT
      LAYER M5 ;
        RECT  21.312 0 21.336 0.192 ;
    END
  END b[431]
  PIN b[432]
    DIRECTION OUTPUT ;
    USE SIGNAL ;
    PORT
      LAYER M5 ;
        RECT  21.36 0 21.384 0.192 ;
    END
  END b[432]
  PIN b[433]
    DIRECTION OUTPUT ;
    USE SIGNAL ;
    PORT
      LAYER M5 ;
        RECT  21.408 0 21.432 0.192 ;
    END
  END b[433]
  PIN b[434]
    DIRECTION OUTPUT ;
    USE SIGNAL ;
    PORT
      LAYER M5 ;
        RECT  21.456 0 21.48 0.192 ;
    END
  END b[434]
  PIN b[435]
    DIRECTION OUTPUT ;
    USE SIGNAL ;
    PORT
      LAYER M5 ;
        RECT  21.504 0 21.528 0.192 ;
    END
  END b[435]
  PIN b[436]
    DIRECTION OUTPUT ;
    USE SIGNAL ;
    PORT
      LAYER M5 ;
        RECT  21.552 0 21.576 0.192 ;
    END
  END b[436]
  PIN b[437]
    DIRECTION OUTPUT ;
    USE SIGNAL ;
    PORT
      LAYER M5 ;
        RECT  21.6 0 21.624 0.192 ;
    END
  END b[437]
  PIN b[438]
    DIRECTION OUTPUT ;
    USE SIGNAL ;
    PORT
      LAYER M5 ;
        RECT  21.648 0 21.672 0.192 ;
    END
  END b[438]
  PIN b[439]
    DIRECTION OUTPUT ;
    USE SIGNAL ;
    PORT
      LAYER M5 ;
        RECT  21.696 0 21.72 0.192 ;
    END
  END b[439]
  PIN b[43]
    DIRECTION OUTPUT ;
    USE SIGNAL ;
    PORT
      LAYER M5 ;
        RECT  2.688 0 2.712 0.192 ;
    END
  END b[43]
  PIN b[440]
    DIRECTION OUTPUT ;
    USE SIGNAL ;
    PORT
      LAYER M5 ;
        RECT  21.744 0 21.768 0.192 ;
    END
  END b[440]
  PIN b[441]
    DIRECTION OUTPUT ;
    USE SIGNAL ;
    PORT
      LAYER M5 ;
        RECT  21.792 0 21.816 0.192 ;
    END
  END b[441]
  PIN b[442]
    DIRECTION OUTPUT ;
    USE SIGNAL ;
    PORT
      LAYER M5 ;
        RECT  21.84 0 21.864 0.192 ;
    END
  END b[442]
  PIN b[443]
    DIRECTION OUTPUT ;
    USE SIGNAL ;
    PORT
      LAYER M5 ;
        RECT  21.888 0 21.912 0.192 ;
    END
  END b[443]
  PIN b[444]
    DIRECTION OUTPUT ;
    USE SIGNAL ;
    PORT
      LAYER M5 ;
        RECT  21.936 0 21.96 0.192 ;
    END
  END b[444]
  PIN b[445]
    DIRECTION OUTPUT ;
    USE SIGNAL ;
    PORT
      LAYER M5 ;
        RECT  21.984 0 22.008 0.192 ;
    END
  END b[445]
  PIN b[446]
    DIRECTION OUTPUT ;
    USE SIGNAL ;
    PORT
      LAYER M5 ;
        RECT  22.032 0 22.056 0.192 ;
    END
  END b[446]
  PIN b[447]
    DIRECTION OUTPUT ;
    USE SIGNAL ;
    PORT
      LAYER M5 ;
        RECT  22.08 0 22.104 0.192 ;
    END
  END b[447]
  PIN b[448]
    DIRECTION OUTPUT ;
    USE SIGNAL ;
    PORT
      LAYER M5 ;
        RECT  22.128 0 22.152 0.192 ;
    END
  END b[448]
  PIN b[449]
    DIRECTION OUTPUT ;
    USE SIGNAL ;
    PORT
      LAYER M5 ;
        RECT  22.176 0 22.2 0.192 ;
    END
  END b[449]
  PIN b[44]
    DIRECTION OUTPUT ;
    USE SIGNAL ;
    PORT
      LAYER M5 ;
        RECT  2.736 0 2.76 0.192 ;
    END
  END b[44]
  PIN b[450]
    DIRECTION OUTPUT ;
    USE SIGNAL ;
    PORT
      LAYER M5 ;
        RECT  22.224 0 22.248 0.192 ;
    END
  END b[450]
  PIN b[451]
    DIRECTION OUTPUT ;
    USE SIGNAL ;
    PORT
      LAYER M5 ;
        RECT  22.272 0 22.296 0.192 ;
    END
  END b[451]
  PIN b[452]
    DIRECTION OUTPUT ;
    USE SIGNAL ;
    PORT
      LAYER M5 ;
        RECT  22.32 0 22.344 0.192 ;
    END
  END b[452]
  PIN b[453]
    DIRECTION OUTPUT ;
    USE SIGNAL ;
    PORT
      LAYER M5 ;
        RECT  22.368 0 22.392 0.192 ;
    END
  END b[453]
  PIN b[454]
    DIRECTION OUTPUT ;
    USE SIGNAL ;
    PORT
      LAYER M5 ;
        RECT  22.416 0 22.44 0.192 ;
    END
  END b[454]
  PIN b[455]
    DIRECTION OUTPUT ;
    USE SIGNAL ;
    PORT
      LAYER M5 ;
        RECT  22.464 0 22.488 0.192 ;
    END
  END b[455]
  PIN b[456]
    DIRECTION OUTPUT ;
    USE SIGNAL ;
    PORT
      LAYER M5 ;
        RECT  22.512 0 22.536 0.192 ;
    END
  END b[456]
  PIN b[457]
    DIRECTION OUTPUT ;
    USE SIGNAL ;
    PORT
      LAYER M5 ;
        RECT  22.56 0 22.584 0.192 ;
    END
  END b[457]
  PIN b[458]
    DIRECTION OUTPUT ;
    USE SIGNAL ;
    PORT
      LAYER M5 ;
        RECT  22.608 0 22.632 0.192 ;
    END
  END b[458]
  PIN b[459]
    DIRECTION OUTPUT ;
    USE SIGNAL ;
    PORT
      LAYER M5 ;
        RECT  22.656 0 22.68 0.192 ;
    END
  END b[459]
  PIN b[45]
    DIRECTION OUTPUT ;
    USE SIGNAL ;
    PORT
      LAYER M5 ;
        RECT  2.784 0 2.808 0.192 ;
    END
  END b[45]
  PIN b[460]
    DIRECTION OUTPUT ;
    USE SIGNAL ;
    PORT
      LAYER M5 ;
        RECT  22.704 0 22.728 0.192 ;
    END
  END b[460]
  PIN b[461]
    DIRECTION OUTPUT ;
    USE SIGNAL ;
    PORT
      LAYER M5 ;
        RECT  22.752 0 22.776 0.192 ;
    END
  END b[461]
  PIN b[462]
    DIRECTION OUTPUT ;
    USE SIGNAL ;
    PORT
      LAYER M5 ;
        RECT  22.8 0 22.824 0.192 ;
    END
  END b[462]
  PIN b[463]
    DIRECTION OUTPUT ;
    USE SIGNAL ;
    PORT
      LAYER M5 ;
        RECT  22.848 0 22.872 0.192 ;
    END
  END b[463]
  PIN b[464]
    DIRECTION OUTPUT ;
    USE SIGNAL ;
    PORT
      LAYER M5 ;
        RECT  22.896 0 22.92 0.192 ;
    END
  END b[464]
  PIN b[465]
    DIRECTION OUTPUT ;
    USE SIGNAL ;
    PORT
      LAYER M5 ;
        RECT  22.944 0 22.968 0.192 ;
    END
  END b[465]
  PIN b[466]
    DIRECTION OUTPUT ;
    USE SIGNAL ;
    PORT
      LAYER M5 ;
        RECT  22.992 0 23.016 0.192 ;
    END
  END b[466]
  PIN b[467]
    DIRECTION OUTPUT ;
    USE SIGNAL ;
    PORT
      LAYER M5 ;
        RECT  23.04 0 23.064 0.192 ;
    END
  END b[467]
  PIN b[468]
    DIRECTION OUTPUT ;
    USE SIGNAL ;
    PORT
      LAYER M5 ;
        RECT  23.088 0 23.112 0.192 ;
    END
  END b[468]
  PIN b[469]
    DIRECTION OUTPUT ;
    USE SIGNAL ;
    PORT
      LAYER M5 ;
        RECT  23.136 0 23.16 0.192 ;
    END
  END b[469]
  PIN b[46]
    DIRECTION OUTPUT ;
    USE SIGNAL ;
    PORT
      LAYER M5 ;
        RECT  2.832 0 2.856 0.192 ;
    END
  END b[46]
  PIN b[470]
    DIRECTION OUTPUT ;
    USE SIGNAL ;
    PORT
      LAYER M5 ;
        RECT  23.184 0 23.208 0.192 ;
    END
  END b[470]
  PIN b[471]
    DIRECTION OUTPUT ;
    USE SIGNAL ;
    PORT
      LAYER M5 ;
        RECT  23.232 0 23.256 0.192 ;
    END
  END b[471]
  PIN b[472]
    DIRECTION OUTPUT ;
    USE SIGNAL ;
    PORT
      LAYER M5 ;
        RECT  23.28 0 23.304 0.192 ;
    END
  END b[472]
  PIN b[473]
    DIRECTION OUTPUT ;
    USE SIGNAL ;
    PORT
      LAYER M5 ;
        RECT  23.328 0 23.352 0.192 ;
    END
  END b[473]
  PIN b[474]
    DIRECTION OUTPUT ;
    USE SIGNAL ;
    PORT
      LAYER M5 ;
        RECT  23.376 0 23.4 0.192 ;
    END
  END b[474]
  PIN b[475]
    DIRECTION OUTPUT ;
    USE SIGNAL ;
    PORT
      LAYER M5 ;
        RECT  23.424 0 23.448 0.192 ;
    END
  END b[475]
  PIN b[476]
    DIRECTION OUTPUT ;
    USE SIGNAL ;
    PORT
      LAYER M5 ;
        RECT  23.472 0 23.496 0.192 ;
    END
  END b[476]
  PIN b[477]
    DIRECTION OUTPUT ;
    USE SIGNAL ;
    PORT
      LAYER M5 ;
        RECT  23.52 0 23.544 0.192 ;
    END
  END b[477]
  PIN b[478]
    DIRECTION OUTPUT ;
    USE SIGNAL ;
    PORT
      LAYER M5 ;
        RECT  23.568 0 23.592 0.192 ;
    END
  END b[478]
  PIN b[479]
    DIRECTION OUTPUT ;
    USE SIGNAL ;
    PORT
      LAYER M5 ;
        RECT  23.616 0 23.64 0.192 ;
    END
  END b[479]
  PIN b[47]
    DIRECTION OUTPUT ;
    USE SIGNAL ;
    PORT
      LAYER M5 ;
        RECT  2.88 0 2.904 0.192 ;
    END
  END b[47]
  PIN b[480]
    DIRECTION OUTPUT ;
    USE SIGNAL ;
    PORT
      LAYER M5 ;
        RECT  23.664 0 23.688 0.192 ;
    END
  END b[480]
  PIN b[481]
    DIRECTION OUTPUT ;
    USE SIGNAL ;
    PORT
      LAYER M5 ;
        RECT  23.712 0 23.736 0.192 ;
    END
  END b[481]
  PIN b[482]
    DIRECTION OUTPUT ;
    USE SIGNAL ;
    PORT
      LAYER M5 ;
        RECT  23.76 0 23.784 0.192 ;
    END
  END b[482]
  PIN b[483]
    DIRECTION OUTPUT ;
    USE SIGNAL ;
    PORT
      LAYER M5 ;
        RECT  23.808 0 23.832 0.192 ;
    END
  END b[483]
  PIN b[484]
    DIRECTION OUTPUT ;
    USE SIGNAL ;
    PORT
      LAYER M5 ;
        RECT  23.856 0 23.88 0.192 ;
    END
  END b[484]
  PIN b[485]
    DIRECTION OUTPUT ;
    USE SIGNAL ;
    PORT
      LAYER M5 ;
        RECT  23.904 0 23.928 0.192 ;
    END
  END b[485]
  PIN b[486]
    DIRECTION OUTPUT ;
    USE SIGNAL ;
    PORT
      LAYER M5 ;
        RECT  23.952 0 23.976 0.192 ;
    END
  END b[486]
  PIN b[487]
    DIRECTION OUTPUT ;
    USE SIGNAL ;
    PORT
      LAYER M5 ;
        RECT  24 0 24.024 0.192 ;
    END
  END b[487]
  PIN b[488]
    DIRECTION OUTPUT ;
    USE SIGNAL ;
    PORT
      LAYER M5 ;
        RECT  24.048 0 24.072 0.192 ;
    END
  END b[488]
  PIN b[489]
    DIRECTION OUTPUT ;
    USE SIGNAL ;
    PORT
      LAYER M5 ;
        RECT  24.096 0 24.12 0.192 ;
    END
  END b[489]
  PIN b[48]
    DIRECTION OUTPUT ;
    USE SIGNAL ;
    PORT
      LAYER M5 ;
        RECT  2.928 0 2.952 0.192 ;
    END
  END b[48]
  PIN b[490]
    DIRECTION OUTPUT ;
    USE SIGNAL ;
    PORT
      LAYER M5 ;
        RECT  24.144 0 24.168 0.192 ;
    END
  END b[490]
  PIN b[491]
    DIRECTION OUTPUT ;
    USE SIGNAL ;
    PORT
      LAYER M5 ;
        RECT  24.192 0 24.216 0.192 ;
    END
  END b[491]
  PIN b[492]
    DIRECTION OUTPUT ;
    USE SIGNAL ;
    PORT
      LAYER M5 ;
        RECT  24.24 0 24.264 0.192 ;
    END
  END b[492]
  PIN b[493]
    DIRECTION OUTPUT ;
    USE SIGNAL ;
    PORT
      LAYER M5 ;
        RECT  24.288 0 24.312 0.192 ;
    END
  END b[493]
  PIN b[494]
    DIRECTION OUTPUT ;
    USE SIGNAL ;
    PORT
      LAYER M5 ;
        RECT  24.336 0 24.36 0.192 ;
    END
  END b[494]
  PIN b[495]
    DIRECTION OUTPUT ;
    USE SIGNAL ;
    PORT
      LAYER M5 ;
        RECT  24.384 0 24.408 0.192 ;
    END
  END b[495]
  PIN b[496]
    DIRECTION OUTPUT ;
    USE SIGNAL ;
    PORT
      LAYER M5 ;
        RECT  24.432 0 24.456 0.192 ;
    END
  END b[496]
  PIN b[497]
    DIRECTION OUTPUT ;
    USE SIGNAL ;
    PORT
      LAYER M5 ;
        RECT  24.48 0 24.504 0.192 ;
    END
  END b[497]
  PIN b[498]
    DIRECTION OUTPUT ;
    USE SIGNAL ;
    PORT
      LAYER M5 ;
        RECT  24.528 0 24.552 0.192 ;
    END
  END b[498]
  PIN b[499]
    DIRECTION OUTPUT ;
    USE SIGNAL ;
    PORT
      LAYER M5 ;
        RECT  24.576 0 24.6 0.192 ;
    END
  END b[499]
  PIN b[49]
    DIRECTION OUTPUT ;
    USE SIGNAL ;
    PORT
      LAYER M5 ;
        RECT  2.976 0 3 0.192 ;
    END
  END b[49]
  PIN b[4]
    DIRECTION OUTPUT ;
    USE SIGNAL ;
    PORT
      LAYER M5 ;
        RECT  0.816 0 0.84 0.192 ;
    END
  END b[4]
  PIN b[500]
    DIRECTION OUTPUT ;
    USE SIGNAL ;
    PORT
      LAYER M5 ;
        RECT  24.624 0 24.648 0.192 ;
    END
  END b[500]
  PIN b[501]
    DIRECTION OUTPUT ;
    USE SIGNAL ;
    PORT
      LAYER M5 ;
        RECT  24.672 0 24.696 0.192 ;
    END
  END b[501]
  PIN b[502]
    DIRECTION OUTPUT ;
    USE SIGNAL ;
    PORT
      LAYER M5 ;
        RECT  24.72 0 24.744 0.192 ;
    END
  END b[502]
  PIN b[503]
    DIRECTION OUTPUT ;
    USE SIGNAL ;
    PORT
      LAYER M5 ;
        RECT  24.768 0 24.792 0.192 ;
    END
  END b[503]
  PIN b[504]
    DIRECTION OUTPUT ;
    USE SIGNAL ;
    PORT
      LAYER M5 ;
        RECT  24.816 0 24.84 0.192 ;
    END
  END b[504]
  PIN b[505]
    DIRECTION OUTPUT ;
    USE SIGNAL ;
    PORT
      LAYER M5 ;
        RECT  24.864 0 24.888 0.192 ;
    END
  END b[505]
  PIN b[506]
    DIRECTION OUTPUT ;
    USE SIGNAL ;
    PORT
      LAYER M5 ;
        RECT  24.912 0 24.936 0.192 ;
    END
  END b[506]
  PIN b[507]
    DIRECTION OUTPUT ;
    USE SIGNAL ;
    PORT
      LAYER M5 ;
        RECT  24.96 0 24.984 0.192 ;
    END
  END b[507]
  PIN b[508]
    DIRECTION OUTPUT ;
    USE SIGNAL ;
    PORT
      LAYER M5 ;
        RECT  25.008 0 25.032 0.192 ;
    END
  END b[508]
  PIN b[509]
    DIRECTION OUTPUT ;
    USE SIGNAL ;
    PORT
      LAYER M5 ;
        RECT  25.056 0 25.08 0.192 ;
    END
  END b[509]
  PIN b[50]
    DIRECTION OUTPUT ;
    USE SIGNAL ;
    PORT
      LAYER M5 ;
        RECT  3.024 0 3.048 0.192 ;
    END
  END b[50]
  PIN b[510]
    DIRECTION OUTPUT ;
    USE SIGNAL ;
    PORT
      LAYER M5 ;
        RECT  25.104 0 25.128 0.192 ;
    END
  END b[510]
  PIN b[511]
    DIRECTION OUTPUT ;
    USE SIGNAL ;
    PORT
      LAYER M5 ;
        RECT  25.152 0 25.176 0.192 ;
    END
  END b[511]
  PIN b[512]
    DIRECTION OUTPUT ;
    USE SIGNAL ;
    PORT
      LAYER M5 ;
        RECT  25.2 0 25.224 0.192 ;
    END
  END b[512]
  PIN b[513]
    DIRECTION OUTPUT ;
    USE SIGNAL ;
    PORT
      LAYER M5 ;
        RECT  25.248 0 25.272 0.192 ;
    END
  END b[513]
  PIN b[514]
    DIRECTION OUTPUT ;
    USE SIGNAL ;
    PORT
      LAYER M5 ;
        RECT  25.296 0 25.32 0.192 ;
    END
  END b[514]
  PIN b[515]
    DIRECTION OUTPUT ;
    USE SIGNAL ;
    PORT
      LAYER M5 ;
        RECT  25.344 0 25.368 0.192 ;
    END
  END b[515]
  PIN b[516]
    DIRECTION OUTPUT ;
    USE SIGNAL ;
    PORT
      LAYER M5 ;
        RECT  25.392 0 25.416 0.192 ;
    END
  END b[516]
  PIN b[517]
    DIRECTION OUTPUT ;
    USE SIGNAL ;
    PORT
      LAYER M5 ;
        RECT  25.44 0 25.464 0.192 ;
    END
  END b[517]
  PIN b[518]
    DIRECTION OUTPUT ;
    USE SIGNAL ;
    PORT
      LAYER M5 ;
        RECT  25.488 0 25.512 0.192 ;
    END
  END b[518]
  PIN b[519]
    DIRECTION OUTPUT ;
    USE SIGNAL ;
    PORT
      LAYER M5 ;
        RECT  25.536 0 25.56 0.192 ;
    END
  END b[519]
  PIN b[51]
    DIRECTION OUTPUT ;
    USE SIGNAL ;
    PORT
      LAYER M5 ;
        RECT  3.072 0 3.096 0.192 ;
    END
  END b[51]
  PIN b[520]
    DIRECTION OUTPUT ;
    USE SIGNAL ;
    PORT
      LAYER M5 ;
        RECT  25.584 0 25.608 0.192 ;
    END
  END b[520]
  PIN b[521]
    DIRECTION OUTPUT ;
    USE SIGNAL ;
    PORT
      LAYER M5 ;
        RECT  25.632 0 25.656 0.192 ;
    END
  END b[521]
  PIN b[522]
    DIRECTION OUTPUT ;
    USE SIGNAL ;
    PORT
      LAYER M5 ;
        RECT  25.68 0 25.704 0.192 ;
    END
  END b[522]
  PIN b[523]
    DIRECTION OUTPUT ;
    USE SIGNAL ;
    PORT
      LAYER M5 ;
        RECT  25.728 0 25.752 0.192 ;
    END
  END b[523]
  PIN b[524]
    DIRECTION OUTPUT ;
    USE SIGNAL ;
    PORT
      LAYER M5 ;
        RECT  25.776 0 25.8 0.192 ;
    END
  END b[524]
  PIN b[525]
    DIRECTION OUTPUT ;
    USE SIGNAL ;
    PORT
      LAYER M5 ;
        RECT  25.824 0 25.848 0.192 ;
    END
  END b[525]
  PIN b[526]
    DIRECTION OUTPUT ;
    USE SIGNAL ;
    PORT
      LAYER M5 ;
        RECT  25.872 0 25.896 0.192 ;
    END
  END b[526]
  PIN b[527]
    DIRECTION OUTPUT ;
    USE SIGNAL ;
    PORT
      LAYER M5 ;
        RECT  25.92 0 25.944 0.192 ;
    END
  END b[527]
  PIN b[528]
    DIRECTION OUTPUT ;
    USE SIGNAL ;
    PORT
      LAYER M5 ;
        RECT  25.968 0 25.992 0.192 ;
    END
  END b[528]
  PIN b[529]
    DIRECTION OUTPUT ;
    USE SIGNAL ;
    PORT
      LAYER M5 ;
        RECT  26.016 0 26.04 0.192 ;
    END
  END b[529]
  PIN b[52]
    DIRECTION OUTPUT ;
    USE SIGNAL ;
    PORT
      LAYER M5 ;
        RECT  3.12 0 3.144 0.192 ;
    END
  END b[52]
  PIN b[530]
    DIRECTION OUTPUT ;
    USE SIGNAL ;
    PORT
      LAYER M5 ;
        RECT  26.064 0 26.088 0.192 ;
    END
  END b[530]
  PIN b[531]
    DIRECTION OUTPUT ;
    USE SIGNAL ;
    PORT
      LAYER M5 ;
        RECT  26.112 0 26.136 0.192 ;
    END
  END b[531]
  PIN b[532]
    DIRECTION OUTPUT ;
    USE SIGNAL ;
    PORT
      LAYER M5 ;
        RECT  26.16 0 26.184 0.192 ;
    END
  END b[532]
  PIN b[533]
    DIRECTION OUTPUT ;
    USE SIGNAL ;
    PORT
      LAYER M5 ;
        RECT  26.208 0 26.232 0.192 ;
    END
  END b[533]
  PIN b[534]
    DIRECTION OUTPUT ;
    USE SIGNAL ;
    PORT
      LAYER M5 ;
        RECT  26.256 0 26.28 0.192 ;
    END
  END b[534]
  PIN b[535]
    DIRECTION OUTPUT ;
    USE SIGNAL ;
    PORT
      LAYER M5 ;
        RECT  26.304 0 26.328 0.192 ;
    END
  END b[535]
  PIN b[536]
    DIRECTION OUTPUT ;
    USE SIGNAL ;
    PORT
      LAYER M5 ;
        RECT  26.352 0 26.376 0.192 ;
    END
  END b[536]
  PIN b[537]
    DIRECTION OUTPUT ;
    USE SIGNAL ;
    PORT
      LAYER M5 ;
        RECT  26.4 0 26.424 0.192 ;
    END
  END b[537]
  PIN b[538]
    DIRECTION OUTPUT ;
    USE SIGNAL ;
    PORT
      LAYER M5 ;
        RECT  26.448 0 26.472 0.192 ;
    END
  END b[538]
  PIN b[539]
    DIRECTION OUTPUT ;
    USE SIGNAL ;
    PORT
      LAYER M5 ;
        RECT  26.496 0 26.52 0.192 ;
    END
  END b[539]
  PIN b[53]
    DIRECTION OUTPUT ;
    USE SIGNAL ;
    PORT
      LAYER M5 ;
        RECT  3.168 0 3.192 0.192 ;
    END
  END b[53]
  PIN b[540]
    DIRECTION OUTPUT ;
    USE SIGNAL ;
    PORT
      LAYER M5 ;
        RECT  26.544 0 26.568 0.192 ;
    END
  END b[540]
  PIN b[541]
    DIRECTION OUTPUT ;
    USE SIGNAL ;
    PORT
      LAYER M5 ;
        RECT  26.592 0 26.616 0.192 ;
    END
  END b[541]
  PIN b[542]
    DIRECTION OUTPUT ;
    USE SIGNAL ;
    PORT
      LAYER M5 ;
        RECT  26.64 0 26.664 0.192 ;
    END
  END b[542]
  PIN b[543]
    DIRECTION OUTPUT ;
    USE SIGNAL ;
    PORT
      LAYER M5 ;
        RECT  26.688 0 26.712 0.192 ;
    END
  END b[543]
  PIN b[544]
    DIRECTION OUTPUT ;
    USE SIGNAL ;
    PORT
      LAYER M5 ;
        RECT  26.736 0 26.76 0.192 ;
    END
  END b[544]
  PIN b[545]
    DIRECTION OUTPUT ;
    USE SIGNAL ;
    PORT
      LAYER M5 ;
        RECT  26.784 0 26.808 0.192 ;
    END
  END b[545]
  PIN b[546]
    DIRECTION OUTPUT ;
    USE SIGNAL ;
    PORT
      LAYER M5 ;
        RECT  26.832 0 26.856 0.192 ;
    END
  END b[546]
  PIN b[547]
    DIRECTION OUTPUT ;
    USE SIGNAL ;
    PORT
      LAYER M5 ;
        RECT  26.88 0 26.904 0.192 ;
    END
  END b[547]
  PIN b[548]
    DIRECTION OUTPUT ;
    USE SIGNAL ;
    PORT
      LAYER M5 ;
        RECT  26.928 0 26.952 0.192 ;
    END
  END b[548]
  PIN b[549]
    DIRECTION OUTPUT ;
    USE SIGNAL ;
    PORT
      LAYER M5 ;
        RECT  26.976 0 27 0.192 ;
    END
  END b[549]
  PIN b[54]
    DIRECTION OUTPUT ;
    USE SIGNAL ;
    PORT
      LAYER M5 ;
        RECT  3.216 0 3.24 0.192 ;
    END
  END b[54]
  PIN b[550]
    DIRECTION OUTPUT ;
    USE SIGNAL ;
    PORT
      LAYER M5 ;
        RECT  27.024 0 27.048 0.192 ;
    END
  END b[550]
  PIN b[551]
    DIRECTION OUTPUT ;
    USE SIGNAL ;
    PORT
      LAYER M5 ;
        RECT  27.072 0 27.096 0.192 ;
    END
  END b[551]
  PIN b[552]
    DIRECTION OUTPUT ;
    USE SIGNAL ;
    PORT
      LAYER M5 ;
        RECT  27.12 0 27.144 0.192 ;
    END
  END b[552]
  PIN b[553]
    DIRECTION OUTPUT ;
    USE SIGNAL ;
    PORT
      LAYER M5 ;
        RECT  27.168 0 27.192 0.192 ;
    END
  END b[553]
  PIN b[554]
    DIRECTION OUTPUT ;
    USE SIGNAL ;
    PORT
      LAYER M5 ;
        RECT  27.216 0 27.24 0.192 ;
    END
  END b[554]
  PIN b[555]
    DIRECTION OUTPUT ;
    USE SIGNAL ;
    PORT
      LAYER M5 ;
        RECT  27.264 0 27.288 0.192 ;
    END
  END b[555]
  PIN b[556]
    DIRECTION OUTPUT ;
    USE SIGNAL ;
    PORT
      LAYER M5 ;
        RECT  27.312 0 27.336 0.192 ;
    END
  END b[556]
  PIN b[557]
    DIRECTION OUTPUT ;
    USE SIGNAL ;
    PORT
      LAYER M5 ;
        RECT  27.36 0 27.384 0.192 ;
    END
  END b[557]
  PIN b[558]
    DIRECTION OUTPUT ;
    USE SIGNAL ;
    PORT
      LAYER M5 ;
        RECT  27.408 0 27.432 0.192 ;
    END
  END b[558]
  PIN b[559]
    DIRECTION OUTPUT ;
    USE SIGNAL ;
    PORT
      LAYER M5 ;
        RECT  27.456 0 27.48 0.192 ;
    END
  END b[559]
  PIN b[55]
    DIRECTION OUTPUT ;
    USE SIGNAL ;
    PORT
      LAYER M5 ;
        RECT  3.264 0 3.288 0.192 ;
    END
  END b[55]
  PIN b[560]
    DIRECTION OUTPUT ;
    USE SIGNAL ;
    PORT
      LAYER M5 ;
        RECT  27.504 0 27.528 0.192 ;
    END
  END b[560]
  PIN b[561]
    DIRECTION OUTPUT ;
    USE SIGNAL ;
    PORT
      LAYER M5 ;
        RECT  27.552 0 27.576 0.192 ;
    END
  END b[561]
  PIN b[562]
    DIRECTION OUTPUT ;
    USE SIGNAL ;
    PORT
      LAYER M5 ;
        RECT  27.6 0 27.624 0.192 ;
    END
  END b[562]
  PIN b[563]
    DIRECTION OUTPUT ;
    USE SIGNAL ;
    PORT
      LAYER M5 ;
        RECT  27.648 0 27.672 0.192 ;
    END
  END b[563]
  PIN b[564]
    DIRECTION OUTPUT ;
    USE SIGNAL ;
    PORT
      LAYER M5 ;
        RECT  27.696 0 27.72 0.192 ;
    END
  END b[564]
  PIN b[565]
    DIRECTION OUTPUT ;
    USE SIGNAL ;
    PORT
      LAYER M5 ;
        RECT  27.744 0 27.768 0.192 ;
    END
  END b[565]
  PIN b[566]
    DIRECTION OUTPUT ;
    USE SIGNAL ;
    PORT
      LAYER M5 ;
        RECT  27.792 0 27.816 0.192 ;
    END
  END b[566]
  PIN b[567]
    DIRECTION OUTPUT ;
    USE SIGNAL ;
    PORT
      LAYER M5 ;
        RECT  27.84 0 27.864 0.192 ;
    END
  END b[567]
  PIN b[568]
    DIRECTION OUTPUT ;
    USE SIGNAL ;
    PORT
      LAYER M5 ;
        RECT  27.888 0 27.912 0.192 ;
    END
  END b[568]
  PIN b[569]
    DIRECTION OUTPUT ;
    USE SIGNAL ;
    PORT
      LAYER M5 ;
        RECT  27.936 0 27.96 0.192 ;
    END
  END b[569]
  PIN b[56]
    DIRECTION OUTPUT ;
    USE SIGNAL ;
    PORT
      LAYER M5 ;
        RECT  3.312 0 3.336 0.192 ;
    END
  END b[56]
  PIN b[570]
    DIRECTION OUTPUT ;
    USE SIGNAL ;
    PORT
      LAYER M5 ;
        RECT  27.984 0 28.008 0.192 ;
    END
  END b[570]
  PIN b[571]
    DIRECTION OUTPUT ;
    USE SIGNAL ;
    PORT
      LAYER M5 ;
        RECT  28.032 0 28.056 0.192 ;
    END
  END b[571]
  PIN b[572]
    DIRECTION OUTPUT ;
    USE SIGNAL ;
    PORT
      LAYER M5 ;
        RECT  28.08 0 28.104 0.192 ;
    END
  END b[572]
  PIN b[573]
    DIRECTION OUTPUT ;
    USE SIGNAL ;
    PORT
      LAYER M5 ;
        RECT  28.128 0 28.152 0.192 ;
    END
  END b[573]
  PIN b[574]
    DIRECTION OUTPUT ;
    USE SIGNAL ;
    PORT
      LAYER M5 ;
        RECT  28.176 0 28.2 0.192 ;
    END
  END b[574]
  PIN b[575]
    DIRECTION OUTPUT ;
    USE SIGNAL ;
    PORT
      LAYER M5 ;
        RECT  28.224 0 28.248 0.192 ;
    END
  END b[575]
  PIN b[576]
    DIRECTION OUTPUT ;
    USE SIGNAL ;
    PORT
      LAYER M5 ;
        RECT  28.272 0 28.296 0.192 ;
    END
  END b[576]
  PIN b[577]
    DIRECTION OUTPUT ;
    USE SIGNAL ;
    PORT
      LAYER M5 ;
        RECT  28.32 0 28.344 0.192 ;
    END
  END b[577]
  PIN b[578]
    DIRECTION OUTPUT ;
    USE SIGNAL ;
    PORT
      LAYER M5 ;
        RECT  28.368 0 28.392 0.192 ;
    END
  END b[578]
  PIN b[579]
    DIRECTION OUTPUT ;
    USE SIGNAL ;
    PORT
      LAYER M5 ;
        RECT  28.416 0 28.44 0.192 ;
    END
  END b[579]
  PIN b[57]
    DIRECTION OUTPUT ;
    USE SIGNAL ;
    PORT
      LAYER M5 ;
        RECT  3.36 0 3.384 0.192 ;
    END
  END b[57]
  PIN b[580]
    DIRECTION OUTPUT ;
    USE SIGNAL ;
    PORT
      LAYER M5 ;
        RECT  28.464 0 28.488 0.192 ;
    END
  END b[580]
  PIN b[581]
    DIRECTION OUTPUT ;
    USE SIGNAL ;
    PORT
      LAYER M5 ;
        RECT  28.512 0 28.536 0.192 ;
    END
  END b[581]
  PIN b[58]
    DIRECTION OUTPUT ;
    USE SIGNAL ;
    PORT
      LAYER M5 ;
        RECT  3.408 0 3.432 0.192 ;
    END
  END b[58]
  PIN b[59]
    DIRECTION OUTPUT ;
    USE SIGNAL ;
    PORT
      LAYER M5 ;
        RECT  3.456 0 3.48 0.192 ;
    END
  END b[59]
  PIN b[5]
    DIRECTION OUTPUT ;
    USE SIGNAL ;
    PORT
      LAYER M5 ;
        RECT  0.864 0 0.888 0.192 ;
    END
  END b[5]
  PIN b[60]
    DIRECTION OUTPUT ;
    USE SIGNAL ;
    PORT
      LAYER M5 ;
        RECT  3.504 0 3.528 0.192 ;
    END
  END b[60]
  PIN b[61]
    DIRECTION OUTPUT ;
    USE SIGNAL ;
    PORT
      LAYER M5 ;
        RECT  3.552 0 3.576 0.192 ;
    END
  END b[61]
  PIN b[62]
    DIRECTION OUTPUT ;
    USE SIGNAL ;
    PORT
      LAYER M5 ;
        RECT  3.6 0 3.624 0.192 ;
    END
  END b[62]
  PIN b[63]
    DIRECTION OUTPUT ;
    USE SIGNAL ;
    PORT
      LAYER M5 ;
        RECT  3.648 0 3.672 0.192 ;
    END
  END b[63]
  PIN b[64]
    DIRECTION OUTPUT ;
    USE SIGNAL ;
    PORT
      LAYER M5 ;
        RECT  3.696 0 3.72 0.192 ;
    END
  END b[64]
  PIN b[65]
    DIRECTION OUTPUT ;
    USE SIGNAL ;
    PORT
      LAYER M5 ;
        RECT  3.744 0 3.768 0.192 ;
    END
  END b[65]
  PIN b[66]
    DIRECTION OUTPUT ;
    USE SIGNAL ;
    PORT
      LAYER M5 ;
        RECT  3.792 0 3.816 0.192 ;
    END
  END b[66]
  PIN b[67]
    DIRECTION OUTPUT ;
    USE SIGNAL ;
    PORT
      LAYER M5 ;
        RECT  3.84 0 3.864 0.192 ;
    END
  END b[67]
  PIN b[68]
    DIRECTION OUTPUT ;
    USE SIGNAL ;
    PORT
      LAYER M5 ;
        RECT  3.888 0 3.912 0.192 ;
    END
  END b[68]
  PIN b[69]
    DIRECTION OUTPUT ;
    USE SIGNAL ;
    PORT
      LAYER M5 ;
        RECT  3.936 0 3.96 0.192 ;
    END
  END b[69]
  PIN b[6]
    DIRECTION OUTPUT ;
    USE SIGNAL ;
    PORT
      LAYER M5 ;
        RECT  0.912 0 0.936 0.192 ;
    END
  END b[6]
  PIN b[70]
    DIRECTION OUTPUT ;
    USE SIGNAL ;
    PORT
      LAYER M5 ;
        RECT  3.984 0 4.008 0.192 ;
    END
  END b[70]
  PIN b[71]
    DIRECTION OUTPUT ;
    USE SIGNAL ;
    PORT
      LAYER M5 ;
        RECT  4.032 0 4.056 0.192 ;
    END
  END b[71]
  PIN b[72]
    DIRECTION OUTPUT ;
    USE SIGNAL ;
    PORT
      LAYER M5 ;
        RECT  4.08 0 4.104 0.192 ;
    END
  END b[72]
  PIN b[73]
    DIRECTION OUTPUT ;
    USE SIGNAL ;
    PORT
      LAYER M5 ;
        RECT  4.128 0 4.152 0.192 ;
    END
  END b[73]
  PIN b[74]
    DIRECTION OUTPUT ;
    USE SIGNAL ;
    PORT
      LAYER M5 ;
        RECT  4.176 0 4.2 0.192 ;
    END
  END b[74]
  PIN b[75]
    DIRECTION OUTPUT ;
    USE SIGNAL ;
    PORT
      LAYER M5 ;
        RECT  4.224 0 4.248 0.192 ;
    END
  END b[75]
  PIN b[76]
    DIRECTION OUTPUT ;
    USE SIGNAL ;
    PORT
      LAYER M5 ;
        RECT  4.272 0 4.296 0.192 ;
    END
  END b[76]
  PIN b[77]
    DIRECTION OUTPUT ;
    USE SIGNAL ;
    PORT
      LAYER M5 ;
        RECT  4.32 0 4.344 0.192 ;
    END
  END b[77]
  PIN b[78]
    DIRECTION OUTPUT ;
    USE SIGNAL ;
    PORT
      LAYER M5 ;
        RECT  4.368 0 4.392 0.192 ;
    END
  END b[78]
  PIN b[79]
    DIRECTION OUTPUT ;
    USE SIGNAL ;
    PORT
      LAYER M5 ;
        RECT  4.416 0 4.44 0.192 ;
    END
  END b[79]
  PIN b[7]
    DIRECTION OUTPUT ;
    USE SIGNAL ;
    PORT
      LAYER M5 ;
        RECT  0.96 0 0.984 0.192 ;
    END
  END b[7]
  PIN b[80]
    DIRECTION OUTPUT ;
    USE SIGNAL ;
    PORT
      LAYER M5 ;
        RECT  4.464 0 4.488 0.192 ;
    END
  END b[80]
  PIN b[81]
    DIRECTION OUTPUT ;
    USE SIGNAL ;
    PORT
      LAYER M5 ;
        RECT  4.512 0 4.536 0.192 ;
    END
  END b[81]
  PIN b[82]
    DIRECTION OUTPUT ;
    USE SIGNAL ;
    PORT
      LAYER M5 ;
        RECT  4.56 0 4.584 0.192 ;
    END
  END b[82]
  PIN b[83]
    DIRECTION OUTPUT ;
    USE SIGNAL ;
    PORT
      LAYER M5 ;
        RECT  4.608 0 4.632 0.192 ;
    END
  END b[83]
  PIN b[84]
    DIRECTION OUTPUT ;
    USE SIGNAL ;
    PORT
      LAYER M5 ;
        RECT  4.656 0 4.68 0.192 ;
    END
  END b[84]
  PIN b[85]
    DIRECTION OUTPUT ;
    USE SIGNAL ;
    PORT
      LAYER M5 ;
        RECT  4.704 0 4.728 0.192 ;
    END
  END b[85]
  PIN b[86]
    DIRECTION OUTPUT ;
    USE SIGNAL ;
    PORT
      LAYER M5 ;
        RECT  4.752 0 4.776 0.192 ;
    END
  END b[86]
  PIN b[87]
    DIRECTION OUTPUT ;
    USE SIGNAL ;
    PORT
      LAYER M5 ;
        RECT  4.8 0 4.824 0.192 ;
    END
  END b[87]
  PIN b[88]
    DIRECTION OUTPUT ;
    USE SIGNAL ;
    PORT
      LAYER M5 ;
        RECT  4.848 0 4.872 0.192 ;
    END
  END b[88]
  PIN b[89]
    DIRECTION OUTPUT ;
    USE SIGNAL ;
    PORT
      LAYER M5 ;
        RECT  4.896 0 4.92 0.192 ;
    END
  END b[89]
  PIN b[8]
    DIRECTION OUTPUT ;
    USE SIGNAL ;
    PORT
      LAYER M5 ;
        RECT  1.008 0 1.032 0.192 ;
    END
  END b[8]
  PIN b[90]
    DIRECTION OUTPUT ;
    USE SIGNAL ;
    PORT
      LAYER M5 ;
        RECT  4.944 0 4.968 0.192 ;
    END
  END b[90]
  PIN b[91]
    DIRECTION OUTPUT ;
    USE SIGNAL ;
    PORT
      LAYER M5 ;
        RECT  4.992 0 5.016 0.192 ;
    END
  END b[91]
  PIN b[92]
    DIRECTION OUTPUT ;
    USE SIGNAL ;
    PORT
      LAYER M5 ;
        RECT  5.04 0 5.064 0.192 ;
    END
  END b[92]
  PIN b[93]
    DIRECTION OUTPUT ;
    USE SIGNAL ;
    PORT
      LAYER M5 ;
        RECT  5.088 0 5.112 0.192 ;
    END
  END b[93]
  PIN b[94]
    DIRECTION OUTPUT ;
    USE SIGNAL ;
    PORT
      LAYER M5 ;
        RECT  5.136 0 5.16 0.192 ;
    END
  END b[94]
  PIN b[95]
    DIRECTION OUTPUT ;
    USE SIGNAL ;
    PORT
      LAYER M5 ;
        RECT  5.184 0 5.208 0.192 ;
    END
  END b[95]
  PIN b[96]
    DIRECTION OUTPUT ;
    USE SIGNAL ;
    PORT
      LAYER M5 ;
        RECT  5.232 0 5.256 0.192 ;
    END
  END b[96]
  PIN b[97]
    DIRECTION OUTPUT ;
    USE SIGNAL ;
    PORT
      LAYER M5 ;
        RECT  5.28 0 5.304 0.192 ;
    END
  END b[97]
  PIN b[98]
    DIRECTION OUTPUT ;
    USE SIGNAL ;
    PORT
      LAYER M5 ;
        RECT  5.328 0 5.352 0.192 ;
    END
  END b[98]
  PIN b[99]
    DIRECTION OUTPUT ;
    USE SIGNAL ;
    PORT
      LAYER M5 ;
        RECT  5.376 0 5.4 0.192 ;
    END
  END b[99]
  PIN b[9]
    DIRECTION OUTPUT ;
    USE SIGNAL ;
    PORT
      LAYER M5 ;
        RECT  1.056 0 1.08 0.192 ;
    END
  END b[9]
  PIN rst[0]
    DIRECTION INPUT ;
    USE SIGNAL ;
    PORT
      LAYER M4 ;
        RECT  42.552 0.624 42.744 0.648 ;
    END
  END rst[0]
  PIN VDD
    DIRECTION INOUT ;
    USE POWER ;
    PORT
      LAYER M7 ;
        RECT  38.656 0.531 38.944 72.639 ;
        RECT  27.856 0.531 28.144 72.639 ;
        RECT  17.056 0.531 17.344 72.639 ;
        RECT  6.256 0.531 6.544 72.639 ;
      LAYER M6 ;
        RECT  0 71.772 0.032 72.06 ;
        RECT  0 66.372 0.032 66.66 ;
        RECT  0 60.972 0.032 61.26 ;
        RECT  0 55.572 0.032 55.86 ;
        RECT  0 50.172 0.032 50.46 ;
        RECT  0 44.772 0.032 45.06 ;
        RECT  0 39.372 0.032 39.66 ;
        RECT  0 33.972 0.032 34.26 ;
        RECT  0 28.572 0.032 28.86 ;
        RECT  0 23.172 0.032 23.46 ;
        RECT  0 17.772 0.032 18.06 ;
        RECT  0 12.372 0.032 12.66 ;
        RECT  0 6.972 0.032 7.26 ;
        RECT  0 1.572 0.032 1.86 ;
      LAYER M2 ;
        RECT  0 72.621 0.018 72.639 ;
        RECT  0 72.081 0.018 72.099 ;
        RECT  0 71.541 0.018 71.559 ;
        RECT  0 71.001 0.018 71.019 ;
        RECT  0 70.461 0.018 70.479 ;
        RECT  0 69.921 0.018 69.939 ;
        RECT  0 69.381 0.018 69.399 ;
        RECT  0 68.841 0.018 68.859 ;
        RECT  0 68.301 0.018 68.319 ;
        RECT  0 67.761 0.018 67.779 ;
        RECT  0 67.221 0.018 67.239 ;
        RECT  0 66.681 0.018 66.699 ;
        RECT  0 66.141 0.018 66.159 ;
        RECT  0 65.601 0.018 65.619 ;
        RECT  0 65.061 0.018 65.079 ;
        RECT  0 64.521 0.018 64.539 ;
        RECT  0 63.981 0.018 63.999 ;
        RECT  0 63.441 0.018 63.459 ;
        RECT  0 62.901 0.018 62.919 ;
        RECT  0 62.361 0.018 62.379 ;
        RECT  0 61.821 0.018 61.839 ;
        RECT  0 61.281 0.018 61.299 ;
        RECT  0 60.741 0.018 60.759 ;
        RECT  0 60.201 0.018 60.219 ;
        RECT  0 59.661 0.018 59.679 ;
        RECT  0 59.121 0.018 59.139 ;
        RECT  0 58.581 0.018 58.599 ;
        RECT  0 58.041 0.018 58.059 ;
        RECT  0 57.501 0.018 57.519 ;
        RECT  0 56.961 0.018 56.979 ;
        RECT  0 56.421 0.018 56.439 ;
        RECT  0 55.881 0.018 55.899 ;
        RECT  0 55.341 0.018 55.359 ;
        RECT  0 54.801 0.018 54.819 ;
        RECT  0 54.261 0.018 54.279 ;
        RECT  0 53.721 0.018 53.739 ;
        RECT  0 53.181 0.018 53.199 ;
        RECT  0 52.641 0.018 52.659 ;
        RECT  0 52.101 0.018 52.119 ;
        RECT  0 51.561 0.018 51.579 ;
        RECT  0 51.021 0.018 51.039 ;
        RECT  0 50.481 0.018 50.499 ;
        RECT  0 49.941 0.018 49.959 ;
        RECT  0 49.401 0.018 49.419 ;
        RECT  0 48.861 0.018 48.879 ;
        RECT  0 48.321 0.018 48.339 ;
        RECT  0 47.781 0.018 47.799 ;
        RECT  0 47.241 0.018 47.259 ;
        RECT  0 46.701 0.018 46.719 ;
        RECT  0 46.161 0.018 46.179 ;
        RECT  0 45.621 0.018 45.639 ;
        RECT  0 45.081 0.018 45.099 ;
        RECT  0 44.541 0.018 44.559 ;
        RECT  0 44.001 0.018 44.019 ;
        RECT  0 43.461 0.018 43.479 ;
        RECT  0 42.921 0.018 42.939 ;
        RECT  0 42.381 0.018 42.399 ;
        RECT  0 41.841 0.018 41.859 ;
        RECT  0 41.301 0.018 41.319 ;
        RECT  0 40.761 0.018 40.779 ;
        RECT  0 40.221 0.018 40.239 ;
        RECT  0 39.681 0.018 39.699 ;
        RECT  0 39.141 0.018 39.159 ;
        RECT  0 38.601 0.018 38.619 ;
        RECT  0 38.061 0.018 38.079 ;
        RECT  0 37.521 0.018 37.539 ;
        RECT  0 36.981 0.018 36.999 ;
        RECT  0 36.441 0.018 36.459 ;
        RECT  0 35.901 0.018 35.919 ;
        RECT  0 35.361 0.018 35.379 ;
        RECT  0 34.821 0.018 34.839 ;
        RECT  0 34.281 0.018 34.299 ;
        RECT  0 33.741 0.018 33.759 ;
        RECT  0 33.201 0.018 33.219 ;
        RECT  0 32.661 0.018 32.679 ;
        RECT  0 32.121 0.018 32.139 ;
        RECT  0 31.581 0.018 31.599 ;
        RECT  0 31.041 0.018 31.059 ;
        RECT  0 30.501 0.018 30.519 ;
        RECT  0 29.961 0.018 29.979 ;
        RECT  0 29.421 0.018 29.439 ;
        RECT  0 28.881 0.018 28.899 ;
        RECT  0 28.341 0.018 28.359 ;
        RECT  0 27.801 0.018 27.819 ;
        RECT  0 27.261 0.018 27.279 ;
        RECT  0 26.721 0.018 26.739 ;
        RECT  0 26.181 0.018 26.199 ;
        RECT  0 25.641 0.018 25.659 ;
        RECT  0 25.101 0.018 25.119 ;
        RECT  0 24.561 0.018 24.579 ;
        RECT  0 24.021 0.018 24.039 ;
        RECT  0 23.481 0.018 23.499 ;
        RECT  0 22.941 0.018 22.959 ;
        RECT  0 22.401 0.018 22.419 ;
        RECT  0 21.861 0.018 21.879 ;
        RECT  0 21.321 0.018 21.339 ;
        RECT  0 20.781 0.018 20.799 ;
        RECT  0 20.241 0.018 20.259 ;
        RECT  0 19.701 0.018 19.719 ;
        RECT  0 19.161 0.018 19.179 ;
        RECT  0 18.621 0.018 18.639 ;
        RECT  0 18.081 0.018 18.099 ;
        RECT  0 17.541 0.018 17.559 ;
        RECT  0 17.001 0.018 17.019 ;
        RECT  0 16.461 0.018 16.479 ;
        RECT  0 15.921 0.018 15.939 ;
        RECT  0 15.381 0.018 15.399 ;
        RECT  0 14.841 0.018 14.859 ;
        RECT  0 14.301 0.018 14.319 ;
        RECT  0 13.761 0.018 13.779 ;
        RECT  0 13.221 0.018 13.239 ;
        RECT  0 12.681 0.018 12.699 ;
        RECT  0 12.141 0.018 12.159 ;
        RECT  0 11.601 0.018 11.619 ;
        RECT  0 11.061 0.018 11.079 ;
        RECT  0 10.521 0.018 10.539 ;
        RECT  0 9.981 0.018 9.999 ;
        RECT  0 9.441 0.018 9.459 ;
        RECT  0 8.901 0.018 8.919 ;
        RECT  0 8.361 0.018 8.379 ;
        RECT  0 7.821 0.018 7.839 ;
        RECT  0 7.281 0.018 7.299 ;
        RECT  0 6.741 0.018 6.759 ;
        RECT  0 6.201 0.018 6.219 ;
        RECT  0 5.661 0.018 5.679 ;
        RECT  0 5.121 0.018 5.139 ;
        RECT  0 4.581 0.018 4.599 ;
        RECT  0 4.041 0.018 4.059 ;
        RECT  0 3.501 0.018 3.519 ;
        RECT  0 2.961 0.018 2.979 ;
        RECT  0 2.421 0.018 2.439 ;
        RECT  0 1.881 0.018 1.899 ;
        RECT  0 1.341 0.018 1.359 ;
        RECT  0 0.801 0.018 0.819 ;
      LAYER M1 ;
        RECT  0 72.621 0.018 72.639 ;
        RECT  0 72.081 0.018 72.099 ;
        RECT  0 71.541 0.018 71.559 ;
        RECT  0 71.001 0.018 71.019 ;
        RECT  0 70.461 0.018 70.479 ;
        RECT  0 69.921 0.018 69.939 ;
        RECT  0 69.381 0.018 69.399 ;
        RECT  0 68.841 0.018 68.859 ;
        RECT  0 68.301 0.018 68.319 ;
        RECT  0 67.761 0.018 67.779 ;
        RECT  0 67.221 0.018 67.239 ;
        RECT  0 66.681 0.018 66.699 ;
        RECT  0 66.141 0.018 66.159 ;
        RECT  0 65.601 0.018 65.619 ;
        RECT  0 65.061 0.018 65.079 ;
        RECT  0 64.521 0.018 64.539 ;
        RECT  0 63.981 0.018 63.999 ;
        RECT  0 63.441 0.018 63.459 ;
        RECT  0 62.901 0.018 62.919 ;
        RECT  0 62.361 0.018 62.379 ;
        RECT  0 61.821 0.018 61.839 ;
        RECT  0 61.281 0.018 61.299 ;
        RECT  0 60.741 0.018 60.759 ;
        RECT  0 60.201 0.018 60.219 ;
        RECT  0 59.661 0.018 59.679 ;
        RECT  0 59.121 0.018 59.139 ;
        RECT  0 58.581 0.018 58.599 ;
        RECT  0 58.041 0.018 58.059 ;
        RECT  0 57.501 0.018 57.519 ;
        RECT  0 56.961 0.018 56.979 ;
        RECT  0 56.421 0.018 56.439 ;
        RECT  0 55.881 0.018 55.899 ;
        RECT  0 55.341 0.018 55.359 ;
        RECT  0 54.801 0.018 54.819 ;
        RECT  0 54.261 0.018 54.279 ;
        RECT  0 53.721 0.018 53.739 ;
        RECT  0 53.181 0.018 53.199 ;
        RECT  0 52.641 0.018 52.659 ;
        RECT  0 52.101 0.018 52.119 ;
        RECT  0 51.561 0.018 51.579 ;
        RECT  0 51.021 0.018 51.039 ;
        RECT  0 50.481 0.018 50.499 ;
        RECT  0 49.941 0.018 49.959 ;
        RECT  0 49.401 0.018 49.419 ;
        RECT  0 48.861 0.018 48.879 ;
        RECT  0 48.321 0.018 48.339 ;
        RECT  0 47.781 0.018 47.799 ;
        RECT  0 47.241 0.018 47.259 ;
        RECT  0 46.701 0.018 46.719 ;
        RECT  0 46.161 0.018 46.179 ;
        RECT  0 45.621 0.018 45.639 ;
        RECT  0 45.081 0.018 45.099 ;
        RECT  0 44.541 0.018 44.559 ;
        RECT  0 44.001 0.018 44.019 ;
        RECT  0 43.461 0.018 43.479 ;
        RECT  0 42.921 0.018 42.939 ;
        RECT  0 42.381 0.018 42.399 ;
        RECT  0 41.841 0.018 41.859 ;
        RECT  0 41.301 0.018 41.319 ;
        RECT  0 40.761 0.018 40.779 ;
        RECT  0 40.221 0.018 40.239 ;
        RECT  0 39.681 0.018 39.699 ;
        RECT  0 39.141 0.018 39.159 ;
        RECT  0 38.601 0.018 38.619 ;
        RECT  0 38.061 0.018 38.079 ;
        RECT  0 37.521 0.018 37.539 ;
        RECT  0 36.981 0.018 36.999 ;
        RECT  0 36.441 0.018 36.459 ;
        RECT  0 35.901 0.018 35.919 ;
        RECT  0 35.361 0.018 35.379 ;
        RECT  0 34.821 0.018 34.839 ;
        RECT  0 34.281 0.018 34.299 ;
        RECT  0 33.741 0.018 33.759 ;
        RECT  0 33.201 0.018 33.219 ;
        RECT  0 32.661 0.018 32.679 ;
        RECT  0 32.121 0.018 32.139 ;
        RECT  0 31.581 0.018 31.599 ;
        RECT  0 31.041 0.018 31.059 ;
        RECT  0 30.501 0.018 30.519 ;
        RECT  0 29.961 0.018 29.979 ;
        RECT  0 29.421 0.018 29.439 ;
        RECT  0 28.881 0.018 28.899 ;
        RECT  0 28.341 0.018 28.359 ;
        RECT  0 27.801 0.018 27.819 ;
        RECT  0 27.261 0.018 27.279 ;
        RECT  0 26.721 0.018 26.739 ;
        RECT  0 26.181 0.018 26.199 ;
        RECT  0 25.641 0.018 25.659 ;
        RECT  0 25.101 0.018 25.119 ;
        RECT  0 24.561 0.018 24.579 ;
        RECT  0 24.021 0.018 24.039 ;
        RECT  0 23.481 0.018 23.499 ;
        RECT  0 22.941 0.018 22.959 ;
        RECT  0 22.401 0.018 22.419 ;
        RECT  0 21.861 0.018 21.879 ;
        RECT  0 21.321 0.018 21.339 ;
        RECT  0 20.781 0.018 20.799 ;
        RECT  0 20.241 0.018 20.259 ;
        RECT  0 19.701 0.018 19.719 ;
        RECT  0 19.161 0.018 19.179 ;
        RECT  0 18.621 0.018 18.639 ;
        RECT  0 18.081 0.018 18.099 ;
        RECT  0 17.541 0.018 17.559 ;
        RECT  0 17.001 0.018 17.019 ;
        RECT  0 16.461 0.018 16.479 ;
        RECT  0 15.921 0.018 15.939 ;
        RECT  0 15.381 0.018 15.399 ;
        RECT  0 14.841 0.018 14.859 ;
        RECT  0 14.301 0.018 14.319 ;
        RECT  0 13.761 0.018 13.779 ;
        RECT  0 13.221 0.018 13.239 ;
        RECT  0 12.681 0.018 12.699 ;
        RECT  0 12.141 0.018 12.159 ;
        RECT  0 11.601 0.018 11.619 ;
        RECT  0 11.061 0.018 11.079 ;
        RECT  0 10.521 0.018 10.539 ;
        RECT  0 9.981 0.018 9.999 ;
        RECT  0 9.441 0.018 9.459 ;
        RECT  0 8.901 0.018 8.919 ;
        RECT  0 8.361 0.018 8.379 ;
        RECT  0 7.821 0.018 7.839 ;
        RECT  0 7.281 0.018 7.299 ;
        RECT  0 6.741 0.018 6.759 ;
        RECT  0 6.201 0.018 6.219 ;
        RECT  0 5.661 0.018 5.679 ;
        RECT  0 5.121 0.018 5.139 ;
        RECT  0 4.581 0.018 4.599 ;
        RECT  0 4.041 0.018 4.059 ;
        RECT  0 3.501 0.018 3.519 ;
        RECT  0 2.961 0.018 2.979 ;
        RECT  0 2.421 0.018 2.439 ;
        RECT  0 1.881 0.018 1.899 ;
        RECT  0 1.341 0.018 1.359 ;
        RECT  0 0.801 0.018 0.819 ;
    END
  END VDD
  PIN VSS
    DIRECTION INOUT ;
    USE GROUND ;
    PORT
      LAYER M7 ;
        RECT  33.256 0.531 33.544 72.639 ;
        RECT  22.456 0.531 22.744 72.639 ;
        RECT  11.656 0.531 11.944 72.639 ;
        RECT  0.856 0.531 1.144 72.639 ;
      LAYER M6 ;
        RECT  0 71.196 0.032 71.484 ;
        RECT  0 65.796 0.032 66.084 ;
        RECT  0 60.396 0.032 60.684 ;
        RECT  0 54.996 0.032 55.284 ;
        RECT  0 49.596 0.032 49.884 ;
        RECT  0 44.196 0.032 44.484 ;
        RECT  0 38.796 0.032 39.084 ;
        RECT  0 33.396 0.032 33.684 ;
        RECT  0 27.996 0.032 28.284 ;
        RECT  0 22.596 0.032 22.884 ;
        RECT  0 17.196 0.032 17.484 ;
        RECT  0 11.796 0.032 12.084 ;
        RECT  0 6.396 0.032 6.684 ;
        RECT  0 0.996 0.032 1.284 ;
      LAYER M2 ;
        RECT  0 72.351 0.018 72.369 ;
        RECT  0 71.811 0.018 71.829 ;
        RECT  0 71.271 0.018 71.289 ;
        RECT  0 70.731 0.018 70.749 ;
        RECT  0 70.191 0.018 70.209 ;
        RECT  0 69.651 0.018 69.669 ;
        RECT  0 69.111 0.018 69.129 ;
        RECT  0 68.571 0.018 68.589 ;
        RECT  0 68.031 0.018 68.049 ;
        RECT  0 67.491 0.018 67.509 ;
        RECT  0 66.951 0.018 66.969 ;
        RECT  0 66.411 0.018 66.429 ;
        RECT  0 65.871 0.018 65.889 ;
        RECT  0 65.331 0.018 65.349 ;
        RECT  0 64.791 0.018 64.809 ;
        RECT  0 64.251 0.018 64.269 ;
        RECT  0 63.711 0.018 63.729 ;
        RECT  0 63.171 0.018 63.189 ;
        RECT  0 62.631 0.018 62.649 ;
        RECT  0 62.091 0.018 62.109 ;
        RECT  0 61.551 0.018 61.569 ;
        RECT  0 61.011 0.018 61.029 ;
        RECT  0 60.471 0.018 60.489 ;
        RECT  0 59.931 0.018 59.949 ;
        RECT  0 59.391 0.018 59.409 ;
        RECT  0 58.851 0.018 58.869 ;
        RECT  0 58.311 0.018 58.329 ;
        RECT  0 57.771 0.018 57.789 ;
        RECT  0 57.231 0.018 57.249 ;
        RECT  0 56.691 0.018 56.709 ;
        RECT  0 56.151 0.018 56.169 ;
        RECT  0 55.611 0.018 55.629 ;
        RECT  0 55.071 0.018 55.089 ;
        RECT  0 54.531 0.018 54.549 ;
        RECT  0 53.991 0.018 54.009 ;
        RECT  0 53.451 0.018 53.469 ;
        RECT  0 52.911 0.018 52.929 ;
        RECT  0 52.371 0.018 52.389 ;
        RECT  0 51.831 0.018 51.849 ;
        RECT  0 51.291 0.018 51.309 ;
        RECT  0 50.751 0.018 50.769 ;
        RECT  0 50.211 0.018 50.229 ;
        RECT  0 49.671 0.018 49.689 ;
        RECT  0 49.131 0.018 49.149 ;
        RECT  0 48.591 0.018 48.609 ;
        RECT  0 48.051 0.018 48.069 ;
        RECT  0 47.511 0.018 47.529 ;
        RECT  0 46.971 0.018 46.989 ;
        RECT  0 46.431 0.018 46.449 ;
        RECT  0 45.891 0.018 45.909 ;
        RECT  0 45.351 0.018 45.369 ;
        RECT  0 44.811 0.018 44.829 ;
        RECT  0 44.271 0.018 44.289 ;
        RECT  0 43.731 0.018 43.749 ;
        RECT  0 43.191 0.018 43.209 ;
        RECT  0 42.651 0.018 42.669 ;
        RECT  0 42.111 0.018 42.129 ;
        RECT  0 41.571 0.018 41.589 ;
        RECT  0 41.031 0.018 41.049 ;
        RECT  0 40.491 0.018 40.509 ;
        RECT  0 39.951 0.018 39.969 ;
        RECT  0 39.411 0.018 39.429 ;
        RECT  0 38.871 0.018 38.889 ;
        RECT  0 38.331 0.018 38.349 ;
        RECT  0 37.791 0.018 37.809 ;
        RECT  0 37.251 0.018 37.269 ;
        RECT  0 36.711 0.018 36.729 ;
        RECT  0 36.171 0.018 36.189 ;
        RECT  0 35.631 0.018 35.649 ;
        RECT  0 35.091 0.018 35.109 ;
        RECT  0 34.551 0.018 34.569 ;
        RECT  0 34.011 0.018 34.029 ;
        RECT  0 33.471 0.018 33.489 ;
        RECT  0 32.931 0.018 32.949 ;
        RECT  0 32.391 0.018 32.409 ;
        RECT  0 31.851 0.018 31.869 ;
        RECT  0 31.311 0.018 31.329 ;
        RECT  0 30.771 0.018 30.789 ;
        RECT  0 30.231 0.018 30.249 ;
        RECT  0 29.691 0.018 29.709 ;
        RECT  0 29.151 0.018 29.169 ;
        RECT  0 28.611 0.018 28.629 ;
        RECT  0 28.071 0.018 28.089 ;
        RECT  0 27.531 0.018 27.549 ;
        RECT  0 26.991 0.018 27.009 ;
        RECT  0 26.451 0.018 26.469 ;
        RECT  0 25.911 0.018 25.929 ;
        RECT  0 25.371 0.018 25.389 ;
        RECT  0 24.831 0.018 24.849 ;
        RECT  0 24.291 0.018 24.309 ;
        RECT  0 23.751 0.018 23.769 ;
        RECT  0 23.211 0.018 23.229 ;
        RECT  0 22.671 0.018 22.689 ;
        RECT  0 22.131 0.018 22.149 ;
        RECT  0 21.591 0.018 21.609 ;
        RECT  0 21.051 0.018 21.069 ;
        RECT  0 20.511 0.018 20.529 ;
        RECT  0 19.971 0.018 19.989 ;
        RECT  0 19.431 0.018 19.449 ;
        RECT  0 18.891 0.018 18.909 ;
        RECT  0 18.351 0.018 18.369 ;
        RECT  0 17.811 0.018 17.829 ;
        RECT  0 17.271 0.018 17.289 ;
        RECT  0 16.731 0.018 16.749 ;
        RECT  0 16.191 0.018 16.209 ;
        RECT  0 15.651 0.018 15.669 ;
        RECT  0 15.111 0.018 15.129 ;
        RECT  0 14.571 0.018 14.589 ;
        RECT  0 14.031 0.018 14.049 ;
        RECT  0 13.491 0.018 13.509 ;
        RECT  0 12.951 0.018 12.969 ;
        RECT  0 12.411 0.018 12.429 ;
        RECT  0 11.871 0.018 11.889 ;
        RECT  0 11.331 0.018 11.349 ;
        RECT  0 10.791 0.018 10.809 ;
        RECT  0 10.251 0.018 10.269 ;
        RECT  0 9.711 0.018 9.729 ;
        RECT  0 9.171 0.018 9.189 ;
        RECT  0 8.631 0.018 8.649 ;
        RECT  0 8.091 0.018 8.109 ;
        RECT  0 7.551 0.018 7.569 ;
        RECT  0 7.011 0.018 7.029 ;
        RECT  0 6.471 0.018 6.489 ;
        RECT  0 5.931 0.018 5.949 ;
        RECT  0 5.391 0.018 5.409 ;
        RECT  0 4.851 0.018 4.869 ;
        RECT  0 4.311 0.018 4.329 ;
        RECT  0 3.771 0.018 3.789 ;
        RECT  0 3.231 0.018 3.249 ;
        RECT  0 2.691 0.018 2.709 ;
        RECT  0 2.151 0.018 2.169 ;
        RECT  0 1.611 0.018 1.629 ;
        RECT  0 1.071 0.018 1.089 ;
        RECT  0 0.531 0.018 0.549 ;
      LAYER M1 ;
        RECT  0 72.351 0.018 72.369 ;
        RECT  0 71.811 0.018 71.829 ;
        RECT  0 71.271 0.018 71.289 ;
        RECT  0 70.731 0.018 70.749 ;
        RECT  0 70.191 0.018 70.209 ;
        RECT  0 69.651 0.018 69.669 ;
        RECT  0 69.111 0.018 69.129 ;
        RECT  0 68.571 0.018 68.589 ;
        RECT  0 68.031 0.018 68.049 ;
        RECT  0 67.491 0.018 67.509 ;
        RECT  0 66.951 0.018 66.969 ;
        RECT  0 66.411 0.018 66.429 ;
        RECT  0 65.871 0.018 65.889 ;
        RECT  0 65.331 0.018 65.349 ;
        RECT  0 64.791 0.018 64.809 ;
        RECT  0 64.251 0.018 64.269 ;
        RECT  0 63.711 0.018 63.729 ;
        RECT  0 63.171 0.018 63.189 ;
        RECT  0 62.631 0.018 62.649 ;
        RECT  0 62.091 0.018 62.109 ;
        RECT  0 61.551 0.018 61.569 ;
        RECT  0 61.011 0.018 61.029 ;
        RECT  0 60.471 0.018 60.489 ;
        RECT  0 59.931 0.018 59.949 ;
        RECT  0 59.391 0.018 59.409 ;
        RECT  0 58.851 0.018 58.869 ;
        RECT  0 58.311 0.018 58.329 ;
        RECT  0 57.771 0.018 57.789 ;
        RECT  0 57.231 0.018 57.249 ;
        RECT  0 56.691 0.018 56.709 ;
        RECT  0 56.151 0.018 56.169 ;
        RECT  0 55.611 0.018 55.629 ;
        RECT  0 55.071 0.018 55.089 ;
        RECT  0 54.531 0.018 54.549 ;
        RECT  0 53.991 0.018 54.009 ;
        RECT  0 53.451 0.018 53.469 ;
        RECT  0 52.911 0.018 52.929 ;
        RECT  0 52.371 0.018 52.389 ;
        RECT  0 51.831 0.018 51.849 ;
        RECT  0 51.291 0.018 51.309 ;
        RECT  0 50.751 0.018 50.769 ;
        RECT  0 50.211 0.018 50.229 ;
        RECT  0 49.671 0.018 49.689 ;
        RECT  0 49.131 0.018 49.149 ;
        RECT  0 48.591 0.018 48.609 ;
        RECT  0 48.051 0.018 48.069 ;
        RECT  0 47.511 0.018 47.529 ;
        RECT  0 46.971 0.018 46.989 ;
        RECT  0 46.431 0.018 46.449 ;
        RECT  0 45.891 0.018 45.909 ;
        RECT  0 45.351 0.018 45.369 ;
        RECT  0 44.811 0.018 44.829 ;
        RECT  0 44.271 0.018 44.289 ;
        RECT  0 43.731 0.018 43.749 ;
        RECT  0 43.191 0.018 43.209 ;
        RECT  0 42.651 0.018 42.669 ;
        RECT  0 42.111 0.018 42.129 ;
        RECT  0 41.571 0.018 41.589 ;
        RECT  0 41.031 0.018 41.049 ;
        RECT  0 40.491 0.018 40.509 ;
        RECT  0 39.951 0.018 39.969 ;
        RECT  0 39.411 0.018 39.429 ;
        RECT  0 38.871 0.018 38.889 ;
        RECT  0 38.331 0.018 38.349 ;
        RECT  0 37.791 0.018 37.809 ;
        RECT  0 37.251 0.018 37.269 ;
        RECT  0 36.711 0.018 36.729 ;
        RECT  0 36.171 0.018 36.189 ;
        RECT  0 35.631 0.018 35.649 ;
        RECT  0 35.091 0.018 35.109 ;
        RECT  0 34.551 0.018 34.569 ;
        RECT  0 34.011 0.018 34.029 ;
        RECT  0 33.471 0.018 33.489 ;
        RECT  0 32.931 0.018 32.949 ;
        RECT  0 32.391 0.018 32.409 ;
        RECT  0 31.851 0.018 31.869 ;
        RECT  0 31.311 0.018 31.329 ;
        RECT  0 30.771 0.018 30.789 ;
        RECT  0 30.231 0.018 30.249 ;
        RECT  0 29.691 0.018 29.709 ;
        RECT  0 29.151 0.018 29.169 ;
        RECT  0 28.611 0.018 28.629 ;
        RECT  0 28.071 0.018 28.089 ;
        RECT  0 27.531 0.018 27.549 ;
        RECT  0 26.991 0.018 27.009 ;
        RECT  0 26.451 0.018 26.469 ;
        RECT  0 25.911 0.018 25.929 ;
        RECT  0 25.371 0.018 25.389 ;
        RECT  0 24.831 0.018 24.849 ;
        RECT  0 24.291 0.018 24.309 ;
        RECT  0 23.751 0.018 23.769 ;
        RECT  0 23.211 0.018 23.229 ;
        RECT  0 22.671 0.018 22.689 ;
        RECT  0 22.131 0.018 22.149 ;
        RECT  0 21.591 0.018 21.609 ;
        RECT  0 21.051 0.018 21.069 ;
        RECT  0 20.511 0.018 20.529 ;
        RECT  0 19.971 0.018 19.989 ;
        RECT  0 19.431 0.018 19.449 ;
        RECT  0 18.891 0.018 18.909 ;
        RECT  0 18.351 0.018 18.369 ;
        RECT  0 17.811 0.018 17.829 ;
        RECT  0 17.271 0.018 17.289 ;
        RECT  0 16.731 0.018 16.749 ;
        RECT  0 16.191 0.018 16.209 ;
        RECT  0 15.651 0.018 15.669 ;
        RECT  0 15.111 0.018 15.129 ;
        RECT  0 14.571 0.018 14.589 ;
        RECT  0 14.031 0.018 14.049 ;
        RECT  0 13.491 0.018 13.509 ;
        RECT  0 12.951 0.018 12.969 ;
        RECT  0 12.411 0.018 12.429 ;
        RECT  0 11.871 0.018 11.889 ;
        RECT  0 11.331 0.018 11.349 ;
        RECT  0 10.791 0.018 10.809 ;
        RECT  0 10.251 0.018 10.269 ;
        RECT  0 9.711 0.018 9.729 ;
        RECT  0 9.171 0.018 9.189 ;
        RECT  0 8.631 0.018 8.649 ;
        RECT  0 8.091 0.018 8.109 ;
        RECT  0 7.551 0.018 7.569 ;
        RECT  0 7.011 0.018 7.029 ;
        RECT  0 6.471 0.018 6.489 ;
        RECT  0 5.931 0.018 5.949 ;
        RECT  0 5.391 0.018 5.409 ;
        RECT  0 4.851 0.018 4.869 ;
        RECT  0 4.311 0.018 4.329 ;
        RECT  0 3.771 0.018 3.789 ;
        RECT  0 3.231 0.018 3.249 ;
        RECT  0 2.691 0.018 2.709 ;
        RECT  0 2.151 0.018 2.169 ;
        RECT  0 1.611 0.018 1.629 ;
        RECT  0 1.071 0.018 1.089 ;
        RECT  0 0.531 0.018 0.549 ;
    END
  END VSS
  OBS
    LAYER RVTN ;
     RECT  0 0.54 42.714 0.675 ;
     RECT  0 0.945 42.714 1.215 ;
     RECT  0 1.485 42.714 1.755 ;
     RECT  0 2.025 42.714 2.295 ;
     RECT  0 2.565 42.714 2.835 ;
     RECT  0 3.105 42.714 3.375 ;
     RECT  0 3.645 42.714 3.915 ;
     RECT  0 4.185 42.714 4.455 ;
     RECT  0 4.725 42.714 4.995 ;
     RECT  0 5.265 42.714 5.535 ;
     RECT  0 5.805 42.714 6.075 ;
     RECT  0 6.345 42.714 6.615 ;
     RECT  0 6.885 42.714 7.155 ;
     RECT  0 7.425 42.714 7.695 ;
     RECT  0 7.965 42.714 8.235 ;
     RECT  0 8.505 42.714 8.775 ;
     RECT  0 9.045 42.714 9.315 ;
     RECT  0 9.585 42.714 9.855 ;
     RECT  0 10.125 42.714 10.395 ;
     RECT  0 10.665 42.714 10.935 ;
     RECT  0 11.205 42.714 11.475 ;
     RECT  0 11.745 42.714 12.015 ;
     RECT  0 12.285 42.714 12.555 ;
     RECT  0 12.825 42.714 13.095 ;
     RECT  0 13.365 42.714 13.635 ;
     RECT  0 13.905 42.714 14.175 ;
     RECT  0 14.445 42.714 14.715 ;
     RECT  0 14.985 42.714 15.255 ;
     RECT  0 15.525 42.714 15.795 ;
     RECT  0 16.065 42.714 16.335 ;
     RECT  0 16.605 42.714 16.875 ;
     RECT  0 17.145 42.714 17.415 ;
     RECT  0 17.685 42.714 17.955 ;
     RECT  0 18.225 42.714 18.495 ;
     RECT  0 18.765 42.714 19.035 ;
     RECT  0 19.305 42.714 19.575 ;
     RECT  0 19.845 42.714 20.115 ;
     RECT  0 20.385 42.714 20.655 ;
     RECT  0 20.925 42.714 21.195 ;
     RECT  0 21.465 42.714 21.735 ;
     RECT  0 22.005 42.714 22.275 ;
     RECT  0 22.545 42.714 22.815 ;
     RECT  0 23.085 42.714 23.355 ;
     RECT  0 23.625 42.714 23.895 ;
     RECT  0 24.165 42.714 24.435 ;
     RECT  0 24.705 42.714 24.975 ;
     RECT  0 25.245 42.714 25.515 ;
     RECT  0 25.785 42.714 26.055 ;
     RECT  0 26.325 42.714 26.595 ;
     RECT  0 26.865 42.714 27.135 ;
     RECT  0 27.405 42.714 27.675 ;
     RECT  0 27.945 42.714 28.215 ;
     RECT  0 28.485 42.714 28.755 ;
     RECT  0 29.025 42.714 29.295 ;
     RECT  0 29.565 42.714 29.835 ;
     RECT  0 30.105 42.714 30.375 ;
     RECT  0 30.645 42.714 30.915 ;
     RECT  0 31.185 42.714 31.455 ;
     RECT  0 31.725 42.714 31.995 ;
     RECT  0 32.265 42.714 32.535 ;
     RECT  0 32.805 42.714 33.075 ;
     RECT  0 33.345 42.714 33.615 ;
     RECT  0 33.885 42.714 34.155 ;
     RECT  0 34.425 42.714 34.695 ;
     RECT  0 34.965 42.714 35.235 ;
     RECT  0 35.505 42.714 35.775 ;
     RECT  0 36.045 42.714 36.315 ;
     RECT  0 36.585 42.714 36.855 ;
     RECT  0 37.125 42.714 37.395 ;
     RECT  0 37.665 42.714 37.935 ;
     RECT  0 38.205 42.714 38.475 ;
     RECT  0 38.745 42.714 39.015 ;
     RECT  0 39.285 42.714 39.555 ;
     RECT  0 39.825 42.714 40.095 ;
     RECT  0 40.365 42.714 40.635 ;
     RECT  0 40.905 42.714 41.175 ;
     RECT  0 41.445 42.714 41.715 ;
     RECT  0 41.985 42.714 42.255 ;
     RECT  0 42.525 42.714 42.795 ;
     RECT  0 43.065 42.714 43.335 ;
     RECT  0 43.605 42.714 43.875 ;
     RECT  0 44.145 42.714 44.415 ;
     RECT  0 44.685 42.714 44.955 ;
     RECT  0 45.225 42.714 45.495 ;
     RECT  0 45.765 42.714 46.035 ;
     RECT  0 46.305 42.714 46.575 ;
     RECT  0 46.845 42.714 47.115 ;
     RECT  0 47.385 42.714 47.655 ;
     RECT  0 47.925 42.714 48.195 ;
     RECT  0 48.465 42.714 48.735 ;
     RECT  0 49.005 42.714 49.275 ;
     RECT  0 49.545 42.714 49.815 ;
     RECT  0 50.085 42.714 50.355 ;
     RECT  0 50.625 42.714 50.895 ;
     RECT  0 51.165 42.714 51.435 ;
     RECT  0 51.705 42.714 51.975 ;
     RECT  0 52.245 42.714 52.515 ;
     RECT  0 52.785 42.714 53.055 ;
     RECT  0 53.325 42.714 53.595 ;
     RECT  0 53.865 42.714 54.135 ;
     RECT  0 54.405 42.714 54.675 ;
     RECT  0 54.945 42.714 55.215 ;
     RECT  0 55.485 42.714 55.755 ;
     RECT  0 56.025 42.714 56.295 ;
     RECT  0 56.565 42.714 56.835 ;
     RECT  0 57.105 42.714 57.375 ;
     RECT  0 57.645 42.714 57.915 ;
     RECT  0 58.185 42.714 58.455 ;
     RECT  0 58.725 42.714 58.995 ;
     RECT  0 59.265 42.714 59.535 ;
     RECT  0 59.805 42.714 60.075 ;
     RECT  0 60.345 42.714 60.615 ;
     RECT  0 60.885 42.714 61.155 ;
     RECT  0 61.425 42.714 61.695 ;
     RECT  0 61.965 42.714 62.235 ;
     RECT  0 62.505 42.714 62.775 ;
     RECT  0 63.045 42.714 63.315 ;
     RECT  0 63.585 42.714 63.855 ;
     RECT  0 64.125 42.714 64.395 ;
     RECT  0 64.665 42.714 64.935 ;
     RECT  0 65.205 42.714 65.475 ;
     RECT  0 65.745 42.714 66.015 ;
     RECT  0 66.285 42.714 66.555 ;
     RECT  0 66.825 42.714 67.095 ;
     RECT  0 67.365 42.714 67.635 ;
     RECT  0 67.905 42.714 68.175 ;
     RECT  0 68.445 42.714 68.715 ;
     RECT  0 68.985 42.714 69.255 ;
     RECT  0 69.525 42.714 69.795 ;
     RECT  0 70.065 42.714 70.335 ;
     RECT  0 70.605 42.714 70.875 ;
     RECT  0 71.145 42.714 71.415 ;
     RECT  0 71.685 42.714 71.955 ;
     RECT  0 72.225 42.714 72.495 ;
    LAYER RVTP ;
     RECT  0 0.675 42.714 0.945 ;
     RECT  0 1.215 42.714 1.485 ;
     RECT  0 1.755 42.714 2.025 ;
     RECT  0 2.295 42.714 2.565 ;
     RECT  0 2.835 42.714 3.105 ;
     RECT  0 3.375 42.714 3.645 ;
     RECT  0 3.915 42.714 4.185 ;
     RECT  0 4.455 42.714 4.725 ;
     RECT  0 4.995 42.714 5.265 ;
     RECT  0 5.535 42.714 5.805 ;
     RECT  0 6.075 42.714 6.345 ;
     RECT  0 6.615 42.714 6.885 ;
     RECT  0 7.155 42.714 7.425 ;
     RECT  0 7.695 42.714 7.965 ;
     RECT  0 8.235 42.714 8.505 ;
     RECT  0 8.775 42.714 9.045 ;
     RECT  0 9.315 42.714 9.585 ;
     RECT  0 9.855 42.714 10.125 ;
     RECT  0 10.395 42.714 10.665 ;
     RECT  0 10.935 42.714 11.205 ;
     RECT  0 11.475 42.714 11.745 ;
     RECT  0 12.015 42.714 12.285 ;
     RECT  0 12.555 42.714 12.825 ;
     RECT  0 13.095 42.714 13.365 ;
     RECT  0 13.635 42.714 13.905 ;
     RECT  0 14.175 42.714 14.445 ;
     RECT  0 14.715 42.714 14.985 ;
     RECT  0 15.255 42.714 15.525 ;
     RECT  0 15.795 42.714 16.065 ;
     RECT  0 16.335 42.714 16.605 ;
     RECT  0 16.875 42.714 17.145 ;
     RECT  0 17.415 42.714 17.685 ;
     RECT  0 17.955 42.714 18.225 ;
     RECT  0 18.495 42.714 18.765 ;
     RECT  0 19.035 42.714 19.305 ;
     RECT  0 19.575 42.714 19.845 ;
     RECT  0 20.115 42.714 20.385 ;
     RECT  0 20.655 42.714 20.925 ;
     RECT  0 21.195 42.714 21.465 ;
     RECT  0 21.735 42.714 22.005 ;
     RECT  0 22.275 42.714 22.545 ;
     RECT  0 22.815 42.714 23.085 ;
     RECT  0 23.355 42.714 23.625 ;
     RECT  0 23.895 42.714 24.165 ;
     RECT  0 24.435 42.714 24.705 ;
     RECT  0 24.975 42.714 25.245 ;
     RECT  0 25.515 42.714 25.785 ;
     RECT  0 26.055 42.714 26.325 ;
     RECT  0 26.595 42.714 26.865 ;
     RECT  0 27.135 42.714 27.405 ;
     RECT  0 27.675 42.714 27.945 ;
     RECT  0 28.215 42.714 28.485 ;
     RECT  0 28.755 42.714 29.025 ;
     RECT  0 29.295 42.714 29.565 ;
     RECT  0 29.835 42.714 30.105 ;
     RECT  0 30.375 42.714 30.645 ;
     RECT  0 30.915 42.714 31.185 ;
     RECT  0 31.455 42.714 31.725 ;
     RECT  0 31.995 42.714 32.265 ;
     RECT  0 32.535 42.714 32.805 ;
     RECT  0 33.075 42.714 33.345 ;
     RECT  0 33.615 42.714 33.885 ;
     RECT  0 34.155 42.714 34.425 ;
     RECT  0 34.695 42.714 34.965 ;
     RECT  0 35.235 42.714 35.505 ;
     RECT  0 35.775 42.714 36.045 ;
     RECT  0 36.315 42.714 36.585 ;
     RECT  0 36.855 42.714 37.125 ;
     RECT  0 37.395 42.714 37.665 ;
     RECT  0 37.935 42.714 38.205 ;
     RECT  0 38.475 42.714 38.745 ;
     RECT  0 39.015 42.714 39.285 ;
     RECT  0 39.555 42.714 39.825 ;
     RECT  0 40.095 42.714 40.365 ;
     RECT  0 40.635 42.714 40.905 ;
     RECT  0 41.175 42.714 41.445 ;
     RECT  0 41.715 42.714 41.985 ;
     RECT  0 42.255 42.714 42.525 ;
     RECT  0 42.795 42.714 43.065 ;
     RECT  0 43.335 42.714 43.605 ;
     RECT  0 43.875 42.714 44.145 ;
     RECT  0 44.415 42.714 44.685 ;
     RECT  0 44.955 42.714 45.225 ;
     RECT  0 45.495 42.714 45.765 ;
     RECT  0 46.035 42.714 46.305 ;
     RECT  0 46.575 42.714 46.845 ;
     RECT  0 47.115 42.714 47.385 ;
     RECT  0 47.655 42.714 47.925 ;
     RECT  0 48.195 42.714 48.465 ;
     RECT  0 48.735 42.714 49.005 ;
     RECT  0 49.275 42.714 49.545 ;
     RECT  0 49.815 42.714 50.085 ;
     RECT  0 50.355 42.714 50.625 ;
     RECT  0 50.895 42.714 51.165 ;
     RECT  0 51.435 42.714 51.705 ;
     RECT  0 51.975 42.714 52.245 ;
     RECT  0 52.515 42.714 52.785 ;
     RECT  0 53.055 42.714 53.325 ;
     RECT  0 53.595 42.714 53.865 ;
     RECT  0 54.135 42.714 54.405 ;
     RECT  0 54.675 42.714 54.945 ;
     RECT  0 55.215 42.714 55.485 ;
     RECT  0 55.755 42.714 56.025 ;
     RECT  0 56.295 42.714 56.565 ;
     RECT  0 56.835 42.714 57.105 ;
     RECT  0 57.375 42.714 57.645 ;
     RECT  0 57.915 42.714 58.185 ;
     RECT  0 58.455 42.714 58.725 ;
     RECT  0 58.995 42.714 59.265 ;
     RECT  0 59.535 42.714 59.805 ;
     RECT  0 60.075 42.714 60.345 ;
     RECT  0 60.615 42.714 60.885 ;
     RECT  0 61.155 42.714 61.425 ;
     RECT  0 61.695 42.714 61.965 ;
     RECT  0 62.235 42.714 62.505 ;
     RECT  0 62.775 42.714 63.045 ;
     RECT  0 63.315 42.714 63.585 ;
     RECT  0 63.855 42.714 64.125 ;
     RECT  0 64.395 42.714 64.665 ;
     RECT  0 64.935 42.714 65.205 ;
     RECT  0 65.475 42.714 65.745 ;
     RECT  0 66.015 42.714 66.285 ;
     RECT  0 66.555 42.714 66.825 ;
     RECT  0 67.095 42.714 67.365 ;
     RECT  0 67.635 42.714 67.905 ;
     RECT  0 68.175 42.714 68.445 ;
     RECT  0 68.715 42.714 68.985 ;
     RECT  0 69.255 42.714 69.525 ;
     RECT  0 69.795 42.714 70.065 ;
     RECT  0 70.335 42.714 70.605 ;
     RECT  0 70.875 42.714 71.145 ;
     RECT  0 71.415 42.714 71.685 ;
     RECT  0 71.955 42.714 72.225 ;
     RECT  0 72.495 42.714 72.63 ;
    LAYER M1 ;
     RECT  0 0.531 42.714 72.639 ;
    LAYER M2 ;
     RECT  0 0.531 5.467 72.639 ;
     RECT  5.467 0.261 5.647 72.639 ;
     RECT  5.647 0.108 6.575 72.639 ;
     RECT  6.575 0.261 6.755 72.639 ;
     RECT  6.755 0.531 7.915 72.639 ;
     RECT  7.915 0.216 8.051 72.639 ;
     RECT  8.051 0.531 10.975 72.639 ;
     RECT  10.975 0.306 11.183 72.639 ;
     RECT  11.183 0.531 15.763 72.639 ;
     RECT  15.763 0.261 16.799 72.639 ;
     RECT  16.799 0.531 19.651 72.639 ;
     RECT  19.651 0.486 20.183 72.639 ;
     RECT  20.183 0.531 21.739 72.639 ;
     RECT  21.739 0.414 21.983 72.639 ;
     RECT  21.983 0.531 24.439 72.639 ;
     RECT  24.439 0.306 24.539 72.639 ;
     RECT  24.539 0.486 24.971 72.639 ;
     RECT  24.971 0.531 25.807 72.639 ;
     RECT  25.807 0.414 26.815 72.639 ;
     RECT  26.815 0.306 26.995 72.639 ;
     RECT  26.995 0.261 27.671 72.639 ;
     RECT  27.671 0.306 28.103 72.639 ;
     RECT  28.103 0.531 28.939 72.639 ;
     RECT  28.939 0.486 29.039 72.639 ;
     RECT  29.039 0.531 42.714 72.639 ;
    LAYER M3 ;
     RECT  5.832 0.043 5.85 0.091 ;
     RECT  28.908 0.043 28.926 0.091 ;
     RECT  31.788 0.043 31.806 0.091 ;
     RECT  5.076 0.091 5.094 0.103 ;
     RECT  5.832 0.091 6.966 0.103 ;
     RECT  11.988 0.091 12.006 0.139 ;
     RECT  26.028 0.091 26.154 0.139 ;
     RECT  27.936 0.091 27.954 0.139 ;
     RECT  28.836 0.091 28.926 0.139 ;
     RECT  5.076 0.103 6.966 0.187 ;
     RECT  7.992 0.139 8.01 0.187 ;
     RECT  10.584 0.043 10.602 0.187 ;
     RECT  19.908 0.091 19.926 0.187 ;
     RECT  22.14 0.139 22.158 0.187 ;
     RECT  23.652 0.091 23.958 0.187 ;
     RECT  27.936 0.139 28.926 0.187 ;
     RECT  7.92 0.187 8.118 0.235 ;
     RECT  9.9 0.187 10.602 0.235 ;
     RECT  15.408 0.187 15.426 0.235 ;
     RECT  16.236 0.091 16.254 0.235 ;
     RECT  18.252 0.139 18.27 0.235 ;
     RECT  19.008 0.187 19.926 0.235 ;
     RECT  21.06 0.091 21.078 0.235 ;
     RECT  21.996 0.187 22.158 0.235 ;
     RECT  25.632 0.139 26.154 0.235 ;
     RECT  27.144 0.139 27.162 0.235 ;
     RECT  27.936 0.187 28.962 0.235 ;
     RECT  31.5 0.091 31.806 0.235 ;
     RECT  14.976 0.235 15.426 0.256 ;
     RECT  16.236 0.235 16.902 0.256 ;
     RECT  3.24 0.139 3.258 0.283 ;
     RECT  4.716 0.187 6.966 0.283 ;
     RECT  7.812 0.235 8.118 0.283 ;
     RECT  9.36 0.235 10.602 0.283 ;
     RECT  11.556 0.139 12.006 0.283 ;
     RECT  14.976 0.256 16.902 0.283 ;
     RECT  18.036 0.235 21.078 0.283 ;
     RECT  23.652 0.187 24.426 0.283 ;
     RECT  25.632 0.235 28.962 0.283 ;
     RECT  29.7 0.187 29.718 0.283 ;
     RECT  23.652 0.283 24.462 0.301 ;
     RECT  21.996 0.235 22.698 0.331 ;
     RECT  23.652 0.301 24.534 0.331 ;
     RECT  14.472 0.283 21.078 0.365 ;
     RECT  21.888 0.331 24.534 0.379 ;
     RECT  25.632 0.283 29.718 0.379 ;
     RECT  30.78 0.235 31.806 0.379 ;
     RECT  21.816 0.379 24.534 0.409 ;
     RECT  3.204 0.283 8.478 0.427 ;
     RECT  13.104 0.331 13.122 0.427 ;
     RECT  21.6 0.409 24.534 0.427 ;
     RECT  25.632 0.379 31.806 0.427 ;
     RECT  13.104 0.427 13.266 0.475 ;
     RECT  14.472 0.365 20.61 0.475 ;
     RECT  0.756 0.283 0.774 0.523 ;
     RECT  2.736 0.427 8.478 0.523 ;
     RECT  9.36 0.283 12.006 0.523 ;
     RECT  0.255 0.523 0.774 0.571 ;
     RECT  2.736 0.523 12.006 0.571 ;
     RECT  0.255 0.571 1.17 0.667 ;
     RECT  2.304 0.571 12.006 0.667 ;
     RECT  32.544 0.523 32.745 0.667 ;
     RECT  33.66 0.139 33.678 0.667 ;
     RECT  21.6 0.427 31.806 0.715 ;
     RECT  32.544 0.667 33.678 0.715 ;
     RECT  38.055 0.523 38.145 0.793 ;
     RECT  0.255 0.667 12.114 1.147 ;
     RECT  13.104 0.475 20.61 1.147 ;
     RECT  21.6 0.715 33.678 1.147 ;
     RECT  21.528 1.147 33.678 1.417 ;
     RECT  0.255 1.147 20.646 1.481 ;
     RECT  21.42 1.417 33.678 1.525 ;
     RECT  35.892 1.561 35.91 1.679 ;
     RECT  37.008 0.907 37.026 1.819 ;
     RECT  38.055 0.793 38.337 1.819 ;
     RECT  34.776 1.795 34.794 1.831 ;
     RECT  35.784 1.687 35.802 1.831 ;
     RECT  34.776 1.831 35.802 1.949 ;
     RECT  37.008 1.819 38.337 1.957 ;
     RECT  34.776 1.949 34.974 2.065 ;
     RECT  21.348 1.525 33.678 2.263 ;
     RECT  34.416 2.065 34.974 2.263 ;
     RECT  0.255 1.481 20.61 2.299 ;
     RECT  21.348 2.263 34.974 2.299 ;
     RECT  0.255 2.299 34.974 2.489 ;
     RECT  37.008 1.957 38.862 2.489 ;
     RECT  35.784 1.949 35.802 2.533 ;
     RECT  0.255 2.489 34.182 2.717 ;
     RECT  35.028 2.731 35.046 2.813 ;
     RECT  0.255 2.717 34.11 2.861 ;
     RECT  37.224 2.489 38.862 3.029 ;
     RECT  0.255 2.861 33.138 3.245 ;
     RECT  37.224 3.029 38.754 3.245 ;
     RECT  33.984 2.861 34.11 3.299 ;
     RECT  35.784 2.533 36.162 3.299 ;
     RECT  37.224 3.245 38.337 3.379 ;
     RECT  3.672 3.245 33.138 3.407 ;
     RECT  33.984 3.299 34.002 3.437 ;
     RECT  35.784 3.299 36.054 3.437 ;
     RECT  37.116 3.379 38.337 3.437 ;
     RECT  21.42 3.407 33.138 3.479 ;
     RECT  0.255 3.245 2.754 3.569 ;
     RECT  35.784 3.437 35.802 3.569 ;
     RECT  31.68 3.479 33.138 3.991 ;
     RECT  31.68 3.991 33.498 4.225 ;
     RECT  21.42 3.479 30.942 4.261 ;
     RECT  31.68 4.225 33.642 4.261 ;
     RECT  21.42 4.261 33.642 4.301 ;
     RECT  3.672 3.407 20.538 4.555 ;
     RECT  3.6 4.555 20.538 4.559 ;
     RECT  32.184 4.301 33.642 4.621 ;
     RECT  0.255 3.569 0.99 4.649 ;
     RECT  37.476 3.437 38.337 4.649 ;
     RECT  32.184 4.621 33.93 4.685 ;
     RECT  35.424 4.261 35.442 4.765 ;
     RECT  36.54 4.699 36.558 4.765 ;
     RECT  34.668 4.765 36.558 4.801 ;
     RECT  0.255 4.649 0.918 4.877 ;
     RECT  34.668 4.801 36.774 4.919 ;
     RECT  3.6 4.559 4.914 5.189 ;
     RECT  5.655 4.559 20.538 5.269 ;
     RECT  21.42 4.301 31.194 5.269 ;
     RECT  5.655 5.269 31.194 5.459 ;
     RECT  21.42 5.459 31.194 5.701 ;
     RECT  34.668 4.919 35.442 5.909 ;
     RECT  35.424 5.909 35.442 5.999 ;
     RECT  34.668 5.909 34.686 6.007 ;
     RECT  34.488 6.007 34.686 6.077 ;
     RECT  21.42 5.701 31.374 6.143 ;
     RECT  36.252 4.919 36.774 6.151 ;
     RECT  27.216 6.143 31.374 6.221 ;
     RECT  5.655 5.459 20.61 6.331 ;
     RECT  21.42 6.143 26.334 6.331 ;
     RECT  32.184 4.685 33.678 6.421 ;
     RECT  35.892 6.151 36.774 6.511 ;
     RECT  3.6 5.189 4.842 6.719 ;
     RECT  27.216 6.221 31.194 6.809 ;
     RECT  32.184 6.421 33.714 6.809 ;
     RECT  2.556 3.569 2.754 6.845 ;
     RECT  5.655 6.331 26.334 7.159 ;
     RECT  27.216 6.809 28.638 7.159 ;
     RECT  29.376 6.809 31.194 7.231 ;
     RECT  32.184 6.809 33.678 7.231 ;
     RECT  35.892 6.511 37.098 7.231 ;
     RECT  38.055 4.649 38.337 7.231 ;
     RECT  5.655 7.159 28.638 7.259 ;
     RECT  35.892 7.231 38.337 7.435 ;
     RECT  35.568 7.435 38.337 7.889 ;
     RECT  35.892 7.889 38.337 7.901 ;
     RECT  27.255 7.259 28.638 8.041 ;
     RECT  29.376 7.231 33.678 8.041 ;
     RECT  27.255 8.041 33.678 8.381 ;
     RECT  29.376 8.381 33.678 8.699 ;
     RECT  5.655 7.259 26.334 8.771 ;
     RECT  5.655 8.771 20.466 9.041 ;
     RECT  2.736 6.845 2.754 9.115 ;
     RECT  3.672 6.719 4.842 9.115 ;
     RECT  27.255 8.381 28.638 9.115 ;
     RECT  29.376 8.699 30.294 9.115 ;
     RECT  35.892 7.901 37.098 9.115 ;
     RECT  38.055 7.901 38.337 9.115 ;
     RECT  31.176 8.699 33.39 9.149 ;
     RECT  31.428 9.149 33.39 9.293 ;
     RECT  35.892 9.115 38.337 9.509 ;
     RECT  21.42 8.771 26.334 9.517 ;
     RECT  27.255 9.115 30.294 9.517 ;
     RECT  21.42 9.517 30.294 9.581 ;
     RECT  5.655 9.041 20.43 9.689 ;
     RECT  2.736 9.115 4.842 9.959 ;
     RECT  31.68 9.293 33.39 10.201 ;
     RECT  34.668 6.077 34.686 10.201 ;
     RECT  35.892 9.509 37.098 10.201 ;
     RECT  34.668 10.201 37.098 10.253 ;
     RECT  19.404 9.689 20.43 10.319 ;
     RECT  20.412 10.319 20.43 10.471 ;
     RECT  31.68 10.201 33.642 10.471 ;
     RECT  28.62 9.581 30.294 10.561 ;
     RECT  3.672 9.959 4.842 10.705 ;
     RECT  5.655 9.689 18.486 10.705 ;
     RECT  3.672 10.705 18.486 10.781 ;
     RECT  35.892 10.253 37.098 10.831 ;
     RECT  38.055 9.509 38.337 10.831 ;
     RECT  20.412 10.471 20.574 10.843 ;
     RECT  21.42 9.581 27.882 10.843 ;
     RECT  2.736 9.959 2.898 10.867 ;
     RECT  3.672 10.781 4.806 10.867 ;
     RECT  2.736 10.867 4.806 10.925 ;
     RECT  28.62 10.561 30.582 10.939 ;
     RECT  31.464 10.471 33.642 10.939 ;
     RECT  35.892 10.831 38.337 10.973 ;
     RECT  28.62 10.939 33.642 11.011 ;
     RECT  34.668 10.253 34.758 11.011 ;
     RECT  38.055 10.973 38.337 11.011 ;
     RECT  5.655 10.781 18.486 11.137 ;
     RECT  19.404 10.319 19.638 11.137 ;
     RECT  28.62 11.011 34.758 11.165 ;
     RECT  5.655 11.137 19.638 11.245 ;
     RECT  20.412 10.843 27.882 11.245 ;
     RECT  5.655 11.245 27.882 11.309 ;
     RECT  35.892 10.973 37.098 11.371 ;
     RECT  38.055 11.011 38.394 11.399 ;
     RECT  5.655 11.309 26.514 11.408 ;
     RECT  27.255 11.309 27.882 11.467 ;
     RECT  28.62 11.165 33.966 11.467 ;
     RECT  3.672 10.925 4.806 11.849 ;
     RECT  2.736 10.925 2.754 11.939 ;
     RECT  5.655 11.408 19.53 11.939 ;
     RECT  4.464 11.849 4.806 11.947 ;
     RECT  5.655 11.939 10.062 11.947 ;
     RECT  20.52 11.408 26.514 12.091 ;
     RECT  27.255 11.467 33.966 12.091 ;
     RECT  2.34 11.947 2.358 12.119 ;
     RECT  20.52 12.091 33.966 12.235 ;
     RECT  34.74 11.165 34.758 12.235 ;
     RECT  20.484 12.235 34.758 12.281 ;
     RECT  10.8 11.939 19.53 12.479 ;
     RECT  4.464 11.947 10.062 12.667 ;
     RECT  10.8 12.479 11.898 12.667 ;
     RECT  21.348 12.281 34.758 12.821 ;
     RECT  21.348 12.821 27.882 13.019 ;
     RECT  12.672 12.479 19.53 13.099 ;
     RECT  28.62 12.821 34.758 13.261 ;
     RECT  35.676 11.371 37.098 13.261 ;
     RECT  23.94 13.019 27.882 13.289 ;
     RECT  4.464 12.667 11.898 13.433 ;
     RECT  10.836 13.433 11.898 13.531 ;
     RECT  12.672 13.099 19.638 13.531 ;
     RECT  10.836 13.531 19.638 13.639 ;
     RECT  24.192 13.289 27.882 13.639 ;
     RECT  28.62 13.261 37.098 13.639 ;
     RECT  10.836 13.639 20.034 13.829 ;
     RECT  10.872 13.829 20.034 14.009 ;
     RECT  4.464 13.433 10.062 14.099 ;
     RECT  24.192 13.639 37.098 14.369 ;
     RECT  27.255 14.369 37.098 14.549 ;
     RECT  3.672 11.849 3.69 14.639 ;
     RECT  19.512 14.009 20.034 14.719 ;
     RECT  19.512 14.719 20.106 14.791 ;
     RECT  19.44 14.791 20.106 14.827 ;
     RECT  21.348 13.019 23.058 14.827 ;
     RECT  5.4 14.099 7.866 14.953 ;
     RECT  5.4 14.953 7.974 15.179 ;
     RECT  19.404 14.827 23.094 15.179 ;
     RECT  8.712 14.099 10.062 15.359 ;
     RECT  5.4 15.179 6.642 15.389 ;
     RECT  8.712 15.359 9.99 15.389 ;
     RECT  27.255 14.549 30.222 15.403 ;
     RECT  31.104 14.549 37.098 15.403 ;
     RECT  8.712 15.389 9.918 15.449 ;
     RECT  27.255 15.403 37.098 15.601 ;
     RECT  27.255 15.601 37.134 15.677 ;
     RECT  19.44 15.179 23.094 15.871 ;
     RECT  24.192 14.369 26.154 15.871 ;
     RECT  10.872 14.009 18.486 15.979 ;
     RECT  19.44 15.871 26.154 15.979 ;
     RECT  10.872 15.979 26.154 16.141 ;
     RECT  27.255 15.677 37.098 16.169 ;
     RECT  29.7 16.169 37.098 16.295 ;
     RECT  10.836 16.141 26.154 16.303 ;
     RECT  27.255 16.169 28.71 16.411 ;
     RECT  10.764 16.303 26.154 16.529 ;
     RECT  11.055 16.529 26.154 16.541 ;
     RECT  20.556 16.541 26.154 16.799 ;
     RECT  7.668 15.179 7.974 16.843 ;
     RECT  8.712 15.449 9.846 16.843 ;
     RECT  5.4 15.389 6.534 16.951 ;
     RECT  20.664 16.799 26.154 16.979 ;
     RECT  20.952 16.979 26.154 17.069 ;
     RECT  27 16.411 28.71 17.077 ;
     RECT  29.7 16.295 30.258 17.077 ;
     RECT  24.192 17.069 26.154 17.149 ;
     RECT  27 17.077 30.258 17.149 ;
     RECT  5.4 16.951 6.606 17.339 ;
     RECT  11.055 16.541 19.746 17.447 ;
     RECT  20.952 17.069 23.454 17.447 ;
     RECT  24.192 17.149 30.258 17.581 ;
     RECT  31.104 16.295 37.098 17.581 ;
     RECT  11.055 17.447 11.79 17.608 ;
     RECT  24.192 17.581 37.098 17.609 ;
     RECT  12.564 17.447 19.746 17.645 ;
     RECT  24.192 17.609 30.402 17.645 ;
     RECT  24.192 17.645 30.258 17.681 ;
     RECT  7.668 16.843 9.846 17.879 ;
     RECT  18.828 17.645 19.746 17.879 ;
     RECT  5.4 17.339 6.534 18.059 ;
     RECT  18.972 17.879 19.638 18.077 ;
     RECT  5.436 18.059 6.534 18.149 ;
     RECT  10.836 17.608 11.79 18.149 ;
     RECT  12.564 17.645 18.054 18.184 ;
     RECT  10.836 18.149 11.337 18.193 ;
     RECT  12.276 18.184 18.054 18.221 ;
     RECT  20.952 17.447 23.382 18.235 ;
     RECT  24.192 17.681 28.71 18.235 ;
     RECT  5.616 18.149 6.534 18.293 ;
     RECT  29.7 17.681 30.258 18.419 ;
     RECT  8.712 17.879 9.846 18.571 ;
     RECT  10.584 18.193 11.337 18.571 ;
     RECT  29.7 18.419 30.186 18.608 ;
     RECT  31.14 17.609 37.098 18.661 ;
     RECT  20.952 18.235 28.71 18.689 ;
     RECT  24.012 18.689 28.71 18.797 ;
     RECT  12.672 18.221 18.054 18.811 ;
     RECT  19.08 18.077 19.458 18.811 ;
     RECT  20.952 18.689 23.058 18.811 ;
     RECT  5.655 18.293 6.534 18.859 ;
     RECT  4.464 14.099 4.482 18.955 ;
     RECT  12.672 18.811 19.458 18.959 ;
     RECT  20.664 18.811 23.058 18.959 ;
     RECT  2.88 18.859 2.898 19.229 ;
     RECT  4.464 18.955 4.59 19.229 ;
     RECT  5.655 18.859 6.678 19.229 ;
     RECT  12.672 18.959 19.134 19.229 ;
     RECT  4.464 19.229 4.518 19.345 ;
     RECT  24.192 18.797 28.71 19.345 ;
     RECT  29.7 18.608 29.862 19.345 ;
     RECT  30.996 18.661 37.098 19.387 ;
     RECT  24.192 19.345 29.862 19.499 ;
     RECT  28.908 19.499 29.862 19.651 ;
     RECT  28.908 19.651 30.222 19.771 ;
     RECT  30.96 19.387 37.098 19.771 ;
     RECT  28.908 19.771 37.098 19.811 ;
     RECT  19.08 19.229 19.134 19.885 ;
     RECT  20.772 18.959 23.058 19.921 ;
     RECT  28.908 19.811 30.258 19.949 ;
     RECT  3.96 19.345 4.518 20.011 ;
     RECT  19.08 19.885 19.422 20.011 ;
     RECT  20.448 19.921 23.058 20.011 ;
     RECT  38.055 11.399 38.337 20.011 ;
     RECT  39.276 15.691 39.294 20.011 ;
     RECT  3.42 20.011 4.518 20.191 ;
     RECT  31.14 19.811 37.098 20.191 ;
     RECT  28.98 19.949 30.258 20.219 ;
     RECT  3.204 20.191 4.518 20.237 ;
     RECT  19.08 20.011 23.058 20.309 ;
     RECT  38.055 20.011 39.294 20.309 ;
     RECT  31.14 20.191 37.314 20.425 ;
     RECT  38.055 20.309 38.337 20.425 ;
     RECT  39.276 20.309 39.294 20.425 ;
     RECT  31.14 20.425 38.337 20.579 ;
     RECT  19.08 20.309 20.97 20.623 ;
     RECT  21.744 20.309 23.058 20.731 ;
     RECT  26.352 19.499 28.062 20.731 ;
     RECT  3.708 20.237 4.518 20.765 ;
     RECT  29.412 20.219 30.258 20.765 ;
     RECT  31.14 20.579 37.314 20.765 ;
     RECT  24.192 19.499 25.542 20.875 ;
     RECT  26.352 20.731 28.494 20.875 ;
     RECT  7.668 17.879 7.974 21.091 ;
     RECT  8.712 18.571 11.337 21.091 ;
     RECT  12.672 19.229 18.054 21.091 ;
     RECT  18.828 20.623 20.97 21.091 ;
     RECT  29.448 20.765 30.258 21.115 ;
     RECT  31.14 20.765 37.098 21.115 ;
     RECT  7.668 21.091 11.934 21.149 ;
     RECT  8.712 21.149 11.934 21.199 ;
     RECT  12.672 21.091 20.97 21.199 ;
     RECT  29.448 21.115 37.098 21.541 ;
     RECT  38.055 20.579 38.337 21.541 ;
     RECT  39.276 20.425 40.014 21.541 ;
     RECT  29.34 21.541 37.098 21.739 ;
     RECT  38.055 21.541 40.014 21.739 ;
     RECT  24.192 20.875 28.494 21.811 ;
     RECT  29.34 21.739 40.014 21.811 ;
     RECT  24.192 21.811 40.014 21.929 ;
     RECT  24.192 21.929 37.314 22.109 ;
     RECT  30.744 22.109 37.314 22.199 ;
     RECT  8.712 21.199 20.97 22.205 ;
     RECT  31.5 22.199 37.314 22.205 ;
     RECT  21.744 20.731 23.274 22.219 ;
     RECT  24.192 22.109 29.862 22.219 ;
     RECT  8.712 22.205 18.342 22.739 ;
     RECT  41.796 22.507 41.814 22.739 ;
     RECT  38.055 21.929 40.014 22.747 ;
     RECT  40.752 14.647 40.77 22.747 ;
     RECT  8.712 22.739 18.054 22.781 ;
     RECT  38.055 22.747 40.77 22.891 ;
     RECT  31.5 22.205 37.098 22.981 ;
     RECT  21.744 22.219 29.862 22.987 ;
     RECT  3.96 20.765 4.518 23.009 ;
     RECT  21.744 22.987 30.006 23.035 ;
     RECT  30.744 22.199 30.762 23.035 ;
     RECT  21.744 23.035 30.762 23.125 ;
     RECT  31.5 22.981 37.134 23.125 ;
     RECT  21.744 23.125 37.134 23.161 ;
     RECT  38.055 22.891 41.454 23.161 ;
     RECT  21.744 23.161 41.454 23.279 ;
     RECT  30.744 23.279 41.454 23.315 ;
     RECT  31.5 23.315 41.454 23.357 ;
     RECT  7.668 21.149 7.974 23.549 ;
     RECT  7.92 23.549 7.974 23.701 ;
     RECT  8.712 22.781 11.574 23.701 ;
     RECT  21.744 23.279 30.006 23.741 ;
     RECT  21.744 23.741 29.934 23.755 ;
     RECT  7.92 23.701 11.574 23.855 ;
     RECT  12.672 22.781 18.054 23.947 ;
     RECT  21.708 23.755 29.934 24.089 ;
     RECT  12.384 23.947 18.198 24.205 ;
     RECT  21.708 24.089 26.37 24.359 ;
     RECT  31.5 23.357 40.014 24.403 ;
     RECT  40.752 23.357 41.454 24.403 ;
     RECT  12.348 24.205 18.198 24.469 ;
     RECT  30.744 23.315 30.762 24.475 ;
     RECT  31.5 24.403 41.454 24.475 ;
     RECT  12.276 24.469 18.198 24.509 ;
     RECT  7.92 23.855 11.502 24.523 ;
     RECT  1.728 24.523 1.746 24.629 ;
     RECT  7.308 24.523 11.502 24.629 ;
     RECT  19.08 22.205 20.97 24.745 ;
     RECT  21.708 24.359 25.83 24.745 ;
     RECT  5.655 19.229 6.534 24.781 ;
     RECT  5.655 24.781 7.11 24.845 ;
     RECT  12.492 24.509 18.198 24.871 ;
     RECT  19.08 24.745 25.83 24.871 ;
     RECT  7.884 24.629 11.502 24.899 ;
     RECT  12.492 24.871 25.83 24.941 ;
     RECT  19.08 24.941 25.83 24.971 ;
     RECT  7.884 24.899 7.974 25.085 ;
     RECT  27.108 24.089 29.934 25.099 ;
     RECT  19.152 24.971 25.83 25.277 ;
     RECT  19.404 25.277 25.83 25.285 ;
     RECT  26.676 25.099 29.934 25.285 ;
     RECT  12.492 24.941 18.198 25.321 ;
     RECT  8.712 24.899 11.502 25.411 ;
     RECT  12.276 25.321 18.198 25.411 ;
     RECT  5.655 24.845 6.858 25.547 ;
     RECT  5.655 25.547 6.678 25.709 ;
     RECT  7.92 25.085 7.974 25.717 ;
     RECT  8.712 25.411 18.198 25.717 ;
     RECT  7.92 25.717 18.198 25.789 ;
     RECT  7.92 25.789 18.486 25.979 ;
     RECT  12.564 25.979 18.486 26.131 ;
     RECT  19.404 25.285 29.934 26.131 ;
     RECT  12.564 26.131 29.934 26.189 ;
     RECT  19.656 26.189 29.934 26.203 ;
     RECT  19.656 26.203 29.97 26.249 ;
     RECT  3.024 26.221 3.042 26.257 ;
     RECT  3.024 26.257 3.114 26.285 ;
     RECT  3.096 26.285 3.114 26.357 ;
     RECT  3.96 23.009 4.482 26.761 ;
     RECT  21.708 26.249 29.97 26.789 ;
     RECT  5.655 25.709 6.534 26.797 ;
     RECT  30.744 24.475 41.454 26.797 ;
     RECT  19.656 26.249 20.97 26.825 ;
     RECT  5.655 26.797 6.606 26.923 ;
     RECT  12.564 26.189 18.918 27.059 ;
     RECT  5.655 26.923 7.146 27.067 ;
     RECT  5.58 27.067 7.146 27.211 ;
     RECT  7.92 25.979 11.502 27.211 ;
     RECT  12.564 27.059 18.666 27.245 ;
     RECT  5.58 27.211 11.502 27.329 ;
     RECT  5.58 27.329 6.678 27.337 ;
     RECT  19.728 26.825 20.97 27.481 ;
     RECT  21.708 26.789 29.934 27.481 ;
     RECT  19.728 27.481 29.934 27.571 ;
     RECT  30.672 26.797 41.454 27.571 ;
     RECT  19.728 27.571 41.454 27.599 ;
     RECT  21.708 27.599 41.454 27.677 ;
     RECT  7.56 27.329 11.502 27.869 ;
     RECT  5.364 27.337 6.678 27.913 ;
     RECT  3.888 26.761 4.482 28.183 ;
     RECT  5.22 27.913 6.678 28.183 ;
     RECT  12.564 27.245 18.054 28.219 ;
     RECT  3.888 28.183 6.822 28.255 ;
     RECT  3.636 28.255 6.822 28.319 ;
     RECT  3.636 28.319 6.678 28.409 ;
     RECT  3.636 28.409 4.77 28.445 ;
     RECT  19.728 27.599 20.97 28.453 ;
     RECT  21.708 27.677 29.934 28.453 ;
     RECT  12.24 28.219 18.054 28.507 ;
     RECT  5.655 28.409 6.678 29.083 ;
     RECT  12.24 28.507 18.558 29.083 ;
     RECT  19.728 28.453 29.934 29.191 ;
     RECT  30.672 27.677 41.454 29.191 ;
     RECT  5.655 29.083 7.002 29.489 ;
     RECT  12.24 29.083 18.594 29.489 ;
     RECT  19.728 29.191 41.454 29.759 ;
     RECT  4.248 28.445 4.482 30.235 ;
     RECT  5.655 29.489 6.534 30.235 ;
     RECT  12.24 29.489 18.054 30.271 ;
     RECT  4.248 30.235 6.534 30.299 ;
     RECT  5.655 30.299 6.534 30.307 ;
     RECT  19.728 29.759 30.762 30.343 ;
     RECT  5.655 30.307 6.858 30.407 ;
     RECT  12.24 30.271 18.09 30.451 ;
     RECT  19.26 30.343 30.762 30.451 ;
     RECT  4.248 30.299 4.482 30.811 ;
     RECT  7.92 27.869 11.502 30.839 ;
     RECT  12.24 30.451 30.762 30.847 ;
     RECT  31.5 29.759 41.454 30.847 ;
     RECT  4.212 30.811 4.482 30.848 ;
     RECT  7.92 30.839 8.73 30.949 ;
     RECT  9.54 30.839 11.502 30.955 ;
     RECT  12.24 30.847 41.454 30.955 ;
     RECT  7.848 30.949 8.73 30.992 ;
     RECT  9.54 30.955 41.454 31.109 ;
     RECT  9.54 31.109 11.337 31.277 ;
     RECT  9.612 31.277 11.337 31.289 ;
     RECT  5.655 30.407 6.534 31.339 ;
     RECT  5.4 31.339 6.534 31.379 ;
     RECT  12.24 31.109 41.454 31.379 ;
     RECT  5.655 31.379 6.534 31.621 ;
     RECT  5.655 31.621 6.894 31.709 ;
     RECT  7.884 30.992 8.73 32.299 ;
     RECT  12.24 31.379 18.09 32.305 ;
     RECT  18.828 31.379 41.454 32.305 ;
     RECT  7.38 32.299 8.73 32.339 ;
     RECT  7.92 32.339 8.73 32.341 ;
     RECT  9.72 31.289 11.337 32.341 ;
     RECT  2.916 31.963 2.934 32.459 ;
     RECT  12.24 32.305 41.454 32.477 ;
     RECT  4.248 30.848 4.482 32.539 ;
     RECT  5.655 31.709 6.534 32.539 ;
     RECT  4.248 32.539 6.534 32.957 ;
     RECT  4.248 32.957 4.482 33.241 ;
     RECT  12.24 32.477 18.09 33.385 ;
     RECT  18.972 32.477 41.454 33.385 ;
     RECT  3.996 33.241 4.482 33.421 ;
     RECT  7.92 32.341 11.337 33.883 ;
     RECT  7.776 33.883 11.337 33.961 ;
     RECT  12.24 33.385 41.454 33.961 ;
     RECT  7.776 33.961 41.454 34.079 ;
     RECT  7.92 34.079 41.454 34.781 ;
     RECT  12.06 34.781 41.454 35.168 ;
     RECT  7.92 34.781 11.337 36.187 ;
     RECT  12.24 35.168 41.454 36.187 ;
     RECT  7.92 36.187 41.454 37.049 ;
     RECT  2.556 37.099 2.574 37.319 ;
     RECT  5.655 32.957 6.534 37.363 ;
     RECT  12.132 37.049 41.454 37.565 ;
     RECT  5.655 37.363 6.57 37.675 ;
     RECT  7.92 37.049 11.337 37.675 ;
     RECT  5.655 37.675 6.606 37.859 ;
     RECT  5.655 37.859 6.57 37.867 ;
     RECT  5.616 37.867 6.57 38.129 ;
     RECT  7.848 37.675 11.337 38.173 ;
     RECT  3.816 33.421 4.482 38.201 ;
     RECT  5.616 38.129 6.534 38.777 ;
     RECT  5.655 38.777 6.534 39.091 ;
     RECT  7.776 38.173 11.337 39.091 ;
     RECT  5.655 39.091 11.337 39.251 ;
     RECT  5.655 39.251 6.858 39.317 ;
     RECT  7.776 39.251 11.337 39.929 ;
     RECT  12.24 37.565 41.454 39.979 ;
     RECT  12.204 39.979 41.454 40.019 ;
     RECT  4.464 38.201 4.482 40.631 ;
     RECT  7.92 39.929 11.337 41.071 ;
     RECT  12.24 40.019 41.454 41.071 ;
     RECT  7.92 41.071 41.454 41.611 ;
     RECT  7.38 41.611 41.454 44.789 ;
     RECT  7.38 44.789 11.337 45.643 ;
     RECT  12.312 44.789 41.454 45.643 ;
     RECT  7.38 45.643 41.454 46.769 ;
     RECT  4.32 49.051 4.338 49.432 ;
     RECT  5.655 39.317 6.534 49.435 ;
     RECT  4.248 49.432 4.338 49.469 ;
     RECT  5.655 49.435 7.038 49.475 ;
     RECT  7.812 46.769 41.454 49.855 ;
     RECT  7.812 49.855 41.634 49.891 ;
     RECT  7.272 49.891 41.634 50.045 ;
     RECT  5.655 49.475 6.534 51.931 ;
     RECT  5.655 51.931 6.894 52.439 ;
     RECT  7.812 50.045 41.634 52.861 ;
     RECT  7.812 52.861 41.922 52.979 ;
     RECT  7.812 52.979 41.634 54.103 ;
     RECT  7.812 54.103 41.778 54.235 ;
     RECT  7.452 54.235 41.778 54.481 ;
     RECT  7.272 54.481 41.778 54.557 ;
     RECT  7.812 54.557 41.778 55.901 ;
     RECT  7.812 55.901 41.634 56.875 ;
     RECT  7.812 56.875 41.67 57.037 ;
     RECT  7.812 57.037 41.742 57.137 ;
     RECT  4.104 57.643 4.122 57.839 ;
     RECT  7.812 57.137 41.67 58.225 ;
     RECT  7.632 58.225 41.67 58.555 ;
     RECT  7.416 58.555 41.67 58.648 ;
     RECT  5.655 52.439 6.534 58.729 ;
     RECT  7.308 58.648 41.67 58.729 ;
     RECT  5.655 58.729 41.67 58.757 ;
     RECT  5.655 58.757 7.002 59.297 ;
     RECT  7.812 58.757 41.67 62.707 ;
     RECT  5.655 59.297 6.534 63.883 ;
     RECT  5.655 63.883 6.57 64.021 ;
     RECT  5.655 64.021 6.858 64.121 ;
     RECT  7.812 62.707 41.742 66.712 ;
     RECT  7.524 66.712 41.742 66.749 ;
     RECT  5.655 64.121 6.534 70.141 ;
     RECT  7.812 66.749 41.742 70.141 ;
     RECT  5.655 70.141 41.742 70.259 ;
     RECT  5.655 70.259 6.966 70.301 ;
     RECT  4.176 70.171 4.194 70.459 ;
     RECT  3.24 70.459 3.258 70.529 ;
     RECT  4.176 70.459 4.878 70.529 ;
     RECT  7.812 70.259 41.742 70.733 ;
     RECT  7.812 70.733 41.202 70.799 ;
     RECT  4.032 70.645 4.05 71.069 ;
     RECT  5.655 70.301 6.858 71.069 ;
     RECT  7.812 70.799 41.058 71.069 ;
     RECT  6.84 71.069 6.858 71.213 ;
     RECT  7.812 71.069 8.298 71.249 ;
     RECT  9.252 71.069 41.058 71.453 ;
     RECT  9.252 71.453 40.986 71.681 ;
     RECT  9.864 71.681 40.986 71.885 ;
     RECT  9.864 71.885 25.326 71.951 ;
     RECT  10.908 71.951 25.326 72.221 ;
     RECT  9.864 71.951 9.882 72.257 ;
     RECT  26.136 71.885 40.986 72.317 ;
     RECT  0.255 4.877 0.537 72.377 ;
     RECT  5.655 71.069 5.937 72.377 ;
     RECT  11.055 72.221 25.326 72.377 ;
     RECT  26.172 72.317 40.986 72.379 ;
     RECT  11.196 72.377 25.326 72.461 ;
     RECT  11.196 72.461 18.594 72.509 ;
     RECT  26.172 72.379 41.022 72.557 ;
     RECT  0.447 72.377 0.537 72.647 ;
     RECT  5.847 72.377 5.937 72.647 ;
     RECT  26.172 72.557 40.842 72.653 ;
     RECT  11.196 72.509 12.582 72.701 ;
     RECT  13.68 72.509 17.478 72.701 ;
     RECT  11.196 72.701 12.078 72.893 ;
     RECT  33.984 72.653 40.842 72.893 ;
     RECT  26.172 72.653 33.066 72.941 ;
     RECT  19.368 72.461 25.326 72.989 ;
     RECT  26.172 72.941 33.03 72.989 ;
     RECT  11.196 72.893 11.214 73.037 ;
     RECT  14.076 72.701 17.478 73.037 ;
     RECT  33.984 72.893 37.746 73.037 ;
     RECT  38.52 72.893 40.842 73.037 ;
     RECT  14.076 73.037 14.202 73.085 ;
     RECT  15.156 73.037 17.262 73.085 ;
     RECT  20.844 72.989 25.326 73.085 ;
     RECT  34.164 73.037 37.746 73.085 ;
     RECT  14.184 73.085 14.202 73.133 ;
     RECT  15.156 73.085 15.822 73.133 ;
     RECT  18.252 72.509 18.594 73.133 ;
     RECT  19.368 72.989 19.818 73.133 ;
     RECT  20.844 73.085 23.346 73.133 ;
     RECT  24.12 73.085 25.002 73.133 ;
     RECT  26.172 72.989 31.23 73.133 ;
     RECT  32.076 72.989 33.03 73.133 ;
     RECT  35.532 73.085 36.342 73.133 ;
     RECT  37.116 73.085 37.602 73.133 ;
     RECT  38.556 73.037 40.842 73.133 ;
     RECT  18.252 73.133 18.27 73.181 ;
     RECT  21.816 73.133 23.274 73.181 ;
     RECT  27.072 73.133 27.846 73.181 ;
     RECT  30.564 73.133 31.23 73.181 ;
     RECT  27.144 73.181 27.846 73.229 ;
     RECT  30.564 73.181 31.158 73.229 ;
     RECT  32.4 73.133 33.03 73.229 ;
     RECT  34.524 73.085 34.542 73.229 ;
     RECT  37.584 73.133 37.602 73.229 ;
     RECT  38.664 73.133 39.618 73.229 ;
     RECT  11.988 72.893 12.078 73.277 ;
     RECT  16.632 73.085 17.262 73.277 ;
     RECT  21.816 73.181 23.202 73.277 ;
     RECT  27.144 73.229 27.162 73.277 ;
     RECT  7.812 71.249 7.83 73.325 ;
     RECT  16.704 73.277 16.722 73.325 ;
     RECT  19.728 73.133 19.746 73.325 ;
     RECT  28.836 73.133 28.962 73.325 ;
     RECT  30.564 73.229 30.582 73.325 ;
     RECT  32.868 73.229 32.886 73.325 ;
     RECT  36.036 73.133 36.342 73.325 ;
     RECT  39.6 73.229 39.618 73.325 ;
     RECT  11.988 73.277 12.006 73.373 ;
     RECT  22.464 73.277 22.482 73.373 ;
     RECT  24.156 73.133 24.174 73.373 ;
     RECT  28.944 73.325 28.962 73.373 ;
     RECT  36.324 73.325 36.342 73.373 ;
     RECT  40.824 73.133 40.842 73.373 ;
    LAYER M4 ;
     RECT  0.248 0.528 0.44 72.372 ;
     RECT  0.44 0.528 0.544 72.642 ;
     RECT  0.544 0.528 0.701 2.376 ;
     RECT  0.544 4.848 0.94 4.872 ;
     RECT  0.701 0.288 1.573 2.376 ;
     RECT  0.544 9.696 1.717 9.72 ;
     RECT  1.573 0.288 1.765 2.424 ;
     RECT  1.717 24.528 1.801 24.552 ;
     RECT  1.765 0.288 2.252 2.712 ;
     RECT  2.501 37.104 2.585 37.128 ;
     RECT  1.717 8.784 2.837 9.72 ;
     RECT  2.861 31.968 2.945 31.992 ;
     RECT  2.869 18.864 2.953 18.888 ;
     RECT  2.869 26.256 3.053 26.28 ;
     RECT  2.252 0.288 3.068 2.76 ;
     RECT  3.068 0.288 3.155 3.24 ;
     RECT  3.155 0.288 3.229 2.616 ;
     RECT  3.212 70.464 3.299 70.488 ;
     RECT  3.26 10.896 3.347 10.92 ;
     RECT  3.164 20.208 3.365 20.232 ;
     RECT  2.837 8.784 3.377 9.144 ;
     RECT  3.365 20.016 3.449 20.232 ;
     RECT  2.629 4.56 3.629 4.584 ;
     RECT  3.685 20.592 3.772 20.76 ;
     RECT  3.772 20.592 4.025 20.616 ;
     RECT  3.941 33.264 4.025 33.288 ;
     RECT  4.028 36.96 4.115 36.984 ;
     RECT  3.229 0.144 4.124 2.616 ;
     RECT  3.877 5.712 4.124 5.736 ;
     RECT  3.836 7.392 4.124 7.416 ;
     RECT  4.124 5.712 4.133 7.416 ;
     RECT  3.973 57.648 4.133 57.672 ;
     RECT  4.117 70.176 4.205 70.2 ;
     RECT  4.133 6.672 4.211 7.416 ;
     RECT  3.973 49.056 4.237 49.08 ;
     RECT  3.973 30.816 4.241 30.84 ;
     RECT  4.193 10.8 4.277 10.824 ;
     RECT  4.211 6.864 4.309 7.416 ;
     RECT  4.237 49.056 4.321 49.464 ;
     RECT  4.321 49.056 4.349 49.08 ;
     RECT  4.309 6.864 4.405 7.464 ;
     RECT  4.345 38.112 4.429 38.136 ;
     RECT  4.517 18.96 4.601 18.984 ;
     RECT  4.556 4.272 4.643 4.296 ;
     RECT  4.405 6.864 4.673 7.512 ;
     RECT  4.124 0.144 4.885 3.24 ;
     RECT  4.885 0.144 5.065 3.96 ;
     RECT  4.988 32.928 5.093 32.952 ;
     RECT  4.844 70.464 5.509 70.488 ;
     RECT  5.065 0.096 5.648 3.96 ;
     RECT  4.673 6.864 5.648 7.128 ;
     RECT  3.377 8.784 5.648 8.808 ;
     RECT  5.228 10.752 5.648 10.776 ;
     RECT  5.509 17.184 5.648 17.208 ;
     RECT  5.125 27.072 5.648 27.096 ;
     RECT  3.397 28.416 5.648 28.44 ;
     RECT  5.093 30.24 5.648 30.264 ;
     RECT  5.389 31.344 5.648 31.368 ;
     RECT  5.093 32.544 5.648 32.952 ;
     RECT  5.509 70.272 5.648 70.488 ;
     RECT  5.648 0.096 5.821 72.372 ;
     RECT  5.821 0.048 5.84 72.372 ;
     RECT  5.84 0.048 5.944 72.642 ;
     RECT  5.944 14.016 6.131 15.384 ;
     RECT  5.944 37.68 6.227 39.24 ;
     RECT  5.944 51.936 6.275 52.44 ;
     RECT  6.131 14.832 6.293 15.384 ;
     RECT  6.227 37.68 6.515 38.184 ;
     RECT  5.944 63.888 6.581 63.912 ;
     RECT  5.944 28.464 6.611 29.112 ;
     RECT  6.515 37.68 6.617 37.704 ;
     RECT  5.944 18.864 6.689 18.888 ;
     RECT  5.944 25.104 6.689 25.704 ;
     RECT  6.293 15.36 6.755 15.384 ;
     RECT  6.689 25.104 6.797 25.128 ;
     RECT  5.944 5.712 6.833 7.464 ;
     RECT  5.944 31.68 6.94 31.704 ;
     RECT  6.275 51.936 6.94 51.96 ;
     RECT  6.833 7.104 6.941 7.464 ;
     RECT  5.944 58.8 6.956 58.824 ;
     RECT  6.908 70.272 6.995 70.296 ;
     RECT  6.611 29.088 7.013 29.112 ;
     RECT  6.941 7.392 7.043 7.464 ;
     RECT  6.956 58.8 7.043 59.064 ;
     RECT  5.944 27.072 7.117 27.096 ;
     RECT  6.227 39.168 7.121 39.24 ;
     RECT  5.944 11.184 7.148 11.208 ;
     RECT  6.997 49.44 7.189 49.464 ;
     RECT  7.043 7.44 7.237 7.464 ;
     RECT  7.189 49.44 7.261 49.992 ;
     RECT  7.052 24.816 7.297 24.84 ;
     RECT  7.237 54.528 7.324 54.552 ;
     RECT  7.261 49.44 7.345 50.04 ;
     RECT  7.297 58.656 7.388 58.68 ;
     RECT  5.944 41.616 7.409 41.64 ;
     RECT  7.333 32.304 7.42 32.328 ;
     RECT  7.117 26.928 7.427 27.096 ;
     RECT  7.388 58.56 7.427 58.68 ;
     RECT  7.345 49.44 7.429 49.992 ;
     RECT  6.949 12.528 7.445 12.552 ;
     RECT  7.429 49.056 7.445 49.992 ;
     RECT  7.427 58.56 7.475 58.584 ;
     RECT  7.397 54.24 7.481 54.264 ;
     RECT  7.148 10.464 7.525 11.208 ;
     RECT  5.944 0.048 7.541 4.248 ;
     RECT  6.833 5.712 7.541 6.024 ;
     RECT  7.429 66.72 7.553 66.744 ;
     RECT  7.121 39.216 7.571 39.24 ;
     RECT  7.429 27.408 7.589 27.432 ;
     RECT  7.237 7.44 7.697 7.512 ;
     RECT  7.429 45.648 7.697 45.672 ;
     RECT  7.525 10.272 7.724 11.208 ;
     RECT  7.429 33.888 7.805 33.912 ;
     RECT  7.724 10.272 7.811 11.928 ;
     RECT  7.772 15.072 7.859 15.096 ;
     RECT  7.297 24.528 7.868 24.84 ;
     RECT  7.813 30.96 7.9 30.984 ;
     RECT  7.837 37.68 7.921 37.704 ;
     RECT  7.541 0.048 7.948 6.024 ;
     RECT  7.868 24.528 7.955 25.08 ;
     RECT  7.868 64.272 7.955 64.296 ;
     RECT  7.829 17.664 7.957 17.688 ;
     RECT  7.445 49.056 7.985 49.08 ;
     RECT  7.948 5.712 8.021 6.024 ;
     RECT  8.005 70.272 8.092 70.296 ;
     RECT  7.948 0.048 8.147 4.248 ;
     RECT  7.717 9.12 8.156 9.144 ;
     RECT  7.811 10.272 8.156 11.208 ;
     RECT  7.957 17.568 8.161 17.688 ;
     RECT  8.089 21.12 8.173 21.144 ;
     RECT  8.161 16.848 8.201 17.688 ;
     RECT  7.955 24.528 8.233 24.552 ;
     RECT  8.156 9.12 8.243 11.208 ;
     RECT  7.697 7.488 8.309 7.512 ;
     RECT  8.233 23.856 8.339 24.552 ;
     RECT  8.341 60.912 8.425 60.936 ;
     RECT  8.339 24.528 8.461 24.552 ;
     RECT  8.201 16.848 8.531 17.592 ;
     RECT  8.444 40.08 8.531 40.104 ;
     RECT  8.531 17.568 8.561 17.592 ;
     RECT  8.021 6 8.581 6.024 ;
     RECT  8.581 6 8.629 6.312 ;
     RECT  8.389 13.104 8.725 13.128 ;
     RECT  8.243 10.272 8.773 11.208 ;
     RECT  8.725 12.24 8.773 13.128 ;
     RECT  8.233 43.104 8.809 43.128 ;
     RECT  8.533 63.888 8.849 63.912 ;
     RECT  8.773 10.272 8.867 13.128 ;
     RECT  8.917 15.504 8.981 15.528 ;
     RECT  8.533 70.176 8.993 70.2 ;
     RECT  8.981 14.88 9.053 15.528 ;
     RECT  8.972 33.888 9.059 33.912 ;
     RECT  8.809 42.192 9.107 43.128 ;
     RECT  9.053 14.784 9.137 15.528 ;
     RECT  9.089 46.272 9.173 46.296 ;
     RECT  8.869 21.696 9.205 21.72 ;
     RECT  9.107 42.912 9.209 43.128 ;
     RECT  9.137 15.36 9.251 15.528 ;
     RECT  8.867 12.192 9.313 13.128 ;
     RECT  9.109 60.816 9.317 60.84 ;
     RECT  8.881 18.576 9.349 18.6 ;
     RECT  8.147 3.408 9.353 4.248 ;
     RECT  9.205 21.696 9.389 21.96 ;
     RECT  9.308 53.952 9.395 53.976 ;
     RECT  9.389 21.696 9.397 21.72 ;
     RECT  8.147 0.048 9.421 2.424 ;
     RECT  9.353 3.408 9.421 4.152 ;
     RECT  9.349 18.24 9.421 18.6 ;
     RECT  8.243 9.12 9.452 9.144 ;
     RECT  8.867 10.272 9.452 11.208 ;
     RECT  8.629 6 9.461 6.408 ;
     RECT  9.421 18.24 9.577 18.696 ;
     RECT  9.109 57.648 9.605 57.672 ;
     RECT  8.917 19.968 9.673 19.992 ;
     RECT  9.397 21.312 9.673 21.72 ;
     RECT  9.313 12.192 9.683 13.656 ;
     RECT  9.452 9.12 9.721 11.208 ;
     RECT  9.673 51.648 9.757 51.672 ;
     RECT  9.673 19.968 9.877 21.72 ;
     RECT  9.461 6 9.893 6.312 ;
     RECT  9.683 12.192 9.916 13.464 ;
     RECT  9.877 19.68 9.929 21.72 ;
     RECT  9.877 33.84 9.953 33.864 ;
     RECT  9.685 47.04 9.965 47.064 ;
     RECT  9.721 9.12 9.98 9.672 ;
     RECT  9.932 38.256 10.019 38.28 ;
     RECT  9.721 10.704 10.021 11.208 ;
     RECT  9.916 12.192 10.021 12.696 ;
     RECT  9.953 33.792 10.037 33.864 ;
     RECT  9.251 15.36 10.045 15.384 ;
     RECT  9.98 8.88 10.067 9.672 ;
     RECT  9.929 19.68 10.105 21.144 ;
     RECT  10.124 40.992 10.241 41.016 ;
     RECT  10.249 45.696 10.261 45.72 ;
     RECT  9.733 65.232 10.261 65.256 ;
     RECT  9.421 0.048 10.316 4.152 ;
     RECT  10.261 47.28 10.321 47.304 ;
     RECT  9.493 31.248 10.357 31.272 ;
     RECT  10.261 37.776 10.393 37.8 ;
     RECT  10.261 65.232 10.453 65.592 ;
     RECT  10.316 0.048 10.613 4.872 ;
     RECT  10.105 19.2 10.681 21.144 ;
     RECT  10.645 7.392 10.693 7.416 ;
     RECT  10.261 45.168 10.741 45.72 ;
     RECT  10.681 18.24 10.789 21.144 ;
     RECT  10.741 45.168 10.789 46.152 ;
     RECT  9.209 43.104 10.825 43.128 ;
     RECT  10.241 40.992 10.837 41.16 ;
     RECT  10.825 49.776 10.837 49.8 ;
     RECT  10.453 65.04 10.837 65.592 ;
     RECT  10.357 31.248 10.885 31.752 ;
     RECT  10.037 33.84 10.885 33.864 ;
     RECT  10.613 0.096 10.892 4.872 ;
     RECT  9.893 6 10.892 6.024 ;
     RECT  10.693 7.152 10.933 7.416 ;
     RECT  10.067 9.12 10.933 9.672 ;
     RECT  10.021 10.704 10.933 12.696 ;
     RECT  10.825 43.008 10.933 43.128 ;
     RECT  10.321 47.28 10.933 47.928 ;
     RECT  10.892 0.096 11.048 6.024 ;
     RECT  10.933 7.104 11.048 7.416 ;
     RECT  10.933 9.12 11.048 12.696 ;
     RECT  10.837 15.984 11.048 16.44 ;
     RECT  10.789 17.616 11.048 21.144 ;
     RECT  10.885 23.568 11.048 23.592 ;
     RECT  10.837 26.16 11.048 26.184 ;
     RECT  10.421 27.936 11.048 27.96 ;
     RECT  9.685 29.76 11.048 29.784 ;
     RECT  10.885 30.96 11.048 31.752 ;
     RECT  10.885 33.84 11.048 34.776 ;
     RECT  10.393 37.008 11.048 37.8 ;
     RECT  10.837 40.512 11.048 41.16 ;
     RECT  10.933 42.72 11.048 43.128 ;
     RECT  10.789 44.64 11.048 46.152 ;
     RECT  10.933 47.28 11.048 48.696 ;
     RECT  10.837 49.776 11.048 50.568 ;
     RECT  10.717 51.936 11.048 51.96 ;
     RECT  10.837 64.896 11.048 65.592 ;
     RECT  9.685 69.984 11.048 70.008 ;
     RECT  7.801 73.296 11.048 73.32 ;
     RECT  11.048 0.096 11.344 73.32 ;
     RECT  11.344 0.096 11.459 5.4 ;
     RECT  11.344 9.36 11.459 15.912 ;
     RECT  11.344 20.496 11.459 25.656 ;
     RECT  11.344 30.576 11.459 30.984 ;
     RECT  11.459 9.36 11.485 14.28 ;
     RECT  11.344 57.072 11.485 58.68 ;
     RECT  11.459 30.864 11.507 30.984 ;
     RECT  11.485 9.36 11.549 13.992 ;
     RECT  11.459 21.12 11.629 25.656 ;
     RECT  11.344 67.296 11.657 67.32 ;
     RECT  11.344 51.888 11.693 52.536 ;
     RECT  11.507 30.96 11.765 30.984 ;
     RECT  11.344 48.624 11.765 48.648 ;
     RECT  11.344 17.088 11.809 17.112 ;
     RECT  11.549 10.56 11.909 13.992 ;
     RECT  11.344 44.448 11.917 44.616 ;
     RECT  11.629 21.12 11.945 22.776 ;
     RECT  11.344 34.752 11.945 35.16 ;
     RECT  11.344 70.944 11.977 73.32 ;
     RECT  11.909 10.56 11.981 12.456 ;
     RECT  11.981 10.56 11.987 11.4 ;
     RECT  11.459 0.096 12.017 2.616 ;
     RECT  11.945 21.648 12.025 22.776 ;
     RECT  11.344 36.192 12.061 36.552 ;
     RECT  11.945 35.136 12.089 35.16 ;
     RECT  11.344 53.568 12.089 53.688 ;
     RECT  11.987 10.704 12.097 11.4 ;
     RECT  11.629 23.952 12.097 25.656 ;
     RECT  12.097 23.952 12.125 25.464 ;
     RECT  11.459 15.408 12.133 15.912 ;
     RECT  11.344 45.648 12.169 45.672 ;
     RECT  12.025 22.752 12.179 22.776 ;
     RECT  11.344 63.216 12.179 63.768 ;
     RECT  11.344 61.344 12.197 61.368 ;
     RECT  11.909 13.536 12.233 13.992 ;
     RECT  11.344 39.984 12.233 40.008 ;
     RECT  11.344 49.968 12.233 49.992 ;
     RECT  11.344 55.248 12.269 55.272 ;
     RECT  12.233 13.968 12.323 13.992 ;
     RECT  12.125 23.952 12.323 25.368 ;
     RECT  11.344 41.424 12.337 41.448 ;
     RECT  11.485 57.552 12.377 58.68 ;
     RECT  12.323 23.952 12.413 25.128 ;
     RECT  12.179 63.216 12.428 63.288 ;
     RECT  12.428 63.12 12.449 63.288 ;
     RECT  12.025 21.648 12.457 21.672 ;
     RECT  12.373 61.584 12.46 61.608 ;
     RECT  11.917 44.544 12.476 44.616 ;
     RECT  12.017 0.144 12.509 2.616 ;
     RECT  11.459 3.648 12.509 4.584 ;
     RECT  12.449 63.12 12.515 63.144 ;
     RECT  12.061 36.48 12.517 36.552 ;
     RECT  11.344 37.536 12.517 37.56 ;
     RECT  12.337 40.992 12.517 41.448 ;
     RECT  11.344 18.192 12.524 18.216 ;
     RECT  12.469 30.528 12.557 30.552 ;
     RECT  12.469 33.072 12.557 33.096 ;
     RECT  11.693 52.512 12.557 52.536 ;
     RECT  11.981 12.432 12.563 12.456 ;
     RECT  12.517 36.48 12.563 37.56 ;
     RECT  12.476 44.544 12.563 45.528 ;
     RECT  12.089 53.568 12.563 53.592 ;
     RECT  11.549 9.36 12.593 9.384 ;
     RECT  12.524 17.856 12.611 18.216 ;
     RECT  12.517 62.352 12.629 62.376 ;
     RECT  12.563 36.48 12.665 37.32 ;
     RECT  12.133 15.696 12.697 15.912 ;
     RECT  12.097 11.04 12.737 11.4 ;
     RECT  12.563 44.544 12.737 44.664 ;
     RECT  11.344 6.768 12.757 7.368 ;
     RECT  12.757 6.768 12.805 7.992 ;
     RECT  12.517 64.992 12.881 65.016 ;
     RECT  12.517 40.992 12.917 42.024 ;
     RECT  12.805 6.768 12.947 9.144 ;
     RECT  12.665 36.96 12.953 37.32 ;
     RECT  12.949 49.056 13.033 49.08 ;
     RECT  12.509 0.144 13.093 4.584 ;
     RECT  12.997 5.712 13.093 5.736 ;
     RECT  12.377 57.552 13.093 58.104 ;
     RECT  12.953 37.296 13.169 37.32 ;
     RECT  13.093 53.856 13.177 53.88 ;
     RECT  12.737 11.376 13.201 11.4 ;
     RECT  11.344 43.008 13.201 43.032 ;
     RECT  13.093 57.024 13.277 58.104 ;
     RECT  13.277 57.312 13.283 58.104 ;
     RECT  12.697 15.696 13.285 16.008 ;
     RECT  12.413 24.912 13.309 25.128 ;
     RECT  13.283 58.08 13.313 58.104 ;
     RECT  13.093 0.144 13.333 5.736 ;
     RECT  13.285 15.312 13.381 16.008 ;
     RECT  12.737 44.544 13.385 44.616 ;
     RECT  13.381 15.216 13.436 16.008 ;
     RECT  12.917 40.992 13.445 41.448 ;
     RECT  13.436 15.072 13.523 16.008 ;
     RECT  13.309 24.912 13.523 25.656 ;
     RECT  13.385 44.544 13.523 44.568 ;
     RECT  13.445 40.56 13.529 41.448 ;
     RECT  13.453 22.224 13.537 22.248 ;
     RECT  13.477 47.232 13.564 47.256 ;
     RECT  13.093 68.736 13.589 68.76 ;
     RECT  13.333 0.144 13.601 5.784 ;
     RECT  13.045 18.24 13.609 18.792 ;
     RECT  13.561 21.12 13.645 21.144 ;
     RECT  13.589 68.736 13.673 68.952 ;
     RECT  13.201 43.008 13.697 43.128 ;
     RECT  13.523 15.456 13.741 16.008 ;
     RECT  13.285 13.008 13.777 13.032 ;
     RECT  13.697 43.008 13.781 43.944 ;
     RECT  13.717 26.88 13.804 26.904 ;
     RECT  13.717 60.912 13.804 60.936 ;
     RECT  13.609 18.672 13.813 18.792 ;
     RECT  13.669 65.088 13.817 65.112 ;
     RECT  13.669 35.664 13.849 35.688 ;
     RECT  13.601 5.376 13.909 5.784 ;
     RECT  13.669 47.76 13.916 47.784 ;
     RECT  13.813 22.416 13.955 22.44 ;
     RECT  13.669 63.024 13.964 63.048 ;
     RECT  13.916 47.76 14.003 47.832 ;
     RECT  12.947 7.68 14.033 9.144 ;
     RECT  13.849 35.328 14.065 35.688 ;
     RECT  11.977 70.944 14.065 73.368 ;
     RECT  13.523 24.912 14.093 24.936 ;
     RECT  13.813 18.672 14.137 18.84 ;
     RECT  13.781 43.008 14.14 43.752 ;
     RECT  14.003 47.76 14.141 47.784 ;
     RECT  13.964 63.024 14.141 63.144 ;
     RECT  14.065 35.136 14.149 35.688 ;
     RECT  14.093 24.528 14.197 24.936 ;
     RECT  13.741 15.456 14.243 16.056 ;
     RECT  14.197 24.288 14.243 24.936 ;
     RECT  13.529 41.088 14.243 41.448 ;
     RECT  13.777 13.008 14.245 13.08 ;
     RECT  12.769 31.968 14.245 31.992 ;
     RECT  14.149 35.136 14.245 36.312 ;
     RECT  13.673 68.736 14.245 68.76 ;
     RECT  14.033 7.68 14.249 8.568 ;
     RECT  14.204 38.64 14.291 38.664 ;
     RECT  13.201 11.376 14.317 11.448 ;
     RECT  14.245 13.008 14.317 13.128 ;
     RECT  14.245 39.792 14.329 39.816 ;
     RECT  14.249 7.68 14.381 8.472 ;
     RECT  14.243 24.288 14.381 24.888 ;
     RECT  14.245 34.8 14.387 36.312 ;
     RECT  14.245 37.632 14.387 37.656 ;
     RECT  14.317 11.376 14.393 13.128 ;
     RECT  13.34 45.648 14.393 45.672 ;
     RECT  14.245 62.16 14.393 62.184 ;
     RECT  14.245 66.192 14.393 66.216 ;
     RECT  14.245 31.968 14.425 32.952 ;
     RECT  14.381 23.952 14.465 24.888 ;
     RECT  13.813 29.664 14.497 29.688 ;
     RECT  14.425 31.968 14.509 33.672 ;
     RECT  13.772 10.224 14.533 10.248 ;
     RECT  14.509 31.968 14.573 33.336 ;
     RECT  14.485 53.52 14.573 53.544 ;
     RECT  14.497 29.664 14.609 30.168 ;
     RECT  14.533 10.224 14.641 10.296 ;
     RECT  14.245 67.872 14.681 68.76 ;
     RECT  14.641 10.032 14.713 10.296 ;
     RECT  14.065 70.512 14.713 73.368 ;
     RECT  14.245 60.864 14.717 60.888 ;
     RECT  13.957 50.784 14.749 50.808 ;
     RECT  14.065 52.128 14.749 52.152 ;
     RECT  14.393 11.376 14.771 12.264 ;
     RECT  14.713 27.84 14.818 27.864 ;
     RECT  14.381 7.44 14.819 8.472 ;
     RECT  14.609 30.144 14.819 30.168 ;
     RECT  14.573 33.024 14.819 33.336 ;
     RECT  14.137 18.672 14.821 19.224 ;
     RECT  14.818 27.792 14.821 27.864 ;
     RECT  14.573 31.968 14.821 31.992 ;
     RECT  14.243 41.424 14.821 41.448 ;
     RECT  14.749 50.784 14.821 52.152 ;
     RECT  14.245 57.696 14.821 57.72 ;
     RECT  14.713 10.032 14.867 10.344 ;
     RECT  14.821 50.544 14.869 52.152 ;
     RECT  14.245 54.864 14.893 55.464 ;
     RECT  14.317 64.416 14.893 64.44 ;
     RECT  14.869 50.544 14.897 52.296 ;
     RECT  14.465 24.864 14.908 24.888 ;
     RECT  14.897 50.544 14.908 50.76 ;
     RECT  14.387 35.136 14.917 36.312 ;
     RECT  14.771 11.376 14.929 11.448 ;
     RECT  14.876 17.04 14.963 17.064 ;
     RECT  14.821 27.408 14.965 27.864 ;
     RECT  14.893 54.72 14.965 55.464 ;
     RECT  14.681 68.064 14.965 68.76 ;
     RECT  14.821 45.504 14.969 45.528 ;
     RECT  14.897 52.032 14.969 52.296 ;
     RECT  14.893 64.416 14.977 65.064 ;
     RECT  14.965 26.784 15.005 27.864 ;
     RECT  14.917 63.216 15.005 63.24 ;
     RECT  14.908 50.736 15.011 50.76 ;
     RECT  14.969 52.272 15.011 52.296 ;
     RECT  15.005 26.784 15.049 26.808 ;
     RECT  14.821 18.624 15.068 19.224 ;
     RECT  14.867 10.032 15.077 10.248 ;
     RECT  14.965 54.048 15.109 55.464 ;
     RECT  15.068 18.624 15.155 19.464 ;
     RECT  13.909 5.376 15.157 6.312 ;
     RECT  14.819 7.44 15.157 7.944 ;
     RECT  15.109 54.048 15.196 55.704 ;
     RECT  14.857 66.72 15.212 66.744 ;
     RECT  15.196 54.048 15.221 55.32 ;
     RECT  15.221 55.296 15.229 55.32 ;
     RECT  15.157 5.376 15.251 7.944 ;
     RECT  14.713 70.128 15.251 73.368 ;
     RECT  14.821 57.6 15.253 57.72 ;
     RECT  15.212 66.72 15.253 66.792 ;
     RECT  14.917 35.136 15.257 37.032 ;
     RECT  15.251 5.376 15.281 7.128 ;
     RECT  14.965 68.064 15.289 69 ;
     RECT  14.821 41.424 15.349 41.64 ;
     RECT  14.14 43.008 15.349 43.128 ;
     RECT  15.281 5.136 15.365 7.128 ;
     RECT  15.257 35.136 15.365 36.264 ;
     RECT  15.073 22.032 15.395 22.056 ;
     RECT  15.349 41.424 15.397 43.128 ;
     RECT  15.155 18.624 15.401 19.32 ;
     RECT  15.253 66.72 15.401 66.888 ;
     RECT  15.397 41.424 15.436 44.04 ;
     RECT  15.401 18.624 15.493 18.792 ;
     RECT  15.401 66.72 15.605 66.792 ;
     RECT  15.109 21.024 15.613 21.048 ;
     RECT  15.253 57.6 15.685 58.152 ;
     RECT  15.469 40.416 15.829 40.44 ;
     RECT  14.929 47.04 15.857 47.064 ;
     RECT  15.829 40.272 15.925 40.44 ;
     RECT  15.685 57.6 15.973 58.68 ;
     RECT  14.977 64.416 15.973 64.44 ;
     RECT  15.289 68.064 15.973 69.048 ;
     RECT  15.589 12.912 16.009 13.8 ;
     RECT  15.613 20.544 16.009 21.048 ;
     RECT  15.925 40.176 16.009 40.44 ;
     RECT  15.181 9.552 16.117 9.576 ;
     RECT  14.929 11.232 16.117 11.448 ;
     RECT  16.009 39.984 16.172 40.44 ;
     RECT  15.865 50.784 16.213 50.808 ;
     RECT  16.117 9.504 16.22 9.576 ;
     RECT  13.601 0.144 16.225 4.008 ;
     RECT  16.22 9.504 16.225 9.672 ;
     RECT  16.009 12.48 16.309 13.8 ;
     RECT  16.172 39.744 16.369 40.44 ;
     RECT  16.225 0.096 16.448 4.008 ;
     RECT  15.365 5.712 16.448 7.128 ;
     RECT  16.225 8.736 16.448 9.672 ;
     RECT  16.117 10.896 16.448 11.448 ;
     RECT  16.309 12.48 16.448 14.136 ;
     RECT  14.243 15.456 16.448 15.48 ;
     RECT  15.493 18.576 16.448 18.792 ;
     RECT  16.009 20.544 16.448 21.672 ;
     RECT  16.181 26.208 16.448 26.232 ;
     RECT  15.733 27.936 16.448 27.96 ;
     RECT  16.213 29.232 16.448 29.256 ;
     RECT  14.821 30.816 16.448 31.992 ;
     RECT  15.365 35.136 16.448 35.4 ;
     RECT  16.369 39.312 16.448 40.44 ;
     RECT  15.436 41.424 16.448 41.688 ;
     RECT  15.436 42.672 16.448 44.04 ;
     RECT  15.973 45.552 16.448 45.576 ;
     RECT  15.857 46.704 16.448 47.064 ;
     RECT  16.213 48.96 16.448 48.984 ;
     RECT  16.213 50.544 16.448 50.808 ;
     RECT  15.397 52.368 16.448 52.392 ;
     RECT  15.221 54.048 16.448 54.072 ;
     RECT  15.973 57.552 16.448 58.68 ;
     RECT  15.965 62.4 16.448 62.424 ;
     RECT  15.973 63.984 16.448 64.44 ;
     RECT  15.605 66.192 16.448 66.792 ;
     RECT  15.973 68.064 16.448 69.192 ;
     RECT  15.251 70.512 16.448 73.368 ;
     RECT  16.448 0.096 16.744 73.368 ;
     RECT  16.744 48.096 16.883 48.984 ;
     RECT  16.744 50.112 16.913 51.048 ;
     RECT  16.744 25.44 16.921 26.808 ;
     RECT  16.744 44.592 16.921 44.616 ;
     RECT  16.744 45.696 16.921 46.92 ;
     RECT  16.744 15.072 16.931 18.264 ;
     RECT  16.744 56.064 16.931 57.192 ;
     RECT  16.744 60 16.931 60.456 ;
     RECT  16.744 66.912 16.931 66.936 ;
     RECT  16.744 37.584 16.979 39.864 ;
     RECT  16.921 46.896 16.985 46.92 ;
     RECT  16.744 53.856 16.985 54.792 ;
     RECT  16.744 22.704 17.021 23.16 ;
     RECT  16.985 54.48 17.021 54.792 ;
     RECT  16.883 48.096 17.027 48.264 ;
     RECT  16.744 41.424 17.075 43.128 ;
     RECT  16.979 37.584 17.129 38.424 ;
     RECT  16.931 60 17.129 60.024 ;
     RECT  16.979 39.84 17.165 39.864 ;
     RECT  16.913 50.112 17.345 50.808 ;
     RECT  17.129 38.16 17.356 38.424 ;
     RECT  16.744 63.888 17.363 65.592 ;
     RECT  16.744 35.136 17.381 36.456 ;
     RECT  16.931 56.784 17.381 57.144 ;
     RECT  17.381 57.024 17.411 57.144 ;
     RECT  17.027 48.096 17.417 48.12 ;
     RECT  17.411 57.024 17.459 57.048 ;
     RECT  17.021 22.752 17.507 23.16 ;
     RECT  16.744 62.352 17.555 62.376 ;
     RECT  17.021 54.48 17.561 54.696 ;
     RECT  16.744 7.104 17.597 11.448 ;
     RECT  16.744 20.544 17.597 20.568 ;
     RECT  17.363 64.944 17.597 65.592 ;
     RECT  17.381 35.136 17.603 36.408 ;
     RECT  16.744 29.568 17.644 29.592 ;
     RECT  17.597 7.872 17.651 11.448 ;
     RECT  16.931 16.512 17.651 18.264 ;
     RECT  17.507 22.752 17.651 22.776 ;
     RECT  17.603 35.136 17.651 36.312 ;
     RECT  17.651 16.512 17.705 16.584 ;
     RECT  17.651 36.288 17.705 36.312 ;
     RECT  17.356 38.4 17.705 38.424 ;
     RECT  17.363 63.888 17.737 63.912 ;
     RECT  16.921 25.44 17.738 26.28 ;
     RECT  17.651 7.968 17.747 11.448 ;
     RECT  17.747 9.6 17.843 11.448 ;
     RECT  17.737 63.84 17.843 63.912 ;
     RECT  17.843 11.232 17.845 11.448 ;
     RECT  16.744 12.912 17.845 13.992 ;
     RECT  17.845 11.232 17.881 13.992 ;
     RECT  16.931 15.072 17.881 15.48 ;
     RECT  17.804 23.808 17.891 23.832 ;
     RECT  16.744 31.392 17.909 32.52 ;
     RECT  16.744 58.608 17.921 58.728 ;
     RECT  17.749 49.92 17.957 49.944 ;
     RECT  17.893 46.224 17.98 46.248 ;
     RECT  17.881 11.232 17.993 15.48 ;
     RECT  17.909 30.72 17.993 32.52 ;
     RECT  17.075 41.424 17.996 42.168 ;
     RECT  17.993 11.232 18.035 13.608 ;
     RECT  17.705 16.56 18.109 16.584 ;
     RECT  17.597 65.568 18.131 65.592 ;
     RECT  17.996 40.512 18.133 42.168 ;
     RECT  17.843 63.888 18.137 63.912 ;
     RECT  18.035 11.232 18.227 11.688 ;
     RECT  18.14 23.952 18.227 23.976 ;
     RECT  18.133 5.04 18.229 5.064 ;
     RECT  18.169 6.096 18.229 6.12 ;
     RECT  17.561 54.48 18.229 54.6 ;
     RECT  16.744 70.128 18.241 73.368 ;
     RECT  18.161 22.368 18.245 22.392 ;
     RECT  17.797 21.12 18.277 21.144 ;
     RECT  18.277 51.84 18.361 51.864 ;
     RECT  18.241 69.552 18.371 73.368 ;
     RECT  18.229 5.04 18.373 6.12 ;
     RECT  17.738 25.44 18.385 26.232 ;
     RECT  18.229 54.336 18.389 54.6 ;
     RECT  18.277 21.12 18.412 22.2 ;
     RECT  17.651 17.616 18.421 18.264 ;
     RECT  18.229 29.088 18.485 29.112 ;
     RECT  18.421 17.616 18.505 18.84 ;
     RECT  18.421 62.16 18.515 62.184 ;
     RECT  18.485 28.512 18.569 29.112 ;
     RECT  18.569 29.088 18.605 29.112 ;
     RECT  18.229 58.224 18.605 58.248 ;
     RECT  18.371 69.6 18.707 73.368 ;
     RECT  18.661 44.784 18.748 44.808 ;
     RECT  18.505 17.616 18.803 18.216 ;
     RECT  18.385 24.912 18.803 26.232 ;
     RECT  18.805 39.36 18.825 39.384 ;
     RECT  18.133 40.512 18.825 42.36 ;
     RECT  18.825 39.36 18.853 42.36 ;
     RECT  18.412 21.12 18.892 21.672 ;
     RECT  18.805 48.672 18.892 48.696 ;
     RECT  18.805 62.736 18.893 62.76 ;
     RECT  18.805 64.128 18.893 64.584 ;
     RECT  17.993 14.928 18.917 15.48 ;
     RECT  18.817 54.672 18.929 54.696 ;
     RECT  18.892 21.12 18.937 21.144 ;
     RECT  18.853 53.088 18.937 53.112 ;
     RECT  18.86 50.448 18.947 50.472 ;
     RECT  16.744 0.096 18.949 4.008 ;
     RECT  18.373 5.04 18.949 6.312 ;
     RECT  18.889 45.312 18.973 45.672 ;
     RECT  18.803 24.912 18.995 26.184 ;
     RECT  18.917 14.928 18.997 16.008 ;
     RECT  18.997 14.832 19.001 16.008 ;
     RECT  18.805 61.584 19.001 61.704 ;
     RECT  17.993 31.44 19.045 32.52 ;
     RECT  18.035 12.768 19.069 13.608 ;
     RECT  19.061 19.392 19.145 19.416 ;
     RECT  18.949 0.096 19.187 6.312 ;
     RECT  18.565 37.584 19.235 37.608 ;
     RECT  18.853 39.36 19.235 42.936 ;
     RECT  18.817 66.72 19.235 66.744 ;
     RECT  17.843 9.6 19.285 10.104 ;
     RECT  18.227 11.232 19.285 11.4 ;
     RECT  17.747 7.968 19.313 8.184 ;
     RECT  19.235 40.224 19.361 42.936 ;
     RECT  18.893 64.128 19.361 64.152 ;
     RECT  19.285 23.376 19.369 23.4 ;
     RECT  19.285 33.072 19.369 33.096 ;
     RECT  19.069 12.72 19.379 13.608 ;
     RECT  19.313 7.968 19.381 8.52 ;
     RECT  19.285 9.6 19.381 11.4 ;
     RECT  19.381 7.968 19.393 11.4 ;
     RECT  19.381 58.512 19.393 58.536 ;
     RECT  19.381 22.176 19.429 22.2 ;
     RECT  19.393 7.968 19.433 11.448 ;
     RECT  19.361 40.224 19.433 42.792 ;
     RECT  19.187 4.56 19.469 6.312 ;
     RECT  19.381 54.288 19.469 54.312 ;
     RECT  19.393 58.512 19.469 58.68 ;
     RECT  18.421 27.216 19.475 27.24 ;
     RECT  19.045 31.44 19.532 31.56 ;
     RECT  19.381 47.952 19.541 48.504 ;
     RECT  19.477 33.12 19.573 33.96 ;
     RECT  17.651 35.136 19.573 35.16 ;
     RECT  18.995 24.912 19.585 25.704 ;
     RECT  19.381 50.544 19.585 50.712 ;
     RECT  18.803 18.048 19.649 18.216 ;
     RECT  19.379 13.104 19.681 13.608 ;
     RECT  19.681 13.104 19.693 13.848 ;
     RECT  19.433 8.736 19.715 11.448 ;
     RECT  19.715 8.736 19.757 9.096 ;
     RECT  19.573 33.12 19.757 35.16 ;
     RECT  18.973 45.312 19.811 45.576 ;
     RECT  19.757 33.12 19.837 33.24 ;
     RECT  19.433 41.424 19.859 42.792 ;
     RECT  19.381 60.816 19.865 60.84 ;
     RECT  19.541 48.48 19.909 48.504 ;
     RECT  19.381 20.016 19.933 20.04 ;
     RECT  19.757 34.752 19.933 35.16 ;
     RECT  19.187 0.096 19.937 3.24 ;
     RECT  19.429 22.176 19.937 22.536 ;
     RECT  19.693 13.584 19.955 13.848 ;
     RECT  19.933 34.752 19.955 36.072 ;
     RECT  19.469 58.656 19.957 58.68 ;
     RECT  19.532 30.864 19.969 31.56 ;
     RECT  19.757 8.976 19.981 9.096 ;
     RECT  19.897 16.512 19.981 16.536 ;
     RECT  19.001 14.832 20.005 15.48 ;
     RECT  19.925 48.624 20.009 48.648 ;
     RECT  19.837 33.216 20.017 33.24 ;
     RECT  19.969 30.816 20.041 31.56 ;
     RECT  19.957 58.656 20.045 59.304 ;
     RECT  19.859 41.712 20.125 42.792 ;
     RECT  19.957 38.64 20.153 38.664 ;
     RECT  19.957 23.76 20.177 23.784 ;
     RECT  20.108 48.672 20.195 48.696 ;
     RECT  19.433 40.224 20.225 40.248 ;
     RECT  20.177 23.76 20.261 23.88 ;
     RECT  19.957 57.456 20.261 57.48 ;
     RECT  19.937 0.24 20.291 3.24 ;
     RECT  19.937 22.176 20.293 22.2 ;
     RECT  20.261 23.76 20.333 23.784 ;
     RECT  20.329 3.36 20.341 3.384 ;
     RECT  19.715 10.08 20.341 11.448 ;
     RECT  20.293 21.648 20.377 22.2 ;
     RECT  19.469 5.472 20.389 6.312 ;
     RECT  19.981 8.976 20.435 9 ;
     RECT  20.341 10.08 20.437 12.12 ;
     RECT  19.955 35.136 20.531 36.072 ;
     RECT  20.125 42.144 20.533 42.792 ;
     RECT  20.341 3.36 20.549 3.432 ;
     RECT  20.389 5.472 20.581 6.36 ;
     RECT  19.573 7.344 20.581 7.464 ;
     RECT  20.045 58.656 20.645 58.728 ;
     RECT  19.933 20.016 20.689 20.52 ;
     RECT  20.101 18.816 20.693 18.84 ;
     RECT  20.533 42.144 20.693 43.56 ;
     RECT  20.693 42.144 20.723 43.272 ;
     RECT  20.041 30.816 20.729 31.752 ;
     RECT  20.533 45.264 20.729 45.288 ;
     RECT  20.581 54.72 20.729 54.744 ;
     RECT  20.141 51.36 20.732 51.384 ;
     RECT  20.689 19.968 20.773 20.52 ;
     RECT  20.732 51.168 20.773 51.384 ;
     RECT  20.533 61.584 20.867 62.184 ;
     RECT  18.707 70.128 20.869 73.368 ;
     RECT  20.531 35.136 20.933 35.16 ;
     RECT  20.867 61.632 20.941 62.184 ;
     RECT  19.585 24.912 21.013 25.128 ;
     RECT  20.869 26.448 21.013 26.472 ;
     RECT  20.773 51.168 21.013 51.912 ;
     RECT  20.291 0.24 21.049 2.376 ;
     RECT  21.013 51.168 21.077 52.056 ;
     RECT  20.645 58.224 21.109 58.728 ;
     RECT  20.723 42.144 21.121 42.744 ;
     RECT  19.429 68.976 21.121 69 ;
     RECT  20.869 70.08 21.121 73.368 ;
     RECT  20.533 36.24 21.301 36.792 ;
     RECT  20.905 66.672 21.301 66.696 ;
     RECT  21.253 17.424 21.308 17.448 ;
     RECT  21.121 42.096 21.337 42.744 ;
     RECT  20.005 14.832 21.409 16.056 ;
     RECT  21.308 17.04 21.409 17.448 ;
     RECT  21.301 66.192 21.409 66.696 ;
     RECT  20.965 32.832 21.509 32.856 ;
     RECT  20.437 10.08 21.589 12.264 ;
     RECT  19.955 13.584 21.589 13.608 ;
     RECT  21.013 24.912 21.589 26.472 ;
     RECT  21.337 41.712 21.617 42.744 ;
     RECT  21.049 0.096 21.625 2.376 ;
     RECT  20.549 3.36 21.625 3.384 ;
     RECT  21.625 0.096 21.637 3.384 ;
     RECT  21.077 40.32 21.637 40.344 ;
     RECT  21.617 41.616 21.637 42.744 ;
     RECT  20.941 61.632 21.661 62.28 ;
     RECT  21.301 36.24 21.685 37.32 ;
     RECT  21.637 40.32 21.692 42.744 ;
     RECT  20.729 30.816 21.725 31.56 ;
     RECT  21.509 32.832 21.725 33.672 ;
     RECT  21.077 51.168 21.725 52.152 ;
     RECT  21.637 0.096 21.733 4.152 ;
     RECT  20.581 5.472 21.733 7.464 ;
     RECT  21.409 14.832 21.733 17.448 ;
     RECT  20.933 34.8 21.733 35.16 ;
     RECT  21.692 40.32 21.733 43.272 ;
     RECT  21.733 0.096 21.848 7.464 ;
     RECT  21.589 10.08 21.848 12.312 ;
     RECT  21.589 13.584 21.848 13.656 ;
     RECT  21.733 14.832 21.848 17.688 ;
     RECT  20.773 20.496 21.848 20.52 ;
     RECT  20.377 22.176 21.848 22.2 ;
     RECT  21.653 23.76 21.848 23.784 ;
     RECT  21.589 24.912 21.848 26.952 ;
     RECT  21.637 28.704 21.848 28.728 ;
     RECT  21.077 29.712 21.848 29.736 ;
     RECT  21.725 30.816 21.848 33.672 ;
     RECT  21.733 34.704 21.848 35.16 ;
     RECT  21.685 36.24 21.848 37.464 ;
     RECT  21.637 39.216 21.848 39.24 ;
     RECT  21.733 40.32 21.848 44.088 ;
     RECT  21.26 47.232 21.848 47.256 ;
     RECT  21.548 49.152 21.848 49.176 ;
     RECT  21.725 50.832 21.848 52.152 ;
     RECT  20.905 54.192 21.848 54.216 ;
     RECT  21.109 58.224 21.848 59.544 ;
     RECT  21.661 61.632 21.848 62.904 ;
     RECT  21.061 64.992 21.848 65.016 ;
     RECT  21.409 66.192 21.848 66.792 ;
     RECT  21.121 68.976 21.848 73.368 ;
     RECT  21.848 0.096 22.144 73.368 ;
     RECT  22.144 42.768 22.241 44.088 ;
     RECT  22.144 20.592 22.259 21.144 ;
     RECT  22.241 42.768 22.259 43.896 ;
     RECT  22.144 62.16 22.259 63.24 ;
     RECT  22.144 25.632 22.285 25.656 ;
     RECT  22.144 14.832 22.3 16.056 ;
     RECT  22.144 4.656 22.307 7.896 ;
     RECT  22.144 26.976 22.307 31.944 ;
     RECT  22.144 41.136 22.313 41.352 ;
     RECT  22.259 42.768 22.313 43.368 ;
     RECT  22.144 45.648 22.421 45.672 ;
     RECT  22.144 50.736 22.421 51.144 ;
     RECT  22.307 28.992 22.429 31.944 ;
     RECT  22.144 39.168 22.457 39.192 ;
     RECT  22.144 67.824 22.493 73.368 ;
     RECT  22.144 34.224 22.565 35.16 ;
     RECT  22.144 49.104 22.565 49.176 ;
     RECT  22.144 58.128 22.565 59.448 ;
     RECT  22.144 36.672 22.595 37.896 ;
     RECT  22.144 23.712 22.601 24.648 ;
     RECT  22.144 66.192 22.643 66.792 ;
     RECT  22.144 55.392 22.673 55.416 ;
     RECT  22.429 30.192 22.691 31.944 ;
     RECT  22.144 9.12 22.717 10.104 ;
     RECT  22.307 6 22.739 7.896 ;
     RECT  22.144 11.28 22.787 13.656 ;
     RECT  22.601 23.712 22.789 24.456 ;
     RECT  22.691 30.24 22.817 31.944 ;
     RECT  22.565 59.424 22.817 59.448 ;
     RECT  22.787 13.536 22.853 13.656 ;
     RECT  22.853 13.536 22.883 13.608 ;
     RECT  22.144 52.992 22.889 53.784 ;
     RECT  22.643 66.192 22.889 66.216 ;
     RECT  22.421 50.832 22.925 51.144 ;
     RECT  22.717 9.408 22.931 10.104 ;
     RECT  22.565 34.224 22.933 34.248 ;
     RECT  22.817 31.92 22.979 31.944 ;
     RECT  22.493 67.824 22.979 73.32 ;
     RECT  22.259 21.12 22.997 21.144 ;
     RECT  22.595 37.056 22.997 37.896 ;
     RECT  22.931 9.552 23.027 10.104 ;
     RECT  22.259 63.216 23.075 63.24 ;
     RECT  22.997 37.056 23.077 37.608 ;
     RECT  22.3 16.032 23.132 16.056 ;
     RECT  22.144 17.088 23.132 17.64 ;
     RECT  22.307 26.976 23.132 27.96 ;
     RECT  22.429 28.992 23.171 29.016 ;
     RECT  23.132 26.88 23.177 27.96 ;
     RECT  23.177 26.88 23.219 27.864 ;
     RECT  22.817 30.24 23.219 30.84 ;
     RECT  23.173 47.28 23.26 47.304 ;
     RECT  22.313 41.328 23.315 41.352 ;
     RECT  22.889 52.992 23.357 53.64 ;
     RECT  23.132 16.032 23.365 17.64 ;
     RECT  22.259 62.16 23.365 62.184 ;
     RECT  22.144 22.224 23.372 22.248 ;
     RECT  22.565 49.152 23.393 49.176 ;
     RECT  23.357 52.992 23.411 53.592 ;
     RECT  23.365 62.016 23.413 62.184 ;
     RECT  23.413 62.016 23.452 62.856 ;
     RECT  23.219 27.84 23.459 27.864 ;
     RECT  22.565 58.128 23.461 58.152 ;
     RECT  23.365 17.088 23.497 17.64 ;
     RECT  23.027 9.744 23.5 10.104 ;
     RECT  23.411 53.568 23.501 53.592 ;
     RECT  23.372 22.224 23.537 22.776 ;
     RECT  23.365 64.56 23.573 64.584 ;
     RECT  22.144 0.096 23.605 3.624 ;
     RECT  22.307 4.656 23.605 4.68 ;
     RECT  23.557 35.568 23.644 35.592 ;
     RECT  22.3 14.832 23.651 14.856 ;
     RECT  23.564 15.888 23.651 15.912 ;
     RECT  23.365 39.36 23.68 39.384 ;
     RECT  23.219 30.816 23.681 30.84 ;
     RECT  23.68 39.36 23.681 39.432 ;
     RECT  22.925 50.832 23.701 50.856 ;
     RECT  23.452 62.832 23.717 62.856 ;
     RECT  22.739 6 23.747 7.416 ;
     RECT  23.669 56.496 23.753 56.52 ;
     RECT  23.497 17.088 23.756 18.264 ;
     RECT  23.747 7.248 23.785 7.416 ;
     RECT  22.979 68.4 23.795 73.32 ;
     RECT  23.795 68.976 23.825 73.32 ;
     RECT  23.653 32.928 23.845 32.952 ;
     RECT  22.313 43.344 23.869 43.368 ;
     RECT  23.461 57.84 23.893 58.152 ;
     RECT  23.605 0.096 23.897 4.68 ;
     RECT  23.681 39.408 23.897 39.432 ;
     RECT  23.813 52.512 23.897 52.536 ;
     RECT  23.5 10.08 23.929 10.104 ;
     RECT  23.893 57.552 23.929 58.152 ;
     RECT  23.893 59.856 23.929 59.88 ;
     RECT  23.713 25.824 23.941 25.848 ;
     RECT  23.701 50.784 23.969 50.856 ;
     RECT  23.929 57.552 23.977 59.88 ;
     RECT  23.785 7.248 23.987 7.992 ;
     RECT  23.756 17.088 24.001 18.456 ;
     RECT  23.929 49.584 24.013 49.608 ;
     RECT  23.977 57.552 24.013 58.92 ;
     RECT  22.789 23.952 24.037 24.456 ;
     RECT  23.996 50.592 24.083 50.616 ;
     RECT  23.987 7.44 24.085 7.992 ;
     RECT  24.001 42.144 24.085 42.168 ;
     RECT  23.825 69.072 24.145 73.32 ;
     RECT  24.037 22.8 24.181 24.552 ;
     RECT  23.941 25.824 24.181 26.232 ;
     RECT  23.941 47.184 24.185 47.208 ;
     RECT  23.929 10.08 24.217 10.296 ;
     RECT  22.787 11.28 24.217 12.552 ;
     RECT  24.181 22.8 24.217 26.232 ;
     RECT  24.013 57.552 24.221 58.68 ;
     RECT  24.085 7.44 24.227 7.464 ;
     RECT  24.217 22.8 24.265 26.76 ;
     RECT  24.001 17.088 24.275 18.792 ;
     RECT  24.265 22.8 24.275 24.552 ;
     RECT  24.209 8.544 24.293 8.568 ;
     RECT  24.133 31.92 24.293 31.944 ;
     RECT  24.275 17.472 24.323 18.792 ;
     RECT  24.217 10.08 24.371 12.552 ;
     RECT  23.845 32.928 24.397 33.096 ;
     RECT  22.883 13.536 24.433 13.56 ;
     RECT  24.361 56.016 24.445 56.04 ;
     RECT  24.361 61.584 24.445 61.608 ;
     RECT  24.38 40.224 24.467 40.248 ;
     RECT  24.397 32.496 24.481 33.096 ;
     RECT  24.371 10.8 24.515 12.552 ;
     RECT  24.433 13.536 24.517 13.656 ;
     RECT  24.275 22.8 24.517 23.64 ;
     RECT  24.505 35.472 24.589 35.496 ;
     RECT  24.533 19.968 24.617 19.992 ;
     RECT  24.517 59.952 24.617 59.976 ;
     RECT  24.541 33.12 24.625 33.864 ;
     RECT  24.625 33.12 24.653 33.144 ;
     RECT  24.649 21.072 24.677 21.096 ;
     RECT  23.897 0.096 24.707 4.536 ;
     RECT  24.323 18.24 24.716 18.792 ;
     RECT  24.677 20.544 24.761 21.096 ;
     RECT  24.001 64.848 24.761 65.064 ;
     RECT  24.716 18.24 24.803 18.936 ;
     RECT  24.515 11.28 24.833 12.552 ;
     RECT  24.145 69.072 24.869 73.368 ;
     RECT  24.803 18.24 24.877 18.84 ;
     RECT  24.221 57.552 24.877 57.672 ;
     RECT  24.829 34.8 24.913 35.352 ;
     RECT  23.921 43.92 24.941 44.04 ;
     RECT  24.761 64.848 24.941 64.872 ;
     RECT  24.913 35.328 24.985 35.352 ;
     RECT  24.901 46.224 24.985 46.248 ;
     RECT  24.929 56.448 25.013 56.472 ;
     RECT  24.901 68.976 25.013 69 ;
     RECT  24.965 44.448 25.049 44.472 ;
     RECT  24.707 3.984 25.091 4.536 ;
     RECT  24.757 14.64 25.091 14.664 ;
     RECT  24.901 63.312 25.091 63.336 ;
     RECT  24.877 57.552 25.093 57.576 ;
     RECT  25.081 9.648 25.187 9.672 ;
     RECT  25.093 56.688 25.187 57.576 ;
     RECT  25.093 62.16 25.189 62.184 ;
     RECT  25.093 49.968 25.225 49.992 ;
     RECT  25.225 63.792 25.285 63.816 ;
     RECT  25.225 49.968 25.297 50.76 ;
     RECT  25.297 49.728 25.337 50.76 ;
     RECT  25.189 62.16 25.337 62.664 ;
     RECT  24.517 22.752 25.34 23.64 ;
     RECT  25.285 8.352 25.373 8.376 ;
     RECT  25.093 40.272 25.373 40.296 ;
     RECT  25.285 63.792 25.373 64.392 ;
     RECT  25.337 62.592 25.379 62.664 ;
     RECT  25.337 49.728 25.481 49.992 ;
     RECT  24.265 25.824 25.505 26.76 ;
     RECT  25.34 22.128 25.513 23.64 ;
     RECT  23.077 37.584 25.541 37.608 ;
     RECT  25.477 38.592 25.541 38.616 ;
     RECT  24.877 18.24 25.549 18.264 ;
     RECT  25.505 25.824 25.589 27.384 ;
     RECT  25.187 57.024 25.589 57.576 ;
     RECT  24.517 13.536 25.621 13.56 ;
     RECT  25.405 48.432 25.621 48.456 ;
     RECT  25.481 49.728 25.621 49.944 ;
     RECT  25.621 48.432 25.667 49.944 ;
     RECT  25.373 63.792 25.667 63.816 ;
     RECT  24.761 21.072 25.685 21.096 ;
     RECT  25.513 22.128 25.685 23.928 ;
     RECT  25.621 13.536 25.705 13.656 ;
     RECT  25.621 39.984 25.705 40.008 ;
     RECT  25.685 21.072 25.729 23.928 ;
     RECT  25.549 17.664 25.733 18.264 ;
     RECT  25.657 43.008 25.741 43.032 ;
     RECT  25.669 61.344 25.769 61.368 ;
     RECT  24.833 11.28 25.813 12.312 ;
     RECT  24.869 70.128 25.837 73.368 ;
     RECT  25.813 10.848 25.861 12.312 ;
     RECT  25.669 29.232 25.868 29.256 ;
     RECT  25.861 10.848 25.873 12.552 ;
     RECT  25.705 13.536 25.873 13.56 ;
     RECT  25.873 10.848 25.907 13.56 ;
     RECT  24.707 0.096 25.909 2.808 ;
     RECT  25.091 3.984 25.909 4.296 ;
     RECT  25.589 57.504 25.909 57.576 ;
     RECT  25.729 20.88 25.913 23.928 ;
     RECT  25.837 69.552 25.921 73.368 ;
     RECT  25.868 28.848 25.955 29.256 ;
     RECT  25.589 25.824 25.957 26.808 ;
     RECT  25.909 0.096 26.051 4.296 ;
     RECT  25.973 29.664 26.057 29.688 ;
     RECT  26.012 16.608 26.099 16.632 ;
     RECT  25.913 22.8 26.101 23.928 ;
     RECT  25.909 57.504 26.129 57.672 ;
     RECT  26.101 22.8 26.147 24.072 ;
     RECT  25.669 45.216 26.165 45.24 ;
     RECT  26.147 23.328 26.188 24.072 ;
     RECT  25.541 37.584 26.197 38.616 ;
     RECT  25.669 51.312 26.237 51.336 ;
     RECT  26.161 33.888 26.245 33.912 ;
     RECT  26.089 54.672 26.284 54.696 ;
     RECT  26.197 37.584 26.305 38.808 ;
     RECT  25.379 62.592 26.341 62.616 ;
     RECT  23.747 6 26.389 6.024 ;
     RECT  26.197 45.696 26.396 45.72 ;
     RECT  26.389 5.616 26.533 6.024 ;
     RECT  25.907 10.848 26.593 13.32 ;
     RECT  25.733 17.664 26.593 17.736 ;
     RECT  26.305 37.584 26.629 39.768 ;
     RECT  25.957 25.68 26.665 26.808 ;
     RECT  25.667 49.2 26.665 49.944 ;
     RECT  26.233 30.864 26.701 30.888 ;
     RECT  25.909 19.392 26.773 19.416 ;
     RECT  25.913 20.88 26.773 21.672 ;
     RECT  26.629 37.056 26.773 39.768 ;
     RECT  26.129 57.552 26.773 57.672 ;
     RECT  26.341 62.592 26.773 62.856 ;
     RECT  26.773 52.704 26.809 52.728 ;
     RECT  26.293 43.296 26.837 43.32 ;
     RECT  26.593 10.224 26.917 13.32 ;
     RECT  26.437 15.024 26.917 15.048 ;
     RECT  26.593 17.616 26.917 17.736 ;
     RECT  26.773 19.392 26.917 21.672 ;
     RECT  26.917 17.616 26.981 21.672 ;
     RECT  26.701 30.288 27.061 30.888 ;
     RECT  26.485 8.016 27.109 8.04 ;
     RECT  26.051 0.096 27.248 4.008 ;
     RECT  26.533 5.616 27.248 6.312 ;
     RECT  27.109 7.776 27.248 8.04 ;
     RECT  26.917 10.224 27.248 16.008 ;
     RECT  26.981 17.088 27.248 21.672 ;
     RECT  26.188 23.328 27.248 23.976 ;
     RECT  26.665 25.104 27.248 26.808 ;
     RECT  26.821 28.512 27.248 28.536 ;
     RECT  27.061 30.24 27.248 30.888 ;
     RECT  26.773 32.4 27.248 32.424 ;
     RECT  26.917 34.752 27.248 34.776 ;
     RECT  26.773 37.056 27.248 40.008 ;
     RECT  26.837 43.296 27.248 43.368 ;
     RECT  26.396 45.696 27.248 45.912 ;
     RECT  26.693 47.088 27.248 47.112 ;
     RECT  26.665 49.2 27.248 49.992 ;
     RECT  26.809 52.704 27.248 53.544 ;
     RECT  26.773 57.552 27.248 57.864 ;
     RECT  27.089 59.952 27.248 59.976 ;
     RECT  26.773 62.352 27.248 62.856 ;
     RECT  26.341 65.568 27.248 65.592 ;
     RECT  26.828 68.784 27.248 68.808 ;
     RECT  25.921 69.792 27.248 73.368 ;
     RECT  27.248 0.096 27.544 73.368 ;
     RECT  27.544 20.592 27.605 21.144 ;
     RECT  27.544 18.144 27.683 18.504 ;
     RECT  27.544 36.48 27.683 36.792 ;
     RECT  27.544 38.256 27.683 38.52 ;
     RECT  27.544 39.504 27.683 39.768 ;
     RECT  27.544 63.888 27.683 64.2 ;
     RECT  27.544 46.8 27.721 47.112 ;
     RECT  27.544 57.024 27.721 57.048 ;
     RECT  27.683 36.48 27.785 36.648 ;
     RECT  27.544 52.128 27.785 53.112 ;
     RECT  27.785 52.128 27.821 52.44 ;
     RECT  27.544 34.176 27.827 34.92 ;
     RECT  27.544 50.736 27.827 50.76 ;
     RECT  27.821 52.272 27.827 52.296 ;
     RECT  27.544 60 27.827 60.264 ;
     RECT  27.544 48.24 27.875 49.032 ;
     RECT  27.785 36.48 27.901 36.504 ;
     RECT  27.544 14.832 27.929 16.632 ;
     RECT  27.683 18.192 27.971 18.504 ;
     RECT  27.827 34.896 28.001 34.92 ;
     RECT  27.544 44.352 28.067 44.664 ;
     RECT  27.544 62.16 28.109 62.808 ;
     RECT  27.544 0.096 28.115 4.536 ;
     RECT  27.544 5.904 28.115 9.576 ;
     RECT  27.544 69.072 28.217 73.368 ;
     RECT  27.544 32.448 28.253 32.472 ;
     RECT  27.544 66.72 28.259 66.936 ;
     RECT  27.605 21.12 28.289 21.144 ;
     RECT  27.544 25.488 28.289 27.048 ;
     RECT  28.259 66.912 28.297 66.936 ;
     RECT  28.115 6.672 28.307 9.576 ;
     RECT  27.929 14.832 28.307 15.528 ;
     RECT  27.544 29.568 28.369 29.688 ;
     RECT  27.683 63.888 28.369 63.912 ;
     RECT  27.544 23.04 28.397 23.976 ;
     RECT  27.544 54.72 28.403 55.752 ;
     RECT  28.109 62.16 28.433 62.184 ;
     RECT  27.929 16.512 28.441 16.632 ;
     RECT  28.441 16.512 28.451 16.536 ;
     RECT  28.369 29.568 28.469 29.592 ;
     RECT  28.307 6.864 28.499 9.576 ;
     RECT  27.971 18.192 28.499 18.216 ;
     RECT  28.289 25.488 28.499 25.848 ;
     RECT  27.683 39.504 28.499 39.528 ;
     RECT  28.307 14.832 28.505 15.048 ;
     RECT  27.683 38.256 28.505 38.28 ;
     RECT  28.067 44.352 28.505 44.616 ;
     RECT  27.875 48.912 28.505 49.032 ;
     RECT  27.544 11.184 28.513 13.704 ;
     RECT  28.289 27.024 28.537 27.048 ;
     RECT  27.544 28.128 28.537 28.536 ;
     RECT  28.537 27.024 28.547 28.536 ;
     RECT  28.115 0.096 28.585 4.008 ;
     RECT  28.513 12.288 28.595 13.704 ;
     RECT  27.544 58.608 28.613 58.872 ;
     RECT  28.537 67.248 28.621 67.368 ;
     RECT  28.499 6.864 28.643 9.144 ;
     RECT  28.547 27.024 28.649 28.152 ;
     RECT  28.649 27.312 28.691 28.152 ;
     RECT  28.643 8.352 28.739 9.144 ;
     RECT  28.499 25.824 28.739 25.848 ;
     RECT  28.397 23.04 28.741 23.64 ;
     RECT  28.595 12.864 28.748 13.704 ;
     RECT  28.505 44.352 28.793 44.376 ;
     RECT  28.748 12.864 28.835 14.568 ;
     RECT  27.827 60 28.865 60.024 ;
     RECT  28.585 0.096 28.897 2.664 ;
     RECT  28.741 22.8 28.901 23.64 ;
     RECT  28.837 32.832 28.924 32.856 ;
     RECT  28.844 49.44 28.931 49.752 ;
     RECT  28.691 27.36 28.937 28.152 ;
     RECT  28.897 19.92 28.969 19.944 ;
     RECT  28.217 69.552 28.973 73.368 ;
     RECT  28.892 52.128 28.979 52.152 ;
     RECT  28.933 18.816 29.075 18.84 ;
     RECT  28.969 19.92 29.075 20.184 ;
     RECT  27.544 30.864 29.077 31.368 ;
     RECT  28.961 43.44 29.077 43.8 ;
     RECT  29.029 40.992 29.116 41.016 ;
     RECT  28.513 11.184 29.171 11.208 ;
     RECT  28.585 3.648 29.18 4.008 ;
     RECT  28.973 69.552 29.197 73.128 ;
     RECT  28.901 22.8 29.221 23.064 ;
     RECT  29.18 3.648 29.267 4.536 ;
     RECT  28.937 27.36 29.305 27.384 ;
     RECT  28.403 55.392 29.305 55.416 ;
     RECT  29.228 36.144 29.315 36.168 ;
     RECT  29.221 21.936 29.324 23.064 ;
     RECT  29.269 58.944 29.356 59.88 ;
     RECT  28.931 49.44 29.369 49.464 ;
     RECT  29.324 21.552 29.401 23.064 ;
     RECT  28.643 6.864 29.405 6.888 ;
     RECT  29.197 70.032 29.441 73.128 ;
     RECT  28.861 50.736 29.461 50.76 ;
     RECT  29.42 10.992 29.507 11.016 ;
     RECT  29.077 30.816 29.513 31.368 ;
     RECT  28.621 67.248 29.513 67.272 ;
     RECT  29.468 15.648 29.555 15.672 ;
     RECT  29.401 20.544 29.555 23.064 ;
     RECT  29.509 39.264 29.605 39.288 ;
     RECT  28.897 0.048 29.617 2.664 ;
     RECT  29.267 3.648 29.617 3.72 ;
     RECT  29.461 50.544 29.621 50.76 ;
     RECT  28.835 12.864 29.651 14.232 ;
     RECT  29.555 21.648 29.651 23.064 ;
     RECT  29.513 30.816 29.651 31.128 ;
     RECT  29.077 43.344 29.651 43.8 ;
     RECT  28.739 9.072 29.653 9.144 ;
     RECT  29.573 17.616 29.653 17.64 ;
     RECT  29.621 50.736 29.653 50.76 ;
     RECT  29.645 54.048 29.653 54.072 ;
     RECT  29.612 36.96 29.699 36.984 ;
     RECT  29.653 54.048 29.729 54.312 ;
     RECT  29.653 9.072 29.737 9.192 ;
     RECT  29.555 20.544 29.737 20.568 ;
     RECT  29.653 50.736 29.737 51.336 ;
     RECT  29.737 50.736 29.795 50.808 ;
     RECT  29.729 54.192 29.795 54.312 ;
     RECT  29.756 33.216 29.797 33.24 ;
     RECT  29.749 63.648 29.836 63.672 ;
     RECT  29.797 33.216 29.843 33.672 ;
     RECT  29.605 5.616 29.869 5.64 ;
     RECT  29.825 45.648 29.909 45.672 ;
     RECT  29.651 22.752 29.948 23.064 ;
     RECT  27.721 47.088 29.948 47.112 ;
     RECT  29.797 38.112 29.981 38.136 ;
     RECT  29.701 40.8 30.017 40.824 ;
     RECT  29.795 54.192 30.017 54.216 ;
     RECT  29.617 10.224 30.035 10.344 ;
     RECT  29.948 22.752 30.035 23.736 ;
     RECT  29.441 70.128 30.035 73.128 ;
     RECT  29.605 39.264 30.049 39.336 ;
     RECT  29.429 66.24 30.049 66.264 ;
     RECT  30.035 10.32 30.124 10.344 ;
     RECT  29.737 9.072 30.131 9.096 ;
     RECT  29.869 5.616 30.157 6.264 ;
     RECT  29.653 17.616 30.157 17.736 ;
     RECT  30.049 66.24 30.161 66.744 ;
     RECT  30.049 38.736 30.179 39.336 ;
     RECT  29.617 0.048 30.227 3.72 ;
     RECT  30.157 5.328 30.227 6.264 ;
     RECT  29.651 13.008 30.227 14.232 ;
     RECT  29.893 28.464 30.229 28.488 ;
     RECT  30.157 68.64 30.229 68.664 ;
     RECT  30.035 22.752 30.233 23.064 ;
     RECT  30.157 17.616 30.241 18.6 ;
     RECT  30.229 68.448 30.241 68.664 ;
     RECT  30.179 38.976 30.257 39.336 ;
     RECT  29.653 15.456 30.277 15.48 ;
     RECT  30.241 68.448 30.313 68.472 ;
     RECT  29.356 58.944 30.325 58.968 ;
     RECT  30.325 58.944 30.332 59.88 ;
     RECT  28.897 61.104 30.332 61.128 ;
     RECT  30.257 38.976 30.341 40.008 ;
     RECT  29.651 43.344 30.341 43.368 ;
     RECT  30.227 5.328 30.373 5.64 ;
     RECT  29.795 50.784 30.377 50.808 ;
     RECT  29.651 30.816 30.38 30.84 ;
     RECT  29.948 46.176 30.413 47.112 ;
     RECT  30.332 58.944 30.419 61.128 ;
     RECT  30.277 15.408 30.449 15.48 ;
     RECT  30.38 30.144 30.449 30.84 ;
     RECT  30.229 66.192 30.449 66.216 ;
     RECT  30.449 30.144 30.467 30.168 ;
     RECT  30.419 58.944 30.477 59.88 ;
     RECT  30.409 36.528 30.493 36.552 ;
     RECT  30.035 70.272 30.553 73.128 ;
     RECT  30.373 5.184 30.565 5.64 ;
     RECT  30.477 58.944 30.593 58.968 ;
     RECT  30.265 56.064 30.725 56.088 ;
     RECT  30.229 27.6 30.755 28.488 ;
     RECT  30.193 11.616 30.757 11.64 ;
     RECT  30.449 15.456 30.769 15.48 ;
     RECT  30.769 15.456 30.797 15.576 ;
     RECT  29.893 26.208 30.805 26.232 ;
     RECT  30.265 51.888 30.805 51.912 ;
     RECT  30.725 56.064 30.805 56.808 ;
     RECT  29.701 62.544 30.805 62.568 ;
     RECT  30.797 15.456 30.809 16.056 ;
     RECT  30.725 43.776 30.844 43.8 ;
     RECT  30.805 55.92 30.844 56.808 ;
     RECT  30.757 11.616 30.853 11.688 ;
     RECT  30.812 19.776 30.853 19.8 ;
     RECT  30.805 62.208 30.853 62.616 ;
     RECT  29.651 21.648 30.877 21.672 ;
     RECT  30.809 15.552 30.881 16.056 ;
     RECT  30.805 25.584 30.889 26.232 ;
     RECT  30.853 18.672 30.899 19.8 ;
     RECT  29.843 33.648 30.913 33.672 ;
     RECT  29.969 34.8 30.913 34.824 ;
     RECT  30.341 38.976 30.988 39.288 ;
     RECT  30.899 18.672 30.989 19.416 ;
     RECT  30.901 48.432 30.989 48.456 ;
     RECT  30.805 51.504 30.989 51.912 ;
     RECT  30.853 61.584 30.989 62.616 ;
     RECT  30.913 33.648 31.004 34.824 ;
     RECT  30.853 11.616 31.013 11.784 ;
     RECT  30.941 29.664 31.025 29.688 ;
     RECT  30.989 18.672 31.043 18.84 ;
     RECT  30.889 26.208 31.057 26.232 ;
     RECT  31.004 32.976 31.091 34.824 ;
     RECT  30.877 21.12 31.093 21.672 ;
     RECT  30.913 31.872 31.093 31.896 ;
     RECT  30.989 61.584 31.097 61.608 ;
     RECT  31.093 20.4 31.18 21.672 ;
     RECT  31.057 26.208 31.205 26.28 ;
     RECT  31.121 54.864 31.205 54.888 ;
     RECT  30.233 22.752 31.235 22.776 ;
     RECT  31.013 10.992 31.237 11.784 ;
     RECT  30.227 13.296 31.283 14.232 ;
     RECT  31.237 10.992 31.331 12.216 ;
     RECT  31.18 21.216 31.331 21.672 ;
     RECT  31.205 26.256 31.331 26.28 ;
     RECT  31.093 31.2 31.331 31.896 ;
     RECT  30.989 62.592 31.333 62.616 ;
     RECT  30.413 46.176 31.34 47.064 ;
     RECT  30.553 70.272 31.345 73.32 ;
     RECT  31.285 52.08 31.372 52.104 ;
     RECT  30.988 39.264 31.385 39.288 ;
     RECT  31.34 46.128 31.421 47.064 ;
     RECT  31.421 46.128 31.427 46.152 ;
     RECT  30.844 55.92 31.475 55.944 ;
     RECT  31.333 27.408 31.565 27.432 ;
     RECT  30.227 0.048 31.628 3.672 ;
     RECT  30.565 5.184 31.628 5.208 ;
     RECT  31.331 10.992 31.628 11.688 ;
     RECT  31.331 21.216 31.637 21.24 ;
     RECT  31.553 39.984 31.637 40.008 ;
     RECT  31.091 33.072 31.673 34.824 ;
     RECT  31.388 9.264 31.676 9.288 ;
     RECT  31.628 0.048 31.817 5.208 ;
     RECT  30.241 17.616 31.909 17.64 ;
     RECT  31.777 57.648 31.909 57.672 ;
     RECT  31.669 58.704 31.909 58.728 ;
     RECT  31.283 13.296 31.921 13.656 ;
     RECT  31.345 6.192 32.197 6.216 ;
     RECT  31.772 24.864 32.389 24.888 ;
     RECT  31.921 13.056 32.453 13.656 ;
     RECT  30.881 15.552 32.453 15.576 ;
     RECT  32.453 13.056 32.485 14.376 ;
     RECT  32.453 15.552 32.485 15.624 ;
     RECT  32.209 20.448 32.497 20.472 ;
     RECT  32.437 36.672 32.525 36.696 ;
     RECT  32.005 51.216 32.525 51.24 ;
     RECT  31.676 8.88 32.533 9.288 ;
     RECT  31.628 10.848 32.533 11.688 ;
     RECT  32.389 23.952 32.533 24.888 ;
     RECT  30.755 28.464 32.533 28.488 ;
     RECT  32.525 36.48 32.533 36.696 ;
     RECT  31.909 57.648 32.533 58.728 ;
     RECT  31.333 62.592 32.533 62.76 ;
     RECT  32.497 19.968 32.641 20.472 ;
     RECT  31.817 0.144 32.648 5.208 ;
     RECT  32.197 6.192 32.648 6.552 ;
     RECT  32.533 8.016 32.648 9.288 ;
     RECT  32.533 10.32 32.648 11.688 ;
     RECT  32.485 13.056 32.648 15.624 ;
     RECT  31.909 17.616 32.648 17.736 ;
     RECT  32.641 19.872 32.648 20.472 ;
     RECT  32.533 23.952 32.648 25.848 ;
     RECT  32.533 28.416 32.648 28.488 ;
     RECT  31.331 31.2 32.648 31.224 ;
     RECT  31.673 33.072 32.648 33.672 ;
     RECT  31.765 35.04 32.648 35.064 ;
     RECT  32.533 36.24 32.648 36.696 ;
     RECT  32.533 41.808 32.648 41.832 ;
     RECT  31.333 43.488 32.648 43.512 ;
     RECT  32.245 47.184 32.648 47.496 ;
     RECT  32.525 50.544 32.648 51.24 ;
     RECT  31.877 55.392 32.648 55.416 ;
     RECT  32.029 56.448 32.648 56.472 ;
     RECT  32.533 57.504 32.648 58.728 ;
     RECT  31.909 60 32.648 60.024 ;
     RECT  32.533 62.16 32.648 62.76 ;
     RECT  32.101 63.888 32.648 63.912 ;
     RECT  31.345 70.176 32.648 73.32 ;
     RECT  32.648 0.144 32.897 73.32 ;
     RECT  32.897 0.144 32.944 73.224 ;
     RECT  32.944 6.768 33.005 8.04 ;
     RECT  32.944 70.272 33.041 73.224 ;
     RECT  33.005 6.768 33.059 7.368 ;
     RECT  32.944 20.976 33.077 25.944 ;
     RECT  32.944 31.872 33.077 31.896 ;
     RECT  33.077 24.528 33.085 25.944 ;
     RECT  32.944 49.056 33.085 49.368 ;
     RECT  32.944 2.832 33.1 5.16 ;
     RECT  32.944 19.872 33.107 19.896 ;
     RECT  33.077 20.976 33.107 23.256 ;
     RECT  33.107 21.12 33.113 23.112 ;
     RECT  32.944 55.824 33.113 57.336 ;
     RECT  32.944 63.216 33.149 64.728 ;
     RECT  33.113 23.088 33.155 23.112 ;
     RECT  32.944 44.64 33.185 45.96 ;
     RECT  32.944 15.552 33.203 16.152 ;
     RECT  32.944 37.632 33.293 38.712 ;
     RECT  32.944 60.192 33.293 60.216 ;
     RECT  32.944 12.528 33.299 13.32 ;
     RECT  32.944 18.192 33.299 18.84 ;
     RECT  33.113 21.12 33.34 22.056 ;
     RECT  32.944 33.84 33.401 33.864 ;
     RECT  32.944 58.32 33.436 58.344 ;
     RECT  33.041 70.272 33.443 73.128 ;
     RECT  33.293 37.728 33.509 38.712 ;
     RECT  33.299 13.296 33.539 13.32 ;
     RECT  32.944 10.224 33.581 10.248 ;
     RECT  33.085 25.296 33.581 25.944 ;
     RECT  33.1 2.832 33.587 4.824 ;
     RECT  33.149 64.704 33.587 64.728 ;
     RECT  32.944 47.952 33.683 47.976 ;
     RECT  32.944 0.144 33.689 1.848 ;
     RECT  32.944 52.224 33.689 52.248 ;
     RECT  32.944 54.048 33.689 54.552 ;
     RECT  33.059 6.768 33.697 6.792 ;
     RECT  33.581 25.296 33.724 25.32 ;
     RECT  32.944 28.416 33.725 28.488 ;
     RECT  33.34 21.12 33.761 21.672 ;
     RECT  33.085 49.056 33.769 49.08 ;
     RECT  32.944 40.368 33.875 40.392 ;
     RECT  32.944 51.024 33.875 51.048 ;
     RECT  33.185 44.64 33.905 45.912 ;
     RECT  32.944 41.52 33.923 41.544 ;
     RECT  33.905 45.216 33.949 45.912 ;
     RECT  33.587 2.832 33.971 4.68 ;
     RECT  33.113 57.024 33.973 57.336 ;
     RECT  33.689 54.192 34.009 54.552 ;
     RECT  33.113 55.824 34.009 55.848 ;
     RECT  33.925 33.504 34.013 33.528 ;
     RECT  33.971 2.832 34.019 4.152 ;
     RECT  33.973 57.024 34.057 58.248 ;
     RECT  33.689 0.912 34.124 1.848 ;
     RECT  33.725 28.464 34.153 28.488 ;
     RECT  33.509 38.64 34.163 38.712 ;
     RECT  32.944 67.776 34.193 67.8 ;
     RECT  34.081 36.144 34.211 36.168 ;
     RECT  34.009 54.192 34.211 55.848 ;
     RECT  33.149 63.216 34.211 63.24 ;
     RECT  33.203 15.984 34.213 16.152 ;
     RECT  34.163 38.688 34.229 38.712 ;
     RECT  34.213 15.984 34.261 16.632 ;
     RECT  34.153 28.464 34.261 28.728 ;
     RECT  33.949 45.648 34.309 45.912 ;
     RECT  34.213 47.328 34.309 47.352 ;
     RECT  32.944 69.024 34.333 69.048 ;
     RECT  34.057 58.224 34.337 58.248 ;
     RECT  34.117 65.616 34.355 65.688 ;
     RECT  34.333 69.024 34.369 69.096 ;
     RECT  34.211 54.192 34.373 54.216 ;
     RECT  34.355 65.616 34.373 65.64 ;
     RECT  34.309 45.648 34.396 47.352 ;
     RECT  34.309 50.976 34.396 51 ;
     RECT  33.443 71.184 34.477 73.128 ;
     RECT  34.213 11.136 34.481 11.16 ;
     RECT  34.412 61.488 34.499 61.512 ;
     RECT  34.477 70.56 34.513 73.128 ;
     RECT  34.213 32.88 34.517 32.904 ;
     RECT  34.453 43.104 34.54 43.128 ;
     RECT  34.46 6.048 34.547 6.072 ;
     RECT  34.369 66.768 34.552 66.792 ;
     RECT  34.261 28.464 34.553 29.112 ;
     RECT  34.552 66.72 34.553 66.792 ;
     RECT  34.213 12.288 34.585 12.312 ;
     RECT  34.261 15.552 34.589 16.632 ;
     RECT  34.396 47.328 34.589 47.352 ;
     RECT  34.213 62.736 34.589 62.76 ;
     RECT  34.589 15.552 34.645 16.008 ;
     RECT  34.585 12.24 34.669 12.312 ;
     RECT  34.645 15.36 34.691 16.008 ;
     RECT  34.669 12.288 34.697 12.312 ;
     RECT  34.057 57.024 34.697 57.192 ;
     RECT  34.553 66.72 34.697 66.744 ;
     RECT  33.299 18.192 34.7 18.552 ;
     RECT  34.369 68.976 34.733 69.096 ;
     RECT  34.513 70.56 34.765 73.224 ;
     RECT  34.7 17.472 34.787 18.552 ;
     RECT  34.7 41.04 34.787 41.064 ;
     RECT  34.765 39.984 34.789 40.008 ;
     RECT  34.165 49.968 34.789 49.992 ;
     RECT  34.172 52.944 34.789 52.968 ;
     RECT  34.787 18.192 34.805 18.552 ;
     RECT  34.789 52.512 34.837 52.968 ;
     RECT  34.789 59.232 34.876 60.168 ;
     RECT  34.789 36.048 34.913 36.072 ;
     RECT  34.019 4.128 34.933 4.152 ;
     RECT  34.396 45.648 34.985 46.248 ;
     RECT  34.124 0.912 35.017 2.712 ;
     RECT  34.933 4.128 35.02 4.824 ;
     RECT  34.837 52.512 35.057 53.112 ;
     RECT  35.029 61.392 35.077 61.416 ;
     RECT  34.789 39.936 35.093 40.008 ;
     RECT  34.876 59.232 35.116 59.832 ;
     RECT  34.789 65.568 35.129 65.592 ;
     RECT  35.077 61.248 35.164 61.416 ;
     RECT  35.017 0.912 35.171 2.808 ;
     RECT  34.765 70.128 35.197 73.224 ;
     RECT  34.789 20.592 35.201 20.616 ;
     RECT  35.057 52.512 35.201 52.536 ;
     RECT  34.553 28.464 35.228 29.016 ;
     RECT  34.789 13.728 35.237 14.328 ;
     RECT  35.02 4.128 35.267 4.152 ;
     RECT  34.789 49.968 35.309 50.808 ;
     RECT  35.116 59.232 35.309 59.256 ;
     RECT  35.228 28.416 35.315 29.016 ;
     RECT  35.237 14.208 35.317 14.328 ;
     RECT  34.691 15.36 35.317 15.624 ;
     RECT  35.317 38.112 35.341 38.136 ;
     RECT  35.317 14.208 35.363 15.624 ;
     RECT  35.093 39.984 35.363 40.008 ;
     RECT  35.363 14.88 35.417 15.624 ;
     RECT  35.309 49.968 35.417 49.992 ;
     RECT  35.164 61.392 35.417 61.416 ;
     RECT  35.317 42.912 35.453 42.936 ;
     RECT  35.317 7.488 35.557 7.512 ;
     RECT  35.516 47.808 35.603 47.832 ;
     RECT  35.417 15.456 35.633 15.624 ;
     RECT  35.557 7.44 35.669 7.512 ;
     RECT  35.593 49.056 35.677 49.08 ;
     RECT  35.633 15.456 35.741 15.48 ;
     RECT  34.873 56.496 35.741 56.52 ;
     RECT  35.077 10.224 35.747 10.248 ;
     RECT  35.197 69.552 35.795 73.224 ;
     RECT  35.557 21.072 35.797 21.096 ;
     RECT  35.341 38.112 35.813 38.808 ;
     RECT  35.797 21.072 35.885 21.384 ;
     RECT  35.669 7.44 35.891 7.464 ;
     RECT  35.593 58.752 35.893 58.776 ;
     RECT  35.893 58.656 35.939 58.776 ;
     RECT  35.797 33.216 35.957 33.24 ;
     RECT  35.873 47.664 35.957 47.688 ;
     RECT  35.873 64.32 35.957 64.344 ;
     RECT  35.909 62.784 35.993 62.808 ;
     RECT  35.795 70.128 36.025 73.224 ;
     RECT  35.893 68.928 36.029 68.952 ;
     RECT  34.985 45.696 36.037 46.248 ;
     RECT  35.996 3.408 36.083 3.432 ;
     RECT  35.996 32.928 36.083 32.952 ;
     RECT  35.917 9.696 36.097 9.72 ;
     RECT  35.939 58.656 36.14 58.68 ;
     RECT  36.097 9.072 36.181 9.72 ;
     RECT  36.037 45.648 36.205 46.248 ;
     RECT  36.14 31.584 36.227 31.608 ;
     RECT  36.133 39.264 36.227 39.288 ;
     RECT  36.14 58.08 36.227 58.68 ;
     RECT  36.227 58.56 36.245 58.68 ;
     RECT  36.025 70.128 36.313 73.32 ;
     RECT  35.315 28.464 36.325 28.968 ;
     RECT  35.893 66.816 36.325 66.84 ;
     RECT  36.205 45.648 36.469 46.488 ;
     RECT  36.325 66.816 36.469 67.272 ;
     RECT  36.413 25.968 36.476 26.136 ;
     RECT  36.476 25.968 36.497 26.712 ;
     RECT  35.516 35.376 36.497 35.4 ;
     RECT  36.469 45.648 36.497 46.776 ;
     RECT  36.469 66.72 36.497 67.272 ;
     RECT  36.449 34.368 36.533 34.392 ;
     RECT  36.421 56.64 36.533 56.664 ;
     RECT  36.497 66.72 36.533 66.84 ;
     RECT  36.497 26.688 36.563 26.712 ;
     RECT  36.469 4.704 36.569 4.728 ;
     RECT  36.469 51.36 36.601 51.384 ;
     RECT  36.469 43.104 36.613 43.128 ;
     RECT  36.613 43.104 36.7 43.272 ;
     RECT  36.349 31.632 36.707 31.848 ;
     RECT  36.601 50.544 36.713 51.384 ;
     RECT  36.469 54.864 36.713 54.888 ;
     RECT  36.7 43.104 36.821 43.128 ;
     RECT  36.313 70.128 36.853 73.368 ;
     RECT  36.613 62.16 36.929 62.184 ;
     RECT  36.533 66.72 36.929 66.744 ;
     RECT  36.853 37.008 36.937 37.032 ;
     RECT  36.817 24.048 36.949 24.072 ;
     RECT  36.469 40.512 36.965 40.536 ;
     RECT  36.925 15.408 37.009 15.432 ;
     RECT  36.949 24.048 37.036 24.936 ;
     RECT  35.171 0.912 37.037 1.848 ;
     RECT  36.713 50.544 37.043 50.568 ;
     RECT  36.181 9.696 37.073 9.72 ;
     RECT  36.901 60.24 37.1 60.264 ;
     RECT  35.885 21.072 37.237 21.096 ;
     RECT  37.045 22.992 37.285 23.016 ;
     RECT  36.956 51.888 37.388 51.96 ;
     RECT  37.045 63.504 37.436 64.296 ;
     RECT  37.381 7.872 37.525 7.896 ;
     RECT  37.1 60.24 37.537 60.744 ;
     RECT  36.245 58.56 37.621 58.632 ;
     RECT  37.537 59.856 37.621 60.744 ;
     RECT  36.497 45.696 37.645 46.776 ;
     RECT  37.037 1.824 37.717 1.848 ;
     RECT  37.093 3.408 37.717 3.432 ;
     RECT  37.621 58.56 37.82 58.728 ;
     RECT  37.645 45.696 37.909 47.016 ;
     RECT  37.669 55.392 37.909 55.416 ;
     RECT  37.717 1.824 38.048 3.432 ;
     RECT  37.525 7.248 38.048 7.896 ;
     RECT  37.321 9.12 38.048 9.144 ;
     RECT  37.601 10.944 38.048 10.968 ;
     RECT  37.093 15.648 38.048 15.672 ;
     RECT  34.805 18.192 38.048 18.216 ;
     RECT  37.237 20.208 38.048 21.096 ;
     RECT  37.285 22.176 38.048 23.016 ;
     RECT  37.036 24.048 38.048 24.072 ;
     RECT  37.813 25.824 38.048 25.848 ;
     RECT  36.325 28.416 38.048 28.968 ;
     RECT  37.381 30.144 38.048 30.168 ;
     RECT  36.707 31.632 38.048 31.656 ;
     RECT  37.045 34.944 38.048 34.968 ;
     RECT  37.573 36.672 38.048 36.696 ;
     RECT  36.961 38.16 38.048 38.184 ;
     RECT  37.045 39.168 38.048 39.192 ;
     RECT  37.933 42.72 38.048 42.744 ;
     RECT  36.961 44.448 38.048 44.472 ;
     RECT  37.909 45.696 38.048 47.112 ;
     RECT  37.753 50.736 38.048 50.76 ;
     RECT  37.388 51.888 38.048 52.824 ;
     RECT  37.909 54.96 38.048 55.416 ;
     RECT  37.82 57.648 38.048 58.728 ;
     RECT  37.621 59.856 38.048 60.936 ;
     RECT  37.436 63.216 38.048 64.296 ;
     RECT  37.825 66.24 38.048 66.264 ;
     RECT  37.357 67.824 38.048 67.848 ;
     RECT  36.853 69.216 38.048 73.368 ;
     RECT  38.048 0.528 38.152 73.368 ;
     RECT  38.152 0.798 38.344 73.368 ;
     RECT  38.344 11.376 38.483 11.4 ;
     RECT  38.344 28.416 38.483 28.968 ;
     RECT  38.344 45.696 38.483 46.44 ;
     RECT  38.344 63.024 38.485 63.048 ;
     RECT  38.483 45.696 38.521 46.248 ;
     RECT  38.344 59.424 38.521 59.448 ;
     RECT  38.344 67.296 38.521 73.368 ;
     RECT  38.344 66.24 38.531 66.264 ;
     RECT  38.521 67.824 38.675 73.368 ;
     RECT  38.344 48.816 38.716 48.84 ;
     RECT  38.344 51.936 38.723 52.776 ;
     RECT  38.344 43.824 38.729 43.848 ;
     RECT  38.344 3.216 38.765 3.24 ;
     RECT  38.344 56.88 38.915 57.672 ;
     RECT  38.344 64.896 38.963 64.92 ;
     RECT  38.344 20.016 38.981 20.04 ;
     RECT  38.344 54.816 38.981 54.84 ;
     RECT  38.344 40.704 39.011 40.728 ;
     RECT  38.675 67.824 39.196 70.296 ;
     RECT  38.723 52.32 39.203 52.776 ;
     RECT  39.203 52.512 39.305 52.776 ;
     RECT  38.344 31.968 39.347 31.992 ;
     RECT  38.344 23.328 39.349 23.352 ;
     RECT  38.344 47.808 39.349 47.832 ;
     RECT  39.308 59.856 39.395 59.88 ;
     RECT  39.337 55.92 39.397 55.944 ;
     RECT  39.329 63.888 39.413 63.912 ;
     RECT  39.397 55.68 39.421 55.944 ;
     RECT  39.421 55.68 39.485 55.704 ;
     RECT  39.196 67.824 39.539 67.848 ;
     RECT  39.349 22.896 39.548 23.352 ;
     RECT  38.483 28.944 39.548 28.968 ;
     RECT  39.548 28.56 39.589 28.968 ;
     RECT  39.548 22.896 39.629 23.736 ;
     RECT  39.349 47.808 39.629 48.648 ;
     RECT  39.629 23.328 39.635 23.736 ;
     RECT  39.589 28.56 39.635 29.064 ;
     RECT  39.196 68.88 39.697 70.296 ;
     RECT  38.675 71.28 39.697 73.368 ;
     RECT  38.344 42.72 39.779 42.744 ;
     RECT  39.869 26.448 39.953 26.472 ;
     RECT  39.635 28.944 39.953 29.064 ;
     RECT  39.877 47.76 40.061 47.784 ;
     RECT  38.521 45.696 40.211 45.72 ;
     RECT  38.344 18.192 40.259 18.216 ;
     RECT  39.877 52.848 40.277 52.872 ;
     RECT  39.697 68.88 40.277 73.368 ;
     RECT  40.165 66.72 40.307 66.744 ;
     RECT  40.277 68.88 40.345 69 ;
     RECT  39.953 28.944 40.403 28.968 ;
     RECT  40.345 68.4 40.429 69 ;
     RECT  39.635 23.328 40.457 23.352 ;
     RECT  40.345 66.144 40.643 66.168 ;
     RECT  40.453 52.464 40.709 52.488 ;
     RECT  40.309 59.232 40.709 59.256 ;
     RECT  40.453 60.24 40.853 60.264 ;
     RECT  40.277 70.08 40.853 73.368 ;
     RECT  40.853 70.08 40.897 73.128 ;
     RECT  40.429 68.64 40.925 69 ;
     RECT  41.029 29.472 41.113 29.496 ;
     RECT  40.897 70.08 41.116 72.696 ;
     RECT  40.345 35.04 41.315 35.064 ;
     RECT  40.925 68.784 41.459 69 ;
     RECT  41.116 70.128 41.555 72.696 ;
     RECT  41.555 71.904 41.603 72.696 ;
     RECT  41.555 70.128 41.651 70.728 ;
     RECT  41.641 66.672 41.725 66.696 ;
     RECT  41.603 71.904 41.747 72.024 ;
     RECT  41.651 70.176 41.795 70.728 ;
     RECT  41.605 22.512 41.825 22.536 ;
     RECT  41.747 72 41.843 72.024 ;
     RECT  41.641 57.024 41.891 57.048 ;
     RECT  41.749 55.872 41.939 55.896 ;
     RECT  41.795 70.704 41.987 70.728 ;
     RECT  41.459 68.976 42.035 69 ;
     RECT  42.085 73.344 42.275 73.368 ;
    LAYER M5 ;
     RECT  0.624 0.144 28.536 0.362 ;
     RECT  0.624 0.362 28.584 0.517 ;
     RECT  0.24 0.517 28.584 0.555 ;
     RECT  29.664 0.245 29.688 0.611 ;
     RECT  32.64 0.517 32.76 0.787 ;
     RECT  38.04 0.517 38.16 0.787 ;
     RECT  32.64 0.787 32.952 1.391 ;
     RECT  32.64 1.391 33.048 1.475 ;
     RECT  30.192 1.391 30.216 1.967 ;
     RECT  0.24 0.555 28.488 2.067 ;
     RECT  30.192 1.967 30.744 2.101 ;
     RECT  0.24 2.067 29.064 2.207 ;
     RECT  30.192 2.101 31.464 2.207 ;
     RECT  32.64 1.475 32.952 2.629 ;
     RECT  34.416 2.067 35.016 2.643 ;
     RECT  0.24 2.207 31.464 2.701 ;
     RECT  29.616 2.701 31.464 2.731 ;
     RECT  34.176 2.643 35.016 2.731 ;
     RECT  30.096 2.731 31.464 2.773 ;
     RECT  32.448 2.629 32.952 2.773 ;
     RECT  38.04 0.787 38.352 2.773 ;
     RECT  30.096 2.773 32.952 2.783 ;
     RECT  30.096 2.783 34.008 2.795 ;
     RECT  35.136 2.773 35.16 2.859 ;
     RECT  31.296 2.795 34.008 3.059 ;
     RECT  37.728 2.773 38.352 3.205 ;
     RECT  0.24 2.701 28.536 3.307 ;
     RECT  37.728 3.205 38.712 3.307 ;
     RECT  37.728 3.307 38.352 3.381 ;
     RECT  31.296 3.059 31.416 3.385 ;
     RECT  32.544 3.059 34.008 3.469 ;
     RECT  36.048 3.381 36.072 3.469 ;
     RECT  37.104 3.381 38.352 3.469 ;
     RECT  30.096 2.795 30.264 3.499 ;
     RECT  3.888 3.307 28.536 3.539 ;
     RECT  30.192 3.499 30.264 3.731 ;
     RECT  3.888 3.539 28.2 3.819 ;
     RECT  30.24 3.731 30.264 4.011 ;
     RECT  32.544 3.469 32.952 4.021 ;
     RECT  3.888 3.819 28.104 4.587 ;
     RECT  29.232 4.501 29.256 4.587 ;
     RECT  31.68 4.021 32.952 4.587 ;
     RECT  0.24 3.307 2.664 4.595 ;
     RECT  33.936 4.533 33.96 4.715 ;
     RECT  36.48 4.655 36.504 4.739 ;
     RECT  32.496 4.587 32.952 4.755 ;
     RECT  35.232 4.117 35.256 4.755 ;
     RECT  32.496 4.755 33.576 4.843 ;
     RECT  34.944 4.755 35.256 4.843 ;
     RECT  32.496 4.843 33.048 5.171 ;
     RECT  30.192 5.279 30.216 5.587 ;
     RECT  29.616 5.587 30.216 5.605 ;
     RECT  29.616 5.605 30.552 5.675 ;
     RECT  30.192 5.675 30.552 5.689 ;
     RECT  3.888 4.587 27.816 5.747 ;
     RECT  4.176 5.747 27.816 5.893 ;
     RECT  35.232 4.843 35.256 6.037 ;
     RECT  34.512 6.037 35.256 6.123 ;
     RECT  32.496 5.171 32.952 6.181 ;
     RECT  31.872 6.181 32.952 6.265 ;
     RECT  30.192 5.689 30.216 6.275 ;
     RECT  32.208 6.265 32.952 6.563 ;
     RECT  4.176 5.893 28.104 6.661 ;
     RECT  32.496 6.563 32.952 6.739 ;
     RECT  32.496 6.739 33.672 6.827 ;
     RECT  4.176 6.661 28.296 6.901 ;
     RECT  4.176 6.901 28.392 7.139 ;
     RECT  38.04 3.469 38.352 7.237 ;
     RECT  4.176 7.139 4.44 7.349 ;
     RECT  35.232 6.123 35.256 7.391 ;
     RECT  32.496 6.827 33.048 7.403 ;
     RECT  3.888 7.349 4.44 7.437 ;
     RECT  4.32 7.437 4.44 7.475 ;
     RECT  35.232 7.391 35.88 7.475 ;
     RECT  4.416 7.475 4.44 7.523 ;
     RECT  35.232 7.475 35.352 7.523 ;
     RECT  5.64 7.139 28.392 7.765 ;
     RECT  37.536 7.237 38.352 7.861 ;
     RECT  5.64 7.765 28.632 7.989 ;
     RECT  0.24 4.595 2.472 8.819 ;
     RECT  32.496 7.403 32.952 8.851 ;
     RECT  31.728 8.851 32.952 8.939 ;
     RECT  30.48 8.565 30.504 9.061 ;
     RECT  35.232 7.523 35.256 9.061 ;
     RECT  5.64 7.989 28.776 9.119 ;
     RECT  30.096 9.061 30.504 9.119 ;
     RECT  35.232 9.061 36.168 9.145 ;
     RECT  2.448 8.819 2.472 9.155 ;
     RECT  5.64 9.119 30.504 9.155 ;
     RECT  37.392 7.861 38.352 9.155 ;
     RECT  14.112 9.155 30.504 9.203 ;
     RECT  30.096 9.203 30.504 9.235 ;
     RECT  30.096 9.235 31.464 9.323 ;
     RECT  0.24 8.819 1.416 9.731 ;
     RECT  32.496 8.939 32.952 10.195 ;
     RECT  35.232 9.145 35.256 10.195 ;
     RECT  14.112 9.203 28.776 10.213 ;
     RECT  30.096 9.323 30.504 10.213 ;
     RECT  35.232 10.195 35.736 10.213 ;
     RECT  32.496 10.195 33.528 10.283 ;
     RECT  35.088 10.213 35.736 10.283 ;
     RECT  5.64 9.155 12.744 10.293 ;
     RECT  13.824 10.213 28.776 10.293 ;
     RECT  30 10.213 30.504 10.357 ;
     RECT  5.64 10.293 28.776 10.707 ;
     RECT  5.28 10.707 28.776 10.795 ;
     RECT  5.64 10.795 28.776 10.805 ;
     RECT  30 10.357 31.368 10.805 ;
     RECT  5.64 10.805 31.368 10.837 ;
     RECT  32.496 10.283 32.952 10.837 ;
     RECT  4.224 10.789 4.248 10.885 ;
     RECT  38.04 9.155 38.352 10.933 ;
     RECT  3.312 10.885 4.248 10.987 ;
     RECT  37.632 10.933 38.352 11.017 ;
     RECT  35.088 10.283 35.256 11.115 ;
     RECT  34.224 11.125 34.248 11.209 ;
     RECT  38.04 11.017 38.352 11.317 ;
     RECT  38.04 11.317 38.472 11.411 ;
     RECT  5.64 10.837 32.952 11.725 ;
     RECT  35.232 11.115 35.256 12.191 ;
     RECT  34.608 12.191 35.256 12.213 ;
     RECT  5.64 11.725 31.32 12.227 ;
     RECT  34.224 12.213 35.256 12.275 ;
     RECT  34.224 12.275 34.248 12.323 ;
     RECT  32.496 11.725 32.952 12.517 ;
     RECT  5.64 12.227 30.984 12.563 ;
     RECT  32.496 12.517 33.288 13.045 ;
     RECT  31.968 13.045 33.288 13.285 ;
     RECT  35.232 12.275 35.256 13.679 ;
     RECT  5.64 12.563 6.072 13.971 ;
     RECT  5.64 13.971 6.12 14.059 ;
     RECT  7.68 12.563 30.984 14.197 ;
     RECT  31.968 13.285 33.528 14.197 ;
     RECT  34.8 13.679 35.256 14.197 ;
     RECT  34.8 14.197 35.352 14.339 ;
     RECT  7.68 14.197 33.528 14.891 ;
     RECT  5.64 14.059 6.072 15.349 ;
     RECT  7.68 14.891 31.272 15.349 ;
     RECT  35.232 14.339 35.352 15.349 ;
     RECT  5.64 15.349 31.272 15.467 ;
     RECT  36.96 15.397 36.984 15.481 ;
     RECT  34.656 15.349 35.352 15.635 ;
     RECT  38.04 11.411 38.352 15.637 ;
     RECT  32.496 14.891 33.528 15.861 ;
     RECT  32.496 15.861 33.672 15.983 ;
     RECT  34.656 15.635 35.256 15.983 ;
     RECT  32.496 15.983 35.256 16.019 ;
     RECT  32.496 16.019 34.248 16.643 ;
     RECT  5.64 15.467 5.952 17.077 ;
     RECT  7.68 15.467 31.272 17.077 ;
     RECT  32.496 16.643 33.528 17.077 ;
     RECT  5.52 17.077 5.952 17.219 ;
     RECT  35.232 16.019 35.256 17.461 ;
     RECT  34.752 17.461 35.256 17.643 ;
     RECT  7.68 17.077 33.528 18.517 ;
     RECT  7.68 18.517 33.672 18.731 ;
     RECT  5.64 17.219 5.952 18.805 ;
     RECT  2.016 18.805 2.904 18.899 ;
     RECT  5.64 18.805 6.312 18.899 ;
     RECT  2.016 18.899 2.04 18.987 ;
     RECT  4.56 18.911 4.584 18.995 ;
     RECT  37.104 15.637 38.352 19.957 ;
     RECT  37.104 19.957 38.808 20.051 ;
     RECT  3.408 20.005 3.432 20.179 ;
     RECT  3.216 20.179 3.432 20.267 ;
     RECT  35.232 17.643 35.256 20.533 ;
     RECT  34.8 20.533 35.256 20.627 ;
     RECT  3.696 20.581 4.008 20.665 ;
     RECT  3.696 20.665 3.72 20.779 ;
     RECT  7.68 18.731 33.528 21.109 ;
     RECT  7.68 21.109 33.672 21.193 ;
     RECT  35.232 20.627 35.256 21.301 ;
     RECT  35.232 21.301 35.832 21.395 ;
     RECT  41.616 22.453 41.64 22.547 ;
     RECT  40.224 18.181 40.248 22.837 ;
     RECT  39.36 22.837 40.248 22.931 ;
     RECT  37.104 20.051 38.352 22.943 ;
     RECT  37.056 22.943 38.352 23.027 ;
     RECT  39.552 22.931 40.248 23.113 ;
     RECT  39.6 23.113 40.248 23.787 ;
     RECT  37.104 23.027 38.352 23.989 ;
     RECT  1.728 24.479 1.752 24.563 ;
     RECT  7.68 21.193 33.528 24.563 ;
     RECT  7.68 24.563 7.944 24.787 ;
     RECT  7.104 24.787 7.944 24.875 ;
     RECT  37.056 23.989 38.352 24.901 ;
     RECT  5.64 18.899 5.952 25.055 ;
     RECT  9.12 24.563 33.528 25.141 ;
     RECT  9.12 25.141 33.672 25.357 ;
     RECT  5.64 25.055 6.312 25.715 ;
     RECT  36.96 24.901 38.352 25.957 ;
     RECT  36.432 25.957 38.352 26.185 ;
     RECT  2.88 26.207 2.904 26.291 ;
     RECT  40.224 23.787 40.248 26.399 ;
     RECT  39.888 26.399 40.248 26.483 ;
     RECT  9.12 25.357 33.528 26.539 ;
     RECT  10.224 26.539 33.528 26.603 ;
     RECT  36.528 26.185 38.352 26.731 ;
     RECT  10.224 26.603 16.872 26.819 ;
     RECT  5.64 25.715 5.952 26.869 ;
     RECT  7.824 24.875 7.944 26.869 ;
     RECT  7.392 26.869 7.944 27.051 ;
     RECT  5.136 26.869 5.952 27.061 ;
     RECT  7.392 27.051 7.848 27.061 ;
     RECT  5.136 27.061 7.848 27.107 ;
     RECT  5.64 27.107 7.848 27.145 ;
     RECT  18.336 26.603 33.528 27.381 ;
     RECT  35.232 21.395 35.256 27.381 ;
     RECT  7.44 27.145 7.848 27.443 ;
     RECT  5.64 27.145 5.952 28.371 ;
     RECT  18.336 27.381 35.256 28.371 ;
     RECT  4.32 28.371 5.952 28.405 ;
     RECT  7.824 27.443 7.848 28.405 ;
     RECT  37.104 26.731 38.352 28.405 ;
     RECT  18.336 28.371 35.304 28.453 ;
     RECT  36.336 28.405 38.472 28.453 ;
     RECT  3.408 28.405 7.848 28.459 ;
     RECT  3.408 28.459 3.432 28.489 ;
     RECT  18.336 28.453 38.472 28.489 ;
     RECT  40.224 26.483 40.248 28.533 ;
     RECT  39.6 28.533 40.248 28.933 ;
     RECT  18.336 28.489 38.352 29.035 ;
     RECT  18.336 29.035 35.256 29.039 ;
     RECT  39.6 28.933 40.392 29.092 ;
     RECT  5.64 28.459 7.848 29.123 ;
     RECT  18.24 29.039 35.256 29.123 ;
     RECT  36.24 29.035 38.352 29.163 ;
     RECT  40.224 29.092 40.392 29.461 ;
     RECT  10.224 26.819 16.752 29.523 ;
     RECT  18.24 29.123 33.528 29.523 ;
     RECT  40.224 29.461 41.064 29.547 ;
     RECT  10.224 29.523 33.528 29.611 ;
     RECT  7.824 29.123 7.848 29.675 ;
     RECT  9.12 26.539 9.144 29.749 ;
     RECT  9.12 29.749 9.72 29.833 ;
     RECT  5.64 29.123 6.6 30.191 ;
     RECT  5.136 30.191 6.6 30.275 ;
     RECT  18.336 29.611 33.528 30.709 ;
     RECT  3.984 30.805 4.008 30.891 ;
     RECT  10.896 29.611 16.752 30.901 ;
     RECT  17.952 30.709 33.528 30.901 ;
     RECT  7.824 30.949 7.848 31.147 ;
     RECT  9.12 29.833 9.144 31.237 ;
     RECT  10.896 30.901 33.528 31.237 ;
     RECT  5.64 30.275 6.6 31.333 ;
     RECT  5.52 31.333 6.6 31.349 ;
     RECT  9.12 31.237 33.528 31.403 ;
     RECT  5.52 31.349 7.368 31.417 ;
     RECT  35.232 29.123 35.256 31.541 ;
     RECT  36.336 29.163 38.352 31.541 ;
     RECT  35.232 31.541 38.352 31.629 ;
     RECT  5.64 31.417 7.368 31.753 ;
     RECT  10.368 31.403 33.528 31.763 ;
     RECT  36.336 31.629 38.352 31.919 ;
     RECT  40.224 29.547 40.392 31.919 ;
     RECT  10.944 31.763 33.528 31.979 ;
     RECT  2.88 31.919 2.904 32.003 ;
     RECT  36.336 31.919 40.392 32.003 ;
     RECT  7.344 31.753 7.368 32.339 ;
     RECT  5.64 31.753 5.952 32.495 ;
     RECT  14.256 31.979 33.528 32.531 ;
     RECT  18.336 32.531 33.528 32.821 ;
     RECT  10.944 31.979 12.648 32.885 ;
     RECT  35.232 31.629 35.256 32.885 ;
     RECT  36.336 32.003 38.352 32.885 ;
     RECT  18.336 32.821 34.248 32.915 ;
     RECT  5.136 32.495 5.952 32.917 ;
     RECT  5.04 32.917 5.952 33.003 ;
     RECT  18.336 32.915 33.96 33.131 ;
     RECT  35.232 32.885 38.352 33.289 ;
     RECT  3.984 33.253 4.008 33.337 ;
     RECT  18.432 33.131 33.96 33.539 ;
     RECT  9.12 31.403 9.144 33.781 ;
     RECT  10.848 32.885 12.648 33.781 ;
     RECT  9.12 33.781 12.648 33.845 ;
     RECT  9.024 33.845 12.648 33.875 ;
     RECT  9.024 33.875 9.912 33.899 ;
     RECT  7.44 33.839 7.464 33.923 ;
     RECT  9.024 33.899 9.144 33.933 ;
     RECT  9.12 33.933 9.144 34.411 ;
     RECT  10.896 33.875 12.648 34.787 ;
     RECT  18.432 33.539 33.528 34.835 ;
     RECT  40.224 32.003 40.392 35.029 ;
     RECT  31.2 34.835 33.528 35.115 ;
     RECT  14.256 32.531 16.752 35.317 ;
     RECT  18.432 34.835 30.12 35.317 ;
     RECT  35.232 33.289 35.256 35.317 ;
     RECT  36.336 33.289 38.352 35.317 ;
     RECT  14.256 35.317 30.12 35.363 ;
     RECT  14.256 35.363 24.552 35.411 ;
     RECT  35.232 35.317 38.352 35.435 ;
     RECT  16.08 35.411 24.552 35.507 ;
     RECT  14.256 35.411 14.952 35.615 ;
     RECT  13.68 35.615 14.952 35.699 ;
     RECT  14.16 35.699 14.952 35.947 ;
     RECT  35.232 35.435 35.256 35.999 ;
     RECT  34.8 35.999 35.256 36.083 ;
     RECT  32.352 35.115 33.528 36.133 ;
     RECT  32.352 36.133 34.2 36.217 ;
     RECT  16.08 35.507 24.504 36.459 ;
     RECT  16.08 36.459 16.872 36.467 ;
     RECT  25.872 35.363 30.12 36.469 ;
     RECT  31.2 35.115 31.272 36.469 ;
     RECT  18.432 36.459 24.504 36.523 ;
     RECT  25.872 36.469 31.272 36.563 ;
     RECT  14.16 35.947 14.904 36.959 ;
     RECT  10.944 34.787 12.648 36.997 ;
     RECT  4.08 36.949 4.104 37.035 ;
     RECT  14.16 36.959 14.952 37.035 ;
     RECT  14.352 37.035 14.952 37.043 ;
     RECT  2.544 37.045 2.568 37.139 ;
     RECT  10.416 36.997 12.648 37.285 ;
     RECT  10.416 37.285 13.128 37.369 ;
     RECT  25.872 36.563 30.12 37.557 ;
     RECT  16.08 36.467 16.752 37.573 ;
     RECT  10.416 37.369 12.552 37.611 ;
     RECT  5.64 33.003 5.952 37.621 ;
     RECT  7.872 37.621 7.896 37.715 ;
     RECT  10.416 37.611 11.88 37.727 ;
     RECT  35.232 36.083 35.256 38.101 ;
     RECT  5.64 37.621 6.312 38.133 ;
     RECT  16.08 37.573 17.112 38.149 ;
     RECT  4.368 38.101 4.392 38.187 ;
     RECT  35.232 38.101 35.352 38.187 ;
     RECT  25.632 37.557 30.12 38.197 ;
     RECT  10.272 37.727 11.88 38.227 ;
     RECT  9.984 38.227 11.88 38.315 ;
     RECT  16.08 38.149 17.304 38.389 ;
     RECT  18.432 36.523 24.36 38.389 ;
     RECT  16.08 38.389 24.36 38.473 ;
     RECT  14.352 37.043 14.904 38.581 ;
     RECT  25.584 38.197 30.12 38.581 ;
     RECT  32.352 36.217 33.528 38.581 ;
     RECT  25.488 38.581 30.12 38.665 ;
     RECT  14.256 38.581 14.904 38.675 ;
     RECT  32.352 38.581 34.152 38.675 ;
     RECT  25.632 38.665 30.12 38.699 ;
     RECT  32.352 38.675 33.864 38.723 ;
     RECT  25.872 38.699 30.12 38.725 ;
     RECT  25.872 38.725 30.168 38.965 ;
     RECT  31.2 36.563 31.272 38.965 ;
     RECT  5.64 38.133 6.504 39.157 ;
     RECT  5.64 39.157 6.984 39.187 ;
     RECT  35.232 38.187 35.256 39.215 ;
     RECT  36.336 35.435 38.352 39.215 ;
     RECT  5.64 39.187 7.56 39.275 ;
     RECT  35.232 39.215 38.352 39.299 ;
     RECT  16.08 38.473 17.304 39.733 ;
     RECT  18.432 38.473 24.36 39.733 ;
     RECT  14.88 38.675 14.904 39.781 ;
     RECT  14.256 39.781 14.904 39.865 ;
     RECT  5.64 39.275 6.888 39.915 ;
     RECT  10.416 38.315 11.88 39.925 ;
     RECT  16.08 39.733 24.36 39.925 ;
     RECT  25.872 38.965 31.272 39.925 ;
     RECT  32.352 38.723 33.528 39.925 ;
     RECT  35.232 39.299 35.352 39.925 ;
     RECT  25.872 39.925 33.528 39.973 ;
     RECT  10.416 39.925 12.216 39.979 ;
     RECT  34.8 39.925 35.352 40.009 ;
     RECT  10.848 39.979 12.216 40.019 ;
     RECT  25.632 39.973 33.528 40.019 ;
     RECT  35.232 40.009 35.352 40.019 ;
     RECT  16.032 39.925 24.36 40.117 ;
     RECT  8.496 40.053 8.52 40.141 ;
     RECT  16.032 40.117 24.456 40.147 ;
     RECT  25.632 40.019 30.168 40.171 ;
     RECT  14.88 39.865 14.904 40.223 ;
     RECT  15.936 40.147 24.456 40.223 ;
     RECT  25.632 40.171 25.896 40.223 ;
     RECT  14.88 40.223 25.896 40.307 ;
     RECT  32.352 40.019 33.528 40.309 ;
     RECT  32.352 40.309 33.864 40.403 ;
     RECT  14.88 40.307 24.36 40.547 ;
     RECT  13.488 40.501 13.512 40.595 ;
     RECT  36.336 39.299 38.352 40.693 ;
     RECT  10.848 40.019 11.88 40.981 ;
     RECT  35.232 40.019 35.256 40.991 ;
     RECT  14.88 40.547 17.304 41.013 ;
     RECT  10.176 40.981 13.128 41.067 ;
     RECT  34.752 40.991 35.256 41.075 ;
     RECT  14.208 41.013 17.304 41.123 ;
     RECT  10.272 41.067 13.128 41.209 ;
     RECT  11.04 41.209 13.128 41.401 ;
     RECT  32.352 40.403 33.528 41.509 ;
     RECT  5.64 39.915 5.952 41.567 ;
     RECT  32.352 41.509 33.912 41.593 ;
     RECT  5.64 41.567 6.888 41.651 ;
     RECT  14.832 41.123 17.304 41.651 ;
     RECT  11.04 41.401 12.552 42.035 ;
     RECT  14.88 41.651 17.304 42.325 ;
     RECT  18.432 40.547 24.36 42.325 ;
     RECT  11.04 42.035 11.88 42.671 ;
     RECT  36.336 40.693 39 42.709 ;
     RECT  40.224 35.029 41.304 42.709 ;
     RECT  10.944 42.671 11.88 42.805 ;
     RECT  9.072 42.143 9.096 42.863 ;
     RECT  35.232 41.075 35.256 42.863 ;
     RECT  35.232 42.863 35.352 42.933 ;
     RECT  9.072 42.863 9.144 42.947 ;
     RECT  34.8 42.933 35.352 42.947 ;
     RECT  14.88 42.325 24.36 42.997 ;
     RECT  25.872 40.307 25.896 42.997 ;
     RECT  32.352 41.593 33.528 43.061 ;
     RECT  34.8 42.947 35.256 43.061 ;
     RECT  32.352 43.061 35.256 43.149 ;
     RECT  8.352 43.093 8.376 43.179 ;
     RECT  10.512 42.805 11.88 43.179 ;
     RECT  14.4 42.997 24.36 43.219 ;
     RECT  25.68 42.997 25.896 43.285 ;
     RECT  27.24 40.171 30.168 43.285 ;
     RECT  25.68 43.285 30.168 43.295 ;
     RECT  31.2 40.019 31.272 43.295 ;
     RECT  14.064 43.219 24.36 43.317 ;
     RECT  25.68 43.295 31.272 43.439 ;
     RECT  25.68 43.439 31.368 43.523 ;
     RECT  13.728 43.317 24.36 43.819 ;
     RECT  25.68 43.523 31.272 43.819 ;
     RECT  14.88 43.819 24.36 43.871 ;
     RECT  25.68 43.819 30.168 43.871 ;
     RECT  13.728 43.819 13.752 43.955 ;
     RECT  14.88 43.871 30.168 44.483 ;
     RECT  11.04 43.179 11.88 44.563 ;
     RECT  13.488 44.533 13.512 44.581 ;
     RECT  11.04 44.563 11.976 44.591 ;
     RECT  13.344 44.581 13.512 44.591 ;
     RECT  32.352 43.149 33.528 44.591 ;
     RECT  10.944 44.591 13.512 45.157 ;
     RECT  32.352 44.591 33.672 45.167 ;
     RECT  32.352 45.167 33.912 45.251 ;
     RECT  14.88 44.483 24.36 45.493 ;
     RECT  10.272 45.157 13.512 45.547 ;
     RECT  13.392 45.547 13.512 45.599 ;
     RECT  14.832 45.493 24.36 45.599 ;
     RECT  35.232 43.149 35.256 45.599 ;
     RECT  36.336 42.709 41.304 45.599 ;
     RECT  7.44 45.599 7.464 45.683 ;
     RECT  10.272 45.547 12.12 45.683 ;
     RECT  13.392 45.599 24.36 45.683 ;
     RECT  34.8 45.599 41.304 45.683 ;
     RECT  10.272 45.683 11.352 45.769 ;
     RECT  25.68 44.483 30.168 45.941 ;
     RECT  31.2 43.819 31.272 45.941 ;
     RECT  25.68 45.941 31.272 46.099 ;
     RECT  32.352 45.251 33.576 46.099 ;
     RECT  14.88 45.683 24.36 46.175 ;
     RECT  25.68 46.099 33.576 46.175 ;
     RECT  10.752 45.769 11.352 46.187 ;
     RECT  14.88 46.175 33.576 46.259 ;
     RECT  9.12 46.261 9.144 46.345 ;
     RECT  25.872 46.259 33.576 46.611 ;
     RECT  34.8 45.683 35.256 46.611 ;
     RECT  25.872 46.611 35.256 46.699 ;
     RECT  9.696 47.029 9.72 47.113 ;
     RECT  25.872 46.699 34.248 47.113 ;
     RECT  25.872 47.113 31.272 47.147 ;
     RECT  32.304 47.113 34.248 47.219 ;
     RECT  11.04 46.187 11.352 47.221 ;
     RECT  13.488 47.187 13.512 47.275 ;
     RECT  10.272 47.221 11.352 47.315 ;
     RECT  32.352 47.219 34.248 47.363 ;
     RECT  35.232 46.699 35.256 47.605 ;
     RECT  36.336 45.683 41.304 47.605 ;
     RECT  13.68 47.711 13.704 47.763 ;
     RECT  14.88 46.259 24.36 47.763 ;
     RECT  13.68 47.763 24.36 47.795 ;
     RECT  13.968 47.795 24.36 47.851 ;
     RECT  35.232 47.605 41.304 47.851 ;
     RECT  10.368 47.315 11.352 47.939 ;
     RECT  32.352 47.363 33.672 48.013 ;
     RECT  25.872 47.147 30.168 48.373 ;
     RECT  31.2 47.147 31.272 48.373 ;
     RECT  25.872 48.373 31.272 48.421 ;
     RECT  25.632 48.421 31.272 48.467 ;
     RECT  10.944 47.939 11.352 48.565 ;
     RECT  10.944 48.565 11.448 48.659 ;
     RECT  10.944 48.659 11.352 48.707 ;
     RECT  32.352 48.013 33.528 49.007 ;
     RECT  35.232 47.851 35.256 49.007 ;
     RECT  36.336 47.851 41.304 49.007 ;
     RECT  3.984 49.007 4.008 49.091 ;
     RECT  7.44 49.007 7.464 49.091 ;
     RECT  12.96 49.007 12.984 49.091 ;
     RECT  35.232 49.007 41.304 49.091 ;
     RECT  7.008 49.397 7.32 49.485 ;
     RECT  4.272 49.429 4.296 49.515 ;
     RECT  11.04 48.707 11.352 49.765 ;
     RECT  32.352 49.007 33.72 49.939 ;
     RECT  10.944 49.765 11.352 49.957 ;
     RECT  14.88 47.851 24.36 49.957 ;
     RECT  25.632 48.467 30.168 49.957 ;
     RECT  7.2 49.485 7.32 50.027 ;
     RECT  10.944 49.957 12.024 50.041 ;
     RECT  14.88 49.957 30.168 50.041 ;
     RECT  35.232 49.091 35.352 50.041 ;
     RECT  7.296 50.027 7.32 50.091 ;
     RECT  10.944 50.041 11.352 50.533 ;
     RECT  14.88 50.041 24.36 50.533 ;
     RECT  10.848 50.533 11.352 50.617 ;
     RECT  14.832 50.533 24.36 50.735 ;
     RECT  25.872 50.041 30.168 50.735 ;
     RECT  31.2 48.467 31.272 50.735 ;
     RECT  32.352 49.939 34.2 50.735 ;
     RECT  35.232 50.041 35.256 50.735 ;
     RECT  13.968 50.735 24.36 50.771 ;
     RECT  13.968 50.771 13.992 50.819 ;
     RECT  25.872 50.735 31.272 51.205 ;
     RECT  32.352 50.735 35.256 51.205 ;
     RECT  25.872 51.205 35.256 51.301 ;
     RECT  25.68 51.301 35.256 51.307 ;
     RECT  25.68 51.307 31.32 51.385 ;
     RECT  9.696 51.637 9.72 51.721 ;
     RECT  11.04 50.617 11.352 51.877 ;
     RECT  5.64 41.651 5.952 51.887 ;
     RECT  14.976 50.771 24.36 51.893 ;
     RECT  11.04 51.877 11.448 51.925 ;
     RECT  25.872 51.385 31.32 51.961 ;
     RECT  5.64 51.887 6.888 51.971 ;
     RECT  10.752 51.925 11.448 52.011 ;
     RECT  14.832 51.893 24.36 52.117 ;
     RECT  31.2 51.961 31.32 52.139 ;
     RECT  14.208 52.117 24.36 52.203 ;
     RECT  7.248 52.213 7.272 52.395 ;
     RECT  11.04 52.011 11.448 52.463 ;
     RECT  35.232 51.307 35.256 52.463 ;
     RECT  5.64 51.971 6.264 52.489 ;
     RECT  11.04 52.463 12.024 52.547 ;
     RECT  32.352 51.307 33.672 52.917 ;
     RECT  34.8 52.463 35.256 52.917 ;
     RECT  32.352 52.917 35.256 53.005 ;
     RECT  34.848 53.005 35.256 53.123 ;
     RECT  14.88 52.203 24.36 53.493 ;
     RECT  11.04 52.547 11.352 53.557 ;
     RECT  12.528 53.493 12.552 53.557 ;
     RECT  14.496 53.493 24.36 53.581 ;
     RECT  11.04 53.557 12.552 53.603 ;
     RECT  11.04 53.603 12.024 53.699 ;
     RECT  13.104 53.685 13.224 53.867 ;
     RECT  13.104 53.867 13.128 53.891 ;
     RECT  9.36 53.907 9.384 53.995 ;
     RECT  32.352 53.005 33.528 54.037 ;
     RECT  32.352 54.037 33.672 54.133 ;
     RECT  32.352 54.133 34.248 54.227 ;
     RECT  7.44 54.191 7.464 54.275 ;
     RECT  7.248 54.483 7.272 54.571 ;
     RECT  14.88 53.581 24.36 54.815 ;
     RECT  31.2 52.139 31.272 54.815 ;
     RECT  31.152 54.815 31.272 54.899 ;
     RECT  11.04 53.699 11.352 55.237 ;
     RECT  31.2 54.899 31.272 55.343 ;
     RECT  32.352 54.227 34.2 55.343 ;
     RECT  11.04 55.237 12.072 55.403 ;
     RECT  14.256 54.815 24.36 55.475 ;
     RECT  36.336 49.091 41.304 55.861 ;
     RECT  25.872 51.961 30.168 55.909 ;
     RECT  31.2 55.343 34.2 55.909 ;
     RECT  14.88 55.475 24.36 55.967 ;
     RECT  25.872 55.909 34.2 56.373 ;
     RECT  35.232 53.123 35.256 56.373 ;
     RECT  14.88 55.967 24.408 56.437 ;
     RECT  25.872 56.373 35.256 56.437 ;
     RECT  14.88 56.437 35.352 56.521 ;
     RECT  32.352 56.521 35.352 56.531 ;
     RECT  14.88 56.521 31.272 56.819 ;
     RECT  11.04 55.403 11.352 57.061 ;
     RECT  13.104 57.013 13.128 57.097 ;
     RECT  11.04 57.061 11.448 57.141 ;
     RECT  32.352 56.531 35.256 57.203 ;
     RECT  14.88 56.819 30.168 57.269 ;
     RECT  13.248 57.269 13.272 57.357 ;
     RECT  11.04 57.141 11.544 57.503 ;
     RECT  14.832 57.269 30.168 57.539 ;
     RECT  11.04 57.503 11.88 57.589 ;
     RECT  31.2 56.819 31.272 57.589 ;
     RECT  32.352 57.203 34.056 57.589 ;
     RECT  14.832 57.539 24.84 57.647 ;
     RECT  3.984 57.589 4.008 57.683 ;
     RECT  9.12 57.589 9.144 57.683 ;
     RECT  14.256 57.647 24.84 57.683 ;
     RECT  14.256 57.683 24.36 57.731 ;
     RECT  35.232 57.203 35.256 58.037 ;
     RECT  36.336 55.861 41.928 58.037 ;
     RECT  13.104 58.069 13.128 58.155 ;
     RECT  31.2 57.589 34.056 58.165 ;
     RECT  31.2 58.165 34.248 58.355 ;
     RECT  11.04 57.589 11.976 58.463 ;
     RECT  11.04 58.463 12.024 58.547 ;
     RECT  7.44 58.485 7.464 58.607 ;
     RECT  7.392 58.607 7.464 58.608 ;
     RECT  7.392 58.608 7.416 58.691 ;
     RECT  12.336 58.645 12.36 58.731 ;
     RECT  5.64 52.489 5.952 58.741 ;
     RECT  35.232 58.037 41.928 58.787 ;
     RECT  5.64 58.741 6.312 58.835 ;
     RECT  25.872 57.539 30.168 58.933 ;
     RECT  31.2 58.355 31.272 58.933 ;
     RECT  7.008 59.029 7.032 59.115 ;
     RECT  32.352 58.355 34.248 59.183 ;
     RECT  35.232 58.787 35.256 59.183 ;
     RECT  25.872 58.933 31.272 59.893 ;
     RECT  32.352 59.183 35.256 59.893 ;
     RECT  14.88 57.731 24.36 59.941 ;
     RECT  14.88 59.941 24.552 60.025 ;
     RECT  25.872 59.893 35.256 60.035 ;
     RECT  32.352 60.035 35.256 60.179 ;
     RECT  9.12 60.767 9.144 60.851 ;
     RECT  14.88 60.025 24.36 60.853 ;
     RECT  13.728 60.853 24.36 60.937 ;
     RECT  8.352 60.853 8.376 60.947 ;
     RECT  13.728 60.937 13.752 60.947 ;
     RECT  35.232 60.179 35.256 61.237 ;
     RECT  11.04 58.547 11.352 61.333 ;
     RECT  25.872 60.035 31.272 61.333 ;
     RECT  35.088 61.237 35.256 61.343 ;
     RECT  11.04 61.333 12.072 61.419 ;
     RECT  32.352 60.179 34.056 61.459 ;
     RECT  35.04 61.343 35.256 61.459 ;
     RECT  14.88 60.937 24.36 61.535 ;
     RECT  32.352 61.459 35.256 61.547 ;
     RECT  12.384 61.557 12.408 61.645 ;
     RECT  14.88 61.535 24.408 62.111 ;
     RECT  25.68 61.333 31.272 62.111 ;
     RECT  14.256 62.111 31.272 62.195 ;
     RECT  25.344 62.195 31.272 62.281 ;
     RECT  12.528 62.303 12.552 62.387 ;
     RECT  31.2 62.281 31.272 62.547 ;
     RECT  32.352 61.547 34.056 62.547 ;
     RECT  31.2 62.547 34.056 62.635 ;
     RECT  35.232 61.547 35.256 62.645 ;
     RECT  36.336 58.787 41.928 62.645 ;
     RECT  32.352 62.635 34.056 62.709 ;
     RECT  31.2 62.635 31.368 62.771 ;
     RECT  32.352 62.709 34.248 62.797 ;
     RECT  35.232 62.645 41.928 62.819 ;
     RECT  11.04 61.419 11.352 62.965 ;
     RECT  14.256 62.195 24.36 62.965 ;
     RECT  13.68 62.965 24.36 63.059 ;
     RECT  10.944 62.965 11.352 63.157 ;
     RECT  12.48 63.093 12.504 63.181 ;
     RECT  10.944 63.157 11.448 63.215 ;
     RECT  14.016 63.059 24.36 63.263 ;
     RECT  25.344 62.281 30.168 63.263 ;
     RECT  10.944 63.215 12.168 63.275 ;
     RECT  14.016 63.263 30.168 63.275 ;
     RECT  32.352 62.797 34.2 63.289 ;
     RECT  14.88 63.275 30.168 63.347 ;
     RECT  11.04 63.275 12.168 63.779 ;
     RECT  5.64 58.835 5.952 63.839 ;
     RECT  31.2 62.771 31.272 63.839 ;
     RECT  32.352 63.289 34.056 63.839 ;
     RECT  5.64 63.839 6.312 63.923 ;
     RECT  8.544 63.839 8.568 63.923 ;
     RECT  31.2 63.839 34.056 63.923 ;
     RECT  35.232 62.819 35.256 64.309 ;
     RECT  36.336 62.819 41.928 64.309 ;
     RECT  7.92 64.245 7.944 64.333 ;
     RECT  14.88 63.347 24.36 64.357 ;
     RECT  25.632 63.347 30.168 64.357 ;
     RECT  35.232 64.309 41.928 64.393 ;
     RECT  11.04 63.779 11.352 64.885 ;
     RECT  10.848 64.885 11.352 64.991 ;
     RECT  12.528 64.943 12.552 65.027 ;
     RECT  10.464 64.991 11.352 65.141 ;
     RECT  13.68 65.077 13.704 65.161 ;
     RECT  9.744 65.141 11.352 65.267 ;
     RECT  32.352 63.923 34.056 65.519 ;
     RECT  35.232 64.393 35.256 65.519 ;
     RECT  10.272 65.267 11.352 65.603 ;
     RECT  32.352 65.519 35.256 65.707 ;
     RECT  14.88 64.357 30.168 66.143 ;
     RECT  31.2 63.923 31.272 66.143 ;
     RECT  14.256 66.143 31.272 66.227 ;
     RECT  35.232 65.707 35.256 66.771 ;
     RECT  36.336 64.393 41.928 66.771 ;
     RECT  7.44 66.709 7.464 66.795 ;
     RECT  35.232 66.771 41.928 66.859 ;
     RECT  11.04 65.603 11.352 67.247 ;
     RECT  36.336 66.859 41.928 67.283 ;
     RECT  11.04 67.247 11.448 67.331 ;
     RECT  14.832 66.227 30.168 67.823 ;
     RECT  14.256 67.823 30.168 68.399 ;
     RECT  31.2 66.227 31.272 68.399 ;
     RECT  14.256 68.399 31.272 68.483 ;
     RECT  14.256 68.483 30.216 68.675 ;
     RECT  14.256 68.675 30.168 68.917 ;
     RECT  35.232 66.859 35.256 68.917 ;
     RECT  36.384 67.283 41.928 68.917 ;
     RECT  35.232 68.917 41.928 68.965 ;
     RECT  13.632 68.917 30.168 69.001 ;
     RECT  14.352 69.001 30.168 69.587 ;
     RECT  9.696 69.973 9.72 70.059 ;
     RECT  31.2 68.483 31.272 70.165 ;
     RECT  32.352 65.707 34.056 70.165 ;
     RECT  4.128 70.127 4.152 70.211 ;
     RECT  8.544 70.127 8.568 70.211 ;
     RECT  5.64 63.923 5.952 70.261 ;
     RECT  26.304 69.587 30.168 70.309 ;
     RECT  5.52 70.261 5.952 70.389 ;
     RECT  6.96 70.261 6.984 70.443 ;
     RECT  8.016 70.261 8.04 70.443 ;
     RECT  3.264 70.389 3.288 70.499 ;
     RECT  4.896 70.389 5.952 70.499 ;
     RECT  26.304 70.309 30.216 70.501 ;
     RECT  31.2 70.165 34.056 70.501 ;
     RECT  14.352 69.587 25.32 70.693 ;
     RECT  26.304 70.501 34.056 70.693 ;
     RECT  35.232 68.965 42.024 71.173 ;
     RECT  14.352 70.693 34.056 71.269 ;
     RECT  35.184 71.173 42.024 71.269 ;
     RECT  14.352 71.269 42.024 71.893 ;
     RECT  14.304 71.893 42.024 72.373 ;
     RECT  0.24 9.731 0.552 72.383 ;
     RECT  5.64 70.499 5.952 72.383 ;
     RECT  11.04 67.331 11.352 72.383 ;
     RECT  0.432 72.383 0.552 72.653 ;
     RECT  5.832 72.383 5.952 72.653 ;
     RECT  11.232 72.383 11.352 72.653 ;
     RECT  14.208 72.373 42.024 72.661 ;
     RECT  13.584 72.661 42.024 72.851 ;
     RECT  14.208 72.851 42.024 72.949 ;
     RECT  14.208 72.949 42.264 73.36 ;
     RECT  42.048 73.36 42.264 73.379 ;
     RECT  35.088 73.36 35.112 73.387 ;
     RECT  37.536 73.36 37.56 73.387 ;
     RECT  38.592 73.36 38.616 73.387 ;
     RECT  39.744 73.36 39.768 73.387 ;
     RECT  42.048 73.379 42.072 73.387 ;
    LAYER M6 ;
     RECT  0 0.996 0.565 1.86 ;
     RECT  0 33.396 0.629 34.26 ;
     RECT  0.693 4.864 0.899 4.896 ;
     RECT  0 22.596 1.269 23.46 ;
     RECT  0.565 31.68 1.525 31.712 ;
     RECT  1.269 22.596 1.763 24.544 ;
     RECT  0.565 0.256 1.765 1.86 ;
     RECT  0 17.196 1.973 18.06 ;
     RECT  1.525 31.68 2.101 31.968 ;
     RECT  1.397 26.24 2.229 26.272 ;
     RECT  1.973 17.196 2.293 18.976 ;
     RECT  1.653 20.608 2.293 20.64 ;
     RECT  2.485 37.056 2.579 37.088 ;
     RECT  0 44.196 2.677 45.06 ;
     RECT  1.763 22.596 2.741 23.584 ;
     RECT  2.101 30.848 2.997 31.968 ;
     RECT  1.765 0.256 3.109 2.72 ;
     RECT  0 71.196 3.253 72.06 ;
     RECT  0 11.796 3.301 12.66 ;
     RECT  2.293 17.196 3.443 20.64 ;
     RECT  2.997 30.208 3.573 31.968 ;
     RECT  0.629 33.28 3.573 34.26 ;
     RECT  3.443 20.608 3.685 20.64 ;
     RECT  2.741 21.952 3.685 23.584 ;
     RECT  0 49.596 3.701 50.46 ;
     RECT  3.685 20.608 3.755 23.584 ;
     RECT  2.229 25.472 3.765 26.272 ;
     RECT  0 27.996 3.765 28.86 ;
     RECT  3.443 17.196 3.829 19.232 ;
     RECT  0 6.396 3.877 7.26 ;
     RECT  3.189 57.536 3.893 57.568 ;
     RECT  3.877 6.396 3.947 7.392 ;
     RECT  3.755 20.608 4.019 20.64 ;
     RECT  3.573 30.208 4.019 34.26 ;
     RECT  3.701 49.024 4.019 50.46 ;
     RECT  3.253 70.4 4.085 72.06 ;
     RECT  4.069 36.992 4.139 37.024 ;
     RECT  4.085 70.144 4.163 72.06 ;
     RECT  4.019 49.472 4.331 50.46 ;
     RECT  0 38.796 4.334 39.66 ;
     RECT  4.021 52.224 4.341 52.256 ;
     RECT  3.765 25.472 4.405 28.86 ;
     RECT  4.334 37.632 4.405 39.66 ;
     RECT  3.253 41.6 4.405 41.632 ;
     RECT  3.109 0.256 4.597 3.296 ;
     RECT  3.893 57.536 4.853 57.632 ;
     RECT  1.333 47.04 4.917 47.072 ;
     RECT  0 54.996 4.981 55.86 ;
     RECT  4.981 54.208 5.045 55.86 ;
     RECT  4.853 57.536 5.045 58.784 ;
     RECT  4.405 25.088 5.171 28.86 ;
     RECT  4.019 30.208 5.171 30.24 ;
     RECT  0 65.796 5.173 66.66 ;
     RECT  3.947 6.396 5.237 7.26 ;
     RECT  3.301 10.944 5.269 12.66 ;
     RECT  4.331 49.596 5.301 50.46 ;
     RECT  4.341 51.904 5.301 52.256 ;
     RECT  5.237 6.208 5.365 7.26 ;
     RECT  4.019 31.68 5.419 34.26 ;
     RECT  5.419 31.68 5.429 31.712 ;
     RECT  2.677 44.196 5.493 45.728 ;
     RECT  4.597 0.256 5.547 4.32 ;
     RECT  5.269 10.752 5.621 12.66 ;
     RECT  5.621 10.304 5.675 12.66 ;
     RECT  5.171 27.072 5.685 28.86 ;
     RECT  5.301 49.596 5.813 52.256 ;
     RECT  5.675 11.796 5.877 12.66 ;
     RECT  4.163 70.272 6.005 72.06 ;
     RECT  5.685 27.072 6.083 29.024 ;
     RECT  5.877 11.796 6.131 14.048 ;
     RECT  5.173 65.796 6.133 66.784 ;
     RECT  5.813 49.024 6.229 52.256 ;
     RECT  5.547 0.256 6.323 3.872 ;
     RECT  5.171 25.088 6.323 25.696 ;
     RECT  4.213 63.872 6.323 63.904 ;
     RECT  5.429 31.104 6.565 31.712 ;
     RECT  5.877 35.712 6.645 35.744 ;
     RECT  5.045 54.208 6.645 58.784 ;
     RECT  6.323 0.256 6.709 3.744 ;
     RECT  5.493 44.032 6.709 45.728 ;
     RECT  4.917 47.04 6.709 47.264 ;
     RECT  6.645 35.648 6.773 35.744 ;
     RECT  6.565 30.784 6.899 31.712 ;
     RECT  4.405 37.632 6.899 41.632 ;
     RECT  3.755 21.952 6.901 23.584 ;
     RECT  6.323 25.088 6.901 25.504 ;
     RECT  5.365 6.016 6.997 7.26 ;
     RECT  6.645 54.08 6.997 58.784 ;
     RECT  6.997 54.08 7.083 59.104 ;
     RECT  6.229 49.024 7.147 52.448 ;
     RECT  5.675 10.304 7.189 10.336 ;
     RECT  6.131 11.796 7.189 13.6 ;
     RECT  6.133 65.408 7.221 66.784 ;
     RECT  6.083 27.072 7.381 28.86 ;
     RECT  7.147 49.024 7.475 52.384 ;
     RECT  7.221 65.216 7.475 66.784 ;
     RECT  6.997 6.016 7.573 7.776 ;
     RECT  6.965 63.168 7.605 63.2 ;
     RECT  7.573 5.056 7.659 7.776 ;
     RECT  7.189 10.304 7.669 13.6 ;
     RECT  7.381 26.88 7.733 28.86 ;
     RECT  6.899 30.784 7.733 31.392 ;
     RECT  6.709 44.032 7.733 47.264 ;
     RECT  7.733 42.88 7.797 47.264 ;
     RECT  6.709 0.064 7.861 3.744 ;
     RECT  7.605 63.168 7.909 63.904 ;
     RECT  7.475 65.216 7.909 66.66 ;
     RECT  6.709 15.296 8.053 15.456 ;
     RECT  3.829 16.96 8.053 19.232 ;
     RECT  5.419 33.396 8.117 34.26 ;
     RECT  6.773 35.648 8.181 36.192 ;
     RECT  7.861 0.064 8.195 4.576 ;
     RECT  6.901 21.952 8.245 25.504 ;
     RECT  7.733 26.88 8.299 31.392 ;
     RECT  8.181 35.648 8.373 36.256 ;
     RECT  6.899 37.632 8.373 41.376 ;
     RECT  8.299 27.008 8.491 31.392 ;
     RECT  8.195 0.064 8.683 2.912 ;
     RECT  7.659 6.016 8.771 7.776 ;
     RECT  7.083 54.08 8.821 58.656 ;
     RECT  8.053 15.296 8.949 19.232 ;
     RECT  7.797 42.88 8.949 47.776 ;
     RECT  7.475 49.596 8.949 52.384 ;
     RECT  7.669 9.664 9.061 13.6 ;
     RECT  8.949 15.296 9.061 19.744 ;
     RECT  8.373 35.648 9.061 41.376 ;
     RECT  8.949 42.88 9.061 52.384 ;
     RECT  8.117 33.024 9.109 34.26 ;
     RECT  9.061 35.648 9.109 52.384 ;
     RECT  8.245 21.696 9.157 25.504 ;
     RECT  9.109 33.024 9.195 52.384 ;
     RECT  9.157 21.632 9.333 25.504 ;
     RECT  9.333 21.312 9.443 25.504 ;
     RECT  9.061 9.664 9.493 19.744 ;
     RECT  8.683 0.256 9.589 2.912 ;
     RECT  8.195 4.544 9.589 4.576 ;
     RECT  9.443 22.596 9.637 25.504 ;
     RECT  0 60.396 9.653 61.26 ;
     RECT  6.005 70.016 9.731 72.06 ;
     RECT  7.909 63.168 9.771 66.66 ;
     RECT  9.493 9.472 9.923 19.744 ;
     RECT  8.771 6.08 10.021 7.776 ;
     RECT  9.923 9.472 10.021 19.488 ;
     RECT  9.653 60.032 10.037 61.26 ;
     RECT  9.771 63.168 10.037 63.264 ;
     RECT  9.771 64.896 10.229 66.66 ;
     RECT  9.589 0.256 10.338 4.576 ;
     RECT  10.021 6.08 10.338 19.488 ;
     RECT  9.195 43.008 10.485 52.384 ;
     RECT  10.485 42.88 10.501 52.384 ;
     RECT  10.338 0.256 10.613 19.488 ;
     RECT  9.195 33.024 10.837 41.376 ;
     RECT  10.613 0.128 10.859 19.488 ;
     RECT  10.837 32.896 10.883 41.376 ;
     RECT  10.229 64.896 10.883 67.296 ;
     RECT  8.491 27.996 10.885 31.392 ;
     RECT  10.859 0.128 10.931 18.656 ;
     RECT  10.501 42.816 10.933 52.384 ;
     RECT  10.883 64.96 10.997 67.296 ;
     RECT  8.309 68.608 10.997 68.64 ;
     RECT  10.933 42.688 11.002 52.512 ;
     RECT  10.885 27.996 11.051 31.584 ;
     RECT  11.002 43.008 11.115 52.512 ;
     RECT  9.637 22.596 11.189 26.528 ;
     RECT  11.051 27.996 11.189 31.328 ;
     RECT  11.115 47.744 11.317 52.512 ;
     RECT  8.821 53.824 11.317 58.656 ;
     RECT  10.997 64.96 11.381 68.64 ;
     RECT  11.317 47.744 11.459 58.656 ;
     RECT  10.931 9.152 11.603 18.656 ;
     RECT  11.189 22.596 11.651 31.328 ;
     RECT  11.651 22.596 11.699 31.2 ;
     RECT  11.603 9.92 11.939 18.656 ;
     RECT  11.699 22.596 11.941 31.072 ;
     RECT  11.941 22.464 12.277 31.072 ;
     RECT  11.459 52.352 12.325 58.656 ;
     RECT  12.325 52.352 12.395 58.72 ;
     RECT  10.883 32.896 12.517 37.344 ;
     RECT  10.883 38.796 12.517 41.376 ;
     RECT  12.395 52.352 12.523 58.656 ;
     RECT  11.115 43.008 12.661 46.24 ;
     RECT  11.459 47.744 12.661 47.776 ;
     RECT  11.939 10.304 12.917 18.656 ;
     RECT  12.661 43.008 12.949 47.776 ;
     RECT  11.459 49.596 12.949 51.04 ;
     RECT  10.931 0.128 13.109 7.776 ;
     RECT  12.523 52.352 13.139 58.144 ;
     RECT  13.109 0.128 13.237 8.288 ;
     RECT  11.381 64.96 13.237 69.216 ;
     RECT  13.237 0.128 13.285 8.544 ;
     RECT  12.917 10.304 13.285 18.784 ;
     RECT  13.285 0.128 13.355 18.784 ;
     RECT  13.355 10.304 13.427 18.784 ;
     RECT  12.277 22.272 13.477 31.072 ;
     RECT  12.517 32.896 13.477 41.376 ;
     RECT  12.949 43.008 13.523 51.04 ;
     RECT  13.477 22.272 13.557 41.376 ;
     RECT  13.427 10.56 13.667 18.784 ;
     RECT  13.523 47.744 13.715 51.04 ;
     RECT  13.667 15.552 13.813 18.784 ;
     RECT  11.413 20.48 13.813 20.512 ;
     RECT  13.813 15.552 13.995 20.512 ;
     RECT  13.557 22.272 14.005 41.632 ;
     RECT  13.523 43.008 14.005 46.24 ;
     RECT  13.715 47.808 14.059 51.04 ;
     RECT  14.059 48.128 14.197 51.04 ;
     RECT  13.139 52.352 14.197 57.696 ;
     RECT  13.237 64.576 14.291 69.216 ;
     RECT  14.005 22.272 14.315 46.24 ;
     RECT  13.995 15.552 14.483 19.424 ;
     RECT  14.197 48.128 14.709 57.696 ;
     RECT  13.355 0.128 14.773 8.928 ;
     RECT  13.667 10.56 14.773 14.048 ;
     RECT  14.315 38.4 14.867 46.24 ;
     RECT  14.315 22.272 14.917 37.024 ;
     RECT  14.917 21.696 14.963 37.024 ;
     RECT  10.037 60.032 14.963 63.264 ;
     RECT  14.773 0.128 15.011 14.048 ;
     RECT  14.483 16 15.166 19.424 ;
     RECT  14.291 64.576 15.349 66.976 ;
     RECT  15.166 16 15.418 19.36 ;
     RECT  15.349 63.872 15.605 66.976 ;
     RECT  14.291 68.928 15.605 69.216 ;
     RECT  14.963 21.696 15.659 36.512 ;
     RECT  14.709 48.128 15.669 58.528 ;
     RECT  14.963 60.032 15.669 62.432 ;
     RECT  15.605 63.872 15.683 69.216 ;
     RECT  15.669 48.128 16.019 62.432 ;
     RECT  15.683 69.184 16.019 69.216 ;
     RECT  14.867 38.4 16.213 40.352 ;
     RECT  14.867 42.176 16.213 46.24 ;
     RECT  15.011 0.128 16.309 13.664 ;
     RECT  16.213 38.4 16.565 46.24 ;
     RECT  16.019 48.128 16.565 62.368 ;
     RECT  16.309 0.128 16.693 14.176 ;
     RECT  16.693 0.064 16.757 14.176 ;
     RECT  15.418 16 16.757 19.104 ;
     RECT  16.565 38.4 16.883 62.368 ;
     RECT  15.683 63.872 16.931 66.976 ;
     RECT  15.659 21.952 17.029 36.512 ;
     RECT  16.883 48.128 17.123 62.368 ;
     RECT  16.757 0.064 17.461 19.104 ;
     RECT  17.029 21.12 17.461 36.512 ;
     RECT  17.123 60.396 17.509 62.368 ;
     RECT  17.461 0.064 17.515 36.832 ;
     RECT  17.123 48.64 17.515 58.912 ;
     RECT  17.515 16.512 17.699 36.832 ;
     RECT  16.931 63.872 17.699 66.66 ;
     RECT  16.883 38.4 17.939 46.24 ;
     RECT  17.699 16.704 18.091 36.832 ;
     RECT  17.509 60.396 18.101 62.432 ;
     RECT  17.515 48.64 18.613 55.86 ;
     RECT  17.939 38.4 18.709 45.728 ;
     RECT  18.101 60.396 18.851 62.752 ;
     RECT  17.699 64.128 18.851 66.66 ;
     RECT  18.709 38.336 18.949 45.728 ;
     RECT  18.091 16.832 19.427 36.832 ;
     RECT  18.613 47.936 19.427 55.86 ;
     RECT  19.427 16.832 19.445 18.72 ;
     RECT  18.949 38.272 19.627 45.728 ;
     RECT  19.427 48.448 19.637 55.86 ;
     RECT  17.515 57.408 19.637 58.912 ;
     RECT  19.445 16.384 19.701 18.72 ;
     RECT  19.637 48.448 19.765 58.912 ;
     RECT  18.851 60.396 19.765 62.368 ;
     RECT  19.765 48.448 19.907 62.368 ;
     RECT  19.907 48.576 20.003 62.368 ;
     RECT  19.427 21.12 20.195 36.832 ;
     RECT  19.627 38.336 20.195 45.728 ;
     RECT  17.515 0.064 20.213 14.944 ;
     RECT  19.701 16.256 20.213 18.72 ;
     RECT  20.213 0.064 20.339 18.72 ;
     RECT  20.339 0.064 20.715 3.936 ;
     RECT  20.195 27.996 21.155 36.832 ;
     RECT  20.853 47.168 21.301 47.2 ;
     RECT  21.155 32.384 21.637 36.832 ;
     RECT  20.195 38.528 21.637 45.728 ;
     RECT  20.003 48.64 21.675 62.368 ;
     RECT  21.637 32.384 21.683 45.728 ;
     RECT  20.195 21.12 21.685 26.656 ;
     RECT  21.155 27.996 21.685 29.024 ;
     RECT  21.733 69.312 21.803 69.344 ;
     RECT  21.685 21.12 22.213 29.024 ;
     RECT  21.683 32.384 22.259 41.184 ;
     RECT  21.683 42.752 22.259 45.728 ;
     RECT  20.339 5.376 22.261 18.72 ;
     RECT  22.259 32.384 22.307 41.056 ;
     RECT  21.675 48.896 22.835 62.368 ;
     RECT  22.835 54.996 23.01 62.368 ;
     RECT  23.01 54.996 23.083 63.2 ;
     RECT  22.835 52.16 23.123 53.6 ;
     RECT  22.213 20.608 23.211 29.024 ;
     RECT  21.155 30.848 23.211 31.072 ;
     RECT  21.301 47.168 23.219 47.264 ;
     RECT  22.307 36.224 23.339 41.056 ;
     RECT  23.211 30.848 23.363 30.88 ;
     RECT  23.211 20.608 23.411 24.224 ;
     RECT  18.851 64.576 23.411 66.66 ;
     RECT  23.211 25.664 23.422 28.86 ;
     RECT  22.259 43.008 23.669 45.728 ;
     RECT  22.835 48.896 23.747 50.784 ;
     RECT  20.715 0.064 23.893 3.808 ;
     RECT  23.219 47.168 23.987 47.2 ;
     RECT  23.411 64.832 24.117 66.66 ;
     RECT  23.893 0.064 24.171 3.872 ;
     RECT  23.669 42.112 24.171 45.728 ;
     RECT  22.307 32.384 24.494 34.26 ;
     RECT  23.339 36.224 24.494 40.8 ;
     RECT  24.171 0.128 24.501 3.872 ;
     RECT  22.261 5.184 24.501 18.72 ;
     RECT  24.117 64.832 24.563 67.296 ;
     RECT  23.123 52.16 24.693 52.768 ;
     RECT  24.501 0.128 24.738 18.72 ;
     RECT  24.738 0.128 24.811 18.912 ;
     RECT  24.811 0.128 24.851 18.72 ;
     RECT  24.171 43.008 24.878 45.728 ;
     RECT  24.053 47.04 24.878 47.072 ;
     RECT  24.494 32.384 24.939 40.8 ;
     RECT  24.878 43.008 24.947 47.072 ;
     RECT  23.083 54.996 25.045 62.368 ;
     RECT  25.045 54.996 25.195 63.328 ;
     RECT  24.693 52.032 25.205 52.768 ;
     RECT  25.195 54.996 25.205 55.968 ;
     RECT  23.411 20.608 25.333 24.096 ;
     RECT  25.195 57.472 25.333 63.328 ;
     RECT  23.747 48.896 25.525 50.592 ;
     RECT  25.205 52.032 25.525 55.968 ;
     RECT  24.939 32.384 25.621 35.296 ;
     RECT  23.422 26.24 25.669 28.86 ;
     RECT  24.947 43.008 25.715 45.728 ;
     RECT  25.525 48.896 25.715 55.968 ;
     RECT  25.333 57.472 25.715 64.288 ;
     RECT  25.621 31.232 25.899 35.296 ;
     RECT  25.669 26.24 25.909 29.152 ;
     RECT  24.851 6.272 26.155 18.72 ;
     RECT  26.155 6.272 26.245 15.712 ;
     RECT  25.715 57.6 26.341 64.288 ;
     RECT  24.563 65.796 26.341 67.296 ;
     RECT  24.851 0.128 26.357 4.576 ;
     RECT  26.357 0.064 26.389 4.576 ;
     RECT  26.245 6.208 26.389 15.712 ;
     RECT  26.341 57.6 26.411 67.296 ;
     RECT  25.715 43.328 26.437 45.728 ;
     RECT  24.947 47.04 26.437 47.072 ;
     RECT  25.909 26.24 26.725 29.6 ;
     RECT  25.899 31.232 26.725 34.912 ;
     RECT  26.437 43.328 26.725 47.072 ;
     RECT  25.333 20.032 26.819 24.096 ;
     RECT  26.725 26.24 26.819 34.912 ;
     RECT  24.939 36.608 26.859 40.8 ;
     RECT  26.725 43.328 26.938 47.136 ;
     RECT  26.819 26.24 27.051 31.264 ;
     RECT  26.389 0.064 27.059 15.712 ;
     RECT  26.155 17.196 27.059 18.72 ;
     RECT  27.059 5.952 27.107 15.712 ;
     RECT  26.859 38.208 27.13 40.8 ;
     RECT  26.938 44.196 27.307 47.136 ;
     RECT  25.715 52.032 27.381 55.968 ;
     RECT  26.411 57.6 27.381 64.288 ;
     RECT  27.051 26.432 27.435 31.264 ;
     RECT  26.859 36.608 27.435 36.896 ;
     RECT  9.731 71.196 27.589 72.06 ;
     RECT  26.037 73.344 27.589 73.376 ;
     RECT  27.435 36.608 27.683 36.768 ;
     RECT  27.381 52.032 27.683 64.288 ;
     RECT  27.059 17.196 27.701 18.656 ;
     RECT  27.107 15.04 27.733 15.712 ;
     RECT  27.701 17.088 27.733 18.656 ;
     RECT  27.573 42.688 27.755 42.72 ;
     RECT  27.589 71.196 27.827 73.376 ;
     RECT  26.819 32.768 27.971 34.912 ;
     RECT  25.715 48.896 27.971 50.46 ;
     RECT  27.683 52.032 27.971 52.256 ;
     RECT  27.307 46.784 28.259 47.136 ;
     RECT  27.307 44.196 28.341 45.06 ;
     RECT  27.435 26.432 28.405 31.2 ;
     RECT  27.733 15.04 28.453 18.656 ;
     RECT  28.405 25.92 28.453 31.2 ;
     RECT  27.13 38.4 28.453 40.8 ;
     RECT  28.453 25.536 28.523 31.2 ;
     RECT  26.411 65.796 28.526 67.296 ;
     RECT  28.526 65.796 28.595 67.36 ;
     RECT  27.107 5.952 28.693 13.664 ;
     RECT  28.453 15.04 28.693 18.784 ;
     RECT  27.971 32.768 28.883 34.26 ;
     RECT  26.819 20.608 28.981 24.096 ;
     RECT  28.453 38.208 28.981 40.8 ;
     RECT  28.693 5.952 29.029 18.784 ;
     RECT  28.981 20.544 29.029 24.096 ;
     RECT  28.981 38.208 29.075 41.056 ;
     RECT  27.059 0.064 29.109 4.576 ;
     RECT  29.029 5.952 29.109 24.096 ;
     RECT  28.595 65.796 29.109 67.296 ;
     RECT  29.109 65.6 29.123 67.296 ;
     RECT  27.683 54.016 29.301 56.8 ;
     RECT  27.683 58.176 29.301 64.288 ;
     RECT  27.971 49.28 29.365 50.46 ;
     RECT  27.971 52.096 29.365 52.256 ;
     RECT  29.301 54.016 29.699 64.288 ;
     RECT  29.075 38.208 29.747 40.8 ;
     RECT  29.747 38.208 29.749 40.032 ;
     RECT  28.341 43.328 29.813 45.06 ;
     RECT  28.259 46.784 29.813 47.072 ;
     RECT  29.749 38.144 29.843 40.032 ;
     RECT  29.843 38.656 29.931 40.032 ;
     RECT  29.269 36.224 30.005 36.256 ;
     RECT  29.109 0.064 30.059 24.096 ;
     RECT  30.133 68.416 30.181 68.448 ;
     RECT  28.883 33.152 30.197 34.26 ;
     RECT  29.813 43.328 30.261 47.072 ;
     RECT  29.365 49.28 30.261 52.256 ;
     RECT  30.261 43.328 30.275 52.256 ;
     RECT  30.181 68.416 30.275 68.64 ;
     RECT  30.059 0.192 30.515 24.096 ;
     RECT  30.275 43.456 30.517 52.256 ;
     RECT  28.523 25.92 30.805 31.2 ;
     RECT  30.515 8.896 30.83 24.096 ;
     RECT  30.805 25.6 30.83 31.2 ;
     RECT  27.827 71.196 30.853 72.06 ;
     RECT  27.827 73.344 30.853 73.376 ;
     RECT  30.853 71.196 30.955 73.376 ;
     RECT  30.005 36.224 31.157 36.512 ;
     RECT  30.515 0.192 31.211 7.392 ;
     RECT  30.83 8.896 31.285 31.2 ;
     RECT  30.197 32.832 31.285 34.26 ;
     RECT  30.517 43.456 31.379 52.768 ;
     RECT  29.931 38.656 31.619 39.968 ;
     RECT  31.285 8.896 31.621 34.26 ;
     RECT  31.621 8.896 31.765 34.4 ;
     RECT  31.157 36.032 31.765 36.512 ;
     RECT  31.765 8.896 31.851 36.512 ;
     RECT  31.211 0.832 32.245 7.392 ;
     RECT  31.851 8.896 32.245 30.304 ;
     RECT  32.245 0.832 32.299 30.304 ;
     RECT  31.851 36.032 32.309 36.512 ;
     RECT  31.619 38.656 32.309 39.66 ;
     RECT  29.699 54.08 32.437 64.288 ;
     RECT  29.123 65.6 32.437 66.66 ;
     RECT  32.299 0.832 32.579 8.032 ;
     RECT  32.299 9.536 32.579 30.304 ;
     RECT  32.533 41.856 32.811 41.888 ;
     RECT  32.309 36.032 33.003 39.66 ;
     RECT  32.579 0.832 33.059 7.456 ;
     RECT  30.955 71.196 33.077 72.06 ;
     RECT  30.955 73.344 33.077 73.376 ;
     RECT  33.003 37.632 33.107 39.66 ;
     RECT  33.077 71.196 33.131 73.376 ;
     RECT  32.579 9.536 33.539 23.46 ;
     RECT  33.539 11.072 33.683 23.46 ;
     RECT  33.107 38.144 33.829 39.66 ;
     RECT  33.829 38.144 33.877 40.352 ;
     RECT  32.579 25.152 33.909 30.304 ;
     RECT  31.851 31.744 33.909 34.26 ;
     RECT  31.379 44.196 33.909 52.768 ;
     RECT  32.437 54.08 33.909 66.66 ;
     RECT  33.539 9.536 33.963 9.568 ;
     RECT  33.877 38.144 33.963 41.568 ;
     RECT  33.683 19.904 34.027 23.46 ;
     RECT  33.909 25.152 34.091 34.26 ;
     RECT  33.059 0.832 34.219 4.832 ;
     RECT  33.683 11.072 34.259 18.06 ;
     RECT  34.091 31.616 34.259 34.26 ;
     RECT  33.909 42.944 34.259 66.66 ;
     RECT  34.091 25.152 34.347 30.304 ;
     RECT  34.219 4.672 34.485 4.832 ;
     RECT  33.059 6.396 34.485 7.456 ;
     RECT  34.485 4.672 34.558 7.456 ;
     RECT  34.219 0.832 34.731 3.36 ;
     RECT  33.963 38.144 34.795 41.056 ;
     RECT  34.259 11.072 34.835 15.584 ;
     RECT  34.259 42.944 34.883 53.088 ;
     RECT  34.558 4.672 34.979 4.832 ;
     RECT  34.883 42.944 35.061 52.768 ;
     RECT  34.835 11.072 35.077 12.66 ;
     RECT  33.131 71.196 35.077 73.248 ;
     RECT  34.259 54.656 35.123 61.536 ;
     RECT  35.077 71.196 35.179 73.376 ;
     RECT  34.259 33.216 35.189 34.26 ;
     RECT  33.003 36.032 35.189 36.192 ;
     RECT  34.731 0.996 35.307 3.36 ;
     RECT  34.835 14.208 35.363 15.584 ;
     RECT  34.795 38.144 35.363 40.544 ;
     RECT  35.061 42.88 35.363 52.768 ;
     RECT  35.189 33.216 35.435 36.192 ;
     RECT  34.259 63.232 35.509 66.66 ;
     RECT  35.363 14.208 35.563 14.24 ;
     RECT  35.307 3.264 35.627 3.36 ;
     RECT  35.077 10.816 35.682 12.66 ;
     RECT  34.347 27.996 35.691 30.304 ;
     RECT  35.682 10.24 35.755 12.66 ;
     RECT  34.259 31.616 35.829 31.648 ;
     RECT  35.435 33.216 35.829 35.424 ;
     RECT  34.027 20.48 35.843 23.46 ;
     RECT  35.509 63.232 35.874 66.784 ;
     RECT  35.829 31.616 35.883 35.424 ;
     RECT  35.883 31.616 35.939 35.36 ;
     RECT  35.363 43.072 35.939 52.768 ;
     RECT  35.874 63.232 35.939 66.848 ;
     RECT  35.939 63.232 35.941 64.288 ;
     RECT  35.939 65.6 35.947 66.848 ;
     RECT  35.627 3.328 36.021 3.36 ;
     RECT  34.979 4.672 36.021 4.704 ;
     RECT  35.941 62.656 36.075 64.288 ;
     RECT  35.947 65.6 36.139 66.784 ;
     RECT  35.939 31.616 36.181 34.976 ;
     RECT  36.133 9.088 36.203 9.12 ;
     RECT  36.181 31.552 36.459 34.976 ;
     RECT  35.123 54.656 36.467 61.26 ;
     RECT  36.021 3.328 36.515 4.704 ;
     RECT  35.363 38.796 36.515 40.544 ;
     RECT  35.939 43.072 36.515 47.008 ;
     RECT  35.939 48.576 36.515 52.768 ;
     RECT  34.347 25.152 36.517 26.464 ;
     RECT  35.691 27.996 36.517 30.176 ;
     RECT  36.517 25.152 36.587 30.176 ;
     RECT  36.467 57.536 36.59 61.26 ;
     RECT  36.59 57.536 36.659 62.176 ;
     RECT  36.515 43.264 36.67 47.008 ;
     RECT  36.459 31.616 36.779 34.976 ;
     RECT  36.853 36.992 36.922 37.024 ;
     RECT  35.843 22.464 37.026 23.46 ;
     RECT  36.587 25.152 37.026 26.464 ;
     RECT  35.755 10.816 37.035 12.66 ;
     RECT  36.949 15.424 37.035 15.456 ;
     RECT  36.779 31.616 37.091 31.648 ;
     RECT  36.779 33.396 37.091 34.976 ;
     RECT  36.659 57.536 37.091 61.26 ;
     RECT  37.026 22.464 37.099 26.464 ;
     RECT  35.843 20.48 37.285 20.512 ;
     RECT  37.285 20.48 37.355 20.768 ;
     RECT  36.587 27.996 37.427 30.176 ;
     RECT  36.075 63.488 37.477 64.288 ;
     RECT  37.477 63.232 37.493 64.288 ;
     RECT  36.139 65.796 37.493 66.784 ;
     RECT  35.179 71.196 37.525 73.248 ;
     RECT  34.558 6.396 37.571 7.456 ;
     RECT  37.301 36.672 37.619 36.96 ;
     RECT  37.035 10.944 37.667 12.66 ;
     RECT  36.515 51.904 37.715 52.768 ;
     RECT  35.307 0.996 37.717 1.86 ;
     RECT  36.515 3.328 37.717 3.424 ;
     RECT  37.493 63.232 37.749 66.784 ;
     RECT  37.717 0.996 37.803 3.424 ;
     RECT  37.099 25.152 37.859 26.464 ;
     RECT  36.67 43.84 37.863 47.008 ;
     RECT  36.515 48.576 37.863 50.592 ;
     RECT  37.091 57.536 37.931 57.632 ;
     RECT  37.803 0.996 38.16 1.86 ;
     RECT  37.571 6.396 38.16 7.26 ;
     RECT  34.259 17.196 38.16 18.06 ;
     RECT  37.427 27.996 38.16 29.536 ;
     RECT  37.091 33.396 38.16 34.26 ;
     RECT  36.515 38.796 38.16 39.66 ;
     RECT  37.863 43.84 38.16 50.592 ;
     RECT  37.749 63.232 38.16 67.296 ;
     RECT  37.525 71.196 38.16 73.376 ;
     RECT  37.803 3.264 38.187 3.424 ;
     RECT  38.16 63.232 38.261 64.928 ;
     RECT  38.16 50.172 38.379 50.592 ;
     RECT  37.667 11.328 38.483 12.66 ;
     RECT  38.16 28.416 38.483 29.536 ;
     RECT  38.16 43.84 38.483 48.864 ;
     RECT  37.091 59.456 38.483 61.26 ;
     RECT  38.261 62.976 38.483 64.928 ;
     RECT  38.16 66.372 38.483 67.296 ;
     RECT  38.483 47.296 38.571 48.864 ;
     RECT  38.571 47.744 38.675 48.864 ;
     RECT  38.187 3.264 38.723 3.36 ;
     RECT  37.715 52.352 38.773 52.768 ;
     RECT  38.517 19.968 38.819 20 ;
     RECT  37.931 57.536 38.819 57.568 ;
     RECT  38.16 1.572 38.944 1.86 ;
     RECT  38.16 6.972 38.944 7.26 ;
     RECT  38.483 12.372 38.944 12.66 ;
     RECT  38.16 17.772 38.944 18.06 ;
     RECT  38.16 33.972 38.944 34.26 ;
     RECT  38.16 39.372 38.944 39.66 ;
     RECT  38.483 44.772 38.944 45.06 ;
     RECT  38.379 50.172 38.944 50.46 ;
     RECT  38.483 59.84 38.944 61.26 ;
     RECT  38.483 66.372 38.944 66.66 ;
     RECT  38.16 71.772 38.944 73.376 ;
     RECT  30.275 68.608 39.029 68.64 ;
     RECT  38.723 3.328 39.083 3.36 ;
     RECT  38.483 63.872 39.083 64.928 ;
     RECT  36.467 54.656 39.093 55.86 ;
     RECT  37.619 36.928 39.211 36.96 ;
     RECT  39.093 54.528 39.339 55.968 ;
     RECT  38.675 47.744 39.395 48.608 ;
     RECT  39.339 54.848 39.395 55.968 ;
     RECT  38.944 59.84 39.395 60.256 ;
     RECT  39.083 63.872 39.395 63.904 ;
     RECT  39.395 54.848 39.443 54.88 ;
     RECT  37.099 22.464 39.589 23.46 ;
     RECT  39.589 22.464 39.659 23.776 ;
     RECT  38.483 28.544 39.659 29.536 ;
     RECT  39.301 31.936 39.659 31.968 ;
     RECT  39.659 28.992 39.681 29.536 ;
     RECT  38.944 72.96 39.802 73.376 ;
     RECT  37.859 26.432 39.923 26.464 ;
     RECT  39.395 47.744 39.923 47.776 ;
     RECT  38.773 52.352 39.923 52.896 ;
     RECT  39.029 68.544 39.971 68.64 ;
     RECT  39.923 52.352 40.499 52.384 ;
     RECT  39.395 60.224 40.499 60.256 ;
     RECT  39.971 68.608 40.499 68.64 ;
     RECT  39.681 29.504 41.075 29.536 ;
     RECT  39.659 22.464 41.651 22.496 ;
     RECT  39.802 72.96 42.037 73.248 ;
     RECT  42.037 72.96 42.106 73.376 ;
     RECT  42.106 72.96 42.275 72.992 ;
    LAYER M7 ;
     RECT  30.016 0.053 30.048 0.117 ;
     RECT  19.776 0.117 19.808 0.181 ;
     RECT  24.128 0.053 24.16 0.181 ;
     RECT  29.76 0.117 30.048 0.181 ;
     RECT  8.64 0.053 8.672 0.245 ;
     RECT  10.624 0.117 10.656 0.245 ;
     RECT  12.288 0.117 12.832 0.245 ;
     RECT  16.704 0.053 17.056 0.245 ;
     RECT  19.008 0.181 19.808 0.245 ;
     RECT  21.312 0.053 22.176 0.245 ;
     RECT  23.936 0.181 24.288 0.245 ;
     RECT  26.368 0.053 27.616 0.245 ;
     RECT  6.72 0.053 6.752 0.309 ;
     RECT  8.64 0.245 13.664 0.309 ;
     RECT  16.704 0.245 22.176 0.309 ;
     RECT  23.936 0.245 24.416 0.309 ;
     RECT  6.72 0.309 14.112 0.373 ;
     RECT  15.424 0.309 22.304 0.373 ;
     RECT  23.616 0.309 24.416 0.373 ;
     RECT  25.984 0.245 27.616 0.373 ;
     RECT  29.76 0.181 31.2 0.373 ;
     RECT  0.576 0.245 4.512 0.501 ;
     RECT  6.72 0.373 24.416 0.501 ;
     RECT  0.576 0.501 24.416 0.565 ;
     RECT  0.576 0.565 24.544 0.693 ;
     RECT  25.984 0.373 31.2 0.693 ;
     RECT  33.256 0.531 33.544 0.821 ;
     RECT  0.576 0.693 31.2 1.397 ;
     RECT  33.256 0.821 34.72 1.397 ;
     RECT  0.576 1.397 31.904 2.421 ;
     RECT  33.256 1.397 35.68 2.421 ;
     RECT  38.656 0.531 38.944 2.805 ;
     RECT  37.76 2.805 38.944 3.317 ;
     RECT  0.576 2.421 35.68 3.381 ;
     RECT  37.76 3.317 39.072 3.381 ;
     RECT  0.576 3.381 39.072 23.733 ;
     RECT  0.576 23.733 39.648 31.723 ;
     RECT  0.64 31.723 39.648 31.979 ;
     RECT  0.64 31.979 38.944 33.323 ;
     RECT  0.704 33.323 38.944 36.917 ;
     RECT  0.704 36.917 39.2 37.099 ;
     RECT  0.704 37.099 1.376 39.211 ;
     RECT  2.688 37.099 39.2 45.739 ;
     RECT  0.856 39.211 1.376 47.083 ;
     RECT  3.2 45.739 39.2 52.725 ;
     RECT  3.2 52.725 39.328 54.699 ;
     RECT  3.2 54.699 39.136 55.979 ;
     RECT  3.2 55.979 38.944 56.491 ;
     RECT  3.2 56.491 22.744 57.579 ;
     RECT  3.904 57.579 22.744 57.643 ;
     RECT  4.096 57.643 22.744 58.677 ;
     RECT  24.128 56.491 38.944 58.677 ;
     RECT  4.096 58.677 38.944 59.499 ;
     RECT  4.096 59.499 31.008 61.867 ;
     RECT  17.056 61.867 31.008 62.187 ;
     RECT  32.448 59.499 38.944 62.581 ;
     RECT  17.056 62.187 18.144 62.763 ;
     RECT  19.456 62.187 30.176 63.211 ;
     RECT  32.128 62.581 38.944 63.915 ;
     RECT  17.056 62.763 17.568 64.171 ;
     RECT  24.128 63.211 30.176 64.299 ;
     RECT  32.448 63.915 38.944 64.363 ;
     RECT  19.456 63.211 22.744 64.619 ;
     RECT  35.52 64.363 38.944 64.885 ;
     RECT  4.096 61.867 15.648 65.013 ;
     RECT  17.056 64.171 17.344 65.013 ;
     RECT  4.096 65.013 17.344 65.451 ;
     RECT  26.048 64.299 30.176 65.579 ;
     RECT  32.448 64.363 33.544 65.579 ;
     RECT  4.096 65.451 11.944 66.219 ;
     RECT  20.352 64.619 22.744 66.219 ;
     RECT  27.456 65.579 30.176 66.219 ;
     RECT  27.856 66.219 30.176 66.283 ;
     RECT  4.096 66.219 8.352 66.795 ;
     RECT  13.504 65.451 17.344 66.795 ;
     RECT  35.52 64.885 39.072 66.795 ;
     RECT  14.464 66.795 15.648 66.859 ;
     RECT  35.904 66.795 39.072 66.859 ;
     RECT  10.24 66.219 11.944 67.307 ;
     RECT  24.128 64.299 24.16 67.307 ;
     RECT  36.864 66.859 39.072 67.307 ;
     RECT  27.856 66.283 28.576 67.371 ;
     RECT  11.008 67.307 11.944 67.883 ;
     RECT  30.144 66.283 30.176 68.459 ;
     RECT  38.656 67.307 39.072 68.587 ;
     RECT  6.016 66.795 8.352 68.651 ;
     RECT  15.616 66.859 15.648 68.971 ;
     RECT  11.392 67.883 11.944 69.227 ;
     RECT  21.76 66.219 22.744 69.355 ;
     RECT  6.016 68.651 7.328 70.059 ;
     RECT  4.096 66.795 4.32 70.187 ;
     RECT  6.256 70.059 7.328 70.187 ;
     RECT  4.288 70.187 4.32 70.315 ;
     RECT  6.256 70.187 7.072 70.443 ;
     RECT  0.856 47.083 1.144 72.639 ;
     RECT  6.256 70.443 6.544 72.639 ;
     RECT  11.656 69.227 11.944 72.639 ;
     RECT  17.056 66.795 17.344 72.639 ;
     RECT  22.456 69.355 22.744 72.639 ;
     RECT  27.856 67.371 28.144 72.639 ;
     RECT  33.256 65.579 33.544 72.639 ;
     RECT  36.864 67.307 36.896 72.821 ;
     RECT  38.656 68.587 38.944 72.949 ;
     RECT  36.864 72.821 37.088 73.003 ;
     RECT  30.912 72.885 30.944 73.067 ;
     RECT  38.592 72.949 38.944 73.077 ;
     RECT  26.048 65.579 26.08 73.387 ;
     RECT  33.088 73.205 33.12 73.387 ;
     RECT  35.136 73.077 35.168 73.387 ;
     RECT  37.568 73.077 39.776 73.387 ;
     RECT  42.048 73.205 42.08 73.387 ;
  END
END hfd_stn_r22
END LIBRARY
